VERSION 5.8 ;
BUSBITCHARS "[]" ;
DIVIDERCHAR "/" ;
UNITS
    DATABASE MICRONS 1000 ;
END UNITS

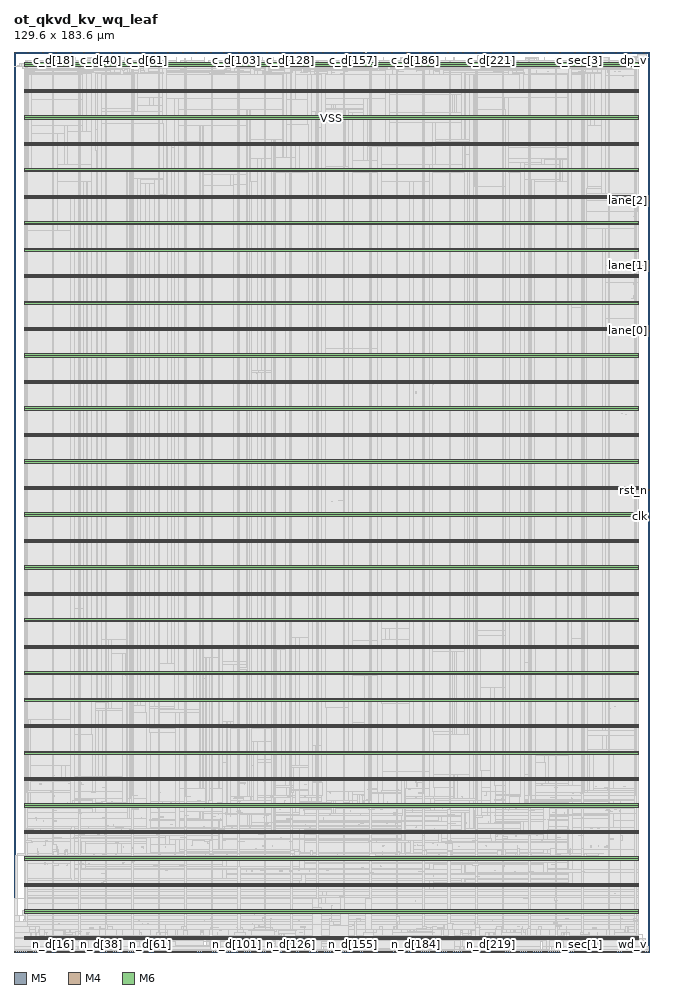
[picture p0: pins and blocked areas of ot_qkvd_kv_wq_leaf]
MACRO ot_qkvd_kv_wq_leaf
  FOREIGN ot_qkvd_kv_wq_leaf 0 0 ;
  CLASS BLOCK ;
  SIZE 129.6 BY 183.6 ;
  PIN c_d[0]
    DIRECTION INPUT ;
    USE SIGNAL ;
    PORT
      LAYER M5 ;
        RECT  0.192 183.516 0.216 183.6 ;
    END
  END c_d[0]
  PIN c_d[100]
    DIRECTION INPUT ;
    USE SIGNAL ;
    PORT
      LAYER M5 ;
        RECT  44.16 183.516 44.184 183.6 ;
    END
  END c_d[100]
  PIN c_d[101]
    DIRECTION INPUT ;
    USE SIGNAL ;
    PORT
      LAYER M5 ;
        RECT  44.592 183.516 44.616 183.6 ;
    END
  END c_d[101]
  PIN c_d[102]
    DIRECTION INPUT ;
    USE SIGNAL ;
    PORT
      LAYER M5 ;
        RECT  45.024 183.516 45.048 183.6 ;
    END
  END c_d[102]
  PIN c_d[103]
    DIRECTION INPUT ;
    USE SIGNAL ;
    PORT
      LAYER M5 ;
        RECT  45.456 183.516 45.48 183.6 ;
    END
  END c_d[103]
  PIN c_d[104]
    DIRECTION INPUT ;
    USE SIGNAL ;
    PORT
      LAYER M5 ;
        RECT  45.888 183.516 45.912 183.6 ;
    END
  END c_d[104]
  PIN c_d[105]
    DIRECTION INPUT ;
    USE SIGNAL ;
    PORT
      LAYER M5 ;
        RECT  46.32 183.516 46.344 183.6 ;
    END
  END c_d[105]
  PIN c_d[106]
    DIRECTION INPUT ;
    USE SIGNAL ;
    PORT
      LAYER M5 ;
        RECT  46.8 183.516 46.824 183.6 ;
    END
  END c_d[106]
  PIN c_d[107]
    DIRECTION INPUT ;
    USE SIGNAL ;
    PORT
      LAYER M5 ;
        RECT  47.232 183.516 47.256 183.6 ;
    END
  END c_d[107]
  PIN c_d[108]
    DIRECTION INPUT ;
    USE SIGNAL ;
    PORT
      LAYER M5 ;
        RECT  47.664 183.516 47.688 183.6 ;
    END
  END c_d[108]
  PIN c_d[109]
    DIRECTION INPUT ;
    USE SIGNAL ;
    PORT
      LAYER M5 ;
        RECT  48.096 183.516 48.12 183.6 ;
    END
  END c_d[109]
  PIN c_d[10]
    DIRECTION INPUT ;
    USE SIGNAL ;
    PORT
      LAYER M5 ;
        RECT  4.608 183.516 4.632 183.6 ;
    END
  END c_d[10]
  PIN c_d[110]
    DIRECTION INPUT ;
    USE SIGNAL ;
    PORT
      LAYER M5 ;
        RECT  48.528 183.516 48.552 183.6 ;
    END
  END c_d[110]
  PIN c_d[111]
    DIRECTION INPUT ;
    USE SIGNAL ;
    PORT
      LAYER M5 ;
        RECT  48.96 183.516 48.984 183.6 ;
    END
  END c_d[111]
  PIN c_d[112]
    DIRECTION INPUT ;
    USE SIGNAL ;
    PORT
      LAYER M5 ;
        RECT  49.392 183.516 49.416 183.6 ;
    END
  END c_d[112]
  PIN c_d[113]
    DIRECTION INPUT ;
    USE SIGNAL ;
    PORT
      LAYER M5 ;
        RECT  49.872 183.516 49.896 183.6 ;
    END
  END c_d[113]
  PIN c_d[114]
    DIRECTION INPUT ;
    USE SIGNAL ;
    PORT
      LAYER M5 ;
        RECT  50.304 183.516 50.328 183.6 ;
    END
  END c_d[114]
  PIN c_d[115]
    DIRECTION INPUT ;
    USE SIGNAL ;
    PORT
      LAYER M5 ;
        RECT  50.736 183.516 50.76 183.6 ;
    END
  END c_d[115]
  PIN c_d[116]
    DIRECTION INPUT ;
    USE SIGNAL ;
    PORT
      LAYER M5 ;
        RECT  51.168 183.516 51.192 183.6 ;
    END
  END c_d[116]
  PIN c_d[117]
    DIRECTION INPUT ;
    USE SIGNAL ;
    PORT
      LAYER M5 ;
        RECT  51.6 183.516 51.624 183.6 ;
    END
  END c_d[117]
  PIN c_d[118]
    DIRECTION INPUT ;
    USE SIGNAL ;
    PORT
      LAYER M5 ;
        RECT  52.032 183.516 52.056 183.6 ;
    END
  END c_d[118]
  PIN c_d[119]
    DIRECTION INPUT ;
    USE SIGNAL ;
    PORT
      LAYER M5 ;
        RECT  52.464 183.516 52.488 183.6 ;
    END
  END c_d[119]
  PIN c_d[11]
    DIRECTION INPUT ;
    USE SIGNAL ;
    PORT
      LAYER M5 ;
        RECT  5.04 183.516 5.064 183.6 ;
    END
  END c_d[11]
  PIN c_d[120]
    DIRECTION INPUT ;
    USE SIGNAL ;
    PORT
      LAYER M5 ;
        RECT  52.944 183.516 52.968 183.6 ;
    END
  END c_d[120]
  PIN c_d[121]
    DIRECTION INPUT ;
    USE SIGNAL ;
    PORT
      LAYER M5 ;
        RECT  53.376 183.516 53.4 183.6 ;
    END
  END c_d[121]
  PIN c_d[122]
    DIRECTION INPUT ;
    USE SIGNAL ;
    PORT
      LAYER M5 ;
        RECT  53.808 183.516 53.832 183.6 ;
    END
  END c_d[122]
  PIN c_d[123]
    DIRECTION INPUT ;
    USE SIGNAL ;
    PORT
      LAYER M5 ;
        RECT  54.24 183.516 54.264 183.6 ;
    END
  END c_d[123]
  PIN c_d[124]
    DIRECTION INPUT ;
    USE SIGNAL ;
    PORT
      LAYER M5 ;
        RECT  54.672 183.516 54.696 183.6 ;
    END
  END c_d[124]
  PIN c_d[125]
    DIRECTION INPUT ;
    USE SIGNAL ;
    PORT
      LAYER M5 ;
        RECT  55.104 183.516 55.128 183.6 ;
    END
  END c_d[125]
  PIN c_d[126]
    DIRECTION INPUT ;
    USE SIGNAL ;
    PORT
      LAYER M5 ;
        RECT  55.584 183.516 55.608 183.6 ;
    END
  END c_d[126]
  PIN c_d[127]
    DIRECTION INPUT ;
    USE SIGNAL ;
    PORT
      LAYER M5 ;
        RECT  56.016 183.516 56.04 183.6 ;
    END
  END c_d[127]
  PIN c_d[128]
    DIRECTION INPUT ;
    USE SIGNAL ;
    PORT
      LAYER M5 ;
        RECT  56.448 183.516 56.472 183.6 ;
    END
  END c_d[128]
  PIN c_d[129]
    DIRECTION INPUT ;
    USE SIGNAL ;
    PORT
      LAYER M5 ;
        RECT  56.88 183.516 56.904 183.6 ;
    END
  END c_d[129]
  PIN c_d[12]
    DIRECTION INPUT ;
    USE SIGNAL ;
    PORT
      LAYER M5 ;
        RECT  5.472 183.516 5.496 183.6 ;
    END
  END c_d[12]
  PIN c_d[130]
    DIRECTION INPUT ;
    USE SIGNAL ;
    PORT
      LAYER M5 ;
        RECT  57.312 183.516 57.336 183.6 ;
    END
  END c_d[130]
  PIN c_d[131]
    DIRECTION INPUT ;
    USE SIGNAL ;
    PORT
      LAYER M5 ;
        RECT  57.744 183.516 57.768 183.6 ;
    END
  END c_d[131]
  PIN c_d[132]
    DIRECTION INPUT ;
    USE SIGNAL ;
    PORT
      LAYER M5 ;
        RECT  58.176 183.516 58.2 183.6 ;
    END
  END c_d[132]
  PIN c_d[133]
    DIRECTION INPUT ;
    USE SIGNAL ;
    PORT
      LAYER M5 ;
        RECT  58.656 183.516 58.68 183.6 ;
    END
  END c_d[133]
  PIN c_d[134]
    DIRECTION INPUT ;
    USE SIGNAL ;
    PORT
      LAYER M5 ;
        RECT  59.088 183.516 59.112 183.6 ;
    END
  END c_d[134]
  PIN c_d[135]
    DIRECTION INPUT ;
    USE SIGNAL ;
    PORT
      LAYER M5 ;
        RECT  59.52 183.516 59.544 183.6 ;
    END
  END c_d[135]
  PIN c_d[136]
    DIRECTION INPUT ;
    USE SIGNAL ;
    PORT
      LAYER M5 ;
        RECT  59.952 183.516 59.976 183.6 ;
    END
  END c_d[136]
  PIN c_d[137]
    DIRECTION INPUT ;
    USE SIGNAL ;
    PORT
      LAYER M5 ;
        RECT  60.384 183.516 60.408 183.6 ;
    END
  END c_d[137]
  PIN c_d[138]
    DIRECTION INPUT ;
    USE SIGNAL ;
    PORT
      LAYER M5 ;
        RECT  60.816 183.516 60.84 183.6 ;
    END
  END c_d[138]
  PIN c_d[139]
    DIRECTION INPUT ;
    USE SIGNAL ;
    PORT
      LAYER M5 ;
        RECT  61.296 183.516 61.32 183.6 ;
    END
  END c_d[139]
  PIN c_d[13]
    DIRECTION INPUT ;
    USE SIGNAL ;
    PORT
      LAYER M5 ;
        RECT  5.904 183.516 5.928 183.6 ;
    END
  END c_d[13]
  PIN c_d[140]
    DIRECTION INPUT ;
    USE SIGNAL ;
    PORT
      LAYER M5 ;
        RECT  61.728 183.516 61.752 183.6 ;
    END
  END c_d[140]
  PIN c_d[141]
    DIRECTION INPUT ;
    USE SIGNAL ;
    PORT
      LAYER M5 ;
        RECT  62.16 183.516 62.184 183.6 ;
    END
  END c_d[141]
  PIN c_d[142]
    DIRECTION INPUT ;
    USE SIGNAL ;
    PORT
      LAYER M5 ;
        RECT  62.592 183.516 62.616 183.6 ;
    END
  END c_d[142]
  PIN c_d[143]
    DIRECTION INPUT ;
    USE SIGNAL ;
    PORT
      LAYER M5 ;
        RECT  63.024 183.516 63.048 183.6 ;
    END
  END c_d[143]
  PIN c_d[144]
    DIRECTION INPUT ;
    USE SIGNAL ;
    PORT
      LAYER M5 ;
        RECT  63.456 183.516 63.48 183.6 ;
    END
  END c_d[144]
  PIN c_d[145]
    DIRECTION INPUT ;
    USE SIGNAL ;
    PORT
      LAYER M5 ;
        RECT  63.888 183.516 63.912 183.6 ;
    END
  END c_d[145]
  PIN c_d[146]
    DIRECTION INPUT ;
    USE SIGNAL ;
    PORT
      LAYER M5 ;
        RECT  64.368 183.516 64.392 183.6 ;
    END
  END c_d[146]
  PIN c_d[147]
    DIRECTION INPUT ;
    USE SIGNAL ;
    PORT
      LAYER M5 ;
        RECT  64.8 183.516 64.824 183.6 ;
    END
  END c_d[147]
  PIN c_d[148]
    DIRECTION INPUT ;
    USE SIGNAL ;
    PORT
      LAYER M5 ;
        RECT  65.232 183.516 65.256 183.6 ;
    END
  END c_d[148]
  PIN c_d[149]
    DIRECTION INPUT ;
    USE SIGNAL ;
    PORT
      LAYER M5 ;
        RECT  65.664 183.516 65.688 183.6 ;
    END
  END c_d[149]
  PIN c_d[14]
    DIRECTION INPUT ;
    USE SIGNAL ;
    PORT
      LAYER M5 ;
        RECT  6.336 183.516 6.36 183.6 ;
    END
  END c_d[14]
  PIN c_d[150]
    DIRECTION INPUT ;
    USE SIGNAL ;
    PORT
      LAYER M5 ;
        RECT  66.096 183.516 66.12 183.6 ;
    END
  END c_d[150]
  PIN c_d[151]
    DIRECTION INPUT ;
    USE SIGNAL ;
    PORT
      LAYER M5 ;
        RECT  66.528 183.516 66.552 183.6 ;
    END
  END c_d[151]
  PIN c_d[152]
    DIRECTION INPUT ;
    USE SIGNAL ;
    PORT
      LAYER M5 ;
        RECT  67.008 183.516 67.032 183.6 ;
    END
  END c_d[152]
  PIN c_d[153]
    DIRECTION INPUT ;
    USE SIGNAL ;
    PORT
      LAYER M5 ;
        RECT  67.44 183.516 67.464 183.6 ;
    END
  END c_d[153]
  PIN c_d[154]
    DIRECTION INPUT ;
    USE SIGNAL ;
    PORT
      LAYER M5 ;
        RECT  67.872 183.516 67.896 183.6 ;
    END
  END c_d[154]
  PIN c_d[155]
    DIRECTION INPUT ;
    USE SIGNAL ;
    PORT
      LAYER M5 ;
        RECT  68.304 183.516 68.328 183.6 ;
    END
  END c_d[155]
  PIN c_d[156]
    DIRECTION INPUT ;
    USE SIGNAL ;
    PORT
      LAYER M5 ;
        RECT  68.736 183.516 68.76 183.6 ;
    END
  END c_d[156]
  PIN c_d[157]
    DIRECTION INPUT ;
    USE SIGNAL ;
    PORT
      LAYER M5 ;
        RECT  69.168 183.516 69.192 183.6 ;
    END
  END c_d[157]
  PIN c_d[158]
    DIRECTION INPUT ;
    USE SIGNAL ;
    PORT
      LAYER M5 ;
        RECT  69.6 183.516 69.624 183.6 ;
    END
  END c_d[158]
  PIN c_d[159]
    DIRECTION INPUT ;
    USE SIGNAL ;
    PORT
      LAYER M5 ;
        RECT  70.08 183.516 70.104 183.6 ;
    END
  END c_d[159]
  PIN c_d[15]
    DIRECTION INPUT ;
    USE SIGNAL ;
    PORT
      LAYER M5 ;
        RECT  6.816 183.516 6.84 183.6 ;
    END
  END c_d[15]
  PIN c_d[160]
    DIRECTION INPUT ;
    USE SIGNAL ;
    PORT
      LAYER M5 ;
        RECT  70.512 183.516 70.536 183.6 ;
    END
  END c_d[160]
  PIN c_d[161]
    DIRECTION INPUT ;
    USE SIGNAL ;
    PORT
      LAYER M5 ;
        RECT  70.944 183.516 70.968 183.6 ;
    END
  END c_d[161]
  PIN c_d[162]
    DIRECTION INPUT ;
    USE SIGNAL ;
    PORT
      LAYER M5 ;
        RECT  71.376 183.516 71.4 183.6 ;
    END
  END c_d[162]
  PIN c_d[163]
    DIRECTION INPUT ;
    USE SIGNAL ;
    PORT
      LAYER M5 ;
        RECT  71.808 183.516 71.832 183.6 ;
    END
  END c_d[163]
  PIN c_d[164]
    DIRECTION INPUT ;
    USE SIGNAL ;
    PORT
      LAYER M5 ;
        RECT  72.24 183.516 72.264 183.6 ;
    END
  END c_d[164]
  PIN c_d[165]
    DIRECTION INPUT ;
    USE SIGNAL ;
    PORT
      LAYER M5 ;
        RECT  72.72 183.516 72.744 183.6 ;
    END
  END c_d[165]
  PIN c_d[166]
    DIRECTION INPUT ;
    USE SIGNAL ;
    PORT
      LAYER M5 ;
        RECT  73.152 183.516 73.176 183.6 ;
    END
  END c_d[166]
  PIN c_d[167]
    DIRECTION INPUT ;
    USE SIGNAL ;
    PORT
      LAYER M5 ;
        RECT  73.584 183.516 73.608 183.6 ;
    END
  END c_d[167]
  PIN c_d[168]
    DIRECTION INPUT ;
    USE SIGNAL ;
    PORT
      LAYER M5 ;
        RECT  74.016 183.516 74.04 183.6 ;
    END
  END c_d[168]
  PIN c_d[169]
    DIRECTION INPUT ;
    USE SIGNAL ;
    PORT
      LAYER M5 ;
        RECT  74.448 183.516 74.472 183.6 ;
    END
  END c_d[169]
  PIN c_d[16]
    DIRECTION INPUT ;
    USE SIGNAL ;
    PORT
      LAYER M5 ;
        RECT  7.248 183.516 7.272 183.6 ;
    END
  END c_d[16]
  PIN c_d[170]
    DIRECTION INPUT ;
    USE SIGNAL ;
    PORT
      LAYER M5 ;
        RECT  74.88 183.516 74.904 183.6 ;
    END
  END c_d[170]
  PIN c_d[171]
    DIRECTION INPUT ;
    USE SIGNAL ;
    PORT
      LAYER M5 ;
        RECT  75.312 183.516 75.336 183.6 ;
    END
  END c_d[171]
  PIN c_d[172]
    DIRECTION INPUT ;
    USE SIGNAL ;
    PORT
      LAYER M5 ;
        RECT  75.792 183.516 75.816 183.6 ;
    END
  END c_d[172]
  PIN c_d[173]
    DIRECTION INPUT ;
    USE SIGNAL ;
    PORT
      LAYER M5 ;
        RECT  76.224 183.516 76.248 183.6 ;
    END
  END c_d[173]
  PIN c_d[174]
    DIRECTION INPUT ;
    USE SIGNAL ;
    PORT
      LAYER M5 ;
        RECT  76.656 183.516 76.68 183.6 ;
    END
  END c_d[174]
  PIN c_d[175]
    DIRECTION INPUT ;
    USE SIGNAL ;
    PORT
      LAYER M5 ;
        RECT  77.088 183.516 77.112 183.6 ;
    END
  END c_d[175]
  PIN c_d[176]
    DIRECTION INPUT ;
    USE SIGNAL ;
    PORT
      LAYER M5 ;
        RECT  77.52 183.516 77.544 183.6 ;
    END
  END c_d[176]
  PIN c_d[177]
    DIRECTION INPUT ;
    USE SIGNAL ;
    PORT
      LAYER M5 ;
        RECT  77.952 183.516 77.976 183.6 ;
    END
  END c_d[177]
  PIN c_d[178]
    DIRECTION INPUT ;
    USE SIGNAL ;
    PORT
      LAYER M5 ;
        RECT  78.384 183.516 78.408 183.6 ;
    END
  END c_d[178]
  PIN c_d[179]
    DIRECTION INPUT ;
    USE SIGNAL ;
    PORT
      LAYER M5 ;
        RECT  78.864 183.516 78.888 183.6 ;
    END
  END c_d[179]
  PIN c_d[17]
    DIRECTION INPUT ;
    USE SIGNAL ;
    PORT
      LAYER M5 ;
        RECT  7.68 183.516 7.704 183.6 ;
    END
  END c_d[17]
  PIN c_d[180]
    DIRECTION INPUT ;
    USE SIGNAL ;
    PORT
      LAYER M5 ;
        RECT  79.296 183.516 79.32 183.6 ;
    END
  END c_d[180]
  PIN c_d[181]
    DIRECTION INPUT ;
    USE SIGNAL ;
    PORT
      LAYER M5 ;
        RECT  79.728 183.516 79.752 183.6 ;
    END
  END c_d[181]
  PIN c_d[182]
    DIRECTION INPUT ;
    USE SIGNAL ;
    PORT
      LAYER M5 ;
        RECT  80.16 183.516 80.184 183.6 ;
    END
  END c_d[182]
  PIN c_d[183]
    DIRECTION INPUT ;
    USE SIGNAL ;
    PORT
      LAYER M5 ;
        RECT  80.592 183.516 80.616 183.6 ;
    END
  END c_d[183]
  PIN c_d[184]
    DIRECTION INPUT ;
    USE SIGNAL ;
    PORT
      LAYER M5 ;
        RECT  81.024 183.516 81.048 183.6 ;
    END
  END c_d[184]
  PIN c_d[185]
    DIRECTION INPUT ;
    USE SIGNAL ;
    PORT
      LAYER M5 ;
        RECT  81.504 183.516 81.528 183.6 ;
    END
  END c_d[185]
  PIN c_d[186]
    DIRECTION INPUT ;
    USE SIGNAL ;
    PORT
      LAYER M5 ;
        RECT  81.936 183.516 81.96 183.6 ;
    END
  END c_d[186]
  PIN c_d[187]
    DIRECTION INPUT ;
    USE SIGNAL ;
    PORT
      LAYER M5 ;
        RECT  82.368 183.516 82.392 183.6 ;
    END
  END c_d[187]
  PIN c_d[188]
    DIRECTION INPUT ;
    USE SIGNAL ;
    PORT
      LAYER M5 ;
        RECT  82.8 183.516 82.824 183.6 ;
    END
  END c_d[188]
  PIN c_d[189]
    DIRECTION INPUT ;
    USE SIGNAL ;
    PORT
      LAYER M5 ;
        RECT  83.232 183.516 83.256 183.6 ;
    END
  END c_d[189]
  PIN c_d[18]
    DIRECTION INPUT ;
    USE SIGNAL ;
    PORT
      LAYER M5 ;
        RECT  8.112 183.516 8.136 183.6 ;
    END
  END c_d[18]
  PIN c_d[190]
    DIRECTION INPUT ;
    USE SIGNAL ;
    PORT
      LAYER M5 ;
        RECT  83.664 183.516 83.688 183.6 ;
    END
  END c_d[190]
  PIN c_d[191]
    DIRECTION INPUT ;
    USE SIGNAL ;
    PORT
      LAYER M5 ;
        RECT  84.096 183.516 84.12 183.6 ;
    END
  END c_d[191]
  PIN c_d[192]
    DIRECTION INPUT ;
    USE SIGNAL ;
    PORT
      LAYER M5 ;
        RECT  84.576 183.516 84.6 183.6 ;
    END
  END c_d[192]
  PIN c_d[193]
    DIRECTION INPUT ;
    USE SIGNAL ;
    PORT
      LAYER M5 ;
        RECT  85.008 183.516 85.032 183.6 ;
    END
  END c_d[193]
  PIN c_d[194]
    DIRECTION INPUT ;
    USE SIGNAL ;
    PORT
      LAYER M5 ;
        RECT  85.44 183.516 85.464 183.6 ;
    END
  END c_d[194]
  PIN c_d[195]
    DIRECTION INPUT ;
    USE SIGNAL ;
    PORT
      LAYER M5 ;
        RECT  85.872 183.516 85.896 183.6 ;
    END
  END c_d[195]
  PIN c_d[196]
    DIRECTION INPUT ;
    USE SIGNAL ;
    PORT
      LAYER M5 ;
        RECT  86.304 183.516 86.328 183.6 ;
    END
  END c_d[196]
  PIN c_d[197]
    DIRECTION INPUT ;
    USE SIGNAL ;
    PORT
      LAYER M5 ;
        RECT  86.736 183.516 86.76 183.6 ;
    END
  END c_d[197]
  PIN c_d[198]
    DIRECTION INPUT ;
    USE SIGNAL ;
    PORT
      LAYER M5 ;
        RECT  87.216 183.516 87.24 183.6 ;
    END
  END c_d[198]
  PIN c_d[199]
    DIRECTION INPUT ;
    USE SIGNAL ;
    PORT
      LAYER M5 ;
        RECT  87.648 183.516 87.672 183.6 ;
    END
  END c_d[199]
  PIN c_d[19]
    DIRECTION INPUT ;
    USE SIGNAL ;
    PORT
      LAYER M5 ;
        RECT  8.544 183.516 8.568 183.6 ;
    END
  END c_d[19]
  PIN c_d[1]
    DIRECTION INPUT ;
    USE SIGNAL ;
    PORT
      LAYER M5 ;
        RECT  0.624 183.516 0.648 183.6 ;
    END
  END c_d[1]
  PIN c_d[200]
    DIRECTION INPUT ;
    USE SIGNAL ;
    PORT
      LAYER M5 ;
        RECT  88.08 183.516 88.104 183.6 ;
    END
  END c_d[200]
  PIN c_d[201]
    DIRECTION INPUT ;
    USE SIGNAL ;
    PORT
      LAYER M5 ;
        RECT  88.512 183.516 88.536 183.6 ;
    END
  END c_d[201]
  PIN c_d[202]
    DIRECTION INPUT ;
    USE SIGNAL ;
    PORT
      LAYER M5 ;
        RECT  88.944 183.516 88.968 183.6 ;
    END
  END c_d[202]
  PIN c_d[203]
    DIRECTION INPUT ;
    USE SIGNAL ;
    PORT
      LAYER M5 ;
        RECT  89.376 183.516 89.4 183.6 ;
    END
  END c_d[203]
  PIN c_d[204]
    DIRECTION INPUT ;
    USE SIGNAL ;
    PORT
      LAYER M5 ;
        RECT  89.808 183.516 89.832 183.6 ;
    END
  END c_d[204]
  PIN c_d[205]
    DIRECTION INPUT ;
    USE SIGNAL ;
    PORT
      LAYER M5 ;
        RECT  90.288 183.516 90.312 183.6 ;
    END
  END c_d[205]
  PIN c_d[206]
    DIRECTION INPUT ;
    USE SIGNAL ;
    PORT
      LAYER M5 ;
        RECT  90.72 183.516 90.744 183.6 ;
    END
  END c_d[206]
  PIN c_d[207]
    DIRECTION INPUT ;
    USE SIGNAL ;
    PORT
      LAYER M5 ;
        RECT  91.152 183.516 91.176 183.6 ;
    END
  END c_d[207]
  PIN c_d[208]
    DIRECTION INPUT ;
    USE SIGNAL ;
    PORT
      LAYER M5 ;
        RECT  91.584 183.516 91.608 183.6 ;
    END
  END c_d[208]
  PIN c_d[209]
    DIRECTION INPUT ;
    USE SIGNAL ;
    PORT
      LAYER M5 ;
        RECT  92.016 183.516 92.04 183.6 ;
    END
  END c_d[209]
  PIN c_d[20]
    DIRECTION INPUT ;
    USE SIGNAL ;
    PORT
      LAYER M5 ;
        RECT  8.976 183.516 9 183.6 ;
    END
  END c_d[20]
  PIN c_d[210]
    DIRECTION INPUT ;
    USE SIGNAL ;
    PORT
      LAYER M5 ;
        RECT  92.448 183.516 92.472 183.6 ;
    END
  END c_d[210]
  PIN c_d[211]
    DIRECTION INPUT ;
    USE SIGNAL ;
    PORT
      LAYER M5 ;
        RECT  92.928 183.516 92.952 183.6 ;
    END
  END c_d[211]
  PIN c_d[212]
    DIRECTION INPUT ;
    USE SIGNAL ;
    PORT
      LAYER M5 ;
        RECT  93.36 183.516 93.384 183.6 ;
    END
  END c_d[212]
  PIN c_d[213]
    DIRECTION INPUT ;
    USE SIGNAL ;
    PORT
      LAYER M5 ;
        RECT  93.792 183.516 93.816 183.6 ;
    END
  END c_d[213]
  PIN c_d[214]
    DIRECTION INPUT ;
    USE SIGNAL ;
    PORT
      LAYER M5 ;
        RECT  94.224 183.516 94.248 183.6 ;
    END
  END c_d[214]
  PIN c_d[215]
    DIRECTION INPUT ;
    USE SIGNAL ;
    PORT
      LAYER M5 ;
        RECT  94.656 183.516 94.68 183.6 ;
    END
  END c_d[215]
  PIN c_d[216]
    DIRECTION INPUT ;
    USE SIGNAL ;
    PORT
      LAYER M5 ;
        RECT  95.088 183.516 95.112 183.6 ;
    END
  END c_d[216]
  PIN c_d[217]
    DIRECTION INPUT ;
    USE SIGNAL ;
    PORT
      LAYER M5 ;
        RECT  95.52 183.516 95.544 183.6 ;
    END
  END c_d[217]
  PIN c_d[218]
    DIRECTION INPUT ;
    USE SIGNAL ;
    PORT
      LAYER M5 ;
        RECT  96 183.516 96.024 183.6 ;
    END
  END c_d[218]
  PIN c_d[219]
    DIRECTION INPUT ;
    USE SIGNAL ;
    PORT
      LAYER M5 ;
        RECT  96.432 183.516 96.456 183.6 ;
    END
  END c_d[219]
  PIN c_d[21]
    DIRECTION INPUT ;
    USE SIGNAL ;
    PORT
      LAYER M5 ;
        RECT  9.456 183.516 9.48 183.6 ;
    END
  END c_d[21]
  PIN c_d[220]
    DIRECTION INPUT ;
    USE SIGNAL ;
    PORT
      LAYER M5 ;
        RECT  96.864 183.516 96.888 183.6 ;
    END
  END c_d[220]
  PIN c_d[221]
    DIRECTION INPUT ;
    USE SIGNAL ;
    PORT
      LAYER M5 ;
        RECT  97.296 183.516 97.32 183.6 ;
    END
  END c_d[221]
  PIN c_d[222]
    DIRECTION INPUT ;
    USE SIGNAL ;
    PORT
      LAYER M5 ;
        RECT  97.728 183.516 97.752 183.6 ;
    END
  END c_d[222]
  PIN c_d[223]
    DIRECTION INPUT ;
    USE SIGNAL ;
    PORT
      LAYER M5 ;
        RECT  98.16 183.516 98.184 183.6 ;
    END
  END c_d[223]
  PIN c_d[224]
    DIRECTION INPUT ;
    USE SIGNAL ;
    PORT
      LAYER M5 ;
        RECT  98.64 183.516 98.664 183.6 ;
    END
  END c_d[224]
  PIN c_d[225]
    DIRECTION INPUT ;
    USE SIGNAL ;
    PORT
      LAYER M5 ;
        RECT  99.072 183.516 99.096 183.6 ;
    END
  END c_d[225]
  PIN c_d[226]
    DIRECTION INPUT ;
    USE SIGNAL ;
    PORT
      LAYER M5 ;
        RECT  99.504 183.516 99.528 183.6 ;
    END
  END c_d[226]
  PIN c_d[227]
    DIRECTION INPUT ;
    USE SIGNAL ;
    PORT
      LAYER M5 ;
        RECT  99.936 183.516 99.96 183.6 ;
    END
  END c_d[227]
  PIN c_d[228]
    DIRECTION INPUT ;
    USE SIGNAL ;
    PORT
      LAYER M5 ;
        RECT  100.368 183.516 100.392 183.6 ;
    END
  END c_d[228]
  PIN c_d[229]
    DIRECTION INPUT ;
    USE SIGNAL ;
    PORT
      LAYER M5 ;
        RECT  100.8 183.516 100.824 183.6 ;
    END
  END c_d[229]
  PIN c_d[22]
    DIRECTION INPUT ;
    USE SIGNAL ;
    PORT
      LAYER M5 ;
        RECT  9.888 183.516 9.912 183.6 ;
    END
  END c_d[22]
  PIN c_d[230]
    DIRECTION INPUT ;
    USE SIGNAL ;
    PORT
      LAYER M5 ;
        RECT  101.232 183.516 101.256 183.6 ;
    END
  END c_d[230]
  PIN c_d[231]
    DIRECTION INPUT ;
    USE SIGNAL ;
    PORT
      LAYER M5 ;
        RECT  101.712 183.516 101.736 183.6 ;
    END
  END c_d[231]
  PIN c_d[232]
    DIRECTION INPUT ;
    USE SIGNAL ;
    PORT
      LAYER M5 ;
        RECT  102.144 183.516 102.168 183.6 ;
    END
  END c_d[232]
  PIN c_d[233]
    DIRECTION INPUT ;
    USE SIGNAL ;
    PORT
      LAYER M5 ;
        RECT  102.576 183.516 102.6 183.6 ;
    END
  END c_d[233]
  PIN c_d[234]
    DIRECTION INPUT ;
    USE SIGNAL ;
    PORT
      LAYER M5 ;
        RECT  103.008 183.516 103.032 183.6 ;
    END
  END c_d[234]
  PIN c_d[235]
    DIRECTION INPUT ;
    USE SIGNAL ;
    PORT
      LAYER M5 ;
        RECT  103.44 183.516 103.464 183.6 ;
    END
  END c_d[235]
  PIN c_d[236]
    DIRECTION INPUT ;
    USE SIGNAL ;
    PORT
      LAYER M5 ;
        RECT  103.872 183.516 103.896 183.6 ;
    END
  END c_d[236]
  PIN c_d[237]
    DIRECTION INPUT ;
    USE SIGNAL ;
    PORT
      LAYER M5 ;
        RECT  104.304 183.516 104.328 183.6 ;
    END
  END c_d[237]
  PIN c_d[238]
    DIRECTION INPUT ;
    USE SIGNAL ;
    PORT
      LAYER M5 ;
        RECT  104.784 183.516 104.808 183.6 ;
    END
  END c_d[238]
  PIN c_d[239]
    DIRECTION INPUT ;
    USE SIGNAL ;
    PORT
      LAYER M5 ;
        RECT  105.216 183.516 105.24 183.6 ;
    END
  END c_d[239]
  PIN c_d[23]
    DIRECTION INPUT ;
    USE SIGNAL ;
    PORT
      LAYER M5 ;
        RECT  10.32 183.516 10.344 183.6 ;
    END
  END c_d[23]
  PIN c_d[240]
    DIRECTION INPUT ;
    USE SIGNAL ;
    PORT
      LAYER M5 ;
        RECT  105.648 183.516 105.672 183.6 ;
    END
  END c_d[240]
  PIN c_d[241]
    DIRECTION INPUT ;
    USE SIGNAL ;
    PORT
      LAYER M5 ;
        RECT  106.08 183.516 106.104 183.6 ;
    END
  END c_d[241]
  PIN c_d[242]
    DIRECTION INPUT ;
    USE SIGNAL ;
    PORT
      LAYER M5 ;
        RECT  106.512 183.516 106.536 183.6 ;
    END
  END c_d[242]
  PIN c_d[243]
    DIRECTION INPUT ;
    USE SIGNAL ;
    PORT
      LAYER M5 ;
        RECT  106.944 183.516 106.968 183.6 ;
    END
  END c_d[243]
  PIN c_d[244]
    DIRECTION INPUT ;
    USE SIGNAL ;
    PORT
      LAYER M5 ;
        RECT  107.424 183.516 107.448 183.6 ;
    END
  END c_d[244]
  PIN c_d[245]
    DIRECTION INPUT ;
    USE SIGNAL ;
    PORT
      LAYER M5 ;
        RECT  107.856 183.516 107.88 183.6 ;
    END
  END c_d[245]
  PIN c_d[246]
    DIRECTION INPUT ;
    USE SIGNAL ;
    PORT
      LAYER M5 ;
        RECT  108.288 183.516 108.312 183.6 ;
    END
  END c_d[246]
  PIN c_d[247]
    DIRECTION INPUT ;
    USE SIGNAL ;
    PORT
      LAYER M5 ;
        RECT  108.72 183.516 108.744 183.6 ;
    END
  END c_d[247]
  PIN c_d[248]
    DIRECTION INPUT ;
    USE SIGNAL ;
    PORT
      LAYER M5 ;
        RECT  109.152 183.516 109.176 183.6 ;
    END
  END c_d[248]
  PIN c_d[249]
    DIRECTION INPUT ;
    USE SIGNAL ;
    PORT
      LAYER M5 ;
        RECT  109.584 183.516 109.608 183.6 ;
    END
  END c_d[249]
  PIN c_d[24]
    DIRECTION INPUT ;
    USE SIGNAL ;
    PORT
      LAYER M5 ;
        RECT  10.752 183.516 10.776 183.6 ;
    END
  END c_d[24]
  PIN c_d[250]
    DIRECTION INPUT ;
    USE SIGNAL ;
    PORT
      LAYER M5 ;
        RECT  110.016 183.516 110.04 183.6 ;
    END
  END c_d[250]
  PIN c_d[251]
    DIRECTION INPUT ;
    USE SIGNAL ;
    PORT
      LAYER M5 ;
        RECT  110.496 183.516 110.52 183.6 ;
    END
  END c_d[251]
  PIN c_d[252]
    DIRECTION INPUT ;
    USE SIGNAL ;
    PORT
      LAYER M5 ;
        RECT  110.928 183.516 110.952 183.6 ;
    END
  END c_d[252]
  PIN c_d[253]
    DIRECTION INPUT ;
    USE SIGNAL ;
    PORT
      LAYER M5 ;
        RECT  111.36 183.516 111.384 183.6 ;
    END
  END c_d[253]
  PIN c_d[254]
    DIRECTION INPUT ;
    USE SIGNAL ;
    PORT
      LAYER M5 ;
        RECT  111.792 183.516 111.816 183.6 ;
    END
  END c_d[254]
  PIN c_d[255]
    DIRECTION INPUT ;
    USE SIGNAL ;
    PORT
      LAYER M5 ;
        RECT  112.224 183.516 112.248 183.6 ;
    END
  END c_d[255]
  PIN c_d[25]
    DIRECTION INPUT ;
    USE SIGNAL ;
    PORT
      LAYER M5 ;
        RECT  11.184 183.516 11.208 183.6 ;
    END
  END c_d[25]
  PIN c_d[26]
    DIRECTION INPUT ;
    USE SIGNAL ;
    PORT
      LAYER M5 ;
        RECT  11.616 183.516 11.64 183.6 ;
    END
  END c_d[26]
  PIN c_d[27]
    DIRECTION INPUT ;
    USE SIGNAL ;
    PORT
      LAYER M5 ;
        RECT  12.048 183.516 12.072 183.6 ;
    END
  END c_d[27]
  PIN c_d[28]
    DIRECTION INPUT ;
    USE SIGNAL ;
    PORT
      LAYER M5 ;
        RECT  12.528 183.516 12.552 183.6 ;
    END
  END c_d[28]
  PIN c_d[29]
    DIRECTION INPUT ;
    USE SIGNAL ;
    PORT
      LAYER M5 ;
        RECT  12.96 183.516 12.984 183.6 ;
    END
  END c_d[29]
  PIN c_d[2]
    DIRECTION INPUT ;
    USE SIGNAL ;
    PORT
      LAYER M5 ;
        RECT  1.104 183.516 1.128 183.6 ;
    END
  END c_d[2]
  PIN c_d[30]
    DIRECTION INPUT ;
    USE SIGNAL ;
    PORT
      LAYER M5 ;
        RECT  13.392 183.516 13.416 183.6 ;
    END
  END c_d[30]
  PIN c_d[31]
    DIRECTION INPUT ;
    USE SIGNAL ;
    PORT
      LAYER M5 ;
        RECT  13.824 183.516 13.848 183.6 ;
    END
  END c_d[31]
  PIN c_d[32]
    DIRECTION INPUT ;
    USE SIGNAL ;
    PORT
      LAYER M5 ;
        RECT  14.256 183.516 14.28 183.6 ;
    END
  END c_d[32]
  PIN c_d[33]
    DIRECTION INPUT ;
    USE SIGNAL ;
    PORT
      LAYER M5 ;
        RECT  14.688 183.516 14.712 183.6 ;
    END
  END c_d[33]
  PIN c_d[34]
    DIRECTION INPUT ;
    USE SIGNAL ;
    PORT
      LAYER M5 ;
        RECT  15.168 183.516 15.192 183.6 ;
    END
  END c_d[34]
  PIN c_d[35]
    DIRECTION INPUT ;
    USE SIGNAL ;
    PORT
      LAYER M5 ;
        RECT  15.6 183.516 15.624 183.6 ;
    END
  END c_d[35]
  PIN c_d[36]
    DIRECTION INPUT ;
    USE SIGNAL ;
    PORT
      LAYER M5 ;
        RECT  16.032 183.516 16.056 183.6 ;
    END
  END c_d[36]
  PIN c_d[37]
    DIRECTION INPUT ;
    USE SIGNAL ;
    PORT
      LAYER M5 ;
        RECT  16.464 183.516 16.488 183.6 ;
    END
  END c_d[37]
  PIN c_d[38]
    DIRECTION INPUT ;
    USE SIGNAL ;
    PORT
      LAYER M5 ;
        RECT  16.896 183.516 16.92 183.6 ;
    END
  END c_d[38]
  PIN c_d[39]
    DIRECTION INPUT ;
    USE SIGNAL ;
    PORT
      LAYER M5 ;
        RECT  17.328 183.516 17.352 183.6 ;
    END
  END c_d[39]
  PIN c_d[3]
    DIRECTION INPUT ;
    USE SIGNAL ;
    PORT
      LAYER M5 ;
        RECT  1.536 183.516 1.56 183.6 ;
    END
  END c_d[3]
  PIN c_d[40]
    DIRECTION INPUT ;
    USE SIGNAL ;
    PORT
      LAYER M5 ;
        RECT  17.76 183.516 17.784 183.6 ;
    END
  END c_d[40]
  PIN c_d[41]
    DIRECTION INPUT ;
    USE SIGNAL ;
    PORT
      LAYER M5 ;
        RECT  18.24 183.516 18.264 183.6 ;
    END
  END c_d[41]
  PIN c_d[42]
    DIRECTION INPUT ;
    USE SIGNAL ;
    PORT
      LAYER M5 ;
        RECT  18.672 183.516 18.696 183.6 ;
    END
  END c_d[42]
  PIN c_d[43]
    DIRECTION INPUT ;
    USE SIGNAL ;
    PORT
      LAYER M5 ;
        RECT  19.104 183.516 19.128 183.6 ;
    END
  END c_d[43]
  PIN c_d[44]
    DIRECTION INPUT ;
    USE SIGNAL ;
    PORT
      LAYER M5 ;
        RECT  19.536 183.516 19.56 183.6 ;
    END
  END c_d[44]
  PIN c_d[45]
    DIRECTION INPUT ;
    USE SIGNAL ;
    PORT
      LAYER M5 ;
        RECT  19.968 183.516 19.992 183.6 ;
    END
  END c_d[45]
  PIN c_d[46]
    DIRECTION INPUT ;
    USE SIGNAL ;
    PORT
      LAYER M5 ;
        RECT  20.4 183.516 20.424 183.6 ;
    END
  END c_d[46]
  PIN c_d[47]
    DIRECTION INPUT ;
    USE SIGNAL ;
    PORT
      LAYER M5 ;
        RECT  20.88 183.516 20.904 183.6 ;
    END
  END c_d[47]
  PIN c_d[48]
    DIRECTION INPUT ;
    USE SIGNAL ;
    PORT
      LAYER M5 ;
        RECT  21.312 183.516 21.336 183.6 ;
    END
  END c_d[48]
  PIN c_d[49]
    DIRECTION INPUT ;
    USE SIGNAL ;
    PORT
      LAYER M5 ;
        RECT  21.744 183.516 21.768 183.6 ;
    END
  END c_d[49]
  PIN c_d[4]
    DIRECTION INPUT ;
    USE SIGNAL ;
    PORT
      LAYER M5 ;
        RECT  1.968 183.516 1.992 183.6 ;
    END
  END c_d[4]
  PIN c_d[50]
    DIRECTION INPUT ;
    USE SIGNAL ;
    PORT
      LAYER M5 ;
        RECT  22.176 183.516 22.2 183.6 ;
    END
  END c_d[50]
  PIN c_d[51]
    DIRECTION INPUT ;
    USE SIGNAL ;
    PORT
      LAYER M5 ;
        RECT  22.608 183.516 22.632 183.6 ;
    END
  END c_d[51]
  PIN c_d[52]
    DIRECTION INPUT ;
    USE SIGNAL ;
    PORT
      LAYER M5 ;
        RECT  23.04 183.516 23.064 183.6 ;
    END
  END c_d[52]
  PIN c_d[53]
    DIRECTION INPUT ;
    USE SIGNAL ;
    PORT
      LAYER M5 ;
        RECT  23.472 183.516 23.496 183.6 ;
    END
  END c_d[53]
  PIN c_d[54]
    DIRECTION INPUT ;
    USE SIGNAL ;
    PORT
      LAYER M5 ;
        RECT  23.952 183.516 23.976 183.6 ;
    END
  END c_d[54]
  PIN c_d[55]
    DIRECTION INPUT ;
    USE SIGNAL ;
    PORT
      LAYER M5 ;
        RECT  24.384 183.516 24.408 183.6 ;
    END
  END c_d[55]
  PIN c_d[56]
    DIRECTION INPUT ;
    USE SIGNAL ;
    PORT
      LAYER M5 ;
        RECT  24.816 183.516 24.84 183.6 ;
    END
  END c_d[56]
  PIN c_d[57]
    DIRECTION INPUT ;
    USE SIGNAL ;
    PORT
      LAYER M5 ;
        RECT  25.248 183.516 25.272 183.6 ;
    END
  END c_d[57]
  PIN c_d[58]
    DIRECTION INPUT ;
    USE SIGNAL ;
    PORT
      LAYER M5 ;
        RECT  25.68 183.516 25.704 183.6 ;
    END
  END c_d[58]
  PIN c_d[59]
    DIRECTION INPUT ;
    USE SIGNAL ;
    PORT
      LAYER M5 ;
        RECT  26.112 183.516 26.136 183.6 ;
    END
  END c_d[59]
  PIN c_d[5]
    DIRECTION INPUT ;
    USE SIGNAL ;
    PORT
      LAYER M5 ;
        RECT  2.4 183.516 2.424 183.6 ;
    END
  END c_d[5]
  PIN c_d[60]
    DIRECTION INPUT ;
    USE SIGNAL ;
    PORT
      LAYER M5 ;
        RECT  26.544 183.516 26.568 183.6 ;
    END
  END c_d[60]
  PIN c_d[61]
    DIRECTION INPUT ;
    USE SIGNAL ;
    PORT
      LAYER M5 ;
        RECT  27.024 183.516 27.048 183.6 ;
    END
  END c_d[61]
  PIN c_d[62]
    DIRECTION INPUT ;
    USE SIGNAL ;
    PORT
      LAYER M5 ;
        RECT  27.456 183.516 27.48 183.6 ;
    END
  END c_d[62]
  PIN c_d[63]
    DIRECTION INPUT ;
    USE SIGNAL ;
    PORT
      LAYER M5 ;
        RECT  27.888 183.516 27.912 183.6 ;
    END
  END c_d[63]
  PIN c_d[64]
    DIRECTION INPUT ;
    USE SIGNAL ;
    PORT
      LAYER M5 ;
        RECT  28.32 183.516 28.344 183.6 ;
    END
  END c_d[64]
  PIN c_d[65]
    DIRECTION INPUT ;
    USE SIGNAL ;
    PORT
      LAYER M5 ;
        RECT  28.752 183.516 28.776 183.6 ;
    END
  END c_d[65]
  PIN c_d[66]
    DIRECTION INPUT ;
    USE SIGNAL ;
    PORT
      LAYER M5 ;
        RECT  29.184 183.516 29.208 183.6 ;
    END
  END c_d[66]
  PIN c_d[67]
    DIRECTION INPUT ;
    USE SIGNAL ;
    PORT
      LAYER M5 ;
        RECT  29.664 183.516 29.688 183.6 ;
    END
  END c_d[67]
  PIN c_d[68]
    DIRECTION INPUT ;
    USE SIGNAL ;
    PORT
      LAYER M5 ;
        RECT  30.096 183.516 30.12 183.6 ;
    END
  END c_d[68]
  PIN c_d[69]
    DIRECTION INPUT ;
    USE SIGNAL ;
    PORT
      LAYER M5 ;
        RECT  30.528 183.516 30.552 183.6 ;
    END
  END c_d[69]
  PIN c_d[6]
    DIRECTION INPUT ;
    USE SIGNAL ;
    PORT
      LAYER M5 ;
        RECT  2.832 183.516 2.856 183.6 ;
    END
  END c_d[6]
  PIN c_d[70]
    DIRECTION INPUT ;
    USE SIGNAL ;
    PORT
      LAYER M5 ;
        RECT  30.96 183.516 30.984 183.6 ;
    END
  END c_d[70]
  PIN c_d[71]
    DIRECTION INPUT ;
    USE SIGNAL ;
    PORT
      LAYER M5 ;
        RECT  31.392 183.516 31.416 183.6 ;
    END
  END c_d[71]
  PIN c_d[72]
    DIRECTION INPUT ;
    USE SIGNAL ;
    PORT
      LAYER M5 ;
        RECT  31.824 183.516 31.848 183.6 ;
    END
  END c_d[72]
  PIN c_d[73]
    DIRECTION INPUT ;
    USE SIGNAL ;
    PORT
      LAYER M5 ;
        RECT  32.256 183.516 32.28 183.6 ;
    END
  END c_d[73]
  PIN c_d[74]
    DIRECTION INPUT ;
    USE SIGNAL ;
    PORT
      LAYER M5 ;
        RECT  32.736 183.516 32.76 183.6 ;
    END
  END c_d[74]
  PIN c_d[75]
    DIRECTION INPUT ;
    USE SIGNAL ;
    PORT
      LAYER M5 ;
        RECT  33.168 183.516 33.192 183.6 ;
    END
  END c_d[75]
  PIN c_d[76]
    DIRECTION INPUT ;
    USE SIGNAL ;
    PORT
      LAYER M5 ;
        RECT  33.6 183.516 33.624 183.6 ;
    END
  END c_d[76]
  PIN c_d[77]
    DIRECTION INPUT ;
    USE SIGNAL ;
    PORT
      LAYER M5 ;
        RECT  34.032 183.516 34.056 183.6 ;
    END
  END c_d[77]
  PIN c_d[78]
    DIRECTION INPUT ;
    USE SIGNAL ;
    PORT
      LAYER M5 ;
        RECT  34.464 183.516 34.488 183.6 ;
    END
  END c_d[78]
  PIN c_d[79]
    DIRECTION INPUT ;
    USE SIGNAL ;
    PORT
      LAYER M5 ;
        RECT  34.896 183.516 34.92 183.6 ;
    END
  END c_d[79]
  PIN c_d[7]
    DIRECTION INPUT ;
    USE SIGNAL ;
    PORT
      LAYER M5 ;
        RECT  3.264 183.516 3.288 183.6 ;
    END
  END c_d[7]
  PIN c_d[80]
    DIRECTION INPUT ;
    USE SIGNAL ;
    PORT
      LAYER M5 ;
        RECT  35.376 183.516 35.4 183.6 ;
    END
  END c_d[80]
  PIN c_d[81]
    DIRECTION INPUT ;
    USE SIGNAL ;
    PORT
      LAYER M5 ;
        RECT  35.808 183.516 35.832 183.6 ;
    END
  END c_d[81]
  PIN c_d[82]
    DIRECTION INPUT ;
    USE SIGNAL ;
    PORT
      LAYER M5 ;
        RECT  36.24 183.516 36.264 183.6 ;
    END
  END c_d[82]
  PIN c_d[83]
    DIRECTION INPUT ;
    USE SIGNAL ;
    PORT
      LAYER M5 ;
        RECT  36.672 183.516 36.696 183.6 ;
    END
  END c_d[83]
  PIN c_d[84]
    DIRECTION INPUT ;
    USE SIGNAL ;
    PORT
      LAYER M5 ;
        RECT  37.104 183.516 37.128 183.6 ;
    END
  END c_d[84]
  PIN c_d[85]
    DIRECTION INPUT ;
    USE SIGNAL ;
    PORT
      LAYER M5 ;
        RECT  37.536 183.516 37.56 183.6 ;
    END
  END c_d[85]
  PIN c_d[86]
    DIRECTION INPUT ;
    USE SIGNAL ;
    PORT
      LAYER M5 ;
        RECT  37.968 183.516 37.992 183.6 ;
    END
  END c_d[86]
  PIN c_d[87]
    DIRECTION INPUT ;
    USE SIGNAL ;
    PORT
      LAYER M5 ;
        RECT  38.448 183.516 38.472 183.6 ;
    END
  END c_d[87]
  PIN c_d[88]
    DIRECTION INPUT ;
    USE SIGNAL ;
    PORT
      LAYER M5 ;
        RECT  38.88 183.516 38.904 183.6 ;
    END
  END c_d[88]
  PIN c_d[89]
    DIRECTION INPUT ;
    USE SIGNAL ;
    PORT
      LAYER M5 ;
        RECT  39.312 183.516 39.336 183.6 ;
    END
  END c_d[89]
  PIN c_d[8]
    DIRECTION INPUT ;
    USE SIGNAL ;
    PORT
      LAYER M5 ;
        RECT  3.744 183.516 3.768 183.6 ;
    END
  END c_d[8]
  PIN c_d[90]
    DIRECTION INPUT ;
    USE SIGNAL ;
    PORT
      LAYER M5 ;
        RECT  39.744 183.516 39.768 183.6 ;
    END
  END c_d[90]
  PIN c_d[91]
    DIRECTION INPUT ;
    USE SIGNAL ;
    PORT
      LAYER M5 ;
        RECT  40.176 183.516 40.2 183.6 ;
    END
  END c_d[91]
  PIN c_d[92]
    DIRECTION INPUT ;
    USE SIGNAL ;
    PORT
      LAYER M5 ;
        RECT  40.608 183.516 40.632 183.6 ;
    END
  END c_d[92]
  PIN c_d[93]
    DIRECTION INPUT ;
    USE SIGNAL ;
    PORT
      LAYER M5 ;
        RECT  41.088 183.516 41.112 183.6 ;
    END
  END c_d[93]
  PIN c_d[94]
    DIRECTION INPUT ;
    USE SIGNAL ;
    PORT
      LAYER M5 ;
        RECT  41.52 183.516 41.544 183.6 ;
    END
  END c_d[94]
  PIN c_d[95]
    DIRECTION INPUT ;
    USE SIGNAL ;
    PORT
      LAYER M5 ;
        RECT  41.952 183.516 41.976 183.6 ;
    END
  END c_d[95]
  PIN c_d[96]
    DIRECTION INPUT ;
    USE SIGNAL ;
    PORT
      LAYER M5 ;
        RECT  42.384 183.516 42.408 183.6 ;
    END
  END c_d[96]
  PIN c_d[97]
    DIRECTION INPUT ;
    USE SIGNAL ;
    PORT
      LAYER M5 ;
        RECT  42.816 183.516 42.84 183.6 ;
    END
  END c_d[97]
  PIN c_d[98]
    DIRECTION INPUT ;
    USE SIGNAL ;
    PORT
      LAYER M5 ;
        RECT  43.248 183.516 43.272 183.6 ;
    END
  END c_d[98]
  PIN c_d[99]
    DIRECTION INPUT ;
    USE SIGNAL ;
    PORT
      LAYER M5 ;
        RECT  43.68 183.516 43.704 183.6 ;
    END
  END c_d[99]
  PIN c_d[9]
    DIRECTION INPUT ;
    USE SIGNAL ;
    PORT
      LAYER M5 ;
        RECT  4.176 183.516 4.2 183.6 ;
    END
  END c_d[9]
  PIN c_lane[0]
    DIRECTION INPUT ;
    USE SIGNAL ;
    PORT
      LAYER M5 ;
        RECT  112.656 183.516 112.68 183.6 ;
    END
  END c_lane[0]
  PIN c_lane[1]
    DIRECTION INPUT ;
    USE SIGNAL ;
    PORT
      LAYER M5 ;
        RECT  113.136 183.516 113.16 183.6 ;
    END
  END c_lane[1]
  PIN c_lane[2]
    DIRECTION INPUT ;
    USE SIGNAL ;
    PORT
      LAYER M5 ;
        RECT  113.568 183.516 113.592 183.6 ;
    END
  END c_lane[2]
  PIN c_sec[0]
    DIRECTION INPUT ;
    USE SIGNAL ;
    PORT
      LAYER M5 ;
        RECT  114 183.516 114.024 183.6 ;
    END
  END c_sec[0]
  PIN c_sec[10]
    DIRECTION INPUT ;
    USE SIGNAL ;
    PORT
      LAYER M5 ;
        RECT  118.368 183.516 118.392 183.6 ;
    END
  END c_sec[10]
  PIN c_sec[11]
    DIRECTION INPUT ;
    USE SIGNAL ;
    PORT
      LAYER M5 ;
        RECT  118.848 183.516 118.872 183.6 ;
    END
  END c_sec[11]
  PIN c_sec[12]
    DIRECTION INPUT ;
    USE SIGNAL ;
    PORT
      LAYER M5 ;
        RECT  119.28 183.516 119.304 183.6 ;
    END
  END c_sec[12]
  PIN c_sec[13]
    DIRECTION INPUT ;
    USE SIGNAL ;
    PORT
      LAYER M5 ;
        RECT  119.712 183.516 119.736 183.6 ;
    END
  END c_sec[13]
  PIN c_sec[14]
    DIRECTION INPUT ;
    USE SIGNAL ;
    PORT
      LAYER M5 ;
        RECT  120.144 183.516 120.168 183.6 ;
    END
  END c_sec[14]
  PIN c_sec[15]
    DIRECTION INPUT ;
    USE SIGNAL ;
    PORT
      LAYER M5 ;
        RECT  120.576 183.516 120.6 183.6 ;
    END
  END c_sec[15]
  PIN c_sec[16]
    DIRECTION INPUT ;
    USE SIGNAL ;
    PORT
      LAYER M5 ;
        RECT  121.008 183.516 121.032 183.6 ;
    END
  END c_sec[16]
  PIN c_sec[17]
    DIRECTION INPUT ;
    USE SIGNAL ;
    PORT
      LAYER M5 ;
        RECT  121.44 183.516 121.464 183.6 ;
    END
  END c_sec[17]
  PIN c_sec[18]
    DIRECTION INPUT ;
    USE SIGNAL ;
    PORT
      LAYER M5 ;
        RECT  121.92 183.516 121.944 183.6 ;
    END
  END c_sec[18]
  PIN c_sec[19]
    DIRECTION INPUT ;
    USE SIGNAL ;
    PORT
      LAYER M5 ;
        RECT  122.352 183.516 122.376 183.6 ;
    END
  END c_sec[19]
  PIN c_sec[1]
    DIRECTION INPUT ;
    USE SIGNAL ;
    PORT
      LAYER M5 ;
        RECT  114.432 183.516 114.456 183.6 ;
    END
  END c_sec[1]
  PIN c_sec[20]
    DIRECTION INPUT ;
    USE SIGNAL ;
    PORT
      LAYER M5 ;
        RECT  122.784 183.516 122.808 183.6 ;
    END
  END c_sec[20]
  PIN c_sec[21]
    DIRECTION INPUT ;
    USE SIGNAL ;
    PORT
      LAYER M5 ;
        RECT  123.216 183.516 123.24 183.6 ;
    END
  END c_sec[21]
  PIN c_sec[22]
    DIRECTION INPUT ;
    USE SIGNAL ;
    PORT
      LAYER M5 ;
        RECT  123.648 183.516 123.672 183.6 ;
    END
  END c_sec[22]
  PIN c_sec[23]
    DIRECTION INPUT ;
    USE SIGNAL ;
    PORT
      LAYER M5 ;
        RECT  124.08 183.516 124.104 183.6 ;
    END
  END c_sec[23]
  PIN c_sec[2]
    DIRECTION INPUT ;
    USE SIGNAL ;
    PORT
      LAYER M5 ;
        RECT  114.864 183.516 114.888 183.6 ;
    END
  END c_sec[2]
  PIN c_sec[3]
    DIRECTION INPUT ;
    USE SIGNAL ;
    PORT
      LAYER M5 ;
        RECT  115.296 183.516 115.32 183.6 ;
    END
  END c_sec[3]
  PIN c_sec[4]
    DIRECTION INPUT ;
    USE SIGNAL ;
    PORT
      LAYER M5 ;
        RECT  115.728 183.516 115.752 183.6 ;
    END
  END c_sec[4]
  PIN c_sec[5]
    DIRECTION INPUT ;
    USE SIGNAL ;
    PORT
      LAYER M5 ;
        RECT  116.208 183.516 116.232 183.6 ;
    END
  END c_sec[5]
  PIN c_sec[6]
    DIRECTION INPUT ;
    USE SIGNAL ;
    PORT
      LAYER M5 ;
        RECT  116.64 183.516 116.664 183.6 ;
    END
  END c_sec[6]
  PIN c_sec[7]
    DIRECTION INPUT ;
    USE SIGNAL ;
    PORT
      LAYER M5 ;
        RECT  117.072 183.516 117.096 183.6 ;
    END
  END c_sec[7]
  PIN c_sec[8]
    DIRECTION INPUT ;
    USE SIGNAL ;
    PORT
      LAYER M5 ;
        RECT  117.504 183.516 117.528 183.6 ;
    END
  END c_sec[8]
  PIN c_sec[9]
    DIRECTION INPUT ;
    USE SIGNAL ;
    PORT
      LAYER M5 ;
        RECT  117.936 183.516 117.96 183.6 ;
    END
  END c_sec[9]
  PIN c_tag[0]
    DIRECTION INPUT ;
    USE SIGNAL ;
    PORT
      LAYER M5 ;
        RECT  124.56 183.516 124.584 183.6 ;
    END
  END c_tag[0]
  PIN c_tag[1]
    DIRECTION INPUT ;
    USE SIGNAL ;
    PORT
      LAYER M5 ;
        RECT  124.992 183.516 125.016 183.6 ;
    END
  END c_tag[1]
  PIN c_tag[2]
    DIRECTION INPUT ;
    USE SIGNAL ;
    PORT
      LAYER M5 ;
        RECT  125.424 183.516 125.448 183.6 ;
    END
  END c_tag[2]
  PIN c_tag[3]
    DIRECTION INPUT ;
    USE SIGNAL ;
    PORT
      LAYER M5 ;
        RECT  125.856 183.516 125.88 183.6 ;
    END
  END c_tag[3]
  PIN c_tag[4]
    DIRECTION INPUT ;
    USE SIGNAL ;
    PORT
      LAYER M5 ;
        RECT  126.288 183.516 126.312 183.6 ;
    END
  END c_tag[4]
  PIN c_tag[5]
    DIRECTION INPUT ;
    USE SIGNAL ;
    PORT
      LAYER M5 ;
        RECT  126.72 183.516 126.744 183.6 ;
    END
  END c_tag[5]
  PIN c_tag[6]
    DIRECTION INPUT ;
    USE SIGNAL ;
    PORT
      LAYER M5 ;
        RECT  127.152 183.516 127.176 183.6 ;
    END
  END c_tag[6]
  PIN c_tag[7]
    DIRECTION INPUT ;
    USE SIGNAL ;
    PORT
      LAYER M5 ;
        RECT  127.632 183.516 127.656 183.6 ;
    END
  END c_tag[7]
  PIN c_tag[8]
    DIRECTION INPUT ;
    USE SIGNAL ;
    PORT
      LAYER M5 ;
        RECT  128.064 183.516 128.088 183.6 ;
    END
  END c_tag[8]
  PIN c_v
    DIRECTION INPUT ;
    USE SIGNAL ;
    PORT
      LAYER M5 ;
        RECT  128.496 183.516 128.52 183.6 ;
    END
  END c_v
  PIN clk
    DIRECTION INPUT ;
    USE SIGNAL ;
    PORT
      LAYER M4 ;
        RECT  129.516 88.752 129.6 88.776 ;
    END
  END clk
  PIN dn_bad
    DIRECTION INPUT ;
    USE SIGNAL ;
    PORT
      LAYER M5 ;
        RECT  0.24 0 0.264 0.084 ;
    END
  END dn_bad
  PIN dn_v
    DIRECTION INPUT ;
    USE SIGNAL ;
    PORT
      LAYER M5 ;
        RECT  0.672 0 0.696 0.084 ;
    END
  END dn_v
  PIN dp_bad
    DIRECTION OUTPUT ;
    USE SIGNAL ;
    PORT
      LAYER M5 ;
        RECT  128.928 183.516 128.952 183.6 ;
    END
  END dp_bad
  PIN dp_v
    DIRECTION OUTPUT ;
    USE SIGNAL ;
    PORT
      LAYER M5 ;
        RECT  129.36 183.516 129.384 183.6 ;
    END
  END dp_v
  PIN lane[0]
    DIRECTION INPUT ;
    USE SIGNAL ;
    PORT
      LAYER M4 ;
        RECT  129.516 126.672 129.6 126.696 ;
    END
  END lane[0]
  PIN lane[1]
    DIRECTION INPUT ;
    USE SIGNAL ;
    PORT
      LAYER M4 ;
        RECT  129.516 139.968 129.6 139.992 ;
    END
  END lane[1]
  PIN lane[2]
    DIRECTION INPUT ;
    USE SIGNAL ;
    PORT
      LAYER M4 ;
        RECT  129.516 153.312 129.6 153.336 ;
    END
  END lane[2]
  PIN n_d[0]
    DIRECTION OUTPUT ;
    USE SIGNAL ;
    PORT
      LAYER M5 ;
        RECT  1.104 0 1.128 0.084 ;
    END
  END n_d[0]
  PIN n_d[100]
    DIRECTION OUTPUT ;
    USE SIGNAL ;
    PORT
      LAYER M5 ;
        RECT  45.024 0 45.048 0.084 ;
    END
  END n_d[100]
  PIN n_d[101]
    DIRECTION OUTPUT ;
    USE SIGNAL ;
    PORT
      LAYER M5 ;
        RECT  45.456 0 45.48 0.084 ;
    END
  END n_d[101]
  PIN n_d[102]
    DIRECTION OUTPUT ;
    USE SIGNAL ;
    PORT
      LAYER M5 ;
        RECT  45.888 0 45.912 0.084 ;
    END
  END n_d[102]
  PIN n_d[103]
    DIRECTION OUTPUT ;
    USE SIGNAL ;
    PORT
      LAYER M5 ;
        RECT  46.32 0 46.344 0.084 ;
    END
  END n_d[103]
  PIN n_d[104]
    DIRECTION OUTPUT ;
    USE SIGNAL ;
    PORT
      LAYER M5 ;
        RECT  46.8 0 46.824 0.084 ;
    END
  END n_d[104]
  PIN n_d[105]
    DIRECTION OUTPUT ;
    USE SIGNAL ;
    PORT
      LAYER M5 ;
        RECT  47.232 0 47.256 0.084 ;
    END
  END n_d[105]
  PIN n_d[106]
    DIRECTION OUTPUT ;
    USE SIGNAL ;
    PORT
      LAYER M5 ;
        RECT  47.664 0 47.688 0.084 ;
    END
  END n_d[106]
  PIN n_d[107]
    DIRECTION OUTPUT ;
    USE SIGNAL ;
    PORT
      LAYER M5 ;
        RECT  48.096 0 48.12 0.084 ;
    END
  END n_d[107]
  PIN n_d[108]
    DIRECTION OUTPUT ;
    USE SIGNAL ;
    PORT
      LAYER M5 ;
        RECT  48.528 0 48.552 0.084 ;
    END
  END n_d[108]
  PIN n_d[109]
    DIRECTION OUTPUT ;
    USE SIGNAL ;
    PORT
      LAYER M5 ;
        RECT  48.96 0 48.984 0.084 ;
    END
  END n_d[109]
  PIN n_d[10]
    DIRECTION OUTPUT ;
    USE SIGNAL ;
    PORT
      LAYER M5 ;
        RECT  5.472 0 5.496 0.084 ;
    END
  END n_d[10]
  PIN n_d[110]
    DIRECTION OUTPUT ;
    USE SIGNAL ;
    PORT
      LAYER M5 ;
        RECT  49.392 0 49.416 0.084 ;
    END
  END n_d[110]
  PIN n_d[111]
    DIRECTION OUTPUT ;
    USE SIGNAL ;
    PORT
      LAYER M5 ;
        RECT  49.872 0 49.896 0.084 ;
    END
  END n_d[111]
  PIN n_d[112]
    DIRECTION OUTPUT ;
    USE SIGNAL ;
    PORT
      LAYER M5 ;
        RECT  50.304 0 50.328 0.084 ;
    END
  END n_d[112]
  PIN n_d[113]
    DIRECTION OUTPUT ;
    USE SIGNAL ;
    PORT
      LAYER M5 ;
        RECT  50.736 0 50.76 0.084 ;
    END
  END n_d[113]
  PIN n_d[114]
    DIRECTION OUTPUT ;
    USE SIGNAL ;
    PORT
      LAYER M5 ;
        RECT  51.168 0 51.192 0.084 ;
    END
  END n_d[114]
  PIN n_d[115]
    DIRECTION OUTPUT ;
    USE SIGNAL ;
    PORT
      LAYER M5 ;
        RECT  51.6 0 51.624 0.084 ;
    END
  END n_d[115]
  PIN n_d[116]
    DIRECTION OUTPUT ;
    USE SIGNAL ;
    PORT
      LAYER M5 ;
        RECT  52.032 0 52.056 0.084 ;
    END
  END n_d[116]
  PIN n_d[117]
    DIRECTION OUTPUT ;
    USE SIGNAL ;
    PORT
      LAYER M5 ;
        RECT  52.464 0 52.488 0.084 ;
    END
  END n_d[117]
  PIN n_d[118]
    DIRECTION OUTPUT ;
    USE SIGNAL ;
    PORT
      LAYER M5 ;
        RECT  52.944 0 52.968 0.084 ;
    END
  END n_d[118]
  PIN n_d[119]
    DIRECTION OUTPUT ;
    USE SIGNAL ;
    PORT
      LAYER M5 ;
        RECT  53.376 0 53.4 0.084 ;
    END
  END n_d[119]
  PIN n_d[11]
    DIRECTION OUTPUT ;
    USE SIGNAL ;
    PORT
      LAYER M5 ;
        RECT  5.904 0 5.928 0.084 ;
    END
  END n_d[11]
  PIN n_d[120]
    DIRECTION OUTPUT ;
    USE SIGNAL ;
    PORT
      LAYER M5 ;
        RECT  53.808 0 53.832 0.084 ;
    END
  END n_d[120]
  PIN n_d[121]
    DIRECTION OUTPUT ;
    USE SIGNAL ;
    PORT
      LAYER M5 ;
        RECT  54.24 0 54.264 0.084 ;
    END
  END n_d[121]
  PIN n_d[122]
    DIRECTION OUTPUT ;
    USE SIGNAL ;
    PORT
      LAYER M5 ;
        RECT  54.672 0 54.696 0.084 ;
    END
  END n_d[122]
  PIN n_d[123]
    DIRECTION OUTPUT ;
    USE SIGNAL ;
    PORT
      LAYER M5 ;
        RECT  55.104 0 55.128 0.084 ;
    END
  END n_d[123]
  PIN n_d[124]
    DIRECTION OUTPUT ;
    USE SIGNAL ;
    PORT
      LAYER M5 ;
        RECT  55.584 0 55.608 0.084 ;
    END
  END n_d[124]
  PIN n_d[125]
    DIRECTION OUTPUT ;
    USE SIGNAL ;
    PORT
      LAYER M5 ;
        RECT  56.016 0 56.04 0.084 ;
    END
  END n_d[125]
  PIN n_d[126]
    DIRECTION OUTPUT ;
    USE SIGNAL ;
    PORT
      LAYER M5 ;
        RECT  56.448 0 56.472 0.084 ;
    END
  END n_d[126]
  PIN n_d[127]
    DIRECTION OUTPUT ;
    USE SIGNAL ;
    PORT
      LAYER M5 ;
        RECT  56.88 0 56.904 0.084 ;
    END
  END n_d[127]
  PIN n_d[128]
    DIRECTION OUTPUT ;
    USE SIGNAL ;
    PORT
      LAYER M5 ;
        RECT  57.312 0 57.336 0.084 ;
    END
  END n_d[128]
  PIN n_d[129]
    DIRECTION OUTPUT ;
    USE SIGNAL ;
    PORT
      LAYER M5 ;
        RECT  57.744 0 57.768 0.084 ;
    END
  END n_d[129]
  PIN n_d[12]
    DIRECTION OUTPUT ;
    USE SIGNAL ;
    PORT
      LAYER M5 ;
        RECT  6.336 0 6.36 0.084 ;
    END
  END n_d[12]
  PIN n_d[130]
    DIRECTION OUTPUT ;
    USE SIGNAL ;
    PORT
      LAYER M5 ;
        RECT  58.176 0 58.2 0.084 ;
    END
  END n_d[130]
  PIN n_d[131]
    DIRECTION OUTPUT ;
    USE SIGNAL ;
    PORT
      LAYER M5 ;
        RECT  58.656 0 58.68 0.084 ;
    END
  END n_d[131]
  PIN n_d[132]
    DIRECTION OUTPUT ;
    USE SIGNAL ;
    PORT
      LAYER M5 ;
        RECT  59.088 0 59.112 0.084 ;
    END
  END n_d[132]
  PIN n_d[133]
    DIRECTION OUTPUT ;
    USE SIGNAL ;
    PORT
      LAYER M5 ;
        RECT  59.52 0 59.544 0.084 ;
    END
  END n_d[133]
  PIN n_d[134]
    DIRECTION OUTPUT ;
    USE SIGNAL ;
    PORT
      LAYER M5 ;
        RECT  59.952 0 59.976 0.084 ;
    END
  END n_d[134]
  PIN n_d[135]
    DIRECTION OUTPUT ;
    USE SIGNAL ;
    PORT
      LAYER M5 ;
        RECT  60.384 0 60.408 0.084 ;
    END
  END n_d[135]
  PIN n_d[136]
    DIRECTION OUTPUT ;
    USE SIGNAL ;
    PORT
      LAYER M5 ;
        RECT  60.816 0 60.84 0.084 ;
    END
  END n_d[136]
  PIN n_d[137]
    DIRECTION OUTPUT ;
    USE SIGNAL ;
    PORT
      LAYER M5 ;
        RECT  61.296 0 61.32 0.084 ;
    END
  END n_d[137]
  PIN n_d[138]
    DIRECTION OUTPUT ;
    USE SIGNAL ;
    PORT
      LAYER M5 ;
        RECT  61.728 0 61.752 0.084 ;
    END
  END n_d[138]
  PIN n_d[139]
    DIRECTION OUTPUT ;
    USE SIGNAL ;
    PORT
      LAYER M5 ;
        RECT  62.16 0 62.184 0.084 ;
    END
  END n_d[139]
  PIN n_d[13]
    DIRECTION OUTPUT ;
    USE SIGNAL ;
    PORT
      LAYER M5 ;
        RECT  6.816 0 6.84 0.084 ;
    END
  END n_d[13]
  PIN n_d[140]
    DIRECTION OUTPUT ;
    USE SIGNAL ;
    PORT
      LAYER M5 ;
        RECT  62.592 0 62.616 0.084 ;
    END
  END n_d[140]
  PIN n_d[141]
    DIRECTION OUTPUT ;
    USE SIGNAL ;
    PORT
      LAYER M5 ;
        RECT  63.024 0 63.048 0.084 ;
    END
  END n_d[141]
  PIN n_d[142]
    DIRECTION OUTPUT ;
    USE SIGNAL ;
    PORT
      LAYER M5 ;
        RECT  63.456 0 63.48 0.084 ;
    END
  END n_d[142]
  PIN n_d[143]
    DIRECTION OUTPUT ;
    USE SIGNAL ;
    PORT
      LAYER M5 ;
        RECT  63.888 0 63.912 0.084 ;
    END
  END n_d[143]
  PIN n_d[144]
    DIRECTION OUTPUT ;
    USE SIGNAL ;
    PORT
      LAYER M5 ;
        RECT  64.416 0 64.44 0.084 ;
    END
  END n_d[144]
  PIN n_d[145]
    DIRECTION OUTPUT ;
    USE SIGNAL ;
    PORT
      LAYER M5 ;
        RECT  64.848 0 64.872 0.084 ;
    END
  END n_d[145]
  PIN n_d[146]
    DIRECTION OUTPUT ;
    USE SIGNAL ;
    PORT
      LAYER M5 ;
        RECT  65.28 0 65.304 0.084 ;
    END
  END n_d[146]
  PIN n_d[147]
    DIRECTION OUTPUT ;
    USE SIGNAL ;
    PORT
      LAYER M5 ;
        RECT  65.712 0 65.736 0.084 ;
    END
  END n_d[147]
  PIN n_d[148]
    DIRECTION OUTPUT ;
    USE SIGNAL ;
    PORT
      LAYER M5 ;
        RECT  66.144 0 66.168 0.084 ;
    END
  END n_d[148]
  PIN n_d[149]
    DIRECTION OUTPUT ;
    USE SIGNAL ;
    PORT
      LAYER M5 ;
        RECT  66.576 0 66.6 0.084 ;
    END
  END n_d[149]
  PIN n_d[14]
    DIRECTION OUTPUT ;
    USE SIGNAL ;
    PORT
      LAYER M5 ;
        RECT  7.248 0 7.272 0.084 ;
    END
  END n_d[14]
  PIN n_d[150]
    DIRECTION OUTPUT ;
    USE SIGNAL ;
    PORT
      LAYER M5 ;
        RECT  67.008 0 67.032 0.084 ;
    END
  END n_d[150]
  PIN n_d[151]
    DIRECTION OUTPUT ;
    USE SIGNAL ;
    PORT
      LAYER M5 ;
        RECT  67.44 0 67.464 0.084 ;
    END
  END n_d[151]
  PIN n_d[152]
    DIRECTION OUTPUT ;
    USE SIGNAL ;
    PORT
      LAYER M5 ;
        RECT  67.872 0 67.896 0.084 ;
    END
  END n_d[152]
  PIN n_d[153]
    DIRECTION OUTPUT ;
    USE SIGNAL ;
    PORT
      LAYER M5 ;
        RECT  68.304 0 68.328 0.084 ;
    END
  END n_d[153]
  PIN n_d[154]
    DIRECTION OUTPUT ;
    USE SIGNAL ;
    PORT
      LAYER M5 ;
        RECT  68.736 0 68.76 0.084 ;
    END
  END n_d[154]
  PIN n_d[155]
    DIRECTION OUTPUT ;
    USE SIGNAL ;
    PORT
      LAYER M5 ;
        RECT  69.168 0 69.192 0.084 ;
    END
  END n_d[155]
  PIN n_d[156]
    DIRECTION OUTPUT ;
    USE SIGNAL ;
    PORT
      LAYER M5 ;
        RECT  69.6 0 69.624 0.084 ;
    END
  END n_d[156]
  PIN n_d[157]
    DIRECTION OUTPUT ;
    USE SIGNAL ;
    PORT
      LAYER M5 ;
        RECT  70.08 0 70.104 0.084 ;
    END
  END n_d[157]
  PIN n_d[158]
    DIRECTION OUTPUT ;
    USE SIGNAL ;
    PORT
      LAYER M5 ;
        RECT  70.512 0 70.536 0.084 ;
    END
  END n_d[158]
  PIN n_d[159]
    DIRECTION OUTPUT ;
    USE SIGNAL ;
    PORT
      LAYER M5 ;
        RECT  70.944 0 70.968 0.084 ;
    END
  END n_d[159]
  PIN n_d[15]
    DIRECTION OUTPUT ;
    USE SIGNAL ;
    PORT
      LAYER M5 ;
        RECT  7.68 0 7.704 0.084 ;
    END
  END n_d[15]
  PIN n_d[160]
    DIRECTION OUTPUT ;
    USE SIGNAL ;
    PORT
      LAYER M5 ;
        RECT  71.376 0 71.4 0.084 ;
    END
  END n_d[160]
  PIN n_d[161]
    DIRECTION OUTPUT ;
    USE SIGNAL ;
    PORT
      LAYER M5 ;
        RECT  71.808 0 71.832 0.084 ;
    END
  END n_d[161]
  PIN n_d[162]
    DIRECTION OUTPUT ;
    USE SIGNAL ;
    PORT
      LAYER M5 ;
        RECT  72.24 0 72.264 0.084 ;
    END
  END n_d[162]
  PIN n_d[163]
    DIRECTION OUTPUT ;
    USE SIGNAL ;
    PORT
      LAYER M5 ;
        RECT  72.72 0 72.744 0.084 ;
    END
  END n_d[163]
  PIN n_d[164]
    DIRECTION OUTPUT ;
    USE SIGNAL ;
    PORT
      LAYER M5 ;
        RECT  73.152 0 73.176 0.084 ;
    END
  END n_d[164]
  PIN n_d[165]
    DIRECTION OUTPUT ;
    USE SIGNAL ;
    PORT
      LAYER M5 ;
        RECT  73.584 0 73.608 0.084 ;
    END
  END n_d[165]
  PIN n_d[166]
    DIRECTION OUTPUT ;
    USE SIGNAL ;
    PORT
      LAYER M5 ;
        RECT  74.016 0 74.04 0.084 ;
    END
  END n_d[166]
  PIN n_d[167]
    DIRECTION OUTPUT ;
    USE SIGNAL ;
    PORT
      LAYER M5 ;
        RECT  74.448 0 74.472 0.084 ;
    END
  END n_d[167]
  PIN n_d[168]
    DIRECTION OUTPUT ;
    USE SIGNAL ;
    PORT
      LAYER M5 ;
        RECT  74.88 0 74.904 0.084 ;
    END
  END n_d[168]
  PIN n_d[169]
    DIRECTION OUTPUT ;
    USE SIGNAL ;
    PORT
      LAYER M5 ;
        RECT  75.312 0 75.336 0.084 ;
    END
  END n_d[169]
  PIN n_d[16]
    DIRECTION OUTPUT ;
    USE SIGNAL ;
    PORT
      LAYER M5 ;
        RECT  8.112 0 8.136 0.084 ;
    END
  END n_d[16]
  PIN n_d[170]
    DIRECTION OUTPUT ;
    USE SIGNAL ;
    PORT
      LAYER M5 ;
        RECT  75.792 0 75.816 0.084 ;
    END
  END n_d[170]
  PIN n_d[171]
    DIRECTION OUTPUT ;
    USE SIGNAL ;
    PORT
      LAYER M5 ;
        RECT  76.224 0 76.248 0.084 ;
    END
  END n_d[171]
  PIN n_d[172]
    DIRECTION OUTPUT ;
    USE SIGNAL ;
    PORT
      LAYER M5 ;
        RECT  76.656 0 76.68 0.084 ;
    END
  END n_d[172]
  PIN n_d[173]
    DIRECTION OUTPUT ;
    USE SIGNAL ;
    PORT
      LAYER M5 ;
        RECT  77.088 0 77.112 0.084 ;
    END
  END n_d[173]
  PIN n_d[174]
    DIRECTION OUTPUT ;
    USE SIGNAL ;
    PORT
      LAYER M5 ;
        RECT  77.52 0 77.544 0.084 ;
    END
  END n_d[174]
  PIN n_d[175]
    DIRECTION OUTPUT ;
    USE SIGNAL ;
    PORT
      LAYER M5 ;
        RECT  77.952 0 77.976 0.084 ;
    END
  END n_d[175]
  PIN n_d[176]
    DIRECTION OUTPUT ;
    USE SIGNAL ;
    PORT
      LAYER M5 ;
        RECT  78.384 0 78.408 0.084 ;
    END
  END n_d[176]
  PIN n_d[177]
    DIRECTION OUTPUT ;
    USE SIGNAL ;
    PORT
      LAYER M5 ;
        RECT  78.864 0 78.888 0.084 ;
    END
  END n_d[177]
  PIN n_d[178]
    DIRECTION OUTPUT ;
    USE SIGNAL ;
    PORT
      LAYER M5 ;
        RECT  79.296 0 79.32 0.084 ;
    END
  END n_d[178]
  PIN n_d[179]
    DIRECTION OUTPUT ;
    USE SIGNAL ;
    PORT
      LAYER M5 ;
        RECT  79.728 0 79.752 0.084 ;
    END
  END n_d[179]
  PIN n_d[17]
    DIRECTION OUTPUT ;
    USE SIGNAL ;
    PORT
      LAYER M5 ;
        RECT  8.544 0 8.568 0.084 ;
    END
  END n_d[17]
  PIN n_d[180]
    DIRECTION OUTPUT ;
    USE SIGNAL ;
    PORT
      LAYER M5 ;
        RECT  80.16 0 80.184 0.084 ;
    END
  END n_d[180]
  PIN n_d[181]
    DIRECTION OUTPUT ;
    USE SIGNAL ;
    PORT
      LAYER M5 ;
        RECT  80.592 0 80.616 0.084 ;
    END
  END n_d[181]
  PIN n_d[182]
    DIRECTION OUTPUT ;
    USE SIGNAL ;
    PORT
      LAYER M5 ;
        RECT  81.024 0 81.048 0.084 ;
    END
  END n_d[182]
  PIN n_d[183]
    DIRECTION OUTPUT ;
    USE SIGNAL ;
    PORT
      LAYER M5 ;
        RECT  81.504 0 81.528 0.084 ;
    END
  END n_d[183]
  PIN n_d[184]
    DIRECTION OUTPUT ;
    USE SIGNAL ;
    PORT
      LAYER M5 ;
        RECT  81.936 0 81.96 0.084 ;
    END
  END n_d[184]
  PIN n_d[185]
    DIRECTION OUTPUT ;
    USE SIGNAL ;
    PORT
      LAYER M5 ;
        RECT  82.368 0 82.392 0.084 ;
    END
  END n_d[185]
  PIN n_d[186]
    DIRECTION OUTPUT ;
    USE SIGNAL ;
    PORT
      LAYER M5 ;
        RECT  82.8 0 82.824 0.084 ;
    END
  END n_d[186]
  PIN n_d[187]
    DIRECTION OUTPUT ;
    USE SIGNAL ;
    PORT
      LAYER M5 ;
        RECT  83.232 0 83.256 0.084 ;
    END
  END n_d[187]
  PIN n_d[188]
    DIRECTION OUTPUT ;
    USE SIGNAL ;
    PORT
      LAYER M5 ;
        RECT  83.664 0 83.688 0.084 ;
    END
  END n_d[188]
  PIN n_d[189]
    DIRECTION OUTPUT ;
    USE SIGNAL ;
    PORT
      LAYER M5 ;
        RECT  84.096 0 84.12 0.084 ;
    END
  END n_d[189]
  PIN n_d[18]
    DIRECTION OUTPUT ;
    USE SIGNAL ;
    PORT
      LAYER M5 ;
        RECT  8.976 0 9 0.084 ;
    END
  END n_d[18]
  PIN n_d[190]
    DIRECTION OUTPUT ;
    USE SIGNAL ;
    PORT
      LAYER M5 ;
        RECT  84.624 0 84.648 0.084 ;
    END
  END n_d[190]
  PIN n_d[191]
    DIRECTION OUTPUT ;
    USE SIGNAL ;
    PORT
      LAYER M5 ;
        RECT  85.056 0 85.08 0.084 ;
    END
  END n_d[191]
  PIN n_d[192]
    DIRECTION OUTPUT ;
    USE SIGNAL ;
    PORT
      LAYER M5 ;
        RECT  85.488 0 85.512 0.084 ;
    END
  END n_d[192]
  PIN n_d[193]
    DIRECTION OUTPUT ;
    USE SIGNAL ;
    PORT
      LAYER M5 ;
        RECT  85.92 0 85.944 0.084 ;
    END
  END n_d[193]
  PIN n_d[194]
    DIRECTION OUTPUT ;
    USE SIGNAL ;
    PORT
      LAYER M5 ;
        RECT  86.352 0 86.376 0.084 ;
    END
  END n_d[194]
  PIN n_d[195]
    DIRECTION OUTPUT ;
    USE SIGNAL ;
    PORT
      LAYER M5 ;
        RECT  86.784 0 86.808 0.084 ;
    END
  END n_d[195]
  PIN n_d[196]
    DIRECTION OUTPUT ;
    USE SIGNAL ;
    PORT
      LAYER M5 ;
        RECT  87.216 0 87.24 0.084 ;
    END
  END n_d[196]
  PIN n_d[197]
    DIRECTION OUTPUT ;
    USE SIGNAL ;
    PORT
      LAYER M5 ;
        RECT  87.648 0 87.672 0.084 ;
    END
  END n_d[197]
  PIN n_d[198]
    DIRECTION OUTPUT ;
    USE SIGNAL ;
    PORT
      LAYER M5 ;
        RECT  88.08 0 88.104 0.084 ;
    END
  END n_d[198]
  PIN n_d[199]
    DIRECTION OUTPUT ;
    USE SIGNAL ;
    PORT
      LAYER M5 ;
        RECT  88.512 0 88.536 0.084 ;
    END
  END n_d[199]
  PIN n_d[19]
    DIRECTION OUTPUT ;
    USE SIGNAL ;
    PORT
      LAYER M5 ;
        RECT  9.456 0 9.48 0.084 ;
    END
  END n_d[19]
  PIN n_d[1]
    DIRECTION OUTPUT ;
    USE SIGNAL ;
    PORT
      LAYER M5 ;
        RECT  1.536 0 1.56 0.084 ;
    END
  END n_d[1]
  PIN n_d[200]
    DIRECTION OUTPUT ;
    USE SIGNAL ;
    PORT
      LAYER M5 ;
        RECT  88.944 0 88.968 0.084 ;
    END
  END n_d[200]
  PIN n_d[201]
    DIRECTION OUTPUT ;
    USE SIGNAL ;
    PORT
      LAYER M5 ;
        RECT  89.376 0 89.4 0.084 ;
    END
  END n_d[201]
  PIN n_d[202]
    DIRECTION OUTPUT ;
    USE SIGNAL ;
    PORT
      LAYER M5 ;
        RECT  89.808 0 89.832 0.084 ;
    END
  END n_d[202]
  PIN n_d[203]
    DIRECTION OUTPUT ;
    USE SIGNAL ;
    PORT
      LAYER M5 ;
        RECT  90.288 0 90.312 0.084 ;
    END
  END n_d[203]
  PIN n_d[204]
    DIRECTION OUTPUT ;
    USE SIGNAL ;
    PORT
      LAYER M5 ;
        RECT  90.72 0 90.744 0.084 ;
    END
  END n_d[204]
  PIN n_d[205]
    DIRECTION OUTPUT ;
    USE SIGNAL ;
    PORT
      LAYER M5 ;
        RECT  91.152 0 91.176 0.084 ;
    END
  END n_d[205]
  PIN n_d[206]
    DIRECTION OUTPUT ;
    USE SIGNAL ;
    PORT
      LAYER M5 ;
        RECT  91.584 0 91.608 0.084 ;
    END
  END n_d[206]
  PIN n_d[207]
    DIRECTION OUTPUT ;
    USE SIGNAL ;
    PORT
      LAYER M5 ;
        RECT  92.016 0 92.04 0.084 ;
    END
  END n_d[207]
  PIN n_d[208]
    DIRECTION OUTPUT ;
    USE SIGNAL ;
    PORT
      LAYER M5 ;
        RECT  92.448 0 92.472 0.084 ;
    END
  END n_d[208]
  PIN n_d[209]
    DIRECTION OUTPUT ;
    USE SIGNAL ;
    PORT
      LAYER M5 ;
        RECT  92.928 0 92.952 0.084 ;
    END
  END n_d[209]
  PIN n_d[20]
    DIRECTION OUTPUT ;
    USE SIGNAL ;
    PORT
      LAYER M5 ;
        RECT  9.888 0 9.912 0.084 ;
    END
  END n_d[20]
  PIN n_d[210]
    DIRECTION OUTPUT ;
    USE SIGNAL ;
    PORT
      LAYER M5 ;
        RECT  93.36 0 93.384 0.084 ;
    END
  END n_d[210]
  PIN n_d[211]
    DIRECTION OUTPUT ;
    USE SIGNAL ;
    PORT
      LAYER M5 ;
        RECT  93.792 0 93.816 0.084 ;
    END
  END n_d[211]
  PIN n_d[212]
    DIRECTION OUTPUT ;
    USE SIGNAL ;
    PORT
      LAYER M5 ;
        RECT  94.224 0 94.248 0.084 ;
    END
  END n_d[212]
  PIN n_d[213]
    DIRECTION OUTPUT ;
    USE SIGNAL ;
    PORT
      LAYER M5 ;
        RECT  94.656 0 94.68 0.084 ;
    END
  END n_d[213]
  PIN n_d[214]
    DIRECTION OUTPUT ;
    USE SIGNAL ;
    PORT
      LAYER M5 ;
        RECT  95.088 0 95.112 0.084 ;
    END
  END n_d[214]
  PIN n_d[215]
    DIRECTION OUTPUT ;
    USE SIGNAL ;
    PORT
      LAYER M5 ;
        RECT  95.52 0 95.544 0.084 ;
    END
  END n_d[215]
  PIN n_d[216]
    DIRECTION OUTPUT ;
    USE SIGNAL ;
    PORT
      LAYER M5 ;
        RECT  96 0 96.024 0.084 ;
    END
  END n_d[216]
  PIN n_d[217]
    DIRECTION OUTPUT ;
    USE SIGNAL ;
    PORT
      LAYER M5 ;
        RECT  96.432 0 96.456 0.084 ;
    END
  END n_d[217]
  PIN n_d[218]
    DIRECTION OUTPUT ;
    USE SIGNAL ;
    PORT
      LAYER M5 ;
        RECT  96.864 0 96.888 0.084 ;
    END
  END n_d[218]
  PIN n_d[219]
    DIRECTION OUTPUT ;
    USE SIGNAL ;
    PORT
      LAYER M5 ;
        RECT  97.296 0 97.32 0.084 ;
    END
  END n_d[219]
  PIN n_d[21]
    DIRECTION OUTPUT ;
    USE SIGNAL ;
    PORT
      LAYER M5 ;
        RECT  10.32 0 10.344 0.084 ;
    END
  END n_d[21]
  PIN n_d[220]
    DIRECTION OUTPUT ;
    USE SIGNAL ;
    PORT
      LAYER M5 ;
        RECT  97.728 0 97.752 0.084 ;
    END
  END n_d[220]
  PIN n_d[221]
    DIRECTION OUTPUT ;
    USE SIGNAL ;
    PORT
      LAYER M5 ;
        RECT  98.16 0 98.184 0.084 ;
    END
  END n_d[221]
  PIN n_d[222]
    DIRECTION OUTPUT ;
    USE SIGNAL ;
    PORT
      LAYER M5 ;
        RECT  98.64 0 98.664 0.084 ;
    END
  END n_d[222]
  PIN n_d[223]
    DIRECTION OUTPUT ;
    USE SIGNAL ;
    PORT
      LAYER M5 ;
        RECT  99.072 0 99.096 0.084 ;
    END
  END n_d[223]
  PIN n_d[224]
    DIRECTION OUTPUT ;
    USE SIGNAL ;
    PORT
      LAYER M5 ;
        RECT  99.504 0 99.528 0.084 ;
    END
  END n_d[224]
  PIN n_d[225]
    DIRECTION OUTPUT ;
    USE SIGNAL ;
    PORT
      LAYER M5 ;
        RECT  99.936 0 99.96 0.084 ;
    END
  END n_d[225]
  PIN n_d[226]
    DIRECTION OUTPUT ;
    USE SIGNAL ;
    PORT
      LAYER M5 ;
        RECT  100.368 0 100.392 0.084 ;
    END
  END n_d[226]
  PIN n_d[227]
    DIRECTION OUTPUT ;
    USE SIGNAL ;
    PORT
      LAYER M5 ;
        RECT  100.8 0 100.824 0.084 ;
    END
  END n_d[227]
  PIN n_d[228]
    DIRECTION OUTPUT ;
    USE SIGNAL ;
    PORT
      LAYER M5 ;
        RECT  101.232 0 101.256 0.084 ;
    END
  END n_d[228]
  PIN n_d[229]
    DIRECTION OUTPUT ;
    USE SIGNAL ;
    PORT
      LAYER M5 ;
        RECT  101.712 0 101.736 0.084 ;
    END
  END n_d[229]
  PIN n_d[22]
    DIRECTION OUTPUT ;
    USE SIGNAL ;
    PORT
      LAYER M5 ;
        RECT  10.752 0 10.776 0.084 ;
    END
  END n_d[22]
  PIN n_d[230]
    DIRECTION OUTPUT ;
    USE SIGNAL ;
    PORT
      LAYER M5 ;
        RECT  102.144 0 102.168 0.084 ;
    END
  END n_d[230]
  PIN n_d[231]
    DIRECTION OUTPUT ;
    USE SIGNAL ;
    PORT
      LAYER M5 ;
        RECT  102.576 0 102.6 0.084 ;
    END
  END n_d[231]
  PIN n_d[232]
    DIRECTION OUTPUT ;
    USE SIGNAL ;
    PORT
      LAYER M5 ;
        RECT  103.008 0 103.032 0.084 ;
    END
  END n_d[232]
  PIN n_d[233]
    DIRECTION OUTPUT ;
    USE SIGNAL ;
    PORT
      LAYER M5 ;
        RECT  103.44 0 103.464 0.084 ;
    END
  END n_d[233]
  PIN n_d[234]
    DIRECTION OUTPUT ;
    USE SIGNAL ;
    PORT
      LAYER M5 ;
        RECT  103.872 0 103.896 0.084 ;
    END
  END n_d[234]
  PIN n_d[235]
    DIRECTION OUTPUT ;
    USE SIGNAL ;
    PORT
      LAYER M5 ;
        RECT  104.304 0 104.328 0.084 ;
    END
  END n_d[235]
  PIN n_d[236]
    DIRECTION OUTPUT ;
    USE SIGNAL ;
    PORT
      LAYER M5 ;
        RECT  104.784 0 104.808 0.084 ;
    END
  END n_d[236]
  PIN n_d[237]
    DIRECTION OUTPUT ;
    USE SIGNAL ;
    PORT
      LAYER M5 ;
        RECT  105.216 0 105.24 0.084 ;
    END
  END n_d[237]
  PIN n_d[238]
    DIRECTION OUTPUT ;
    USE SIGNAL ;
    PORT
      LAYER M5 ;
        RECT  105.648 0 105.672 0.084 ;
    END
  END n_d[238]
  PIN n_d[239]
    DIRECTION OUTPUT ;
    USE SIGNAL ;
    PORT
      LAYER M5 ;
        RECT  106.08 0 106.104 0.084 ;
    END
  END n_d[239]
  PIN n_d[23]
    DIRECTION OUTPUT ;
    USE SIGNAL ;
    PORT
      LAYER M5 ;
        RECT  11.184 0 11.208 0.084 ;
    END
  END n_d[23]
  PIN n_d[240]
    DIRECTION OUTPUT ;
    USE SIGNAL ;
    PORT
      LAYER M5 ;
        RECT  106.512 0 106.536 0.084 ;
    END
  END n_d[240]
  PIN n_d[241]
    DIRECTION OUTPUT ;
    USE SIGNAL ;
    PORT
      LAYER M5 ;
        RECT  106.944 0 106.968 0.084 ;
    END
  END n_d[241]
  PIN n_d[242]
    DIRECTION OUTPUT ;
    USE SIGNAL ;
    PORT
      LAYER M5 ;
        RECT  107.472 0 107.496 0.084 ;
    END
  END n_d[242]
  PIN n_d[243]
    DIRECTION OUTPUT ;
    USE SIGNAL ;
    PORT
      LAYER M5 ;
        RECT  107.904 0 107.928 0.084 ;
    END
  END n_d[243]
  PIN n_d[244]
    DIRECTION OUTPUT ;
    USE SIGNAL ;
    PORT
      LAYER M5 ;
        RECT  108.336 0 108.36 0.084 ;
    END
  END n_d[244]
  PIN n_d[245]
    DIRECTION OUTPUT ;
    USE SIGNAL ;
    PORT
      LAYER M5 ;
        RECT  108.768 0 108.792 0.084 ;
    END
  END n_d[245]
  PIN n_d[246]
    DIRECTION OUTPUT ;
    USE SIGNAL ;
    PORT
      LAYER M5 ;
        RECT  109.2 0 109.224 0.084 ;
    END
  END n_d[246]
  PIN n_d[247]
    DIRECTION OUTPUT ;
    USE SIGNAL ;
    PORT
      LAYER M5 ;
        RECT  109.632 0 109.656 0.084 ;
    END
  END n_d[247]
  PIN n_d[248]
    DIRECTION OUTPUT ;
    USE SIGNAL ;
    PORT
      LAYER M5 ;
        RECT  110.064 0 110.088 0.084 ;
    END
  END n_d[248]
  PIN n_d[249]
    DIRECTION OUTPUT ;
    USE SIGNAL ;
    PORT
      LAYER M5 ;
        RECT  110.496 0 110.52 0.084 ;
    END
  END n_d[249]
  PIN n_d[24]
    DIRECTION OUTPUT ;
    USE SIGNAL ;
    PORT
      LAYER M5 ;
        RECT  11.616 0 11.64 0.084 ;
    END
  END n_d[24]
  PIN n_d[250]
    DIRECTION OUTPUT ;
    USE SIGNAL ;
    PORT
      LAYER M5 ;
        RECT  110.928 0 110.952 0.084 ;
    END
  END n_d[250]
  PIN n_d[251]
    DIRECTION OUTPUT ;
    USE SIGNAL ;
    PORT
      LAYER M5 ;
        RECT  111.36 0 111.384 0.084 ;
    END
  END n_d[251]
  PIN n_d[252]
    DIRECTION OUTPUT ;
    USE SIGNAL ;
    PORT
      LAYER M5 ;
        RECT  111.792 0 111.816 0.084 ;
    END
  END n_d[252]
  PIN n_d[253]
    DIRECTION OUTPUT ;
    USE SIGNAL ;
    PORT
      LAYER M5 ;
        RECT  112.224 0 112.248 0.084 ;
    END
  END n_d[253]
  PIN n_d[254]
    DIRECTION OUTPUT ;
    USE SIGNAL ;
    PORT
      LAYER M5 ;
        RECT  112.656 0 112.68 0.084 ;
    END
  END n_d[254]
  PIN n_d[255]
    DIRECTION OUTPUT ;
    USE SIGNAL ;
    PORT
      LAYER M5 ;
        RECT  113.136 0 113.16 0.084 ;
    END
  END n_d[255]
  PIN n_d[25]
    DIRECTION OUTPUT ;
    USE SIGNAL ;
    PORT
      LAYER M5 ;
        RECT  12.048 0 12.072 0.084 ;
    END
  END n_d[25]
  PIN n_d[26]
    DIRECTION OUTPUT ;
    USE SIGNAL ;
    PORT
      LAYER M5 ;
        RECT  12.528 0 12.552 0.084 ;
    END
  END n_d[26]
  PIN n_d[27]
    DIRECTION OUTPUT ;
    USE SIGNAL ;
    PORT
      LAYER M5 ;
        RECT  12.96 0 12.984 0.084 ;
    END
  END n_d[27]
  PIN n_d[28]
    DIRECTION OUTPUT ;
    USE SIGNAL ;
    PORT
      LAYER M5 ;
        RECT  13.392 0 13.416 0.084 ;
    END
  END n_d[28]
  PIN n_d[29]
    DIRECTION OUTPUT ;
    USE SIGNAL ;
    PORT
      LAYER M5 ;
        RECT  13.824 0 13.848 0.084 ;
    END
  END n_d[29]
  PIN n_d[2]
    DIRECTION OUTPUT ;
    USE SIGNAL ;
    PORT
      LAYER M5 ;
        RECT  1.968 0 1.992 0.084 ;
    END
  END n_d[2]
  PIN n_d[30]
    DIRECTION OUTPUT ;
    USE SIGNAL ;
    PORT
      LAYER M5 ;
        RECT  14.256 0 14.28 0.084 ;
    END
  END n_d[30]
  PIN n_d[31]
    DIRECTION OUTPUT ;
    USE SIGNAL ;
    PORT
      LAYER M5 ;
        RECT  14.688 0 14.712 0.084 ;
    END
  END n_d[31]
  PIN n_d[32]
    DIRECTION OUTPUT ;
    USE SIGNAL ;
    PORT
      LAYER M5 ;
        RECT  15.168 0 15.192 0.084 ;
    END
  END n_d[32]
  PIN n_d[33]
    DIRECTION OUTPUT ;
    USE SIGNAL ;
    PORT
      LAYER M5 ;
        RECT  15.6 0 15.624 0.084 ;
    END
  END n_d[33]
  PIN n_d[34]
    DIRECTION OUTPUT ;
    USE SIGNAL ;
    PORT
      LAYER M5 ;
        RECT  16.032 0 16.056 0.084 ;
    END
  END n_d[34]
  PIN n_d[35]
    DIRECTION OUTPUT ;
    USE SIGNAL ;
    PORT
      LAYER M5 ;
        RECT  16.464 0 16.488 0.084 ;
    END
  END n_d[35]
  PIN n_d[36]
    DIRECTION OUTPUT ;
    USE SIGNAL ;
    PORT
      LAYER M5 ;
        RECT  16.896 0 16.92 0.084 ;
    END
  END n_d[36]
  PIN n_d[37]
    DIRECTION OUTPUT ;
    USE SIGNAL ;
    PORT
      LAYER M5 ;
        RECT  17.328 0 17.352 0.084 ;
    END
  END n_d[37]
  PIN n_d[38]
    DIRECTION OUTPUT ;
    USE SIGNAL ;
    PORT
      LAYER M5 ;
        RECT  17.76 0 17.784 0.084 ;
    END
  END n_d[38]
  PIN n_d[39]
    DIRECTION OUTPUT ;
    USE SIGNAL ;
    PORT
      LAYER M5 ;
        RECT  18.24 0 18.264 0.084 ;
    END
  END n_d[39]
  PIN n_d[3]
    DIRECTION OUTPUT ;
    USE SIGNAL ;
    PORT
      LAYER M5 ;
        RECT  2.4 0 2.424 0.084 ;
    END
  END n_d[3]
  PIN n_d[40]
    DIRECTION OUTPUT ;
    USE SIGNAL ;
    PORT
      LAYER M5 ;
        RECT  18.672 0 18.696 0.084 ;
    END
  END n_d[40]
  PIN n_d[41]
    DIRECTION OUTPUT ;
    USE SIGNAL ;
    PORT
      LAYER M5 ;
        RECT  19.104 0 19.128 0.084 ;
    END
  END n_d[41]
  PIN n_d[42]
    DIRECTION OUTPUT ;
    USE SIGNAL ;
    PORT
      LAYER M5 ;
        RECT  19.536 0 19.56 0.084 ;
    END
  END n_d[42]
  PIN n_d[43]
    DIRECTION OUTPUT ;
    USE SIGNAL ;
    PORT
      LAYER M5 ;
        RECT  19.968 0 19.992 0.084 ;
    END
  END n_d[43]
  PIN n_d[44]
    DIRECTION OUTPUT ;
    USE SIGNAL ;
    PORT
      LAYER M5 ;
        RECT  20.4 0 20.424 0.084 ;
    END
  END n_d[44]
  PIN n_d[45]
    DIRECTION OUTPUT ;
    USE SIGNAL ;
    PORT
      LAYER M5 ;
        RECT  20.928 0 20.952 0.084 ;
    END
  END n_d[45]
  PIN n_d[46]
    DIRECTION OUTPUT ;
    USE SIGNAL ;
    PORT
      LAYER M5 ;
        RECT  21.36 0 21.384 0.084 ;
    END
  END n_d[46]
  PIN n_d[47]
    DIRECTION OUTPUT ;
    USE SIGNAL ;
    PORT
      LAYER M5 ;
        RECT  21.792 0 21.816 0.084 ;
    END
  END n_d[47]
  PIN n_d[48]
    DIRECTION OUTPUT ;
    USE SIGNAL ;
    PORT
      LAYER M5 ;
        RECT  22.224 0 22.248 0.084 ;
    END
  END n_d[48]
  PIN n_d[49]
    DIRECTION OUTPUT ;
    USE SIGNAL ;
    PORT
      LAYER M5 ;
        RECT  22.656 0 22.68 0.084 ;
    END
  END n_d[49]
  PIN n_d[4]
    DIRECTION OUTPUT ;
    USE SIGNAL ;
    PORT
      LAYER M5 ;
        RECT  2.832 0 2.856 0.084 ;
    END
  END n_d[4]
  PIN n_d[50]
    DIRECTION OUTPUT ;
    USE SIGNAL ;
    PORT
      LAYER M5 ;
        RECT  23.088 0 23.112 0.084 ;
    END
  END n_d[50]
  PIN n_d[51]
    DIRECTION OUTPUT ;
    USE SIGNAL ;
    PORT
      LAYER M5 ;
        RECT  23.52 0 23.544 0.084 ;
    END
  END n_d[51]
  PIN n_d[52]
    DIRECTION OUTPUT ;
    USE SIGNAL ;
    PORT
      LAYER M5 ;
        RECT  23.952 0 23.976 0.084 ;
    END
  END n_d[52]
  PIN n_d[53]
    DIRECTION OUTPUT ;
    USE SIGNAL ;
    PORT
      LAYER M5 ;
        RECT  24.384 0 24.408 0.084 ;
    END
  END n_d[53]
  PIN n_d[54]
    DIRECTION OUTPUT ;
    USE SIGNAL ;
    PORT
      LAYER M5 ;
        RECT  24.816 0 24.84 0.084 ;
    END
  END n_d[54]
  PIN n_d[55]
    DIRECTION OUTPUT ;
    USE SIGNAL ;
    PORT
      LAYER M5 ;
        RECT  25.248 0 25.272 0.084 ;
    END
  END n_d[55]
  PIN n_d[56]
    DIRECTION OUTPUT ;
    USE SIGNAL ;
    PORT
      LAYER M5 ;
        RECT  25.68 0 25.704 0.084 ;
    END
  END n_d[56]
  PIN n_d[57]
    DIRECTION OUTPUT ;
    USE SIGNAL ;
    PORT
      LAYER M5 ;
        RECT  26.112 0 26.136 0.084 ;
    END
  END n_d[57]
  PIN n_d[58]
    DIRECTION OUTPUT ;
    USE SIGNAL ;
    PORT
      LAYER M5 ;
        RECT  26.544 0 26.568 0.084 ;
    END
  END n_d[58]
  PIN n_d[59]
    DIRECTION OUTPUT ;
    USE SIGNAL ;
    PORT
      LAYER M5 ;
        RECT  27.024 0 27.048 0.084 ;
    END
  END n_d[59]
  PIN n_d[5]
    DIRECTION OUTPUT ;
    USE SIGNAL ;
    PORT
      LAYER M5 ;
        RECT  3.264 0 3.288 0.084 ;
    END
  END n_d[5]
  PIN n_d[60]
    DIRECTION OUTPUT ;
    USE SIGNAL ;
    PORT
      LAYER M5 ;
        RECT  27.456 0 27.48 0.084 ;
    END
  END n_d[60]
  PIN n_d[61]
    DIRECTION OUTPUT ;
    USE SIGNAL ;
    PORT
      LAYER M5 ;
        RECT  27.888 0 27.912 0.084 ;
    END
  END n_d[61]
  PIN n_d[62]
    DIRECTION OUTPUT ;
    USE SIGNAL ;
    PORT
      LAYER M5 ;
        RECT  28.32 0 28.344 0.084 ;
    END
  END n_d[62]
  PIN n_d[63]
    DIRECTION OUTPUT ;
    USE SIGNAL ;
    PORT
      LAYER M5 ;
        RECT  28.752 0 28.776 0.084 ;
    END
  END n_d[63]
  PIN n_d[64]
    DIRECTION OUTPUT ;
    USE SIGNAL ;
    PORT
      LAYER M5 ;
        RECT  29.184 0 29.208 0.084 ;
    END
  END n_d[64]
  PIN n_d[65]
    DIRECTION OUTPUT ;
    USE SIGNAL ;
    PORT
      LAYER M5 ;
        RECT  29.664 0 29.688 0.084 ;
    END
  END n_d[65]
  PIN n_d[66]
    DIRECTION OUTPUT ;
    USE SIGNAL ;
    PORT
      LAYER M5 ;
        RECT  30.096 0 30.12 0.084 ;
    END
  END n_d[66]
  PIN n_d[67]
    DIRECTION OUTPUT ;
    USE SIGNAL ;
    PORT
      LAYER M5 ;
        RECT  30.528 0 30.552 0.084 ;
    END
  END n_d[67]
  PIN n_d[68]
    DIRECTION OUTPUT ;
    USE SIGNAL ;
    PORT
      LAYER M5 ;
        RECT  30.96 0 30.984 0.084 ;
    END
  END n_d[68]
  PIN n_d[69]
    DIRECTION OUTPUT ;
    USE SIGNAL ;
    PORT
      LAYER M5 ;
        RECT  31.392 0 31.416 0.084 ;
    END
  END n_d[69]
  PIN n_d[6]
    DIRECTION OUTPUT ;
    USE SIGNAL ;
    PORT
      LAYER M5 ;
        RECT  3.744 0 3.768 0.084 ;
    END
  END n_d[6]
  PIN n_d[70]
    DIRECTION OUTPUT ;
    USE SIGNAL ;
    PORT
      LAYER M5 ;
        RECT  31.824 0 31.848 0.084 ;
    END
  END n_d[70]
  PIN n_d[71]
    DIRECTION OUTPUT ;
    USE SIGNAL ;
    PORT
      LAYER M5 ;
        RECT  32.256 0 32.28 0.084 ;
    END
  END n_d[71]
  PIN n_d[72]
    DIRECTION OUTPUT ;
    USE SIGNAL ;
    PORT
      LAYER M5 ;
        RECT  32.736 0 32.76 0.084 ;
    END
  END n_d[72]
  PIN n_d[73]
    DIRECTION OUTPUT ;
    USE SIGNAL ;
    PORT
      LAYER M5 ;
        RECT  33.168 0 33.192 0.084 ;
    END
  END n_d[73]
  PIN n_d[74]
    DIRECTION OUTPUT ;
    USE SIGNAL ;
    PORT
      LAYER M5 ;
        RECT  33.6 0 33.624 0.084 ;
    END
  END n_d[74]
  PIN n_d[75]
    DIRECTION OUTPUT ;
    USE SIGNAL ;
    PORT
      LAYER M5 ;
        RECT  34.032 0 34.056 0.084 ;
    END
  END n_d[75]
  PIN n_d[76]
    DIRECTION OUTPUT ;
    USE SIGNAL ;
    PORT
      LAYER M5 ;
        RECT  34.464 0 34.488 0.084 ;
    END
  END n_d[76]
  PIN n_d[77]
    DIRECTION OUTPUT ;
    USE SIGNAL ;
    PORT
      LAYER M5 ;
        RECT  34.896 0 34.92 0.084 ;
    END
  END n_d[77]
  PIN n_d[78]
    DIRECTION OUTPUT ;
    USE SIGNAL ;
    PORT
      LAYER M5 ;
        RECT  35.376 0 35.4 0.084 ;
    END
  END n_d[78]
  PIN n_d[79]
    DIRECTION OUTPUT ;
    USE SIGNAL ;
    PORT
      LAYER M5 ;
        RECT  35.808 0 35.832 0.084 ;
    END
  END n_d[79]
  PIN n_d[7]
    DIRECTION OUTPUT ;
    USE SIGNAL ;
    PORT
      LAYER M5 ;
        RECT  4.176 0 4.2 0.084 ;
    END
  END n_d[7]
  PIN n_d[80]
    DIRECTION OUTPUT ;
    USE SIGNAL ;
    PORT
      LAYER M5 ;
        RECT  36.24 0 36.264 0.084 ;
    END
  END n_d[80]
  PIN n_d[81]
    DIRECTION OUTPUT ;
    USE SIGNAL ;
    PORT
      LAYER M5 ;
        RECT  36.672 0 36.696 0.084 ;
    END
  END n_d[81]
  PIN n_d[82]
    DIRECTION OUTPUT ;
    USE SIGNAL ;
    PORT
      LAYER M5 ;
        RECT  37.104 0 37.128 0.084 ;
    END
  END n_d[82]
  PIN n_d[83]
    DIRECTION OUTPUT ;
    USE SIGNAL ;
    PORT
      LAYER M5 ;
        RECT  37.536 0 37.56 0.084 ;
    END
  END n_d[83]
  PIN n_d[84]
    DIRECTION OUTPUT ;
    USE SIGNAL ;
    PORT
      LAYER M5 ;
        RECT  37.968 0 37.992 0.084 ;
    END
  END n_d[84]
  PIN n_d[85]
    DIRECTION OUTPUT ;
    USE SIGNAL ;
    PORT
      LAYER M5 ;
        RECT  38.448 0 38.472 0.084 ;
    END
  END n_d[85]
  PIN n_d[86]
    DIRECTION OUTPUT ;
    USE SIGNAL ;
    PORT
      LAYER M5 ;
        RECT  38.88 0 38.904 0.084 ;
    END
  END n_d[86]
  PIN n_d[87]
    DIRECTION OUTPUT ;
    USE SIGNAL ;
    PORT
      LAYER M5 ;
        RECT  39.312 0 39.336 0.084 ;
    END
  END n_d[87]
  PIN n_d[88]
    DIRECTION OUTPUT ;
    USE SIGNAL ;
    PORT
      LAYER M5 ;
        RECT  39.744 0 39.768 0.084 ;
    END
  END n_d[88]
  PIN n_d[89]
    DIRECTION OUTPUT ;
    USE SIGNAL ;
    PORT
      LAYER M5 ;
        RECT  40.176 0 40.2 0.084 ;
    END
  END n_d[89]
  PIN n_d[8]
    DIRECTION OUTPUT ;
    USE SIGNAL ;
    PORT
      LAYER M5 ;
        RECT  4.608 0 4.632 0.084 ;
    END
  END n_d[8]
  PIN n_d[90]
    DIRECTION OUTPUT ;
    USE SIGNAL ;
    PORT
      LAYER M5 ;
        RECT  40.608 0 40.632 0.084 ;
    END
  END n_d[90]
  PIN n_d[91]
    DIRECTION OUTPUT ;
    USE SIGNAL ;
    PORT
      LAYER M5 ;
        RECT  41.136 0 41.16 0.084 ;
    END
  END n_d[91]
  PIN n_d[92]
    DIRECTION OUTPUT ;
    USE SIGNAL ;
    PORT
      LAYER M5 ;
        RECT  41.568 0 41.592 0.084 ;
    END
  END n_d[92]
  PIN n_d[93]
    DIRECTION OUTPUT ;
    USE SIGNAL ;
    PORT
      LAYER M5 ;
        RECT  42 0 42.024 0.084 ;
    END
  END n_d[93]
  PIN n_d[94]
    DIRECTION OUTPUT ;
    USE SIGNAL ;
    PORT
      LAYER M5 ;
        RECT  42.432 0 42.456 0.084 ;
    END
  END n_d[94]
  PIN n_d[95]
    DIRECTION OUTPUT ;
    USE SIGNAL ;
    PORT
      LAYER M5 ;
        RECT  42.864 0 42.888 0.084 ;
    END
  END n_d[95]
  PIN n_d[96]
    DIRECTION OUTPUT ;
    USE SIGNAL ;
    PORT
      LAYER M5 ;
        RECT  43.296 0 43.32 0.084 ;
    END
  END n_d[96]
  PIN n_d[97]
    DIRECTION OUTPUT ;
    USE SIGNAL ;
    PORT
      LAYER M5 ;
        RECT  43.728 0 43.752 0.084 ;
    END
  END n_d[97]
  PIN n_d[98]
    DIRECTION OUTPUT ;
    USE SIGNAL ;
    PORT
      LAYER M5 ;
        RECT  44.16 0 44.184 0.084 ;
    END
  END n_d[98]
  PIN n_d[99]
    DIRECTION OUTPUT ;
    USE SIGNAL ;
    PORT
      LAYER M5 ;
        RECT  44.592 0 44.616 0.084 ;
    END
  END n_d[99]
  PIN n_d[9]
    DIRECTION OUTPUT ;
    USE SIGNAL ;
    PORT
      LAYER M5 ;
        RECT  5.04 0 5.064 0.084 ;
    END
  END n_d[9]
  PIN n_lane[0]
    DIRECTION OUTPUT ;
    USE SIGNAL ;
    PORT
      LAYER M5 ;
        RECT  113.568 0 113.592 0.084 ;
    END
  END n_lane[0]
  PIN n_lane[1]
    DIRECTION OUTPUT ;
    USE SIGNAL ;
    PORT
      LAYER M5 ;
        RECT  114 0 114.024 0.084 ;
    END
  END n_lane[1]
  PIN n_lane[2]
    DIRECTION OUTPUT ;
    USE SIGNAL ;
    PORT
      LAYER M5 ;
        RECT  114.432 0 114.456 0.084 ;
    END
  END n_lane[2]
  PIN n_sec[0]
    DIRECTION OUTPUT ;
    USE SIGNAL ;
    PORT
      LAYER M5 ;
        RECT  114.864 0 114.888 0.084 ;
    END
  END n_sec[0]
  PIN n_sec[10]
    DIRECTION OUTPUT ;
    USE SIGNAL ;
    PORT
      LAYER M5 ;
        RECT  119.28 0 119.304 0.084 ;
    END
  END n_sec[10]
  PIN n_sec[11]
    DIRECTION OUTPUT ;
    USE SIGNAL ;
    PORT
      LAYER M5 ;
        RECT  119.712 0 119.736 0.084 ;
    END
  END n_sec[11]
  PIN n_sec[12]
    DIRECTION OUTPUT ;
    USE SIGNAL ;
    PORT
      LAYER M5 ;
        RECT  120.144 0 120.168 0.084 ;
    END
  END n_sec[12]
  PIN n_sec[13]
    DIRECTION OUTPUT ;
    USE SIGNAL ;
    PORT
      LAYER M5 ;
        RECT  120.576 0 120.6 0.084 ;
    END
  END n_sec[13]
  PIN n_sec[14]
    DIRECTION OUTPUT ;
    USE SIGNAL ;
    PORT
      LAYER M5 ;
        RECT  121.008 0 121.032 0.084 ;
    END
  END n_sec[14]
  PIN n_sec[15]
    DIRECTION OUTPUT ;
    USE SIGNAL ;
    PORT
      LAYER M5 ;
        RECT  121.44 0 121.464 0.084 ;
    END
  END n_sec[15]
  PIN n_sec[16]
    DIRECTION OUTPUT ;
    USE SIGNAL ;
    PORT
      LAYER M5 ;
        RECT  121.92 0 121.944 0.084 ;
    END
  END n_sec[16]
  PIN n_sec[17]
    DIRECTION OUTPUT ;
    USE SIGNAL ;
    PORT
      LAYER M5 ;
        RECT  122.352 0 122.376 0.084 ;
    END
  END n_sec[17]
  PIN n_sec[18]
    DIRECTION OUTPUT ;
    USE SIGNAL ;
    PORT
      LAYER M5 ;
        RECT  122.784 0 122.808 0.084 ;
    END
  END n_sec[18]
  PIN n_sec[19]
    DIRECTION OUTPUT ;
    USE SIGNAL ;
    PORT
      LAYER M5 ;
        RECT  123.216 0 123.24 0.084 ;
    END
  END n_sec[19]
  PIN n_sec[1]
    DIRECTION OUTPUT ;
    USE SIGNAL ;
    PORT
      LAYER M5 ;
        RECT  115.296 0 115.32 0.084 ;
    END
  END n_sec[1]
  PIN n_sec[20]
    DIRECTION OUTPUT ;
    USE SIGNAL ;
    PORT
      LAYER M5 ;
        RECT  123.648 0 123.672 0.084 ;
    END
  END n_sec[20]
  PIN n_sec[21]
    DIRECTION OUTPUT ;
    USE SIGNAL ;
    PORT
      LAYER M5 ;
        RECT  124.08 0 124.104 0.084 ;
    END
  END n_sec[21]
  PIN n_sec[22]
    DIRECTION OUTPUT ;
    USE SIGNAL ;
    PORT
      LAYER M5 ;
        RECT  124.56 0 124.584 0.084 ;
    END
  END n_sec[22]
  PIN n_sec[23]
    DIRECTION OUTPUT ;
    USE SIGNAL ;
    PORT
      LAYER M5 ;
        RECT  124.992 0 125.016 0.084 ;
    END
  END n_sec[23]
  PIN n_sec[2]
    DIRECTION OUTPUT ;
    USE SIGNAL ;
    PORT
      LAYER M5 ;
        RECT  115.728 0 115.752 0.084 ;
    END
  END n_sec[2]
  PIN n_sec[3]
    DIRECTION OUTPUT ;
    USE SIGNAL ;
    PORT
      LAYER M5 ;
        RECT  116.208 0 116.232 0.084 ;
    END
  END n_sec[3]
  PIN n_sec[4]
    DIRECTION OUTPUT ;
    USE SIGNAL ;
    PORT
      LAYER M5 ;
        RECT  116.64 0 116.664 0.084 ;
    END
  END n_sec[4]
  PIN n_sec[5]
    DIRECTION OUTPUT ;
    USE SIGNAL ;
    PORT
      LAYER M5 ;
        RECT  117.072 0 117.096 0.084 ;
    END
  END n_sec[5]
  PIN n_sec[6]
    DIRECTION OUTPUT ;
    USE SIGNAL ;
    PORT
      LAYER M5 ;
        RECT  117.504 0 117.528 0.084 ;
    END
  END n_sec[6]
  PIN n_sec[7]
    DIRECTION OUTPUT ;
    USE SIGNAL ;
    PORT
      LAYER M5 ;
        RECT  117.936 0 117.96 0.084 ;
    END
  END n_sec[7]
  PIN n_sec[8]
    DIRECTION OUTPUT ;
    USE SIGNAL ;
    PORT
      LAYER M5 ;
        RECT  118.368 0 118.392 0.084 ;
    END
  END n_sec[8]
  PIN n_sec[9]
    DIRECTION OUTPUT ;
    USE SIGNAL ;
    PORT
      LAYER M5 ;
        RECT  118.848 0 118.872 0.084 ;
    END
  END n_sec[9]
  PIN n_tag[0]
    DIRECTION OUTPUT ;
    USE SIGNAL ;
    PORT
      LAYER M5 ;
        RECT  125.424 0 125.448 0.084 ;
    END
  END n_tag[0]
  PIN n_tag[1]
    DIRECTION OUTPUT ;
    USE SIGNAL ;
    PORT
      LAYER M5 ;
        RECT  125.856 0 125.88 0.084 ;
    END
  END n_tag[1]
  PIN n_tag[2]
    DIRECTION OUTPUT ;
    USE SIGNAL ;
    PORT
      LAYER M5 ;
        RECT  126.288 0 126.312 0.084 ;
    END
  END n_tag[2]
  PIN n_tag[3]
    DIRECTION OUTPUT ;
    USE SIGNAL ;
    PORT
      LAYER M5 ;
        RECT  126.72 0 126.744 0.084 ;
    END
  END n_tag[3]
  PIN n_tag[4]
    DIRECTION OUTPUT ;
    USE SIGNAL ;
    PORT
      LAYER M5 ;
        RECT  127.152 0 127.176 0.084 ;
    END
  END n_tag[4]
  PIN n_tag[5]
    DIRECTION OUTPUT ;
    USE SIGNAL ;
    PORT
      LAYER M5 ;
        RECT  127.68 0 127.704 0.084 ;
    END
  END n_tag[5]
  PIN n_tag[6]
    DIRECTION OUTPUT ;
    USE SIGNAL ;
    PORT
      LAYER M5 ;
        RECT  128.112 0 128.136 0.084 ;
    END
  END n_tag[6]
  PIN n_tag[7]
    DIRECTION OUTPUT ;
    USE SIGNAL ;
    PORT
      LAYER M5 ;
        RECT  128.544 0 128.568 0.084 ;
    END
  END n_tag[7]
  PIN n_tag[8]
    DIRECTION OUTPUT ;
    USE SIGNAL ;
    PORT
      LAYER M5 ;
        RECT  128.976 0 129 0.084 ;
    END
  END n_tag[8]
  PIN n_v
    DIRECTION OUTPUT ;
    USE SIGNAL ;
    PORT
      LAYER M5 ;
        RECT  129.408 0 129.432 0.084 ;
    END
  END n_v
  PIN rst_n
    DIRECTION INPUT ;
    USE SIGNAL ;
    PORT
      LAYER M4 ;
        RECT  129.516 94.224 129.6 94.248 ;
    END
  END rst_n
  PIN w_data[0]
    DIRECTION OUTPUT ;
    USE SIGNAL ;
    PORT
      LAYER M5 ;
        RECT  0.192 0 0.216 0.084 ;
    END
  END w_data[0]
  PIN w_data[100]
    DIRECTION OUTPUT ;
    USE SIGNAL ;
    PORT
      LAYER M5 ;
        RECT  43.248 0 43.272 0.084 ;
    END
  END w_data[100]
  PIN w_data[101]
    DIRECTION OUTPUT ;
    USE SIGNAL ;
    PORT
      LAYER M5 ;
        RECT  43.68 0 43.704 0.084 ;
    END
  END w_data[101]
  PIN w_data[102]
    DIRECTION OUTPUT ;
    USE SIGNAL ;
    PORT
      LAYER M5 ;
        RECT  44.112 0 44.136 0.084 ;
    END
  END w_data[102]
  PIN w_data[103]
    DIRECTION OUTPUT ;
    USE SIGNAL ;
    PORT
      LAYER M5 ;
        RECT  44.544 0 44.568 0.084 ;
    END
  END w_data[103]
  PIN w_data[104]
    DIRECTION OUTPUT ;
    USE SIGNAL ;
    PORT
      LAYER M5 ;
        RECT  44.976 0 45 0.084 ;
    END
  END w_data[104]
  PIN w_data[105]
    DIRECTION OUTPUT ;
    USE SIGNAL ;
    PORT
      LAYER M5 ;
        RECT  45.408 0 45.432 0.084 ;
    END
  END w_data[105]
  PIN w_data[106]
    DIRECTION OUTPUT ;
    USE SIGNAL ;
    PORT
      LAYER M5 ;
        RECT  45.84 0 45.864 0.084 ;
    END
  END w_data[106]
  PIN w_data[107]
    DIRECTION OUTPUT ;
    USE SIGNAL ;
    PORT
      LAYER M5 ;
        RECT  46.272 0 46.296 0.084 ;
    END
  END w_data[107]
  PIN w_data[108]
    DIRECTION OUTPUT ;
    USE SIGNAL ;
    PORT
      LAYER M5 ;
        RECT  46.704 0 46.728 0.084 ;
    END
  END w_data[108]
  PIN w_data[109]
    DIRECTION OUTPUT ;
    USE SIGNAL ;
    PORT
      LAYER M5 ;
        RECT  47.136 0 47.16 0.084 ;
    END
  END w_data[109]
  PIN w_data[10]
    DIRECTION OUTPUT ;
    USE SIGNAL ;
    PORT
      LAYER M5 ;
        RECT  4.512 0 4.536 0.084 ;
    END
  END w_data[10]
  PIN w_data[110]
    DIRECTION OUTPUT ;
    USE SIGNAL ;
    PORT
      LAYER M5 ;
        RECT  47.568 0 47.592 0.084 ;
    END
  END w_data[110]
  PIN w_data[111]
    DIRECTION OUTPUT ;
    USE SIGNAL ;
    PORT
      LAYER M5 ;
        RECT  48 0 48.024 0.084 ;
    END
  END w_data[111]
  PIN w_data[112]
    DIRECTION OUTPUT ;
    USE SIGNAL ;
    PORT
      LAYER M5 ;
        RECT  48.432 0 48.456 0.084 ;
    END
  END w_data[112]
  PIN w_data[113]
    DIRECTION OUTPUT ;
    USE SIGNAL ;
    PORT
      LAYER M5 ;
        RECT  48.864 0 48.888 0.084 ;
    END
  END w_data[113]
  PIN w_data[114]
    DIRECTION OUTPUT ;
    USE SIGNAL ;
    PORT
      LAYER M5 ;
        RECT  49.296 0 49.32 0.084 ;
    END
  END w_data[114]
  PIN w_data[115]
    DIRECTION OUTPUT ;
    USE SIGNAL ;
    PORT
      LAYER M5 ;
        RECT  49.728 0 49.752 0.084 ;
    END
  END w_data[115]
  PIN w_data[116]
    DIRECTION OUTPUT ;
    USE SIGNAL ;
    PORT
      LAYER M5 ;
        RECT  50.16 0 50.184 0.084 ;
    END
  END w_data[116]
  PIN w_data[117]
    DIRECTION OUTPUT ;
    USE SIGNAL ;
    PORT
      LAYER M5 ;
        RECT  50.592 0 50.616 0.084 ;
    END
  END w_data[117]
  PIN w_data[118]
    DIRECTION OUTPUT ;
    USE SIGNAL ;
    PORT
      LAYER M5 ;
        RECT  51.024 0 51.048 0.084 ;
    END
  END w_data[118]
  PIN w_data[119]
    DIRECTION OUTPUT ;
    USE SIGNAL ;
    PORT
      LAYER M5 ;
        RECT  51.456 0 51.48 0.084 ;
    END
  END w_data[119]
  PIN w_data[11]
    DIRECTION OUTPUT ;
    USE SIGNAL ;
    PORT
      LAYER M5 ;
        RECT  4.944 0 4.968 0.084 ;
    END
  END w_data[11]
  PIN w_data[120]
    DIRECTION OUTPUT ;
    USE SIGNAL ;
    PORT
      LAYER M5 ;
        RECT  51.888 0 51.912 0.084 ;
    END
  END w_data[120]
  PIN w_data[121]
    DIRECTION OUTPUT ;
    USE SIGNAL ;
    PORT
      LAYER M5 ;
        RECT  52.32 0 52.344 0.084 ;
    END
  END w_data[121]
  PIN w_data[122]
    DIRECTION OUTPUT ;
    USE SIGNAL ;
    PORT
      LAYER M5 ;
        RECT  52.752 0 52.776 0.084 ;
    END
  END w_data[122]
  PIN w_data[123]
    DIRECTION OUTPUT ;
    USE SIGNAL ;
    PORT
      LAYER M5 ;
        RECT  53.184 0 53.208 0.084 ;
    END
  END w_data[123]
  PIN w_data[124]
    DIRECTION OUTPUT ;
    USE SIGNAL ;
    PORT
      LAYER M5 ;
        RECT  53.616 0 53.64 0.084 ;
    END
  END w_data[124]
  PIN w_data[125]
    DIRECTION OUTPUT ;
    USE SIGNAL ;
    PORT
      LAYER M5 ;
        RECT  54.048 0 54.072 0.084 ;
    END
  END w_data[125]
  PIN w_data[126]
    DIRECTION OUTPUT ;
    USE SIGNAL ;
    PORT
      LAYER M5 ;
        RECT  54.432 0 54.456 0.084 ;
    END
  END w_data[126]
  PIN w_data[127]
    DIRECTION OUTPUT ;
    USE SIGNAL ;
    PORT
      LAYER M5 ;
        RECT  54.864 0 54.888 0.084 ;
    END
  END w_data[127]
  PIN w_data[128]
    DIRECTION OUTPUT ;
    USE SIGNAL ;
    PORT
      LAYER M5 ;
        RECT  55.296 0 55.32 0.084 ;
    END
  END w_data[128]
  PIN w_data[129]
    DIRECTION OUTPUT ;
    USE SIGNAL ;
    PORT
      LAYER M5 ;
        RECT  55.728 0 55.752 0.084 ;
    END
  END w_data[129]
  PIN w_data[12]
    DIRECTION OUTPUT ;
    USE SIGNAL ;
    PORT
      LAYER M5 ;
        RECT  5.376 0 5.4 0.084 ;
    END
  END w_data[12]
  PIN w_data[130]
    DIRECTION OUTPUT ;
    USE SIGNAL ;
    PORT
      LAYER M5 ;
        RECT  56.16 0 56.184 0.084 ;
    END
  END w_data[130]
  PIN w_data[131]
    DIRECTION OUTPUT ;
    USE SIGNAL ;
    PORT
      LAYER M5 ;
        RECT  56.592 0 56.616 0.084 ;
    END
  END w_data[131]
  PIN w_data[132]
    DIRECTION OUTPUT ;
    USE SIGNAL ;
    PORT
      LAYER M5 ;
        RECT  57.024 0 57.048 0.084 ;
    END
  END w_data[132]
  PIN w_data[133]
    DIRECTION OUTPUT ;
    USE SIGNAL ;
    PORT
      LAYER M5 ;
        RECT  57.456 0 57.48 0.084 ;
    END
  END w_data[133]
  PIN w_data[134]
    DIRECTION OUTPUT ;
    USE SIGNAL ;
    PORT
      LAYER M5 ;
        RECT  57.888 0 57.912 0.084 ;
    END
  END w_data[134]
  PIN w_data[135]
    DIRECTION OUTPUT ;
    USE SIGNAL ;
    PORT
      LAYER M5 ;
        RECT  58.32 0 58.344 0.084 ;
    END
  END w_data[135]
  PIN w_data[136]
    DIRECTION OUTPUT ;
    USE SIGNAL ;
    PORT
      LAYER M5 ;
        RECT  58.752 0 58.776 0.084 ;
    END
  END w_data[136]
  PIN w_data[137]
    DIRECTION OUTPUT ;
    USE SIGNAL ;
    PORT
      LAYER M5 ;
        RECT  59.184 0 59.208 0.084 ;
    END
  END w_data[137]
  PIN w_data[138]
    DIRECTION OUTPUT ;
    USE SIGNAL ;
    PORT
      LAYER M5 ;
        RECT  59.616 0 59.64 0.084 ;
    END
  END w_data[138]
  PIN w_data[139]
    DIRECTION OUTPUT ;
    USE SIGNAL ;
    PORT
      LAYER M5 ;
        RECT  60.048 0 60.072 0.084 ;
    END
  END w_data[139]
  PIN w_data[13]
    DIRECTION OUTPUT ;
    USE SIGNAL ;
    PORT
      LAYER M5 ;
        RECT  5.808 0 5.832 0.084 ;
    END
  END w_data[13]
  PIN w_data[140]
    DIRECTION OUTPUT ;
    USE SIGNAL ;
    PORT
      LAYER M5 ;
        RECT  60.48 0 60.504 0.084 ;
    END
  END w_data[140]
  PIN w_data[141]
    DIRECTION OUTPUT ;
    USE SIGNAL ;
    PORT
      LAYER M5 ;
        RECT  60.912 0 60.936 0.084 ;
    END
  END w_data[141]
  PIN w_data[142]
    DIRECTION OUTPUT ;
    USE SIGNAL ;
    PORT
      LAYER M5 ;
        RECT  61.344 0 61.368 0.084 ;
    END
  END w_data[142]
  PIN w_data[143]
    DIRECTION OUTPUT ;
    USE SIGNAL ;
    PORT
      LAYER M5 ;
        RECT  61.776 0 61.8 0.084 ;
    END
  END w_data[143]
  PIN w_data[144]
    DIRECTION OUTPUT ;
    USE SIGNAL ;
    PORT
      LAYER M5 ;
        RECT  62.208 0 62.232 0.084 ;
    END
  END w_data[144]
  PIN w_data[145]
    DIRECTION OUTPUT ;
    USE SIGNAL ;
    PORT
      LAYER M5 ;
        RECT  62.64 0 62.664 0.084 ;
    END
  END w_data[145]
  PIN w_data[146]
    DIRECTION OUTPUT ;
    USE SIGNAL ;
    PORT
      LAYER M5 ;
        RECT  63.072 0 63.096 0.084 ;
    END
  END w_data[146]
  PIN w_data[147]
    DIRECTION OUTPUT ;
    USE SIGNAL ;
    PORT
      LAYER M5 ;
        RECT  63.504 0 63.528 0.084 ;
    END
  END w_data[147]
  PIN w_data[148]
    DIRECTION OUTPUT ;
    USE SIGNAL ;
    PORT
      LAYER M5 ;
        RECT  63.936 0 63.96 0.084 ;
    END
  END w_data[148]
  PIN w_data[149]
    DIRECTION OUTPUT ;
    USE SIGNAL ;
    PORT
      LAYER M5 ;
        RECT  64.368 0 64.392 0.084 ;
    END
  END w_data[149]
  PIN w_data[14]
    DIRECTION OUTPUT ;
    USE SIGNAL ;
    PORT
      LAYER M5 ;
        RECT  6.24 0 6.264 0.084 ;
    END
  END w_data[14]
  PIN w_data[150]
    DIRECTION OUTPUT ;
    USE SIGNAL ;
    PORT
      LAYER M5 ;
        RECT  64.8 0 64.824 0.084 ;
    END
  END w_data[150]
  PIN w_data[151]
    DIRECTION OUTPUT ;
    USE SIGNAL ;
    PORT
      LAYER M5 ;
        RECT  65.232 0 65.256 0.084 ;
    END
  END w_data[151]
  PIN w_data[152]
    DIRECTION OUTPUT ;
    USE SIGNAL ;
    PORT
      LAYER M5 ;
        RECT  65.664 0 65.688 0.084 ;
    END
  END w_data[152]
  PIN w_data[153]
    DIRECTION OUTPUT ;
    USE SIGNAL ;
    PORT
      LAYER M5 ;
        RECT  66.096 0 66.12 0.084 ;
    END
  END w_data[153]
  PIN w_data[154]
    DIRECTION OUTPUT ;
    USE SIGNAL ;
    PORT
      LAYER M5 ;
        RECT  66.528 0 66.552 0.084 ;
    END
  END w_data[154]
  PIN w_data[155]
    DIRECTION OUTPUT ;
    USE SIGNAL ;
    PORT
      LAYER M5 ;
        RECT  66.96 0 66.984 0.084 ;
    END
  END w_data[155]
  PIN w_data[156]
    DIRECTION OUTPUT ;
    USE SIGNAL ;
    PORT
      LAYER M5 ;
        RECT  67.392 0 67.416 0.084 ;
    END
  END w_data[156]
  PIN w_data[157]
    DIRECTION OUTPUT ;
    USE SIGNAL ;
    PORT
      LAYER M5 ;
        RECT  67.824 0 67.848 0.084 ;
    END
  END w_data[157]
  PIN w_data[158]
    DIRECTION OUTPUT ;
    USE SIGNAL ;
    PORT
      LAYER M5 ;
        RECT  68.256 0 68.28 0.084 ;
    END
  END w_data[158]
  PIN w_data[159]
    DIRECTION OUTPUT ;
    USE SIGNAL ;
    PORT
      LAYER M5 ;
        RECT  68.64 0 68.664 0.084 ;
    END
  END w_data[159]
  PIN w_data[15]
    DIRECTION OUTPUT ;
    USE SIGNAL ;
    PORT
      LAYER M5 ;
        RECT  6.672 0 6.696 0.084 ;
    END
  END w_data[15]
  PIN w_data[160]
    DIRECTION OUTPUT ;
    USE SIGNAL ;
    PORT
      LAYER M5 ;
        RECT  69.072 0 69.096 0.084 ;
    END
  END w_data[160]
  PIN w_data[161]
    DIRECTION OUTPUT ;
    USE SIGNAL ;
    PORT
      LAYER M5 ;
        RECT  69.504 0 69.528 0.084 ;
    END
  END w_data[161]
  PIN w_data[162]
    DIRECTION OUTPUT ;
    USE SIGNAL ;
    PORT
      LAYER M5 ;
        RECT  69.936 0 69.96 0.084 ;
    END
  END w_data[162]
  PIN w_data[163]
    DIRECTION OUTPUT ;
    USE SIGNAL ;
    PORT
      LAYER M5 ;
        RECT  70.368 0 70.392 0.084 ;
    END
  END w_data[163]
  PIN w_data[164]
    DIRECTION OUTPUT ;
    USE SIGNAL ;
    PORT
      LAYER M5 ;
        RECT  70.8 0 70.824 0.084 ;
    END
  END w_data[164]
  PIN w_data[165]
    DIRECTION OUTPUT ;
    USE SIGNAL ;
    PORT
      LAYER M5 ;
        RECT  71.232 0 71.256 0.084 ;
    END
  END w_data[165]
  PIN w_data[166]
    DIRECTION OUTPUT ;
    USE SIGNAL ;
    PORT
      LAYER M5 ;
        RECT  71.664 0 71.688 0.084 ;
    END
  END w_data[166]
  PIN w_data[167]
    DIRECTION OUTPUT ;
    USE SIGNAL ;
    PORT
      LAYER M5 ;
        RECT  72.096 0 72.12 0.084 ;
    END
  END w_data[167]
  PIN w_data[168]
    DIRECTION OUTPUT ;
    USE SIGNAL ;
    PORT
      LAYER M5 ;
        RECT  72.528 0 72.552 0.084 ;
    END
  END w_data[168]
  PIN w_data[169]
    DIRECTION OUTPUT ;
    USE SIGNAL ;
    PORT
      LAYER M5 ;
        RECT  72.96 0 72.984 0.084 ;
    END
  END w_data[169]
  PIN w_data[16]
    DIRECTION OUTPUT ;
    USE SIGNAL ;
    PORT
      LAYER M5 ;
        RECT  7.104 0 7.128 0.084 ;
    END
  END w_data[16]
  PIN w_data[170]
    DIRECTION OUTPUT ;
    USE SIGNAL ;
    PORT
      LAYER M5 ;
        RECT  73.392 0 73.416 0.084 ;
    END
  END w_data[170]
  PIN w_data[171]
    DIRECTION OUTPUT ;
    USE SIGNAL ;
    PORT
      LAYER M5 ;
        RECT  73.824 0 73.848 0.084 ;
    END
  END w_data[171]
  PIN w_data[172]
    DIRECTION OUTPUT ;
    USE SIGNAL ;
    PORT
      LAYER M5 ;
        RECT  74.256 0 74.28 0.084 ;
    END
  END w_data[172]
  PIN w_data[173]
    DIRECTION OUTPUT ;
    USE SIGNAL ;
    PORT
      LAYER M5 ;
        RECT  74.688 0 74.712 0.084 ;
    END
  END w_data[173]
  PIN w_data[174]
    DIRECTION OUTPUT ;
    USE SIGNAL ;
    PORT
      LAYER M5 ;
        RECT  75.12 0 75.144 0.084 ;
    END
  END w_data[174]
  PIN w_data[175]
    DIRECTION OUTPUT ;
    USE SIGNAL ;
    PORT
      LAYER M5 ;
        RECT  75.552 0 75.576 0.084 ;
    END
  END w_data[175]
  PIN w_data[176]
    DIRECTION OUTPUT ;
    USE SIGNAL ;
    PORT
      LAYER M5 ;
        RECT  75.984 0 76.008 0.084 ;
    END
  END w_data[176]
  PIN w_data[177]
    DIRECTION OUTPUT ;
    USE SIGNAL ;
    PORT
      LAYER M5 ;
        RECT  76.416 0 76.44 0.084 ;
    END
  END w_data[177]
  PIN w_data[178]
    DIRECTION OUTPUT ;
    USE SIGNAL ;
    PORT
      LAYER M5 ;
        RECT  76.848 0 76.872 0.084 ;
    END
  END w_data[178]
  PIN w_data[179]
    DIRECTION OUTPUT ;
    USE SIGNAL ;
    PORT
      LAYER M5 ;
        RECT  77.28 0 77.304 0.084 ;
    END
  END w_data[179]
  PIN w_data[17]
    DIRECTION OUTPUT ;
    USE SIGNAL ;
    PORT
      LAYER M5 ;
        RECT  7.536 0 7.56 0.084 ;
    END
  END w_data[17]
  PIN w_data[180]
    DIRECTION OUTPUT ;
    USE SIGNAL ;
    PORT
      LAYER M5 ;
        RECT  77.712 0 77.736 0.084 ;
    END
  END w_data[180]
  PIN w_data[181]
    DIRECTION OUTPUT ;
    USE SIGNAL ;
    PORT
      LAYER M5 ;
        RECT  78.144 0 78.168 0.084 ;
    END
  END w_data[181]
  PIN w_data[182]
    DIRECTION OUTPUT ;
    USE SIGNAL ;
    PORT
      LAYER M5 ;
        RECT  78.576 0 78.6 0.084 ;
    END
  END w_data[182]
  PIN w_data[183]
    DIRECTION OUTPUT ;
    USE SIGNAL ;
    PORT
      LAYER M5 ;
        RECT  79.008 0 79.032 0.084 ;
    END
  END w_data[183]
  PIN w_data[184]
    DIRECTION OUTPUT ;
    USE SIGNAL ;
    PORT
      LAYER M5 ;
        RECT  79.44 0 79.464 0.084 ;
    END
  END w_data[184]
  PIN w_data[185]
    DIRECTION OUTPUT ;
    USE SIGNAL ;
    PORT
      LAYER M5 ;
        RECT  79.872 0 79.896 0.084 ;
    END
  END w_data[185]
  PIN w_data[186]
    DIRECTION OUTPUT ;
    USE SIGNAL ;
    PORT
      LAYER M5 ;
        RECT  80.304 0 80.328 0.084 ;
    END
  END w_data[186]
  PIN w_data[187]
    DIRECTION OUTPUT ;
    USE SIGNAL ;
    PORT
      LAYER M5 ;
        RECT  80.736 0 80.76 0.084 ;
    END
  END w_data[187]
  PIN w_data[188]
    DIRECTION OUTPUT ;
    USE SIGNAL ;
    PORT
      LAYER M5 ;
        RECT  81.168 0 81.192 0.084 ;
    END
  END w_data[188]
  PIN w_data[189]
    DIRECTION OUTPUT ;
    USE SIGNAL ;
    PORT
      LAYER M5 ;
        RECT  81.6 0 81.624 0.084 ;
    END
  END w_data[189]
  PIN w_data[18]
    DIRECTION OUTPUT ;
    USE SIGNAL ;
    PORT
      LAYER M5 ;
        RECT  7.968 0 7.992 0.084 ;
    END
  END w_data[18]
  PIN w_data[190]
    DIRECTION OUTPUT ;
    USE SIGNAL ;
    PORT
      LAYER M5 ;
        RECT  82.032 0 82.056 0.084 ;
    END
  END w_data[190]
  PIN w_data[191]
    DIRECTION OUTPUT ;
    USE SIGNAL ;
    PORT
      LAYER M5 ;
        RECT  82.464 0 82.488 0.084 ;
    END
  END w_data[191]
  PIN w_data[192]
    DIRECTION OUTPUT ;
    USE SIGNAL ;
    PORT
      LAYER M5 ;
        RECT  82.896 0 82.92 0.084 ;
    END
  END w_data[192]
  PIN w_data[193]
    DIRECTION OUTPUT ;
    USE SIGNAL ;
    PORT
      LAYER M5 ;
        RECT  83.28 0 83.304 0.084 ;
    END
  END w_data[193]
  PIN w_data[194]
    DIRECTION OUTPUT ;
    USE SIGNAL ;
    PORT
      LAYER M5 ;
        RECT  83.712 0 83.736 0.084 ;
    END
  END w_data[194]
  PIN w_data[195]
    DIRECTION OUTPUT ;
    USE SIGNAL ;
    PORT
      LAYER M5 ;
        RECT  84.144 0 84.168 0.084 ;
    END
  END w_data[195]
  PIN w_data[196]
    DIRECTION OUTPUT ;
    USE SIGNAL ;
    PORT
      LAYER M5 ;
        RECT  84.576 0 84.6 0.084 ;
    END
  END w_data[196]
  PIN w_data[197]
    DIRECTION OUTPUT ;
    USE SIGNAL ;
    PORT
      LAYER M5 ;
        RECT  85.008 0 85.032 0.084 ;
    END
  END w_data[197]
  PIN w_data[198]
    DIRECTION OUTPUT ;
    USE SIGNAL ;
    PORT
      LAYER M5 ;
        RECT  85.44 0 85.464 0.084 ;
    END
  END w_data[198]
  PIN w_data[199]
    DIRECTION OUTPUT ;
    USE SIGNAL ;
    PORT
      LAYER M5 ;
        RECT  85.872 0 85.896 0.084 ;
    END
  END w_data[199]
  PIN w_data[19]
    DIRECTION OUTPUT ;
    USE SIGNAL ;
    PORT
      LAYER M5 ;
        RECT  8.4 0 8.424 0.084 ;
    END
  END w_data[19]
  PIN w_data[1]
    DIRECTION OUTPUT ;
    USE SIGNAL ;
    PORT
      LAYER M5 ;
        RECT  0.624 0 0.648 0.084 ;
    END
  END w_data[1]
  PIN w_data[200]
    DIRECTION OUTPUT ;
    USE SIGNAL ;
    PORT
      LAYER M5 ;
        RECT  86.304 0 86.328 0.084 ;
    END
  END w_data[200]
  PIN w_data[201]
    DIRECTION OUTPUT ;
    USE SIGNAL ;
    PORT
      LAYER M5 ;
        RECT  86.736 0 86.76 0.084 ;
    END
  END w_data[201]
  PIN w_data[202]
    DIRECTION OUTPUT ;
    USE SIGNAL ;
    PORT
      LAYER M5 ;
        RECT  87.168 0 87.192 0.084 ;
    END
  END w_data[202]
  PIN w_data[203]
    DIRECTION OUTPUT ;
    USE SIGNAL ;
    PORT
      LAYER M5 ;
        RECT  87.6 0 87.624 0.084 ;
    END
  END w_data[203]
  PIN w_data[204]
    DIRECTION OUTPUT ;
    USE SIGNAL ;
    PORT
      LAYER M5 ;
        RECT  88.032 0 88.056 0.084 ;
    END
  END w_data[204]
  PIN w_data[205]
    DIRECTION OUTPUT ;
    USE SIGNAL ;
    PORT
      LAYER M5 ;
        RECT  88.464 0 88.488 0.084 ;
    END
  END w_data[205]
  PIN w_data[206]
    DIRECTION OUTPUT ;
    USE SIGNAL ;
    PORT
      LAYER M5 ;
        RECT  88.896 0 88.92 0.084 ;
    END
  END w_data[206]
  PIN w_data[207]
    DIRECTION OUTPUT ;
    USE SIGNAL ;
    PORT
      LAYER M5 ;
        RECT  89.328 0 89.352 0.084 ;
    END
  END w_data[207]
  PIN w_data[208]
    DIRECTION OUTPUT ;
    USE SIGNAL ;
    PORT
      LAYER M5 ;
        RECT  89.76 0 89.784 0.084 ;
    END
  END w_data[208]
  PIN w_data[209]
    DIRECTION OUTPUT ;
    USE SIGNAL ;
    PORT
      LAYER M5 ;
        RECT  90.192 0 90.216 0.084 ;
    END
  END w_data[209]
  PIN w_data[20]
    DIRECTION OUTPUT ;
    USE SIGNAL ;
    PORT
      LAYER M5 ;
        RECT  8.832 0 8.856 0.084 ;
    END
  END w_data[20]
  PIN w_data[210]
    DIRECTION OUTPUT ;
    USE SIGNAL ;
    PORT
      LAYER M5 ;
        RECT  90.624 0 90.648 0.084 ;
    END
  END w_data[210]
  PIN w_data[211]
    DIRECTION OUTPUT ;
    USE SIGNAL ;
    PORT
      LAYER M5 ;
        RECT  91.056 0 91.08 0.084 ;
    END
  END w_data[211]
  PIN w_data[212]
    DIRECTION OUTPUT ;
    USE SIGNAL ;
    PORT
      LAYER M5 ;
        RECT  91.488 0 91.512 0.084 ;
    END
  END w_data[212]
  PIN w_data[213]
    DIRECTION OUTPUT ;
    USE SIGNAL ;
    PORT
      LAYER M5 ;
        RECT  91.92 0 91.944 0.084 ;
    END
  END w_data[213]
  PIN w_data[214]
    DIRECTION OUTPUT ;
    USE SIGNAL ;
    PORT
      LAYER M5 ;
        RECT  92.352 0 92.376 0.084 ;
    END
  END w_data[214]
  PIN w_data[215]
    DIRECTION OUTPUT ;
    USE SIGNAL ;
    PORT
      LAYER M5 ;
        RECT  92.784 0 92.808 0.084 ;
    END
  END w_data[215]
  PIN w_data[216]
    DIRECTION OUTPUT ;
    USE SIGNAL ;
    PORT
      LAYER M5 ;
        RECT  93.216 0 93.24 0.084 ;
    END
  END w_data[216]
  PIN w_data[217]
    DIRECTION OUTPUT ;
    USE SIGNAL ;
    PORT
      LAYER M5 ;
        RECT  93.648 0 93.672 0.084 ;
    END
  END w_data[217]
  PIN w_data[218]
    DIRECTION OUTPUT ;
    USE SIGNAL ;
    PORT
      LAYER M5 ;
        RECT  94.08 0 94.104 0.084 ;
    END
  END w_data[218]
  PIN w_data[219]
    DIRECTION OUTPUT ;
    USE SIGNAL ;
    PORT
      LAYER M5 ;
        RECT  94.512 0 94.536 0.084 ;
    END
  END w_data[219]
  PIN w_data[21]
    DIRECTION OUTPUT ;
    USE SIGNAL ;
    PORT
      LAYER M5 ;
        RECT  9.264 0 9.288 0.084 ;
    END
  END w_data[21]
  PIN w_data[220]
    DIRECTION OUTPUT ;
    USE SIGNAL ;
    PORT
      LAYER M5 ;
        RECT  94.944 0 94.968 0.084 ;
    END
  END w_data[220]
  PIN w_data[221]
    DIRECTION OUTPUT ;
    USE SIGNAL ;
    PORT
      LAYER M5 ;
        RECT  95.376 0 95.4 0.084 ;
    END
  END w_data[221]
  PIN w_data[222]
    DIRECTION OUTPUT ;
    USE SIGNAL ;
    PORT
      LAYER M5 ;
        RECT  95.808 0 95.832 0.084 ;
    END
  END w_data[222]
  PIN w_data[223]
    DIRECTION OUTPUT ;
    USE SIGNAL ;
    PORT
      LAYER M5 ;
        RECT  96.24 0 96.264 0.084 ;
    END
  END w_data[223]
  PIN w_data[224]
    DIRECTION OUTPUT ;
    USE SIGNAL ;
    PORT
      LAYER M5 ;
        RECT  96.672 0 96.696 0.084 ;
    END
  END w_data[224]
  PIN w_data[225]
    DIRECTION OUTPUT ;
    USE SIGNAL ;
    PORT
      LAYER M5 ;
        RECT  97.104 0 97.128 0.084 ;
    END
  END w_data[225]
  PIN w_data[226]
    DIRECTION OUTPUT ;
    USE SIGNAL ;
    PORT
      LAYER M5 ;
        RECT  97.488 0 97.512 0.084 ;
    END
  END w_data[226]
  PIN w_data[227]
    DIRECTION OUTPUT ;
    USE SIGNAL ;
    PORT
      LAYER M5 ;
        RECT  97.92 0 97.944 0.084 ;
    END
  END w_data[227]
  PIN w_data[228]
    DIRECTION OUTPUT ;
    USE SIGNAL ;
    PORT
      LAYER M5 ;
        RECT  98.352 0 98.376 0.084 ;
    END
  END w_data[228]
  PIN w_data[229]
    DIRECTION OUTPUT ;
    USE SIGNAL ;
    PORT
      LAYER M5 ;
        RECT  98.784 0 98.808 0.084 ;
    END
  END w_data[229]
  PIN w_data[22]
    DIRECTION OUTPUT ;
    USE SIGNAL ;
    PORT
      LAYER M5 ;
        RECT  9.696 0 9.72 0.084 ;
    END
  END w_data[22]
  PIN w_data[230]
    DIRECTION OUTPUT ;
    USE SIGNAL ;
    PORT
      LAYER M5 ;
        RECT  99.216 0 99.24 0.084 ;
    END
  END w_data[230]
  PIN w_data[231]
    DIRECTION OUTPUT ;
    USE SIGNAL ;
    PORT
      LAYER M5 ;
        RECT  99.648 0 99.672 0.084 ;
    END
  END w_data[231]
  PIN w_data[232]
    DIRECTION OUTPUT ;
    USE SIGNAL ;
    PORT
      LAYER M5 ;
        RECT  100.08 0 100.104 0.084 ;
    END
  END w_data[232]
  PIN w_data[233]
    DIRECTION OUTPUT ;
    USE SIGNAL ;
    PORT
      LAYER M5 ;
        RECT  100.512 0 100.536 0.084 ;
    END
  END w_data[233]
  PIN w_data[234]
    DIRECTION OUTPUT ;
    USE SIGNAL ;
    PORT
      LAYER M5 ;
        RECT  100.944 0 100.968 0.084 ;
    END
  END w_data[234]
  PIN w_data[235]
    DIRECTION OUTPUT ;
    USE SIGNAL ;
    PORT
      LAYER M5 ;
        RECT  101.376 0 101.4 0.084 ;
    END
  END w_data[235]
  PIN w_data[236]
    DIRECTION OUTPUT ;
    USE SIGNAL ;
    PORT
      LAYER M5 ;
        RECT  101.808 0 101.832 0.084 ;
    END
  END w_data[236]
  PIN w_data[237]
    DIRECTION OUTPUT ;
    USE SIGNAL ;
    PORT
      LAYER M5 ;
        RECT  102.24 0 102.264 0.084 ;
    END
  END w_data[237]
  PIN w_data[238]
    DIRECTION OUTPUT ;
    USE SIGNAL ;
    PORT
      LAYER M5 ;
        RECT  102.672 0 102.696 0.084 ;
    END
  END w_data[238]
  PIN w_data[239]
    DIRECTION OUTPUT ;
    USE SIGNAL ;
    PORT
      LAYER M5 ;
        RECT  103.104 0 103.128 0.084 ;
    END
  END w_data[239]
  PIN w_data[23]
    DIRECTION OUTPUT ;
    USE SIGNAL ;
    PORT
      LAYER M5 ;
        RECT  10.128 0 10.152 0.084 ;
    END
  END w_data[23]
  PIN w_data[240]
    DIRECTION OUTPUT ;
    USE SIGNAL ;
    PORT
      LAYER M5 ;
        RECT  103.536 0 103.56 0.084 ;
    END
  END w_data[240]
  PIN w_data[241]
    DIRECTION OUTPUT ;
    USE SIGNAL ;
    PORT
      LAYER M5 ;
        RECT  103.968 0 103.992 0.084 ;
    END
  END w_data[241]
  PIN w_data[242]
    DIRECTION OUTPUT ;
    USE SIGNAL ;
    PORT
      LAYER M5 ;
        RECT  104.4 0 104.424 0.084 ;
    END
  END w_data[242]
  PIN w_data[243]
    DIRECTION OUTPUT ;
    USE SIGNAL ;
    PORT
      LAYER M5 ;
        RECT  104.832 0 104.856 0.084 ;
    END
  END w_data[243]
  PIN w_data[244]
    DIRECTION OUTPUT ;
    USE SIGNAL ;
    PORT
      LAYER M5 ;
        RECT  105.264 0 105.288 0.084 ;
    END
  END w_data[244]
  PIN w_data[245]
    DIRECTION OUTPUT ;
    USE SIGNAL ;
    PORT
      LAYER M5 ;
        RECT  105.696 0 105.72 0.084 ;
    END
  END w_data[245]
  PIN w_data[246]
    DIRECTION OUTPUT ;
    USE SIGNAL ;
    PORT
      LAYER M5 ;
        RECT  106.128 0 106.152 0.084 ;
    END
  END w_data[246]
  PIN w_data[247]
    DIRECTION OUTPUT ;
    USE SIGNAL ;
    PORT
      LAYER M5 ;
        RECT  106.56 0 106.584 0.084 ;
    END
  END w_data[247]
  PIN w_data[248]
    DIRECTION OUTPUT ;
    USE SIGNAL ;
    PORT
      LAYER M5 ;
        RECT  106.992 0 107.016 0.084 ;
    END
  END w_data[248]
  PIN w_data[249]
    DIRECTION OUTPUT ;
    USE SIGNAL ;
    PORT
      LAYER M5 ;
        RECT  107.424 0 107.448 0.084 ;
    END
  END w_data[249]
  PIN w_data[24]
    DIRECTION OUTPUT ;
    USE SIGNAL ;
    PORT
      LAYER M5 ;
        RECT  10.56 0 10.584 0.084 ;
    END
  END w_data[24]
  PIN w_data[250]
    DIRECTION OUTPUT ;
    USE SIGNAL ;
    PORT
      LAYER M5 ;
        RECT  107.856 0 107.88 0.084 ;
    END
  END w_data[250]
  PIN w_data[251]
    DIRECTION OUTPUT ;
    USE SIGNAL ;
    PORT
      LAYER M5 ;
        RECT  108.288 0 108.312 0.084 ;
    END
  END w_data[251]
  PIN w_data[252]
    DIRECTION OUTPUT ;
    USE SIGNAL ;
    PORT
      LAYER M5 ;
        RECT  108.72 0 108.744 0.084 ;
    END
  END w_data[252]
  PIN w_data[253]
    DIRECTION OUTPUT ;
    USE SIGNAL ;
    PORT
      LAYER M5 ;
        RECT  109.152 0 109.176 0.084 ;
    END
  END w_data[253]
  PIN w_data[254]
    DIRECTION OUTPUT ;
    USE SIGNAL ;
    PORT
      LAYER M5 ;
        RECT  109.584 0 109.608 0.084 ;
    END
  END w_data[254]
  PIN w_data[255]
    DIRECTION OUTPUT ;
    USE SIGNAL ;
    PORT
      LAYER M5 ;
        RECT  110.016 0 110.04 0.084 ;
    END
  END w_data[255]
  PIN w_data[25]
    DIRECTION OUTPUT ;
    USE SIGNAL ;
    PORT
      LAYER M5 ;
        RECT  10.944 0 10.968 0.084 ;
    END
  END w_data[25]
  PIN w_data[26]
    DIRECTION OUTPUT ;
    USE SIGNAL ;
    PORT
      LAYER M5 ;
        RECT  11.376 0 11.4 0.084 ;
    END
  END w_data[26]
  PIN w_data[27]
    DIRECTION OUTPUT ;
    USE SIGNAL ;
    PORT
      LAYER M5 ;
        RECT  11.808 0 11.832 0.084 ;
    END
  END w_data[27]
  PIN w_data[28]
    DIRECTION OUTPUT ;
    USE SIGNAL ;
    PORT
      LAYER M5 ;
        RECT  12.24 0 12.264 0.084 ;
    END
  END w_data[28]
  PIN w_data[29]
    DIRECTION OUTPUT ;
    USE SIGNAL ;
    PORT
      LAYER M5 ;
        RECT  12.672 0 12.696 0.084 ;
    END
  END w_data[29]
  PIN w_data[2]
    DIRECTION OUTPUT ;
    USE SIGNAL ;
    PORT
      LAYER M5 ;
        RECT  1.056 0 1.08 0.084 ;
    END
  END w_data[2]
  PIN w_data[30]
    DIRECTION OUTPUT ;
    USE SIGNAL ;
    PORT
      LAYER M5 ;
        RECT  13.104 0 13.128 0.084 ;
    END
  END w_data[30]
  PIN w_data[31]
    DIRECTION OUTPUT ;
    USE SIGNAL ;
    PORT
      LAYER M5 ;
        RECT  13.536 0 13.56 0.084 ;
    END
  END w_data[31]
  PIN w_data[32]
    DIRECTION OUTPUT ;
    USE SIGNAL ;
    PORT
      LAYER M5 ;
        RECT  13.968 0 13.992 0.084 ;
    END
  END w_data[32]
  PIN w_data[33]
    DIRECTION OUTPUT ;
    USE SIGNAL ;
    PORT
      LAYER M5 ;
        RECT  14.4 0 14.424 0.084 ;
    END
  END w_data[33]
  PIN w_data[34]
    DIRECTION OUTPUT ;
    USE SIGNAL ;
    PORT
      LAYER M5 ;
        RECT  14.832 0 14.856 0.084 ;
    END
  END w_data[34]
  PIN w_data[35]
    DIRECTION OUTPUT ;
    USE SIGNAL ;
    PORT
      LAYER M5 ;
        RECT  15.264 0 15.288 0.084 ;
    END
  END w_data[35]
  PIN w_data[36]
    DIRECTION OUTPUT ;
    USE SIGNAL ;
    PORT
      LAYER M5 ;
        RECT  15.696 0 15.72 0.084 ;
    END
  END w_data[36]
  PIN w_data[37]
    DIRECTION OUTPUT ;
    USE SIGNAL ;
    PORT
      LAYER M5 ;
        RECT  16.128 0 16.152 0.084 ;
    END
  END w_data[37]
  PIN w_data[38]
    DIRECTION OUTPUT ;
    USE SIGNAL ;
    PORT
      LAYER M5 ;
        RECT  16.56 0 16.584 0.084 ;
    END
  END w_data[38]
  PIN w_data[39]
    DIRECTION OUTPUT ;
    USE SIGNAL ;
    PORT
      LAYER M5 ;
        RECT  16.992 0 17.016 0.084 ;
    END
  END w_data[39]
  PIN w_data[3]
    DIRECTION OUTPUT ;
    USE SIGNAL ;
    PORT
      LAYER M5 ;
        RECT  1.488 0 1.512 0.084 ;
    END
  END w_data[3]
  PIN w_data[40]
    DIRECTION OUTPUT ;
    USE SIGNAL ;
    PORT
      LAYER M5 ;
        RECT  17.424 0 17.448 0.084 ;
    END
  END w_data[40]
  PIN w_data[41]
    DIRECTION OUTPUT ;
    USE SIGNAL ;
    PORT
      LAYER M5 ;
        RECT  17.856 0 17.88 0.084 ;
    END
  END w_data[41]
  PIN w_data[42]
    DIRECTION OUTPUT ;
    USE SIGNAL ;
    PORT
      LAYER M5 ;
        RECT  18.288 0 18.312 0.084 ;
    END
  END w_data[42]
  PIN w_data[43]
    DIRECTION OUTPUT ;
    USE SIGNAL ;
    PORT
      LAYER M5 ;
        RECT  18.72 0 18.744 0.084 ;
    END
  END w_data[43]
  PIN w_data[44]
    DIRECTION OUTPUT ;
    USE SIGNAL ;
    PORT
      LAYER M5 ;
        RECT  19.152 0 19.176 0.084 ;
    END
  END w_data[44]
  PIN w_data[45]
    DIRECTION OUTPUT ;
    USE SIGNAL ;
    PORT
      LAYER M5 ;
        RECT  19.584 0 19.608 0.084 ;
    END
  END w_data[45]
  PIN w_data[46]
    DIRECTION OUTPUT ;
    USE SIGNAL ;
    PORT
      LAYER M5 ;
        RECT  20.016 0 20.04 0.084 ;
    END
  END w_data[46]
  PIN w_data[47]
    DIRECTION OUTPUT ;
    USE SIGNAL ;
    PORT
      LAYER M5 ;
        RECT  20.448 0 20.472 0.084 ;
    END
  END w_data[47]
  PIN w_data[48]
    DIRECTION OUTPUT ;
    USE SIGNAL ;
    PORT
      LAYER M5 ;
        RECT  20.88 0 20.904 0.084 ;
    END
  END w_data[48]
  PIN w_data[49]
    DIRECTION OUTPUT ;
    USE SIGNAL ;
    PORT
      LAYER M5 ;
        RECT  21.312 0 21.336 0.084 ;
    END
  END w_data[49]
  PIN w_data[4]
    DIRECTION OUTPUT ;
    USE SIGNAL ;
    PORT
      LAYER M5 ;
        RECT  1.92 0 1.944 0.084 ;
    END
  END w_data[4]
  PIN w_data[50]
    DIRECTION OUTPUT ;
    USE SIGNAL ;
    PORT
      LAYER M5 ;
        RECT  21.744 0 21.768 0.084 ;
    END
  END w_data[50]
  PIN w_data[51]
    DIRECTION OUTPUT ;
    USE SIGNAL ;
    PORT
      LAYER M5 ;
        RECT  22.176 0 22.2 0.084 ;
    END
  END w_data[51]
  PIN w_data[52]
    DIRECTION OUTPUT ;
    USE SIGNAL ;
    PORT
      LAYER M5 ;
        RECT  22.608 0 22.632 0.084 ;
    END
  END w_data[52]
  PIN w_data[53]
    DIRECTION OUTPUT ;
    USE SIGNAL ;
    PORT
      LAYER M5 ;
        RECT  23.04 0 23.064 0.084 ;
    END
  END w_data[53]
  PIN w_data[54]
    DIRECTION OUTPUT ;
    USE SIGNAL ;
    PORT
      LAYER M5 ;
        RECT  23.472 0 23.496 0.084 ;
    END
  END w_data[54]
  PIN w_data[55]
    DIRECTION OUTPUT ;
    USE SIGNAL ;
    PORT
      LAYER M5 ;
        RECT  23.904 0 23.928 0.084 ;
    END
  END w_data[55]
  PIN w_data[56]
    DIRECTION OUTPUT ;
    USE SIGNAL ;
    PORT
      LAYER M5 ;
        RECT  24.336 0 24.36 0.084 ;
    END
  END w_data[56]
  PIN w_data[57]
    DIRECTION OUTPUT ;
    USE SIGNAL ;
    PORT
      LAYER M5 ;
        RECT  24.768 0 24.792 0.084 ;
    END
  END w_data[57]
  PIN w_data[58]
    DIRECTION OUTPUT ;
    USE SIGNAL ;
    PORT
      LAYER M5 ;
        RECT  25.2 0 25.224 0.084 ;
    END
  END w_data[58]
  PIN w_data[59]
    DIRECTION OUTPUT ;
    USE SIGNAL ;
    PORT
      LAYER M5 ;
        RECT  25.584 0 25.608 0.084 ;
    END
  END w_data[59]
  PIN w_data[5]
    DIRECTION OUTPUT ;
    USE SIGNAL ;
    PORT
      LAYER M5 ;
        RECT  2.352 0 2.376 0.084 ;
    END
  END w_data[5]
  PIN w_data[60]
    DIRECTION OUTPUT ;
    USE SIGNAL ;
    PORT
      LAYER M5 ;
        RECT  26.016 0 26.04 0.084 ;
    END
  END w_data[60]
  PIN w_data[61]
    DIRECTION OUTPUT ;
    USE SIGNAL ;
    PORT
      LAYER M5 ;
        RECT  26.448 0 26.472 0.084 ;
    END
  END w_data[61]
  PIN w_data[62]
    DIRECTION OUTPUT ;
    USE SIGNAL ;
    PORT
      LAYER M5 ;
        RECT  26.88 0 26.904 0.084 ;
    END
  END w_data[62]
  PIN w_data[63]
    DIRECTION OUTPUT ;
    USE SIGNAL ;
    PORT
      LAYER M5 ;
        RECT  27.312 0 27.336 0.084 ;
    END
  END w_data[63]
  PIN w_data[64]
    DIRECTION OUTPUT ;
    USE SIGNAL ;
    PORT
      LAYER M5 ;
        RECT  27.744 0 27.768 0.084 ;
    END
  END w_data[64]
  PIN w_data[65]
    DIRECTION OUTPUT ;
    USE SIGNAL ;
    PORT
      LAYER M5 ;
        RECT  28.176 0 28.2 0.084 ;
    END
  END w_data[65]
  PIN w_data[66]
    DIRECTION OUTPUT ;
    USE SIGNAL ;
    PORT
      LAYER M5 ;
        RECT  28.608 0 28.632 0.084 ;
    END
  END w_data[66]
  PIN w_data[67]
    DIRECTION OUTPUT ;
    USE SIGNAL ;
    PORT
      LAYER M5 ;
        RECT  29.04 0 29.064 0.084 ;
    END
  END w_data[67]
  PIN w_data[68]
    DIRECTION OUTPUT ;
    USE SIGNAL ;
    PORT
      LAYER M5 ;
        RECT  29.472 0 29.496 0.084 ;
    END
  END w_data[68]
  PIN w_data[69]
    DIRECTION OUTPUT ;
    USE SIGNAL ;
    PORT
      LAYER M5 ;
        RECT  29.904 0 29.928 0.084 ;
    END
  END w_data[69]
  PIN w_data[6]
    DIRECTION OUTPUT ;
    USE SIGNAL ;
    PORT
      LAYER M5 ;
        RECT  2.784 0 2.808 0.084 ;
    END
  END w_data[6]
  PIN w_data[70]
    DIRECTION OUTPUT ;
    USE SIGNAL ;
    PORT
      LAYER M5 ;
        RECT  30.336 0 30.36 0.084 ;
    END
  END w_data[70]
  PIN w_data[71]
    DIRECTION OUTPUT ;
    USE SIGNAL ;
    PORT
      LAYER M5 ;
        RECT  30.768 0 30.792 0.084 ;
    END
  END w_data[71]
  PIN w_data[72]
    DIRECTION OUTPUT ;
    USE SIGNAL ;
    PORT
      LAYER M5 ;
        RECT  31.2 0 31.224 0.084 ;
    END
  END w_data[72]
  PIN w_data[73]
    DIRECTION OUTPUT ;
    USE SIGNAL ;
    PORT
      LAYER M5 ;
        RECT  31.632 0 31.656 0.084 ;
    END
  END w_data[73]
  PIN w_data[74]
    DIRECTION OUTPUT ;
    USE SIGNAL ;
    PORT
      LAYER M5 ;
        RECT  32.064 0 32.088 0.084 ;
    END
  END w_data[74]
  PIN w_data[75]
    DIRECTION OUTPUT ;
    USE SIGNAL ;
    PORT
      LAYER M5 ;
        RECT  32.496 0 32.52 0.084 ;
    END
  END w_data[75]
  PIN w_data[76]
    DIRECTION OUTPUT ;
    USE SIGNAL ;
    PORT
      LAYER M5 ;
        RECT  32.928 0 32.952 0.084 ;
    END
  END w_data[76]
  PIN w_data[77]
    DIRECTION OUTPUT ;
    USE SIGNAL ;
    PORT
      LAYER M5 ;
        RECT  33.36 0 33.384 0.084 ;
    END
  END w_data[77]
  PIN w_data[78]
    DIRECTION OUTPUT ;
    USE SIGNAL ;
    PORT
      LAYER M5 ;
        RECT  33.792 0 33.816 0.084 ;
    END
  END w_data[78]
  PIN w_data[79]
    DIRECTION OUTPUT ;
    USE SIGNAL ;
    PORT
      LAYER M5 ;
        RECT  34.224 0 34.248 0.084 ;
    END
  END w_data[79]
  PIN w_data[7]
    DIRECTION OUTPUT ;
    USE SIGNAL ;
    PORT
      LAYER M5 ;
        RECT  3.216 0 3.24 0.084 ;
    END
  END w_data[7]
  PIN w_data[80]
    DIRECTION OUTPUT ;
    USE SIGNAL ;
    PORT
      LAYER M5 ;
        RECT  34.656 0 34.68 0.084 ;
    END
  END w_data[80]
  PIN w_data[81]
    DIRECTION OUTPUT ;
    USE SIGNAL ;
    PORT
      LAYER M5 ;
        RECT  35.088 0 35.112 0.084 ;
    END
  END w_data[81]
  PIN w_data[82]
    DIRECTION OUTPUT ;
    USE SIGNAL ;
    PORT
      LAYER M5 ;
        RECT  35.52 0 35.544 0.084 ;
    END
  END w_data[82]
  PIN w_data[83]
    DIRECTION OUTPUT ;
    USE SIGNAL ;
    PORT
      LAYER M5 ;
        RECT  35.952 0 35.976 0.084 ;
    END
  END w_data[83]
  PIN w_data[84]
    DIRECTION OUTPUT ;
    USE SIGNAL ;
    PORT
      LAYER M5 ;
        RECT  36.384 0 36.408 0.084 ;
    END
  END w_data[84]
  PIN w_data[85]
    DIRECTION OUTPUT ;
    USE SIGNAL ;
    PORT
      LAYER M5 ;
        RECT  36.816 0 36.84 0.084 ;
    END
  END w_data[85]
  PIN w_data[86]
    DIRECTION OUTPUT ;
    USE SIGNAL ;
    PORT
      LAYER M5 ;
        RECT  37.248 0 37.272 0.084 ;
    END
  END w_data[86]
  PIN w_data[87]
    DIRECTION OUTPUT ;
    USE SIGNAL ;
    PORT
      LAYER M5 ;
        RECT  37.68 0 37.704 0.084 ;
    END
  END w_data[87]
  PIN w_data[88]
    DIRECTION OUTPUT ;
    USE SIGNAL ;
    PORT
      LAYER M5 ;
        RECT  38.112 0 38.136 0.084 ;
    END
  END w_data[88]
  PIN w_data[89]
    DIRECTION OUTPUT ;
    USE SIGNAL ;
    PORT
      LAYER M5 ;
        RECT  38.544 0 38.568 0.084 ;
    END
  END w_data[89]
  PIN w_data[8]
    DIRECTION OUTPUT ;
    USE SIGNAL ;
    PORT
      LAYER M5 ;
        RECT  3.648 0 3.672 0.084 ;
    END
  END w_data[8]
  PIN w_data[90]
    DIRECTION OUTPUT ;
    USE SIGNAL ;
    PORT
      LAYER M5 ;
        RECT  38.976 0 39 0.084 ;
    END
  END w_data[90]
  PIN w_data[91]
    DIRECTION OUTPUT ;
    USE SIGNAL ;
    PORT
      LAYER M5 ;
        RECT  39.408 0 39.432 0.084 ;
    END
  END w_data[91]
  PIN w_data[92]
    DIRECTION OUTPUT ;
    USE SIGNAL ;
    PORT
      LAYER M5 ;
        RECT  39.792 0 39.816 0.084 ;
    END
  END w_data[92]
  PIN w_data[93]
    DIRECTION OUTPUT ;
    USE SIGNAL ;
    PORT
      LAYER M5 ;
        RECT  40.224 0 40.248 0.084 ;
    END
  END w_data[93]
  PIN w_data[94]
    DIRECTION OUTPUT ;
    USE SIGNAL ;
    PORT
      LAYER M5 ;
        RECT  40.656 0 40.68 0.084 ;
    END
  END w_data[94]
  PIN w_data[95]
    DIRECTION OUTPUT ;
    USE SIGNAL ;
    PORT
      LAYER M5 ;
        RECT  41.088 0 41.112 0.084 ;
    END
  END w_data[95]
  PIN w_data[96]
    DIRECTION OUTPUT ;
    USE SIGNAL ;
    PORT
      LAYER M5 ;
        RECT  41.52 0 41.544 0.084 ;
    END
  END w_data[96]
  PIN w_data[97]
    DIRECTION OUTPUT ;
    USE SIGNAL ;
    PORT
      LAYER M5 ;
        RECT  41.952 0 41.976 0.084 ;
    END
  END w_data[97]
  PIN w_data[98]
    DIRECTION OUTPUT ;
    USE SIGNAL ;
    PORT
      LAYER M5 ;
        RECT  42.384 0 42.408 0.084 ;
    END
  END w_data[98]
  PIN w_data[99]
    DIRECTION OUTPUT ;
    USE SIGNAL ;
    PORT
      LAYER M5 ;
        RECT  42.816 0 42.84 0.084 ;
    END
  END w_data[99]
  PIN w_data[9]
    DIRECTION OUTPUT ;
    USE SIGNAL ;
    PORT
      LAYER M5 ;
        RECT  4.08 0 4.104 0.084 ;
    END
  END w_data[9]
  PIN w_room
    DIRECTION INPUT ;
    USE SIGNAL ;
    PORT
      LAYER M5 ;
        RECT  110.448 0 110.472 0.084 ;
    END
  END w_room
  PIN w_sec[0]
    DIRECTION OUTPUT ;
    USE SIGNAL ;
    PORT
      LAYER M5 ;
        RECT  110.88 0 110.904 0.084 ;
    END
  END w_sec[0]
  PIN w_sec[10]
    DIRECTION OUTPUT ;
    USE SIGNAL ;
    PORT
      LAYER M5 ;
        RECT  115.152 0 115.176 0.084 ;
    END
  END w_sec[10]
  PIN w_sec[11]
    DIRECTION OUTPUT ;
    USE SIGNAL ;
    PORT
      LAYER M5 ;
        RECT  115.584 0 115.608 0.084 ;
    END
  END w_sec[11]
  PIN w_sec[12]
    DIRECTION OUTPUT ;
    USE SIGNAL ;
    PORT
      LAYER M5 ;
        RECT  116.016 0 116.04 0.084 ;
    END
  END w_sec[12]
  PIN w_sec[13]
    DIRECTION OUTPUT ;
    USE SIGNAL ;
    PORT
      LAYER M5 ;
        RECT  116.448 0 116.472 0.084 ;
    END
  END w_sec[13]
  PIN w_sec[14]
    DIRECTION OUTPUT ;
    USE SIGNAL ;
    PORT
      LAYER M5 ;
        RECT  116.88 0 116.904 0.084 ;
    END
  END w_sec[14]
  PIN w_sec[15]
    DIRECTION OUTPUT ;
    USE SIGNAL ;
    PORT
      LAYER M5 ;
        RECT  117.312 0 117.336 0.084 ;
    END
  END w_sec[15]
  PIN w_sec[16]
    DIRECTION OUTPUT ;
    USE SIGNAL ;
    PORT
      LAYER M5 ;
        RECT  117.744 0 117.768 0.084 ;
    END
  END w_sec[16]
  PIN w_sec[17]
    DIRECTION OUTPUT ;
    USE SIGNAL ;
    PORT
      LAYER M5 ;
        RECT  118.176 0 118.2 0.084 ;
    END
  END w_sec[17]
  PIN w_sec[18]
    DIRECTION OUTPUT ;
    USE SIGNAL ;
    PORT
      LAYER M5 ;
        RECT  118.608 0 118.632 0.084 ;
    END
  END w_sec[18]
  PIN w_sec[19]
    DIRECTION OUTPUT ;
    USE SIGNAL ;
    PORT
      LAYER M5 ;
        RECT  119.04 0 119.064 0.084 ;
    END
  END w_sec[19]
  PIN w_sec[1]
    DIRECTION OUTPUT ;
    USE SIGNAL ;
    PORT
      LAYER M5 ;
        RECT  111.312 0 111.336 0.084 ;
    END
  END w_sec[1]
  PIN w_sec[20]
    DIRECTION OUTPUT ;
    USE SIGNAL ;
    PORT
      LAYER M5 ;
        RECT  119.472 0 119.496 0.084 ;
    END
  END w_sec[20]
  PIN w_sec[21]
    DIRECTION OUTPUT ;
    USE SIGNAL ;
    PORT
      LAYER M5 ;
        RECT  119.904 0 119.928 0.084 ;
    END
  END w_sec[21]
  PIN w_sec[22]
    DIRECTION OUTPUT ;
    USE SIGNAL ;
    PORT
      LAYER M5 ;
        RECT  120.336 0 120.36 0.084 ;
    END
  END w_sec[22]
  PIN w_sec[23]
    DIRECTION OUTPUT ;
    USE SIGNAL ;
    PORT
      LAYER M5 ;
        RECT  120.768 0 120.792 0.084 ;
    END
  END w_sec[23]
  PIN w_sec[2]
    DIRECTION OUTPUT ;
    USE SIGNAL ;
    PORT
      LAYER M5 ;
        RECT  111.744 0 111.768 0.084 ;
    END
  END w_sec[2]
  PIN w_sec[3]
    DIRECTION OUTPUT ;
    USE SIGNAL ;
    PORT
      LAYER M5 ;
        RECT  112.128 0 112.152 0.084 ;
    END
  END w_sec[3]
  PIN w_sec[4]
    DIRECTION OUTPUT ;
    USE SIGNAL ;
    PORT
      LAYER M5 ;
        RECT  112.56 0 112.584 0.084 ;
    END
  END w_sec[4]
  PIN w_sec[5]
    DIRECTION OUTPUT ;
    USE SIGNAL ;
    PORT
      LAYER M5 ;
        RECT  112.992 0 113.016 0.084 ;
    END
  END w_sec[5]
  PIN w_sec[6]
    DIRECTION OUTPUT ;
    USE SIGNAL ;
    PORT
      LAYER M5 ;
        RECT  113.424 0 113.448 0.084 ;
    END
  END w_sec[6]
  PIN w_sec[7]
    DIRECTION OUTPUT ;
    USE SIGNAL ;
    PORT
      LAYER M5 ;
        RECT  113.856 0 113.88 0.084 ;
    END
  END w_sec[7]
  PIN w_sec[8]
    DIRECTION OUTPUT ;
    USE SIGNAL ;
    PORT
      LAYER M5 ;
        RECT  114.288 0 114.312 0.084 ;
    END
  END w_sec[8]
  PIN w_sec[9]
    DIRECTION OUTPUT ;
    USE SIGNAL ;
    PORT
      LAYER M5 ;
        RECT  114.72 0 114.744 0.084 ;
    END
  END w_sec[9]
  PIN w_tag[0]
    DIRECTION OUTPUT ;
    USE SIGNAL ;
    PORT
      LAYER M5 ;
        RECT  121.2 0 121.224 0.084 ;
    END
  END w_tag[0]
  PIN w_tag[1]
    DIRECTION OUTPUT ;
    USE SIGNAL ;
    PORT
      LAYER M5 ;
        RECT  121.632 0 121.656 0.084 ;
    END
  END w_tag[1]
  PIN w_tag[2]
    DIRECTION OUTPUT ;
    USE SIGNAL ;
    PORT
      LAYER M5 ;
        RECT  122.064 0 122.088 0.084 ;
    END
  END w_tag[2]
  PIN w_tag[3]
    DIRECTION OUTPUT ;
    USE SIGNAL ;
    PORT
      LAYER M5 ;
        RECT  122.496 0 122.52 0.084 ;
    END
  END w_tag[3]
  PIN w_tag[4]
    DIRECTION OUTPUT ;
    USE SIGNAL ;
    PORT
      LAYER M5 ;
        RECT  122.928 0 122.952 0.084 ;
    END
  END w_tag[4]
  PIN w_tag[5]
    DIRECTION OUTPUT ;
    USE SIGNAL ;
    PORT
      LAYER M5 ;
        RECT  123.36 0 123.384 0.084 ;
    END
  END w_tag[5]
  PIN w_tag[6]
    DIRECTION OUTPUT ;
    USE SIGNAL ;
    PORT
      LAYER M5 ;
        RECT  123.792 0 123.816 0.084 ;
    END
  END w_tag[6]
  PIN w_tag[7]
    DIRECTION OUTPUT ;
    USE SIGNAL ;
    PORT
      LAYER M5 ;
        RECT  124.224 0 124.248 0.084 ;
    END
  END w_tag[7]
  PIN w_tag[8]
    DIRECTION OUTPUT ;
    USE SIGNAL ;
    PORT
      LAYER M5 ;
        RECT  124.656 0 124.68 0.084 ;
    END
  END w_tag[8]
  PIN w_v
    DIRECTION OUTPUT ;
    USE SIGNAL ;
    PORT
      LAYER M5 ;
        RECT  125.088 0 125.112 0.084 ;
    END
  END w_v
  PIN wd_tag[0]
    DIRECTION INPUT ;
    USE SIGNAL ;
    PORT
      LAYER M5 ;
        RECT  125.52 0 125.544 0.084 ;
    END
  END wd_tag[0]
  PIN wd_tag[1]
    DIRECTION INPUT ;
    USE SIGNAL ;
    PORT
      LAYER M5 ;
        RECT  125.952 0 125.976 0.084 ;
    END
  END wd_tag[1]
  PIN wd_tag[2]
    DIRECTION INPUT ;
    USE SIGNAL ;
    PORT
      LAYER M5 ;
        RECT  126.336 0 126.36 0.084 ;
    END
  END wd_tag[2]
  PIN wd_tag[3]
    DIRECTION INPUT ;
    USE SIGNAL ;
    PORT
      LAYER M5 ;
        RECT  126.768 0 126.792 0.084 ;
    END
  END wd_tag[3]
  PIN wd_tag[4]
    DIRECTION INPUT ;
    USE SIGNAL ;
    PORT
      LAYER M5 ;
        RECT  127.2 0 127.224 0.084 ;
    END
  END wd_tag[4]
  PIN wd_tag[5]
    DIRECTION INPUT ;
    USE SIGNAL ;
    PORT
      LAYER M5 ;
        RECT  127.632 0 127.656 0.084 ;
    END
  END wd_tag[5]
  PIN wd_tag[6]
    DIRECTION INPUT ;
    USE SIGNAL ;
    PORT
      LAYER M5 ;
        RECT  128.064 0 128.088 0.084 ;
    END
  END wd_tag[6]
  PIN wd_tag[7]
    DIRECTION INPUT ;
    USE SIGNAL ;
    PORT
      LAYER M5 ;
        RECT  128.496 0 128.52 0.084 ;
    END
  END wd_tag[7]
  PIN wd_tag[8]
    DIRECTION INPUT ;
    USE SIGNAL ;
    PORT
      LAYER M5 ;
        RECT  128.928 0 128.952 0.084 ;
    END
  END wd_tag[8]
  PIN wd_v
    DIRECTION INPUT ;
    USE SIGNAL ;
    PORT
      LAYER M5 ;
        RECT  129.36 0 129.384 0.084 ;
    END
  END wd_v
  PIN VDD
    DIRECTION INOUT ;
    USE POWER ;
    PORT
      LAYER M6 ;
        RECT  2.16 181.113 127.44 181.401 ;
        RECT  2.16 175.713 127.44 176.001 ;
        RECT  2.16 170.313 127.44 170.601 ;
        RECT  2.16 164.913 127.44 165.201 ;
        RECT  2.16 159.513 127.44 159.801 ;
        RECT  2.16 154.113 127.44 154.401 ;
        RECT  2.16 148.713 127.44 149.001 ;
        RECT  2.16 143.313 127.44 143.601 ;
        RECT  2.16 137.913 127.44 138.201 ;
        RECT  2.16 132.513 127.44 132.801 ;
        RECT  2.16 127.113 127.44 127.401 ;
        RECT  2.16 121.713 127.44 122.001 ;
        RECT  2.16 116.313 127.44 116.601 ;
        RECT  2.16 110.913 127.44 111.201 ;
        RECT  2.16 105.513 127.44 105.801 ;
        RECT  2.16 100.113 127.44 100.401 ;
        RECT  2.16 94.713 127.44 95.001 ;
        RECT  2.16 89.313 127.44 89.601 ;
        RECT  2.16 83.913 127.44 84.201 ;
        RECT  2.16 78.513 127.44 78.801 ;
        RECT  2.16 73.113 127.44 73.401 ;
        RECT  2.16 67.713 127.44 68.001 ;
        RECT  2.16 62.313 127.44 62.601 ;
        RECT  2.16 56.913 127.44 57.201 ;
        RECT  2.16 51.513 127.44 51.801 ;
        RECT  2.16 46.113 127.44 46.401 ;
        RECT  2.16 40.713 127.44 41.001 ;
        RECT  2.16 35.313 127.44 35.601 ;
        RECT  2.16 29.913 127.44 30.201 ;
        RECT  2.16 24.513 127.44 24.801 ;
        RECT  2.16 19.113 127.44 19.401 ;
        RECT  2.16 13.713 127.44 14.001 ;
        RECT  2.16 8.313 127.44 8.601 ;
        RECT  2.16 2.913 127.44 3.201 ;
    END
  END VDD
  PIN VSS
    DIRECTION INOUT ;
    USE GROUND ;
    PORT
      LAYER M6 ;
        RECT  2.16 180.729 127.44 181.017 ;
        RECT  2.16 175.329 127.44 175.617 ;
        RECT  2.16 169.929 127.44 170.217 ;
        RECT  2.16 164.529 127.44 164.817 ;
        RECT  2.16 159.129 127.44 159.417 ;
        RECT  2.16 153.729 127.44 154.017 ;
        RECT  2.16 148.329 127.44 148.617 ;
        RECT  2.16 142.929 127.44 143.217 ;
        RECT  2.16 137.529 127.44 137.817 ;
        RECT  2.16 132.129 127.44 132.417 ;
        RECT  2.16 126.729 127.44 127.017 ;
        RECT  2.16 121.329 127.44 121.617 ;
        RECT  2.16 115.929 127.44 116.217 ;
        RECT  2.16 110.529 127.44 110.817 ;
        RECT  2.16 105.129 127.44 105.417 ;
        RECT  2.16 99.729 127.44 100.017 ;
        RECT  2.16 94.329 127.44 94.617 ;
        RECT  2.16 88.929 127.44 89.217 ;
        RECT  2.16 83.529 127.44 83.817 ;
        RECT  2.16 78.129 127.44 78.417 ;
        RECT  2.16 72.729 127.44 73.017 ;
        RECT  2.16 67.329 127.44 67.617 ;
        RECT  2.16 61.929 127.44 62.217 ;
        RECT  2.16 56.529 127.44 56.817 ;
        RECT  2.16 51.129 127.44 51.417 ;
        RECT  2.16 45.729 127.44 46.017 ;
        RECT  2.16 40.329 127.44 40.617 ;
        RECT  2.16 34.929 127.44 35.217 ;
        RECT  2.16 29.529 127.44 29.817 ;
        RECT  2.16 24.129 127.44 24.417 ;
        RECT  2.16 18.729 127.44 19.017 ;
        RECT  2.16 13.329 127.44 13.617 ;
        RECT  2.16 7.929 127.44 8.217 ;
        RECT  2.16 2.529 127.44 2.817 ;
    END
  END VSS
  OBS
    LAYER RVTN ;
     RECT  2.16 2.16 127.44 2.295 ;
     RECT  2.16 2.565 127.44 2.835 ;
     RECT  2.16 3.105 127.44 3.375 ;
     RECT  2.16 3.645 127.44 3.915 ;
     RECT  2.16 4.185 127.44 4.455 ;
     RECT  2.16 4.725 127.44 4.995 ;
     RECT  2.16 5.265 127.44 5.535 ;
     RECT  2.16 5.805 127.44 6.075 ;
     RECT  2.16 6.345 127.44 6.615 ;
     RECT  2.16 6.885 127.44 7.155 ;
     RECT  2.16 7.425 127.44 7.695 ;
     RECT  2.16 7.965 127.44 8.235 ;
     RECT  2.16 8.505 127.44 8.775 ;
     RECT  2.16 9.045 127.44 9.315 ;
     RECT  2.16 9.585 127.44 9.855 ;
     RECT  2.16 10.125 127.44 10.395 ;
     RECT  2.16 10.665 127.44 10.935 ;
     RECT  2.16 11.205 127.44 11.475 ;
     RECT  2.16 11.745 127.44 12.015 ;
     RECT  2.16 12.285 127.44 12.555 ;
     RECT  2.16 12.825 127.44 13.095 ;
     RECT  2.16 13.365 127.44 13.635 ;
     RECT  2.16 13.905 127.44 14.175 ;
     RECT  2.16 14.445 127.44 14.715 ;
     RECT  2.16 14.985 127.44 15.255 ;
     RECT  2.16 15.525 127.44 15.795 ;
     RECT  2.16 16.065 127.44 16.335 ;
     RECT  2.16 16.605 127.44 16.875 ;
     RECT  2.16 17.145 127.44 17.415 ;
     RECT  2.16 17.685 127.44 17.955 ;
     RECT  2.16 18.225 127.44 18.495 ;
     RECT  2.16 18.765 127.44 19.035 ;
     RECT  2.16 19.305 127.44 19.575 ;
     RECT  2.16 19.845 127.44 20.115 ;
     RECT  2.16 20.385 127.44 20.655 ;
     RECT  2.16 20.925 127.44 21.195 ;
     RECT  2.16 21.465 127.44 21.735 ;
     RECT  2.16 22.005 127.44 22.275 ;
     RECT  2.16 22.545 127.44 22.815 ;
     RECT  2.16 23.085 127.44 23.355 ;
     RECT  2.16 23.625 127.44 23.895 ;
     RECT  2.16 24.165 127.44 24.435 ;
     RECT  2.16 24.705 127.44 24.975 ;
     RECT  2.16 25.245 127.44 25.515 ;
     RECT  2.16 25.785 127.44 26.055 ;
     RECT  2.16 26.325 127.44 26.595 ;
     RECT  2.16 26.865 127.44 27.135 ;
     RECT  2.16 27.405 127.44 27.675 ;
     RECT  2.16 27.945 127.44 28.215 ;
     RECT  2.16 28.485 127.44 28.755 ;
     RECT  2.16 29.025 127.44 29.295 ;
     RECT  2.16 29.565 127.44 29.835 ;
     RECT  2.16 30.105 127.44 30.375 ;
     RECT  2.16 30.645 127.44 30.915 ;
     RECT  2.16 31.185 127.44 31.455 ;
     RECT  2.16 31.725 127.44 31.995 ;
     RECT  2.16 32.265 127.44 32.535 ;
     RECT  2.16 32.805 127.44 33.075 ;
     RECT  2.16 33.345 127.44 33.615 ;
     RECT  2.16 33.885 127.44 34.155 ;
     RECT  2.16 34.425 127.44 34.695 ;
     RECT  2.16 34.965 127.44 35.235 ;
     RECT  2.16 35.505 127.44 35.775 ;
     RECT  2.16 36.045 127.44 36.315 ;
     RECT  2.16 36.585 127.44 36.855 ;
     RECT  2.16 37.125 127.44 37.395 ;
     RECT  2.16 37.665 127.44 37.935 ;
     RECT  2.16 38.205 127.44 38.475 ;
     RECT  2.16 38.745 127.44 39.015 ;
     RECT  2.16 39.285 127.44 39.555 ;
     RECT  2.16 39.825 127.44 40.095 ;
     RECT  2.16 40.365 127.44 40.635 ;
     RECT  2.16 40.905 127.44 41.175 ;
     RECT  2.16 41.445 127.44 41.715 ;
     RECT  2.16 41.985 127.44 42.255 ;
     RECT  2.16 42.525 127.44 42.795 ;
     RECT  2.16 43.065 127.44 43.335 ;
     RECT  2.16 43.605 127.44 43.875 ;
     RECT  2.16 44.145 127.44 44.415 ;
     RECT  2.16 44.685 127.44 44.955 ;
     RECT  2.16 45.225 127.44 45.495 ;
     RECT  2.16 45.765 127.44 46.035 ;
     RECT  2.16 46.305 127.44 46.575 ;
     RECT  2.16 46.845 127.44 47.115 ;
     RECT  2.16 47.385 127.44 47.655 ;
     RECT  2.16 47.925 127.44 48.195 ;
     RECT  2.16 48.465 127.44 48.735 ;
     RECT  2.16 49.005 127.44 49.275 ;
     RECT  2.16 49.545 127.44 49.815 ;
     RECT  2.16 50.085 127.44 50.355 ;
     RECT  2.16 50.625 127.44 50.895 ;
     RECT  2.16 51.165 127.44 51.435 ;
     RECT  2.16 51.705 127.44 51.975 ;
     RECT  2.16 52.245 127.44 52.515 ;
     RECT  2.16 52.785 127.44 53.055 ;
     RECT  2.16 53.325 127.44 53.595 ;
     RECT  2.16 53.865 127.44 54.135 ;
     RECT  2.16 54.405 127.44 54.675 ;
     RECT  2.16 54.945 127.44 55.215 ;
     RECT  2.16 55.485 127.44 55.755 ;
     RECT  2.16 56.025 127.44 56.295 ;
     RECT  2.16 56.565 127.44 56.835 ;
     RECT  2.16 57.105 127.44 57.375 ;
     RECT  2.16 57.645 127.44 57.915 ;
     RECT  2.16 58.185 127.44 58.455 ;
     RECT  2.16 58.725 127.44 58.995 ;
     RECT  2.16 59.265 127.44 59.535 ;
     RECT  2.16 59.805 127.44 60.075 ;
     RECT  2.16 60.345 127.44 60.615 ;
     RECT  2.16 60.885 127.44 61.155 ;
     RECT  2.16 61.425 127.44 61.695 ;
     RECT  2.16 61.965 127.44 62.235 ;
     RECT  2.16 62.505 127.44 62.775 ;
     RECT  2.16 63.045 127.44 63.315 ;
     RECT  2.16 63.585 127.44 63.855 ;
     RECT  2.16 64.125 127.44 64.395 ;
     RECT  2.16 64.665 127.44 64.935 ;
     RECT  2.16 65.205 127.44 65.475 ;
     RECT  2.16 65.745 127.44 66.015 ;
     RECT  2.16 66.285 127.44 66.555 ;
     RECT  2.16 66.825 127.44 67.095 ;
     RECT  2.16 67.365 127.44 67.635 ;
     RECT  2.16 67.905 127.44 68.175 ;
     RECT  2.16 68.445 127.44 68.715 ;
     RECT  2.16 68.985 127.44 69.255 ;
     RECT  2.16 69.525 127.44 69.795 ;
     RECT  2.16 70.065 127.44 70.335 ;
     RECT  2.16 70.605 127.44 70.875 ;
     RECT  2.16 71.145 127.44 71.415 ;
     RECT  2.16 71.685 127.44 71.955 ;
     RECT  2.16 72.225 127.44 72.495 ;
     RECT  2.16 72.765 127.44 73.035 ;
     RECT  2.16 73.305 127.44 73.575 ;
     RECT  2.16 73.845 127.44 74.115 ;
     RECT  2.16 74.385 127.44 74.655 ;
     RECT  2.16 74.925 127.44 75.195 ;
     RECT  2.16 75.465 127.44 75.735 ;
     RECT  2.16 76.005 127.44 76.275 ;
     RECT  2.16 76.545 127.44 76.815 ;
     RECT  2.16 77.085 127.44 77.355 ;
     RECT  2.16 77.625 127.44 77.895 ;
     RECT  2.16 78.165 127.44 78.435 ;
     RECT  2.16 78.705 127.44 78.975 ;
     RECT  2.16 79.245 127.44 79.515 ;
     RECT  2.16 79.785 127.44 80.055 ;
     RECT  2.16 80.325 127.44 80.595 ;
     RECT  2.16 80.865 127.44 81.135 ;
     RECT  2.16 81.405 127.44 81.675 ;
     RECT  2.16 81.945 127.44 82.215 ;
     RECT  2.16 82.485 127.44 82.755 ;
     RECT  2.16 83.025 127.44 83.295 ;
     RECT  2.16 83.565 127.44 83.835 ;
     RECT  2.16 84.105 127.44 84.375 ;
     RECT  2.16 84.645 127.44 84.915 ;
     RECT  2.16 85.185 127.44 85.455 ;
     RECT  2.16 85.725 127.44 85.995 ;
     RECT  2.16 86.265 127.44 86.535 ;
     RECT  2.16 86.805 127.44 87.075 ;
     RECT  2.16 87.345 127.44 87.615 ;
     RECT  2.16 87.885 127.44 88.155 ;
     RECT  2.16 88.425 127.44 88.695 ;
     RECT  2.16 88.965 127.44 89.235 ;
     RECT  2.16 89.505 127.44 89.775 ;
     RECT  2.16 90.045 127.44 90.315 ;
     RECT  2.16 90.585 127.44 90.855 ;
     RECT  2.16 91.125 127.44 91.395 ;
     RECT  2.16 91.665 127.44 91.935 ;
     RECT  2.16 92.205 127.44 92.475 ;
     RECT  2.16 92.745 127.44 93.015 ;
     RECT  2.16 93.285 127.44 93.555 ;
     RECT  2.16 93.825 127.44 94.095 ;
     RECT  2.16 94.365 127.44 94.635 ;
     RECT  2.16 94.905 127.44 95.175 ;
     RECT  2.16 95.445 127.44 95.715 ;
     RECT  2.16 95.985 127.44 96.255 ;
     RECT  2.16 96.525 127.44 96.795 ;
     RECT  2.16 97.065 127.44 97.335 ;
     RECT  2.16 97.605 127.44 97.875 ;
     RECT  2.16 98.145 127.44 98.415 ;
     RECT  2.16 98.685 127.44 98.955 ;
     RECT  2.16 99.225 127.44 99.495 ;
     RECT  2.16 99.765 127.44 100.035 ;
     RECT  2.16 100.305 127.44 100.575 ;
     RECT  2.16 100.845 127.44 101.115 ;
     RECT  2.16 101.385 127.44 101.655 ;
     RECT  2.16 101.925 127.44 102.195 ;
     RECT  2.16 102.465 127.44 102.735 ;
     RECT  2.16 103.005 127.44 103.275 ;
     RECT  2.16 103.545 127.44 103.815 ;
     RECT  2.16 104.085 127.44 104.355 ;
     RECT  2.16 104.625 127.44 104.895 ;
     RECT  2.16 105.165 127.44 105.435 ;
     RECT  2.16 105.705 127.44 105.975 ;
     RECT  2.16 106.245 127.44 106.515 ;
     RECT  2.16 106.785 127.44 107.055 ;
     RECT  2.16 107.325 127.44 107.595 ;
     RECT  2.16 107.865 127.44 108.135 ;
     RECT  2.16 108.405 127.44 108.675 ;
     RECT  2.16 108.945 127.44 109.215 ;
     RECT  2.16 109.485 127.44 109.755 ;
     RECT  2.16 110.025 127.44 110.295 ;
     RECT  2.16 110.565 127.44 110.835 ;
     RECT  2.16 111.105 127.44 111.375 ;
     RECT  2.16 111.645 127.44 111.915 ;
     RECT  2.16 112.185 127.44 112.455 ;
     RECT  2.16 112.725 127.44 112.995 ;
     RECT  2.16 113.265 127.44 113.535 ;
     RECT  2.16 113.805 127.44 114.075 ;
     RECT  2.16 114.345 127.44 114.615 ;
     RECT  2.16 114.885 127.44 115.155 ;
     RECT  2.16 115.425 127.44 115.695 ;
     RECT  2.16 115.965 127.44 116.235 ;
     RECT  2.16 116.505 127.44 116.775 ;
     RECT  2.16 117.045 127.44 117.315 ;
     RECT  2.16 117.585 127.44 117.855 ;
     RECT  2.16 118.125 127.44 118.395 ;
     RECT  2.16 118.665 127.44 118.935 ;
     RECT  2.16 119.205 127.44 119.475 ;
     RECT  2.16 119.745 127.44 120.015 ;
     RECT  2.16 120.285 127.44 120.555 ;
     RECT  2.16 120.825 127.44 121.095 ;
     RECT  2.16 121.365 127.44 121.635 ;
     RECT  2.16 121.905 127.44 122.175 ;
     RECT  2.16 122.445 127.44 122.715 ;
     RECT  2.16 122.985 127.44 123.255 ;
     RECT  2.16 123.525 127.44 123.795 ;
     RECT  2.16 124.065 127.44 124.335 ;
     RECT  2.16 124.605 127.44 124.875 ;
     RECT  2.16 125.145 127.44 125.415 ;
     RECT  2.16 125.685 127.44 125.955 ;
     RECT  2.16 126.225 127.44 126.495 ;
     RECT  2.16 126.765 127.44 127.035 ;
     RECT  2.16 127.305 127.44 127.575 ;
     RECT  2.16 127.845 127.44 128.115 ;
     RECT  2.16 128.385 127.44 128.655 ;
     RECT  2.16 128.925 127.44 129.195 ;
     RECT  2.16 129.465 127.44 129.735 ;
     RECT  2.16 130.005 127.44 130.275 ;
     RECT  2.16 130.545 127.44 130.815 ;
     RECT  2.16 131.085 127.44 131.355 ;
     RECT  2.16 131.625 127.44 131.895 ;
     RECT  2.16 132.165 127.44 132.435 ;
     RECT  2.16 132.705 127.44 132.975 ;
     RECT  2.16 133.245 127.44 133.515 ;
     RECT  2.16 133.785 127.44 134.055 ;
     RECT  2.16 134.325 127.44 134.595 ;
     RECT  2.16 134.865 127.44 135.135 ;
     RECT  2.16 135.405 127.44 135.675 ;
     RECT  2.16 135.945 127.44 136.215 ;
     RECT  2.16 136.485 127.44 136.755 ;
     RECT  2.16 137.025 127.44 137.295 ;
     RECT  2.16 137.565 127.44 137.835 ;
     RECT  2.16 138.105 127.44 138.375 ;
     RECT  2.16 138.645 127.44 138.915 ;
     RECT  2.16 139.185 127.44 139.455 ;
     RECT  2.16 139.725 127.44 139.995 ;
     RECT  2.16 140.265 127.44 140.535 ;
     RECT  2.16 140.805 127.44 141.075 ;
     RECT  2.16 141.345 127.44 141.615 ;
     RECT  2.16 141.885 127.44 142.155 ;
     RECT  2.16 142.425 127.44 142.695 ;
     RECT  2.16 142.965 127.44 143.235 ;
     RECT  2.16 143.505 127.44 143.775 ;
     RECT  2.16 144.045 127.44 144.315 ;
     RECT  2.16 144.585 127.44 144.855 ;
     RECT  2.16 145.125 127.44 145.395 ;
     RECT  2.16 145.665 127.44 145.935 ;
     RECT  2.16 146.205 127.44 146.475 ;
     RECT  2.16 146.745 127.44 147.015 ;
     RECT  2.16 147.285 127.44 147.555 ;
     RECT  2.16 147.825 127.44 148.095 ;
     RECT  2.16 148.365 127.44 148.635 ;
     RECT  2.16 148.905 127.44 149.175 ;
     RECT  2.16 149.445 127.44 149.715 ;
     RECT  2.16 149.985 127.44 150.255 ;
     RECT  2.16 150.525 127.44 150.795 ;
     RECT  2.16 151.065 127.44 151.335 ;
     RECT  2.16 151.605 127.44 151.875 ;
     RECT  2.16 152.145 127.44 152.415 ;
     RECT  2.16 152.685 127.44 152.955 ;
     RECT  2.16 153.225 127.44 153.495 ;
     RECT  2.16 153.765 127.44 154.035 ;
     RECT  2.16 154.305 127.44 154.575 ;
     RECT  2.16 154.845 127.44 155.115 ;
     RECT  2.16 155.385 127.44 155.655 ;
     RECT  2.16 155.925 127.44 156.195 ;
     RECT  2.16 156.465 127.44 156.735 ;
     RECT  2.16 157.005 127.44 157.275 ;
     RECT  2.16 157.545 127.44 157.815 ;
     RECT  2.16 158.085 127.44 158.355 ;
     RECT  2.16 158.625 127.44 158.895 ;
     RECT  2.16 159.165 127.44 159.435 ;
     RECT  2.16 159.705 127.44 159.975 ;
     RECT  2.16 160.245 127.44 160.515 ;
     RECT  2.16 160.785 127.44 161.055 ;
     RECT  2.16 161.325 127.44 161.595 ;
     RECT  2.16 161.865 127.44 162.135 ;
     RECT  2.16 162.405 127.44 162.675 ;
     RECT  2.16 162.945 127.44 163.215 ;
     RECT  2.16 163.485 127.44 163.755 ;
     RECT  2.16 164.025 127.44 164.295 ;
     RECT  2.16 164.565 127.44 164.835 ;
     RECT  2.16 165.105 127.44 165.375 ;
     RECT  2.16 165.645 127.44 165.915 ;
     RECT  2.16 166.185 127.44 166.455 ;
     RECT  2.16 166.725 127.44 166.995 ;
     RECT  2.16 167.265 127.44 167.535 ;
     RECT  2.16 167.805 127.44 168.075 ;
     RECT  2.16 168.345 127.44 168.615 ;
     RECT  2.16 168.885 127.44 169.155 ;
     RECT  2.16 169.425 127.44 169.695 ;
     RECT  2.16 169.965 127.44 170.235 ;
     RECT  2.16 170.505 127.44 170.775 ;
     RECT  2.16 171.045 127.44 171.315 ;
     RECT  2.16 171.585 127.44 171.855 ;
     RECT  2.16 172.125 127.44 172.395 ;
     RECT  2.16 172.665 127.44 172.935 ;
     RECT  2.16 173.205 127.44 173.475 ;
     RECT  2.16 173.745 127.44 174.015 ;
     RECT  2.16 174.285 127.44 174.555 ;
     RECT  2.16 174.825 127.44 175.095 ;
     RECT  2.16 175.365 127.44 175.635 ;
     RECT  2.16 175.905 127.44 176.175 ;
     RECT  2.16 176.445 127.44 176.715 ;
     RECT  2.16 176.985 127.44 177.255 ;
     RECT  2.16 177.525 127.44 177.795 ;
     RECT  2.16 178.065 127.44 178.335 ;
     RECT  2.16 178.605 127.44 178.875 ;
     RECT  2.16 179.145 127.44 179.415 ;
     RECT  2.16 179.685 127.44 179.955 ;
     RECT  2.16 180.225 127.44 180.495 ;
     RECT  2.16 180.765 127.44 181.035 ;
     RECT  2.16 181.305 127.44 181.44 ;
    LAYER RVTP ;
     RECT  2.16 2.295 127.44 2.565 ;
     RECT  2.16 2.835 127.44 3.105 ;
     RECT  2.16 3.375 127.44 3.645 ;
     RECT  2.16 3.915 127.44 4.185 ;
     RECT  2.16 4.455 127.44 4.725 ;
     RECT  2.16 4.995 127.44 5.265 ;
     RECT  2.16 5.535 127.44 5.805 ;
     RECT  2.16 6.075 127.44 6.345 ;
     RECT  2.16 6.615 127.44 6.885 ;
     RECT  2.16 7.155 127.44 7.425 ;
     RECT  2.16 7.695 127.44 7.965 ;
     RECT  2.16 8.235 127.44 8.505 ;
     RECT  2.16 8.775 127.44 9.045 ;
     RECT  2.16 9.315 127.44 9.585 ;
     RECT  2.16 9.855 127.44 10.125 ;
     RECT  2.16 10.395 127.44 10.665 ;
     RECT  2.16 10.935 127.44 11.205 ;
     RECT  2.16 11.475 127.44 11.745 ;
     RECT  2.16 12.015 127.44 12.285 ;
     RECT  2.16 12.555 127.44 12.825 ;
     RECT  2.16 13.095 127.44 13.365 ;
     RECT  2.16 13.635 127.44 13.905 ;
     RECT  2.16 14.175 127.44 14.445 ;
     RECT  2.16 14.715 127.44 14.985 ;
     RECT  2.16 15.255 127.44 15.525 ;
     RECT  2.16 15.795 127.44 16.065 ;
     RECT  2.16 16.335 127.44 16.605 ;
     RECT  2.16 16.875 127.44 17.145 ;
     RECT  2.16 17.415 127.44 17.685 ;
     RECT  2.16 17.955 127.44 18.225 ;
     RECT  2.16 18.495 127.44 18.765 ;
     RECT  2.16 19.035 127.44 19.305 ;
     RECT  2.16 19.575 127.44 19.845 ;
     RECT  2.16 20.115 127.44 20.385 ;
     RECT  2.16 20.655 127.44 20.925 ;
     RECT  2.16 21.195 127.44 21.465 ;
     RECT  2.16 21.735 127.44 22.005 ;
     RECT  2.16 22.275 127.44 22.545 ;
     RECT  2.16 22.815 127.44 23.085 ;
     RECT  2.16 23.355 127.44 23.625 ;
     RECT  2.16 23.895 127.44 24.165 ;
     RECT  2.16 24.435 127.44 24.705 ;
     RECT  2.16 24.975 127.44 25.245 ;
     RECT  2.16 25.515 127.44 25.785 ;
     RECT  2.16 26.055 127.44 26.325 ;
     RECT  2.16 26.595 127.44 26.865 ;
     RECT  2.16 27.135 127.44 27.405 ;
     RECT  2.16 27.675 127.44 27.945 ;
     RECT  2.16 28.215 127.44 28.485 ;
     RECT  2.16 28.755 127.44 29.025 ;
     RECT  2.16 29.295 127.44 29.565 ;
     RECT  2.16 29.835 127.44 30.105 ;
     RECT  2.16 30.375 127.44 30.645 ;
     RECT  2.16 30.915 127.44 31.185 ;
     RECT  2.16 31.455 127.44 31.725 ;
     RECT  2.16 31.995 127.44 32.265 ;
     RECT  2.16 32.535 127.44 32.805 ;
     RECT  2.16 33.075 127.44 33.345 ;
     RECT  2.16 33.615 127.44 33.885 ;
     RECT  2.16 34.155 127.44 34.425 ;
     RECT  2.16 34.695 127.44 34.965 ;
     RECT  2.16 35.235 127.44 35.505 ;
     RECT  2.16 35.775 127.44 36.045 ;
     RECT  2.16 36.315 127.44 36.585 ;
     RECT  2.16 36.855 127.44 37.125 ;
     RECT  2.16 37.395 127.44 37.665 ;
     RECT  2.16 37.935 127.44 38.205 ;
     RECT  2.16 38.475 127.44 38.745 ;
     RECT  2.16 39.015 127.44 39.285 ;
     RECT  2.16 39.555 127.44 39.825 ;
     RECT  2.16 40.095 127.44 40.365 ;
     RECT  2.16 40.635 127.44 40.905 ;
     RECT  2.16 41.175 127.44 41.445 ;
     RECT  2.16 41.715 127.44 41.985 ;
     RECT  2.16 42.255 127.44 42.525 ;
     RECT  2.16 42.795 127.44 43.065 ;
     RECT  2.16 43.335 127.44 43.605 ;
     RECT  2.16 43.875 127.44 44.145 ;
     RECT  2.16 44.415 127.44 44.685 ;
     RECT  2.16 44.955 127.44 45.225 ;
     RECT  2.16 45.495 127.44 45.765 ;
     RECT  2.16 46.035 127.44 46.305 ;
     RECT  2.16 46.575 127.44 46.845 ;
     RECT  2.16 47.115 127.44 47.385 ;
     RECT  2.16 47.655 127.44 47.925 ;
     RECT  2.16 48.195 127.44 48.465 ;
     RECT  2.16 48.735 127.44 49.005 ;
     RECT  2.16 49.275 127.44 49.545 ;
     RECT  2.16 49.815 127.44 50.085 ;
     RECT  2.16 50.355 127.44 50.625 ;
     RECT  2.16 50.895 127.44 51.165 ;
     RECT  2.16 51.435 127.44 51.705 ;
     RECT  2.16 51.975 127.44 52.245 ;
     RECT  2.16 52.515 127.44 52.785 ;
     RECT  2.16 53.055 127.44 53.325 ;
     RECT  2.16 53.595 127.44 53.865 ;
     RECT  2.16 54.135 127.44 54.405 ;
     RECT  2.16 54.675 127.44 54.945 ;
     RECT  2.16 55.215 127.44 55.485 ;
     RECT  2.16 55.755 127.44 56.025 ;
     RECT  2.16 56.295 127.44 56.565 ;
     RECT  2.16 56.835 127.44 57.105 ;
     RECT  2.16 57.375 127.44 57.645 ;
     RECT  2.16 57.915 127.44 58.185 ;
     RECT  2.16 58.455 127.44 58.725 ;
     RECT  2.16 58.995 127.44 59.265 ;
     RECT  2.16 59.535 127.44 59.805 ;
     RECT  2.16 60.075 127.44 60.345 ;
     RECT  2.16 60.615 127.44 60.885 ;
     RECT  2.16 61.155 127.44 61.425 ;
     RECT  2.16 61.695 127.44 61.965 ;
     RECT  2.16 62.235 127.44 62.505 ;
     RECT  2.16 62.775 127.44 63.045 ;
     RECT  2.16 63.315 127.44 63.585 ;
     RECT  2.16 63.855 127.44 64.125 ;
     RECT  2.16 64.395 127.44 64.665 ;
     RECT  2.16 64.935 127.44 65.205 ;
     RECT  2.16 65.475 127.44 65.745 ;
     RECT  2.16 66.015 127.44 66.285 ;
     RECT  2.16 66.555 127.44 66.825 ;
     RECT  2.16 67.095 127.44 67.365 ;
     RECT  2.16 67.635 127.44 67.905 ;
     RECT  2.16 68.175 127.44 68.445 ;
     RECT  2.16 68.715 127.44 68.985 ;
     RECT  2.16 69.255 127.44 69.525 ;
     RECT  2.16 69.795 127.44 70.065 ;
     RECT  2.16 70.335 127.44 70.605 ;
     RECT  2.16 70.875 127.44 71.145 ;
     RECT  2.16 71.415 127.44 71.685 ;
     RECT  2.16 71.955 127.44 72.225 ;
     RECT  2.16 72.495 127.44 72.765 ;
     RECT  2.16 73.035 127.44 73.305 ;
     RECT  2.16 73.575 127.44 73.845 ;
     RECT  2.16 74.115 127.44 74.385 ;
     RECT  2.16 74.655 127.44 74.925 ;
     RECT  2.16 75.195 127.44 75.465 ;
     RECT  2.16 75.735 127.44 76.005 ;
     RECT  2.16 76.275 127.44 76.545 ;
     RECT  2.16 76.815 127.44 77.085 ;
     RECT  2.16 77.355 127.44 77.625 ;
     RECT  2.16 77.895 127.44 78.165 ;
     RECT  2.16 78.435 127.44 78.705 ;
     RECT  2.16 78.975 127.44 79.245 ;
     RECT  2.16 79.515 127.44 79.785 ;
     RECT  2.16 80.055 127.44 80.325 ;
     RECT  2.16 80.595 127.44 80.865 ;
     RECT  2.16 81.135 127.44 81.405 ;
     RECT  2.16 81.675 127.44 81.945 ;
     RECT  2.16 82.215 127.44 82.485 ;
     RECT  2.16 82.755 127.44 83.025 ;
     RECT  2.16 83.295 127.44 83.565 ;
     RECT  2.16 83.835 127.44 84.105 ;
     RECT  2.16 84.375 127.44 84.645 ;
     RECT  2.16 84.915 127.44 85.185 ;
     RECT  2.16 85.455 127.44 85.725 ;
     RECT  2.16 85.995 127.44 86.265 ;
     RECT  2.16 86.535 127.44 86.805 ;
     RECT  2.16 87.075 127.44 87.345 ;
     RECT  2.16 87.615 127.44 87.885 ;
     RECT  2.16 88.155 127.44 88.425 ;
     RECT  2.16 88.695 127.44 88.965 ;
     RECT  2.16 89.235 127.44 89.505 ;
     RECT  2.16 89.775 127.44 90.045 ;
     RECT  2.16 90.315 127.44 90.585 ;
     RECT  2.16 90.855 127.44 91.125 ;
     RECT  2.16 91.395 127.44 91.665 ;
     RECT  2.16 91.935 127.44 92.205 ;
     RECT  2.16 92.475 127.44 92.745 ;
     RECT  2.16 93.015 127.44 93.285 ;
     RECT  2.16 93.555 127.44 93.825 ;
     RECT  2.16 94.095 127.44 94.365 ;
     RECT  2.16 94.635 127.44 94.905 ;
     RECT  2.16 95.175 127.44 95.445 ;
     RECT  2.16 95.715 127.44 95.985 ;
     RECT  2.16 96.255 127.44 96.525 ;
     RECT  2.16 96.795 127.44 97.065 ;
     RECT  2.16 97.335 127.44 97.605 ;
     RECT  2.16 97.875 127.44 98.145 ;
     RECT  2.16 98.415 127.44 98.685 ;
     RECT  2.16 98.955 127.44 99.225 ;
     RECT  2.16 99.495 127.44 99.765 ;
     RECT  2.16 100.035 127.44 100.305 ;
     RECT  2.16 100.575 127.44 100.845 ;
     RECT  2.16 101.115 127.44 101.385 ;
     RECT  2.16 101.655 127.44 101.925 ;
     RECT  2.16 102.195 127.44 102.465 ;
     RECT  2.16 102.735 127.44 103.005 ;
     RECT  2.16 103.275 127.44 103.545 ;
     RECT  2.16 103.815 127.44 104.085 ;
     RECT  2.16 104.355 127.44 104.625 ;
     RECT  2.16 104.895 127.44 105.165 ;
     RECT  2.16 105.435 127.44 105.705 ;
     RECT  2.16 105.975 127.44 106.245 ;
     RECT  2.16 106.515 127.44 106.785 ;
     RECT  2.16 107.055 127.44 107.325 ;
     RECT  2.16 107.595 127.44 107.865 ;
     RECT  2.16 108.135 127.44 108.405 ;
     RECT  2.16 108.675 127.44 108.945 ;
     RECT  2.16 109.215 127.44 109.485 ;
     RECT  2.16 109.755 127.44 110.025 ;
     RECT  2.16 110.295 127.44 110.565 ;
     RECT  2.16 110.835 127.44 111.105 ;
     RECT  2.16 111.375 127.44 111.645 ;
     RECT  2.16 111.915 127.44 112.185 ;
     RECT  2.16 112.455 127.44 112.725 ;
     RECT  2.16 112.995 127.44 113.265 ;
     RECT  2.16 113.535 127.44 113.805 ;
     RECT  2.16 114.075 127.44 114.345 ;
     RECT  2.16 114.615 127.44 114.885 ;
     RECT  2.16 115.155 127.44 115.425 ;
     RECT  2.16 115.695 127.44 115.965 ;
     RECT  2.16 116.235 127.44 116.505 ;
     RECT  2.16 116.775 127.44 117.045 ;
     RECT  2.16 117.315 127.44 117.585 ;
     RECT  2.16 117.855 127.44 118.125 ;
     RECT  2.16 118.395 127.44 118.665 ;
     RECT  2.16 118.935 127.44 119.205 ;
     RECT  2.16 119.475 127.44 119.745 ;
     RECT  2.16 120.015 127.44 120.285 ;
     RECT  2.16 120.555 127.44 120.825 ;
     RECT  2.16 121.095 127.44 121.365 ;
     RECT  2.16 121.635 127.44 121.905 ;
     RECT  2.16 122.175 127.44 122.445 ;
     RECT  2.16 122.715 127.44 122.985 ;
     RECT  2.16 123.255 127.44 123.525 ;
     RECT  2.16 123.795 127.44 124.065 ;
     RECT  2.16 124.335 127.44 124.605 ;
     RECT  2.16 124.875 127.44 125.145 ;
     RECT  2.16 125.415 127.44 125.685 ;
     RECT  2.16 125.955 127.44 126.225 ;
     RECT  2.16 126.495 127.44 126.765 ;
     RECT  2.16 127.035 127.44 127.305 ;
     RECT  2.16 127.575 127.44 127.845 ;
     RECT  2.16 128.115 127.44 128.385 ;
     RECT  2.16 128.655 127.44 128.925 ;
     RECT  2.16 129.195 127.44 129.465 ;
     RECT  2.16 129.735 127.44 130.005 ;
     RECT  2.16 130.275 127.44 130.545 ;
     RECT  2.16 130.815 127.44 131.085 ;
     RECT  2.16 131.355 127.44 131.625 ;
     RECT  2.16 131.895 127.44 132.165 ;
     RECT  2.16 132.435 127.44 132.705 ;
     RECT  2.16 132.975 127.44 133.245 ;
     RECT  2.16 133.515 127.44 133.785 ;
     RECT  2.16 134.055 127.44 134.325 ;
     RECT  2.16 134.595 127.44 134.865 ;
     RECT  2.16 135.135 127.44 135.405 ;
     RECT  2.16 135.675 127.44 135.945 ;
     RECT  2.16 136.215 127.44 136.485 ;
     RECT  2.16 136.755 127.44 137.025 ;
     RECT  2.16 137.295 127.44 137.565 ;
     RECT  2.16 137.835 127.44 138.105 ;
     RECT  2.16 138.375 127.44 138.645 ;
     RECT  2.16 138.915 127.44 139.185 ;
     RECT  2.16 139.455 127.44 139.725 ;
     RECT  2.16 139.995 127.44 140.265 ;
     RECT  2.16 140.535 127.44 140.805 ;
     RECT  2.16 141.075 127.44 141.345 ;
     RECT  2.16 141.615 127.44 141.885 ;
     RECT  2.16 142.155 127.44 142.425 ;
     RECT  2.16 142.695 127.44 142.965 ;
     RECT  2.16 143.235 127.44 143.505 ;
     RECT  2.16 143.775 127.44 144.045 ;
     RECT  2.16 144.315 127.44 144.585 ;
     RECT  2.16 144.855 127.44 145.125 ;
     RECT  2.16 145.395 127.44 145.665 ;
     RECT  2.16 145.935 127.44 146.205 ;
     RECT  2.16 146.475 127.44 146.745 ;
     RECT  2.16 147.015 127.44 147.285 ;
     RECT  2.16 147.555 127.44 147.825 ;
     RECT  2.16 148.095 127.44 148.365 ;
     RECT  2.16 148.635 127.44 148.905 ;
     RECT  2.16 149.175 127.44 149.445 ;
     RECT  2.16 149.715 127.44 149.985 ;
     RECT  2.16 150.255 127.44 150.525 ;
     RECT  2.16 150.795 127.44 151.065 ;
     RECT  2.16 151.335 127.44 151.605 ;
     RECT  2.16 151.875 127.44 152.145 ;
     RECT  2.16 152.415 127.44 152.685 ;
     RECT  2.16 152.955 127.44 153.225 ;
     RECT  2.16 153.495 127.44 153.765 ;
     RECT  2.16 154.035 127.44 154.305 ;
     RECT  2.16 154.575 127.44 154.845 ;
     RECT  2.16 155.115 127.44 155.385 ;
     RECT  2.16 155.655 127.44 155.925 ;
     RECT  2.16 156.195 127.44 156.465 ;
     RECT  2.16 156.735 127.44 157.005 ;
     RECT  2.16 157.275 127.44 157.545 ;
     RECT  2.16 157.815 127.44 158.085 ;
     RECT  2.16 158.355 127.44 158.625 ;
     RECT  2.16 158.895 127.44 159.165 ;
     RECT  2.16 159.435 127.44 159.705 ;
     RECT  2.16 159.975 127.44 160.245 ;
     RECT  2.16 160.515 127.44 160.785 ;
     RECT  2.16 161.055 127.44 161.325 ;
     RECT  2.16 161.595 127.44 161.865 ;
     RECT  2.16 162.135 127.44 162.405 ;
     RECT  2.16 162.675 127.44 162.945 ;
     RECT  2.16 163.215 127.44 163.485 ;
     RECT  2.16 163.755 127.44 164.025 ;
     RECT  2.16 164.295 127.44 164.565 ;
     RECT  2.16 164.835 127.44 165.105 ;
     RECT  2.16 165.375 127.44 165.645 ;
     RECT  2.16 165.915 127.44 166.185 ;
     RECT  2.16 166.455 127.44 166.725 ;
     RECT  2.16 166.995 127.44 167.265 ;
     RECT  2.16 167.535 127.44 167.805 ;
     RECT  2.16 168.075 127.44 168.345 ;
     RECT  2.16 168.615 127.44 168.885 ;
     RECT  2.16 169.155 127.44 169.425 ;
     RECT  2.16 169.695 127.44 169.965 ;
     RECT  2.16 170.235 127.44 170.505 ;
     RECT  2.16 170.775 127.44 171.045 ;
     RECT  2.16 171.315 127.44 171.585 ;
     RECT  2.16 171.855 127.44 172.125 ;
     RECT  2.16 172.395 127.44 172.665 ;
     RECT  2.16 172.935 127.44 173.205 ;
     RECT  2.16 173.475 127.44 173.745 ;
     RECT  2.16 174.015 127.44 174.285 ;
     RECT  2.16 174.555 127.44 174.825 ;
     RECT  2.16 175.095 127.44 175.365 ;
     RECT  2.16 175.635 127.44 175.905 ;
     RECT  2.16 176.175 127.44 176.445 ;
     RECT  2.16 176.715 127.44 176.985 ;
     RECT  2.16 177.255 127.44 177.525 ;
     RECT  2.16 177.795 127.44 178.065 ;
     RECT  2.16 178.335 127.44 178.605 ;
     RECT  2.16 178.875 127.44 179.145 ;
     RECT  2.16 179.415 127.44 179.685 ;
     RECT  2.16 179.955 127.44 180.225 ;
     RECT  2.16 180.495 127.44 180.765 ;
     RECT  2.16 181.035 127.44 181.305 ;
    LAYER M1 ;
     RECT  2.16 2.151 127.44 181.449 ;
    LAYER M2 ;
     RECT  1.111 2.646 1.975 2.664 ;
     RECT  1.975 2.106 2.16 2.664 ;
     RECT  1.939 6.516 2.16 6.534 ;
     RECT  1.723 8.406 2.16 8.424 ;
     RECT  1.687 180.27 2.16 180.288 ;
     RECT  1.111 181.116 2.16 181.134 ;
     RECT  2.16 2.106 3.047 181.449 ;
     RECT  3.047 2.151 13.027 181.449 ;
     RECT  13.027 2.106 13.415 181.449 ;
     RECT  13.415 2.151 14.755 181.449 ;
     RECT  14.755 2.106 15.071 181.449 ;
     RECT  15.071 2.151 23.107 181.449 ;
     RECT  23.107 2.106 23.495 181.449 ;
     RECT  23.495 2.151 32.755 181.449 ;
     RECT  32.755 2.106 33.827 181.449 ;
     RECT  33.827 2.151 37.975 181.449 ;
     RECT  37.975 2.106 38.363 181.449 ;
     RECT  38.363 2.151 39.271 181.449 ;
     RECT  39.271 2.106 40.127 181.449 ;
     RECT  40.063 1.152 40.199 1.17 ;
     RECT  40.127 2.151 41.575 181.449 ;
     RECT  41.575 2.106 41.855 181.449 ;
     RECT  41.855 2.151 43.303 181.449 ;
     RECT  43.303 2.106 43.655 181.449 ;
     RECT  43.655 2.151 47.695 181.449 ;
     RECT  47.695 2.106 48.083 181.449 ;
     RECT  48.083 2.151 51.187 181.449 ;
     RECT  51.187 2.106 51.683 181.449 ;
     RECT  51.683 2.151 52.987 181.449 ;
     RECT  52.987 2.106 53.087 181.449 ;
     RECT  53.087 2.151 54.679 181.449 ;
     RECT  54.679 2.106 54.887 181.449 ;
     RECT  54.887 2.151 64.867 181.449 ;
     RECT  64.867 2.106 65.255 181.449 ;
     RECT  65.255 2.151 68.323 181.449 ;
     RECT  68.323 2.106 68.963 181.449 ;
     RECT  68.963 2.151 70.087 181.449 ;
     RECT  70.087 2.106 70.475 181.449 ;
     RECT  70.475 2.151 77.971 181.449 ;
     RECT  77.971 2.106 78.431 181.449 ;
     RECT  78.431 2.151 79.735 181.449 ;
     RECT  79.735 2.106 80.087 181.449 ;
     RECT  80.087 2.151 85.927 181.449 ;
     RECT  85.927 2.106 86.423 181.449 ;
     RECT  86.423 2.151 87.655 181.449 ;
     RECT  87.655 2.106 88.043 181.449 ;
     RECT  88.043 2.151 89.383 181.449 ;
     RECT  89.383 2.106 89.771 181.449 ;
     RECT  89.771 2.151 91.183 181.449 ;
     RECT  91.183 2.106 91.967 181.449 ;
     RECT  91.967 2.151 93.811 181.449 ;
     RECT  93.811 2.106 94.199 181.449 ;
     RECT  94.199 2.151 95.539 181.449 ;
     RECT  95.539 2.106 96.035 181.449 ;
     RECT  96.035 2.151 102.559 181.449 ;
     RECT  102.559 2.106 102.983 181.449 ;
     RECT  102.983 2.151 105.223 181.449 ;
     RECT  105.223 2.106 105.575 181.449 ;
     RECT  105.575 2.151 109.219 181.449 ;
     RECT  109.219 2.106 109.571 181.449 ;
     RECT  109.571 2.151 110.947 181.449 ;
     RECT  110.947 2.106 111.407 181.449 ;
     RECT  111.407 2.151 112.675 181.449 ;
     RECT  112.675 2.106 113.099 181.449 ;
     RECT  113.099 2.151 114.439 181.449 ;
     RECT  114.439 2.106 114.827 181.449 ;
     RECT  114.827 2.151 116.239 181.449 ;
     RECT  116.239 2.106 116.447 181.449 ;
     RECT  119.443 1.152 119.543 1.17 ;
     RECT  116.447 2.151 121.567 181.449 ;
     RECT  121.567 2.106 124.979 181.449 ;
     RECT  124.979 2.151 126.211 181.449 ;
     RECT  126.211 2.106 126.499 181.449 ;
     RECT  126.499 2.07 127.44 181.449 ;
     RECT  127.44 2.07 127.607 2.754 ;
     RECT  127.607 2.106 127.643 2.754 ;
     RECT  127.44 3.582 128.255 3.6 ;
     RECT  127.44 180.81 128.291 180.828 ;
     RECT  127.643 2.232 128.831 2.754 ;
     RECT  127.44 94.032 128.831 94.05 ;
     RECT  127.44 127.386 128.831 127.404 ;
     RECT  128.831 2.232 128.939 2.25 ;
    LAYER M3 ;
     RECT  8.856 0.091 8.874 0.139 ;
     RECT  13.644 0.091 16.254 0.139 ;
     RECT  25.956 0.091 25.974 0.139 ;
     RECT  54.576 0.091 54.594 0.139 ;
     RECT  73.332 0.091 73.782 0.139 ;
     RECT  80.136 0.091 82.926 0.139 ;
     RECT  90.504 0.091 90.954 0.139 ;
     RECT  13.536 0.139 16.254 0.187 ;
     RECT  98.424 0.091 98.874 0.187 ;
     RECT  109.98 0.139 109.998 0.187 ;
     RECT  18.468 0.139 18.486 0.235 ;
     RECT  21.636 0.139 22.626 0.235 ;
     RECT  40.86 0.139 41.31 0.235 ;
     RECT  42.156 0.139 43.002 0.235 ;
     RECT  45.288 0.139 45.306 0.235 ;
     RECT  80.136 0.139 83.322 0.235 ;
     RECT  109.98 0.187 110.106 0.235 ;
     RECT  109.62 0.235 110.106 0.283 ;
     RECT  8.136 0.139 8.874 0.523 ;
     RECT  9.756 0.091 9.774 0.523 ;
     RECT  11.34 0.091 12.258 0.523 ;
     RECT  40.68 0.235 41.418 0.523 ;
     RECT  48.276 0.091 48.762 0.523 ;
     RECT  52.956 0.091 52.974 0.523 ;
     RECT  73.332 0.139 74.034 0.523 ;
     RECT  85.896 0.139 88.074 0.523 ;
     RECT  92.232 0.091 93.222 0.523 ;
     RECT  98.388 0.187 98.874 0.523 ;
     RECT  111.6 0.139 112.158 0.523 ;
     RECT  113.328 0.091 114.318 0.523 ;
     RECT  115.164 0.091 117.738 0.523 ;
     RECT  124.884 0.043 124.902 0.523 ;
     RECT  126.288 0.139 126.306 0.523 ;
     RECT  128.916 0.139 128.934 0.523 ;
     RECT  2.556 0.235 2.574 0.571 ;
     RECT  4.788 0.091 4.806 0.571 ;
     RECT  8.136 0.523 9.774 0.571 ;
     RECT  11.34 0.523 12.69 0.571 ;
     RECT  13.536 0.187 16.29 0.571 ;
     RECT  17.496 0.091 17.514 0.571 ;
     RECT  18.36 0.235 18.486 0.571 ;
     RECT  20.196 0.139 20.214 0.571 ;
     RECT  23.76 0.139 23.778 0.571 ;
     RECT  25.38 0.139 25.974 0.571 ;
     RECT  26.712 0.091 28.278 0.571 ;
     RECT  29.304 0.091 30.186 0.571 ;
     RECT  31.14 0.091 31.662 0.571 ;
     RECT  32.4 0.091 32.418 0.571 ;
     RECT  33.372 0.091 33.39 0.571 ;
     RECT  34.668 0.091 35.694 0.571 ;
     RECT  37.26 0.091 37.854 0.571 ;
     RECT  46.26 0.475 46.278 0.571 ;
     RECT  47.124 0.091 47.142 0.571 ;
     RECT  52.956 0.523 53.154 0.571 ;
     RECT  54.468 0.139 54.594 0.571 ;
     RECT  56.196 0.091 56.718 0.571 ;
     RECT  57.492 0.091 58.59 0.571 ;
     RECT  63.108 0.139 63.63 0.571 ;
     RECT  68.904 0.091 68.922 0.571 ;
     RECT  69.876 0.091 72.558 0.571 ;
     RECT  73.332 0.523 74.682 0.571 ;
     RECT  78.552 0.091 79.11 0.571 ;
     RECT  80.136 0.235 83.574 0.571 ;
     RECT  85.86 0.523 88.074 0.571 ;
     RECT  89.82 0.139 90.954 0.571 ;
     RECT  91.872 0.523 93.222 0.571 ;
     RECT  93.996 0.091 95.094 0.571 ;
     RECT  96.156 0.091 96.57 0.571 ;
     RECT  106.56 0.139 106.578 0.571 ;
     RECT  111.24 0.523 114.318 0.571 ;
     RECT  115.164 0.523 118.17 0.571 ;
     RECT  121.608 0.475 121.626 0.571 ;
     RECT  124.884 0.523 125.01 0.571 ;
     RECT  126.288 0.523 127.314 0.619 ;
     RECT  128.232 0.523 128.934 0.619 ;
     RECT  91.872 0.571 95.094 1.099 ;
     RECT  96.048 0.571 96.57 1.099 ;
     RECT  2.556 0.571 3.114 1.147 ;
     RECT  4.428 0.571 4.806 1.147 ;
     RECT  6.048 0.091 6.75 1.147 ;
     RECT  19.62 0.571 20.214 1.147 ;
     RECT  21.564 0.235 22.626 1.147 ;
     RECT  23.508 0.571 33.39 1.147 ;
     RECT  34.308 0.571 35.694 1.147 ;
     RECT  36.432 0.571 37.854 1.147 ;
     RECT  39.24 0.571 39.258 1.147 ;
     RECT  40.068 0.523 41.418 1.147 ;
     RECT  42.156 0.235 43.038 1.147 ;
     RECT  44.64 0.235 45.306 1.147 ;
     RECT  46.044 0.571 47.142 1.147 ;
     RECT  47.988 0.523 48.762 1.147 ;
     RECT  50.292 0.091 50.922 1.147 ;
     RECT  51.804 0.571 51.822 1.147 ;
     RECT  52.812 0.571 58.698 1.147 ;
     RECT  59.724 0.571 60.318 1.147 ;
     RECT  61.74 0.571 62.334 1.147 ;
     RECT  63.108 0.571 64.602 1.147 ;
     RECT  65.448 0.139 65.466 1.147 ;
     RECT  66.564 0.139 66.582 1.147 ;
     RECT  67.536 0.139 68.166 1.147 ;
     RECT  68.904 0.571 69.138 1.147 ;
     RECT  69.876 0.571 74.682 1.147 ;
     RECT  77.364 0.091 77.778 1.147 ;
     RECT  78.552 0.571 83.574 1.147 ;
     RECT  85.14 0.571 90.954 1.147 ;
     RECT  91.872 1.099 96.57 1.147 ;
     RECT  101.844 0.091 101.862 1.147 ;
     RECT  102.708 0.091 102.726 1.147 ;
     RECT  104.148 0.091 104.562 1.147 ;
     RECT  107.712 0.139 108.594 1.147 ;
     RECT  109.62 0.283 110.25 1.147 ;
     RECT  111.24 0.571 118.17 1.147 ;
     RECT  119.052 0.091 120.402 1.147 ;
     RECT  121.176 0.571 121.662 1.147 ;
     RECT  123.048 0.571 123.498 1.147 ;
     RECT  124.704 0.571 125.01 1.147 ;
     RECT  1.98 1.147 3.114 1.723 ;
     RECT  4.428 1.147 6.75 1.723 ;
     RECT  49.572 1.147 60.39 1.723 ;
     RECT  61.38 1.147 66.69 1.723 ;
     RECT  97.632 0.091 97.65 1.723 ;
     RECT  119.052 1.147 121.662 1.723 ;
     RECT  126.288 0.619 128.934 1.723 ;
     RECT  17.496 0.571 18.486 2.011 ;
     RECT  19.368 1.147 20.214 2.011 ;
     RECT  36.432 1.147 37.998 2.101 ;
     RECT  39.24 1.147 43.326 2.101 ;
     RECT  101.844 1.147 102.726 2.101 ;
     RECT  103.716 1.147 105.246 2.101 ;
     RECT  106.2 0.571 106.578 2.101 ;
     RECT  1.98 1.723 6.75 2.129 ;
     RECT  101.844 2.101 102.978 2.129 ;
     RECT  125.784 1.723 128.934 2.129 ;
     RECT  44.424 1.147 45.306 2.143 ;
     RECT  46.044 1.147 48.762 2.143 ;
     RECT  49.572 1.723 66.69 2.143 ;
     RECT  67.536 1.147 74.682 2.143 ;
     RECT  98.388 0.523 99.198 2.143 ;
     RECT  100.152 0.091 101.106 2.143 ;
     RECT  119.052 1.723 122.238 2.191 ;
     RECT  123.048 1.147 125.01 2.191 ;
     RECT  21.564 1.147 35.694 2.227 ;
     RECT  49.572 2.143 74.682 2.227 ;
     RECT  77.364 1.147 83.574 2.227 ;
     RECT  97.38 1.723 97.65 2.227 ;
     RECT  98.388 2.143 101.106 2.227 ;
     RECT  119.052 2.191 125.01 2.227 ;
     RECT  77.292 2.227 83.574 2.251 ;
     RECT  84.348 1.147 84.366 2.251 ;
     RECT  128.232 2.129 128.934 2.255 ;
     RECT  2.376 2.129 6.75 2.263 ;
     RECT  7.632 0.571 10.098 2.263 ;
     RECT  11.34 0.571 16.758 2.263 ;
     RECT  17.496 2.011 20.214 2.263 ;
     RECT  39.24 2.101 43.65 2.263 ;
     RECT  49.5 2.227 74.682 2.263 ;
     RECT  97.38 2.227 101.106 2.263 ;
     RECT  101.844 2.129 101.862 2.263 ;
     RECT  102.6 2.129 102.978 2.263 ;
     RECT  103.716 2.101 106.578 2.263 ;
     RECT  118.98 2.227 125.01 2.263 ;
     RECT  125.784 2.129 127.35 2.263 ;
     RECT  11.34 2.263 20.214 2.299 ;
     RECT  21.528 2.227 35.694 2.299 ;
     RECT  36.432 2.101 38.358 2.299 ;
     RECT  39.168 2.263 43.65 2.299 ;
     RECT  44.424 2.143 48.762 2.299 ;
     RECT  49.5 2.263 74.718 2.299 ;
     RECT  77.292 2.251 84.366 2.299 ;
     RECT  85.14 1.147 96.57 2.299 ;
     RECT  97.38 2.263 101.862 2.299 ;
     RECT  118.98 2.263 127.35 2.299 ;
     RECT  107.712 1.147 118.17 2.335 ;
     RECT  21.528 2.299 38.358 2.569 ;
     RECT  39.168 2.299 74.718 2.569 ;
     RECT  75.744 0.091 76.446 2.605 ;
     RECT  2.376 2.263 10.098 2.641 ;
     RECT  10.836 2.299 20.214 2.641 ;
     RECT  21.528 2.569 74.718 2.641 ;
     RECT  75.636 2.605 76.446 2.641 ;
     RECT  77.292 2.299 101.862 2.641 ;
     RECT  107.604 2.335 118.17 2.641 ;
     RECT  1.116 2.299 1.134 2.669 ;
     RECT  128.232 2.255 128.826 2.759 ;
     RECT  107.352 2.641 118.17 2.767 ;
     RECT  118.944 2.299 127.35 2.767 ;
     RECT  2.376 2.641 20.214 2.875 ;
     RECT  20.952 2.641 101.862 2.875 ;
     RECT  102.6 2.263 106.578 2.875 ;
     RECT  107.352 2.767 127.35 2.875 ;
     RECT  2.376 2.875 101.862 2.911 ;
     RECT  102.6 2.875 127.35 2.911 ;
     RECT  2.376 2.911 127.35 3.307 ;
     RECT  128.232 2.759 128.25 3.605 ;
     RECT  2.304 3.307 127.35 4.559 ;
     RECT  2.415 4.559 127.35 5.575 ;
     RECT  2.34 5.575 127.35 6.283 ;
     RECT  1.944 6.283 127.35 6.539 ;
     RECT  2.34 6.539 127.314 7.483 ;
     RECT  1.728 7.483 127.314 8.429 ;
     RECT  2.34 8.429 127.314 9.959 ;
     RECT  2.34 9.959 62.766 10.859 ;
     RECT  2.415 10.859 62.766 11.173 ;
     RECT  63.504 9.959 127.314 11.173 ;
     RECT  2.415 11.173 127.314 11.543 ;
     RECT  2.415 11.543 62.91 12.289 ;
     RECT  63.684 11.543 127.314 12.289 ;
     RECT  2.415 12.289 127.314 12.659 ;
     RECT  2.415 12.659 84.798 13.289 ;
     RECT  2.415 13.289 58.626 13.469 ;
     RECT  85.536 12.659 127.314 13.937 ;
     RECT  85.536 13.937 113.022 14.207 ;
     RECT  2.415 13.469 58.194 14.485 ;
     RECT  59.436 13.289 84.798 14.485 ;
     RECT  85.536 14.207 91.314 14.485 ;
     RECT  2.415 14.485 58.554 14.675 ;
     RECT  92.052 14.207 113.022 14.881 ;
     RECT  2.415 14.675 11.646 14.909 ;
     RECT  12.384 14.675 58.554 14.909 ;
     RECT  59.436 14.485 91.314 15.061 ;
     RECT  92.052 14.881 113.058 15.061 ;
     RECT  43.344 14.909 58.554 15.763 ;
     RECT  59.436 15.061 113.058 15.763 ;
     RECT  43.344 15.763 113.058 16.025 ;
     RECT  92.124 16.025 113.058 16.169 ;
     RECT  108.828 16.169 113.058 16.219 ;
     RECT  113.94 13.937 127.314 16.219 ;
     RECT  12.384 14.909 42.534 16.843 ;
     RECT  43.344 16.025 91.35 16.843 ;
     RECT  12.384 16.843 91.35 16.871 ;
     RECT  85.572 16.871 91.35 16.907 ;
     RECT  108.828 16.219 127.314 16.907 ;
     RECT  12.384 16.871 84.798 16.979 ;
     RECT  14.544 16.979 84.798 17.069 ;
     RECT  108.828 16.907 113.058 17.069 ;
     RECT  14.544 17.069 58.194 17.519 ;
     RECT  12.384 16.979 13.77 17.761 ;
     RECT  14.544 17.519 42.606 17.761 ;
     RECT  85.608 16.907 91.35 17.887 ;
     RECT  92.124 16.169 108.09 17.887 ;
     RECT  12.384 17.761 42.606 17.933 ;
     RECT  59.292 17.069 84.798 17.959 ;
     RECT  85.608 17.887 108.09 17.959 ;
     RECT  2.415 14.909 11.43 18.121 ;
     RECT  59.292 17.959 108.09 18.193 ;
     RECT  108.828 17.069 112.986 18.193 ;
     RECT  43.344 17.519 58.194 18.841 ;
     RECT  59.292 18.193 112.986 18.841 ;
     RECT  43.344 18.841 112.986 18.869 ;
     RECT  43.344 18.869 108.09 19.031 ;
     RECT  59.292 19.031 108.09 19.139 ;
     RECT  113.94 16.907 127.314 19.301 ;
     RECT  81.54 19.139 108.09 19.409 ;
     RECT  14.544 17.933 42.606 19.535 ;
     RECT  21.852 19.535 42.606 19.579 ;
     RECT  43.344 19.031 58.23 19.579 ;
     RECT  12.384 17.933 13.77 19.679 ;
     RECT  21.852 19.579 58.23 19.913 ;
     RECT  27.756 19.913 58.23 20.011 ;
     RECT  59.292 19.139 80.694 20.075 ;
     RECT  27.756 20.011 58.518 20.191 ;
     RECT  59.292 20.075 79.002 20.191 ;
     RECT  79.848 20.075 80.694 20.281 ;
     RECT  27.756 20.191 79.002 20.309 ;
     RECT  27.756 20.309 32.886 20.345 ;
     RECT  81.54 19.409 91.314 20.353 ;
     RECT  92.088 19.409 108.09 20.353 ;
     RECT  33.66 20.309 58.446 20.417 ;
     RECT  33.66 20.417 58.194 20.849 ;
     RECT  81.54 20.353 108.09 20.965 ;
     RECT  108.828 18.869 112.986 20.965 ;
     RECT  113.94 19.301 126.897 20.965 ;
     RECT  81.54 20.965 126.897 21.005 ;
     RECT  27.756 20.345 32.85 21.839 ;
     RECT  14.544 19.535 21.114 22.207 ;
     RECT  21.852 19.913 26.946 22.207 ;
     RECT  81.54 21.005 112.986 22.307 ;
     RECT  59.292 20.309 79.002 22.315 ;
     RECT  79.848 20.281 80.802 22.315 ;
     RECT  2.415 18.121 11.466 22.441 ;
     RECT  87.264 22.307 112.986 22.577 ;
     RECT  12.42 19.679 13.77 22.585 ;
     RECT  14.544 22.207 26.946 22.585 ;
     RECT  12.42 22.585 26.946 22.621 ;
     RECT  59.292 22.315 80.802 22.775 ;
     RECT  79.848 22.775 80.802 22.783 ;
     RECT  81.54 22.307 86.526 22.783 ;
     RECT  59.292 22.775 79.038 22.811 ;
     RECT  98.172 22.577 112.986 22.883 ;
     RECT  31.752 21.839 32.85 23.017 ;
     RECT  33.66 20.849 41.706 23.017 ;
     RECT  42.444 20.849 58.194 23.017 ;
     RECT  59.292 22.811 79.002 23.017 ;
     RECT  2.415 22.441 11.61 23.161 ;
     RECT  12.348 22.621 26.946 23.161 ;
     RECT  42.444 23.017 79.002 23.189 ;
     RECT  87.264 22.577 97.326 23.189 ;
     RECT  2.415 23.161 26.946 23.213 ;
     RECT  12.42 23.213 26.946 23.359 ;
     RECT  27.756 21.839 30.978 23.359 ;
     RECT  12.42 23.359 30.978 23.863 ;
     RECT  31.752 23.017 41.706 23.863 ;
     RECT  59.292 23.189 79.002 23.971 ;
     RECT  98.172 22.883 108.09 23.999 ;
     RECT  87.264 23.189 97.146 24.169 ;
     RECT  87.264 24.169 97.398 24.205 ;
     RECT  98.172 23.999 103.266 24.205 ;
     RECT  87.264 24.205 103.266 24.665 ;
     RECT  42.444 23.189 58.194 24.737 ;
     RECT  108.9 22.883 112.986 24.745 ;
     RECT  108.9 24.745 113.13 24.893 ;
     RECT  79.848 22.783 86.526 24.907 ;
     RECT  87.264 24.665 91.314 24.907 ;
     RECT  59.22 23.971 79.002 24.943 ;
     RECT  108.9 24.893 112.986 25.007 ;
     RECT  12.42 23.863 41.706 25.147 ;
     RECT  42.444 24.737 52.542 25.147 ;
     RECT  12.42 25.147 52.542 25.169 ;
     RECT  2.415 23.213 11.466 25.177 ;
     RECT  27.756 25.169 52.542 25.205 ;
     RECT  92.052 24.665 103.266 25.241 ;
     RECT  53.352 24.737 58.194 25.249 ;
     RECT  59.22 24.943 79.074 25.249 ;
     RECT  113.94 21.005 126.897 25.439 ;
     RECT  27.756 25.205 41.706 25.475 ;
     RECT  42.444 25.205 52.542 25.583 ;
     RECT  2.415 25.177 11.646 25.591 ;
     RECT  12.42 25.169 26.946 25.591 ;
     RECT  53.352 25.249 79.074 25.591 ;
     RECT  108.936 25.007 112.986 25.681 ;
     RECT  42.444 25.583 42.606 25.709 ;
     RECT  79.848 24.907 91.314 25.709 ;
     RECT  53.352 25.591 79.11 25.781 ;
     RECT  43.38 25.583 52.542 25.817 ;
     RECT  93.924 25.241 103.266 26.249 ;
     RECT  48.456 25.817 52.542 26.365 ;
     RECT  53.352 25.781 79.038 26.365 ;
     RECT  48.456 26.365 79.038 26.429 ;
     RECT  97.956 26.249 103.266 26.429 ;
     RECT  79.884 25.709 91.314 26.591 ;
     RECT  53.352 26.429 79.038 26.635 ;
     RECT  79.884 26.591 86.526 26.635 ;
     RECT  98.208 26.429 103.266 26.671 ;
     RECT  104.004 23.999 108.09 26.671 ;
     RECT  53.352 26.635 86.526 26.765 ;
     RECT  108.936 25.681 113.13 26.789 ;
     RECT  122.256 25.439 126.897 26.789 ;
     RECT  33.768 25.475 41.706 26.827 ;
     RECT  42.516 25.709 42.606 26.827 ;
     RECT  27.756 25.475 32.994 26.869 ;
     RECT  108.936 26.789 113.022 26.941 ;
     RECT  27.72 26.869 32.994 26.969 ;
     RECT  108.864 26.941 113.022 27.059 ;
     RECT  98.208 26.671 108.09 27.061 ;
     RECT  33.768 26.827 42.606 27.101 ;
     RECT  98.208 27.061 108.378 27.101 ;
     RECT  2.415 25.591 26.946 27.167 ;
     RECT  113.94 25.439 121.497 27.211 ;
     RECT  33.768 27.101 37.926 27.329 ;
     RECT  109.152 27.059 113.022 27.571 ;
     RECT  79.956 26.765 86.526 27.643 ;
     RECT  87.264 26.591 91.314 27.643 ;
     RECT  98.208 27.101 108.09 27.751 ;
     RECT  109.152 27.571 113.166 27.841 ;
     RECT  113.94 27.211 121.554 27.841 ;
     RECT  98.172 27.751 108.09 27.868 ;
     RECT  93.924 26.249 97.146 27.869 ;
     RECT  79.956 27.643 91.314 27.877 ;
     RECT  53.352 26.765 79.038 27.905 ;
     RECT  59.184 27.905 79.038 27.913 ;
     RECT  79.92 27.877 91.314 27.917 ;
     RECT  109.152 27.841 121.554 28.013 ;
     RECT  53.352 27.905 58.302 28.139 ;
     RECT  43.38 25.817 47.538 28.147 ;
     RECT  48.456 26.429 52.542 28.147 ;
     RECT  43.38 28.147 52.542 28.183 ;
     RECT  59.184 27.913 79.182 28.211 ;
     RECT  113.94 28.013 121.554 28.219 ;
     RECT  122.328 26.789 126.897 28.219 ;
     RECT  43.38 28.183 52.578 28.283 ;
     RECT  38.664 27.101 42.606 28.291 ;
     RECT  43.38 28.283 43.398 28.291 ;
     RECT  44.136 28.283 52.578 28.291 ;
     RECT  38.664 28.291 43.398 28.349 ;
     RECT  79.956 27.917 91.314 28.381 ;
     RECT  92.052 25.241 92.97 28.381 ;
     RECT  2.415 27.167 23.166 28.409 ;
     RECT  95.292 27.869 97.146 28.411 ;
     RECT  98.136 27.868 108.09 28.411 ;
     RECT  27.756 26.969 32.994 28.445 ;
     RECT  53.352 28.139 58.194 28.445 ;
     RECT  95.292 28.411 108.09 28.451 ;
     RECT  33.804 27.329 37.926 28.561 ;
     RECT  38.664 28.349 42.606 28.561 ;
     RECT  93.924 27.869 94.554 28.787 ;
     RECT  79.956 28.381 92.97 28.823 ;
     RECT  98.208 28.451 108.09 28.985 ;
     RECT  59.184 28.211 64.854 28.987 ;
     RECT  2.415 28.409 15.966 29.219 ;
     RECT  58.176 28.445 58.194 29.263 ;
     RECT  59.04 28.987 64.854 29.263 ;
     RECT  113.94 28.219 126.897 29.291 ;
     RECT  113.94 29.291 121.554 29.327 ;
     RECT  109.152 28.013 112.986 29.365 ;
     RECT  113.94 29.327 121.497 29.365 ;
     RECT  65.592 28.211 79.182 29.371 ;
     RECT  79.956 28.823 85.014 29.371 ;
     RECT  94.068 28.787 94.554 29.399 ;
     RECT  109.152 29.365 121.497 29.405 ;
     RECT  2.415 29.219 11.538 29.489 ;
     RECT  65.592 29.371 85.014 29.561 ;
     RECT  53.352 28.445 57.33 29.605 ;
     RECT  58.176 29.263 64.854 29.605 ;
     RECT  101.124 28.985 108.09 29.605 ;
     RECT  109.152 29.405 113.094 29.605 ;
     RECT  98.208 28.985 100.314 29.641 ;
     RECT  101.124 29.605 113.094 29.795 ;
     RECT  75.312 29.561 85.014 29.867 ;
     RECT  27.756 28.445 32.85 29.911 ;
     RECT  53.352 29.605 64.854 30.029 ;
     RECT  65.592 29.561 74.394 30.029 ;
     RECT  33.804 28.561 42.606 30.173 ;
     RECT  101.124 29.795 103.266 30.299 ;
     RECT  70.992 30.029 74.394 30.371 ;
     RECT  104.184 29.795 113.094 30.451 ;
     RECT  16.704 28.409 23.166 30.569 ;
     RECT  58.176 30.029 64.854 30.569 ;
     RECT  58.176 30.569 62.766 30.677 ;
     RECT  27.756 29.911 32.958 30.685 ;
     RECT  33.804 30.173 39.006 30.685 ;
     RECT  104.184 30.451 113.166 30.685 ;
     RECT  113.94 29.405 121.497 30.685 ;
     RECT  27.756 30.685 39.006 30.749 ;
     RECT  63.684 30.569 64.854 30.805 ;
     RECT  65.592 30.029 68.202 30.805 ;
     RECT  12.42 29.219 15.966 30.811 ;
     RECT  44.136 28.291 52.614 30.839 ;
     RECT  63.684 30.805 68.202 30.847 ;
     RECT  69.012 30.029 70.074 30.847 ;
     RECT  94.068 29.399 94.497 30.859 ;
     RECT  95.292 28.451 97.146 30.859 ;
     RECT  63.684 30.847 70.074 30.893 ;
     RECT  94.068 30.859 97.146 30.911 ;
     RECT  104.184 30.685 121.497 30.919 ;
     RECT  122.328 29.291 126.897 30.919 ;
     RECT  85.824 28.823 92.97 30.955 ;
     RECT  94.068 30.911 94.497 30.955 ;
     RECT  98.172 29.641 100.314 30.991 ;
     RECT  97.92 30.991 100.314 31.109 ;
     RECT  104.184 30.919 126.897 31.109 ;
     RECT  12.348 30.811 15.966 31.145 ;
     RECT  98.028 31.109 100.314 31.145 ;
     RECT  98.1 31.145 100.314 31.181 ;
     RECT  12.42 31.145 15.966 31.225 ;
     RECT  16.704 30.569 22.05 31.225 ;
     RECT  22.896 30.569 23.166 31.261 ;
     RECT  23.94 27.167 26.946 31.261 ;
     RECT  85.824 30.955 94.497 31.325 ;
     RECT  22.896 31.261 26.946 31.379 ;
     RECT  79.956 29.867 85.014 31.387 ;
     RECT  85.824 31.325 92.97 31.387 ;
     RECT  79.956 31.387 92.97 31.415 ;
     RECT  49.752 30.839 52.614 31.483 ;
     RECT  53.352 30.029 57.33 31.483 ;
     RECT  58.176 30.677 59.994 31.531 ;
     RECT  60.768 30.677 62.766 31.531 ;
     RECT  101.124 30.299 103.194 31.621 ;
     RECT  44.136 30.839 48.942 31.649 ;
     RECT  79.956 31.415 89.622 31.685 ;
     RECT  48.384 31.649 48.942 31.721 ;
     RECT  49.752 31.483 57.33 31.853 ;
     RECT  58.176 31.531 62.766 31.891 ;
     RECT  70.992 30.371 71.514 31.891 ;
     RECT  104.184 31.109 105.534 31.915 ;
     RECT  106.308 31.109 126.897 31.915 ;
     RECT  49.752 31.853 55.494 31.919 ;
     RECT  58.176 31.891 62.838 31.919 ;
     RECT  104.184 31.915 126.897 31.955 ;
     RECT  98.172 31.181 100.314 31.963 ;
     RECT  101.124 31.621 103.338 31.963 ;
     RECT  69.012 30.893 70.074 32.071 ;
     RECT  70.92 31.891 71.514 32.071 ;
     RECT  98.172 31.963 103.338 32.225 ;
     RECT  72.324 30.371 74.394 32.341 ;
     RECT  75.312 29.867 79.11 32.341 ;
     RECT  106.308 31.955 126.897 32.459 ;
     RECT  72.324 32.341 79.11 32.495 ;
     RECT  2.415 29.489 2.697 32.539 ;
     RECT  3.456 29.489 11.538 32.539 ;
     RECT  95.292 30.911 97.146 32.683 ;
     RECT  98.172 32.225 100.314 32.683 ;
     RECT  63.684 30.893 68.202 32.701 ;
     RECT  69.012 32.071 71.514 32.701 ;
     RECT  12.42 31.225 22.05 32.729 ;
     RECT  95.292 32.683 100.314 32.729 ;
     RECT  56.268 31.853 57.33 32.845 ;
     RECT  58.176 31.919 59.994 32.845 ;
     RECT  75.06 32.495 79.11 32.873 ;
     RECT  2.415 32.539 11.538 32.999 ;
     RECT  116.964 32.459 126.897 32.999 ;
     RECT  56.268 32.845 59.994 33.071 ;
     RECT  72.324 32.495 74.214 33.115 ;
     RECT  56.268 33.071 57.294 33.179 ;
     RECT  33.804 30.749 39.006 33.269 ;
     RECT  39.852 30.173 42.606 33.269 ;
     RECT  72.252 33.115 74.214 33.269 ;
     RECT  79.956 31.685 84.798 33.269 ;
     RECT  80.028 33.269 84.798 33.341 ;
     RECT  118.26 32.999 126.897 33.449 ;
     RECT  53.352 31.919 55.494 33.547 ;
     RECT  56.268 33.179 57.114 33.547 ;
     RECT  85.824 31.685 89.622 33.619 ;
     RECT  95.292 32.729 97.146 33.647 ;
     RECT  53.352 33.547 57.114 33.917 ;
     RECT  53.352 33.917 55.494 33.953 ;
     RECT  98.172 32.729 100.314 33.961 ;
     RECT  106.308 32.459 116.154 33.989 ;
     RECT  106.308 33.989 113.058 34.349 ;
     RECT  60.912 31.919 62.838 34.619 ;
     RECT  3.456 32.999 11.538 34.691 ;
     RECT  60.912 34.619 62.766 34.735 ;
     RECT  60.84 34.735 62.766 34.763 ;
     RECT  10.44 34.691 11.538 35.231 ;
     RECT  44.136 31.649 47.574 35.429 ;
     RECT  53.352 33.953 55.314 35.429 ;
     RECT  75.132 32.873 79.11 35.581 ;
     RECT  80.064 33.341 84.798 35.581 ;
     RECT  101.124 32.225 103.338 35.699 ;
     RECT  12.42 32.729 15.93 35.707 ;
     RECT  16.704 32.729 22.05 35.707 ;
     RECT  12.42 35.707 22.05 35.744 ;
     RECT  16.704 35.744 22.05 35.807 ;
     RECT  85.536 33.619 89.622 36.121 ;
     RECT  90.468 31.415 92.97 36.121 ;
     RECT  104.184 31.955 105.534 36.239 ;
     RECT  94.068 31.325 94.497 36.581 ;
     RECT  75.132 35.581 84.798 36.779 ;
     RECT  95.328 33.647 97.146 37.021 ;
     RECT  56.268 33.917 57.114 37.633 ;
     RECT  58.176 33.071 59.994 37.633 ;
     RECT  48.456 31.721 48.942 38.011 ;
     RECT  56.268 37.633 59.994 38.129 ;
     RECT  3.456 34.691 9.702 38.137 ;
     RECT  10.476 35.231 11.538 38.137 ;
     RECT  42.516 33.269 42.606 38.641 ;
     RECT  43.38 28.349 43.398 38.641 ;
     RECT  49.752 31.919 52.614 38.641 ;
     RECT  106.308 34.349 108.342 38.669 ;
     RECT  42.516 38.641 43.398 38.741 ;
     RECT  49.68 38.641 52.614 39.209 ;
     RECT  106.308 38.669 108.27 40.171 ;
     RECT  109.116 34.349 113.058 40.171 ;
     RECT  106.308 40.171 113.058 40.289 ;
     RECT  63.684 32.701 71.514 40.559 ;
     RECT  3.456 38.137 11.538 40.801 ;
     RECT  56.268 38.129 57.402 40.981 ;
     RECT  116.964 32.999 117.414 40.981 ;
     RECT  118.26 33.449 121.497 40.981 ;
     RECT  122.328 33.449 126.897 40.981 ;
     RECT  116.964 40.981 126.897 41.369 ;
     RECT  60.84 34.763 60.858 42.061 ;
     RECT  61.596 34.763 62.766 42.061 ;
     RECT  48.42 38.011 48.942 42.961 ;
     RECT  49.68 39.209 52.542 42.961 ;
     RECT  116.964 41.369 120.006 44.221 ;
     RECT  120.78 41.369 126.897 44.221 ;
     RECT  12.42 35.744 15.93 44.339 ;
     RECT  85.536 36.121 92.97 44.339 ;
     RECT  92.592 44.339 92.97 44.419 ;
     RECT  27.756 30.749 32.85 44.761 ;
     RECT  85.536 44.339 89.514 45.031 ;
     RECT  116.964 44.221 126.897 45.149 ;
     RECT  27.684 44.761 32.85 45.599 ;
     RECT  44.136 35.429 47.43 45.689 ;
     RECT  48.42 42.961 52.542 45.689 ;
     RECT  75.132 36.779 84.726 46.499 ;
     RECT  69.084 40.559 71.514 46.769 ;
     RECT  42.588 38.741 43.398 46.921 ;
     RECT  44.136 45.689 44.874 46.921 ;
     RECT  2.415 32.999 2.697 47.461 ;
     RECT  3.456 40.801 11.61 47.461 ;
     RECT  29.415 45.599 32.85 48.811 ;
     RECT  33.804 33.269 37.854 48.811 ;
     RECT  23.724 31.379 26.946 48.929 ;
     RECT  16.704 35.807 17.19 49.351 ;
     RECT  18 35.807 22.05 49.351 ;
     RECT  29.415 48.811 37.854 49.469 ;
     RECT  27.684 45.599 28.638 49.585 ;
     RECT  29.415 49.469 32.742 49.585 ;
     RECT  16.704 49.351 22.05 49.739 ;
     RECT  63.684 40.559 68.31 49.891 ;
     RECT  27.684 49.585 32.742 50.009 ;
     RECT  23.724 48.929 26.874 50.279 ;
     RECT  75.132 46.499 80.73 50.701 ;
     RECT  16.704 49.739 19.206 50.819 ;
     RECT  16.704 50.819 17.118 51.161 ;
     RECT  33.516 49.469 37.854 51.359 ;
     RECT  54.468 35.429 55.314 51.511 ;
     RECT  95.22 37.021 97.146 53.941 ;
     RECT  98.1 33.961 100.314 53.941 ;
     RECT  38.592 33.269 39.006 55.831 ;
     RECT  22.896 31.379 22.95 56.371 ;
     RECT  69.084 46.769 71.442 56.371 ;
     RECT  72.324 33.269 74.214 56.371 ;
     RECT  101.124 35.699 103.23 56.641 ;
     RECT  12.42 44.339 15.858 57.029 ;
     RECT  113.94 33.989 116.154 57.181 ;
     RECT  45.615 45.689 47.43 57.577 ;
     RECT  45.615 57.577 47.61 58.109 ;
     RECT  42.588 46.921 44.874 58.729 ;
     RECT  45.615 58.109 47.502 58.729 ;
     RECT  29.415 50.009 32.742 58.919 ;
     RECT  104.184 36.239 105.462 59.071 ;
     RECT  42.588 58.729 47.502 59.189 ;
     RECT  38.592 55.831 39.078 60.151 ;
     RECT  39.852 33.269 41.778 60.151 ;
     RECT  19.98 49.739 22.05 60.961 ;
     RECT  22.824 56.371 22.95 60.961 ;
     RECT  85.464 45.031 89.514 61.321 ;
     RECT  90.324 44.339 91.854 61.321 ;
     RECT  53.352 35.429 53.586 61.771 ;
     RECT  54.396 51.511 55.314 61.771 ;
     RECT  94.104 36.581 94.497 61.961 ;
     RECT  94.14 61.961 94.497 62.041 ;
     RECT  95.22 53.941 100.314 62.041 ;
     RECT  38.592 60.151 41.778 62.311 ;
     RECT  42.588 59.189 44.874 62.311 ;
     RECT  106.308 40.289 112.914 62.311 ;
     RECT  33.516 51.359 36.558 62.581 ;
     RECT  37.296 51.359 37.854 62.581 ;
     RECT  69.084 56.371 74.214 63.509 ;
     RECT  17.892 50.819 19.206 63.661 ;
     RECT  19.98 60.961 22.95 63.661 ;
     RECT  74.988 50.701 80.73 63.779 ;
     RECT  113.796 57.181 116.154 64.049 ;
     RECT  56.196 40.981 57.402 64.201 ;
     RECT  58.176 38.129 59.994 64.201 ;
     RECT  94.14 62.041 100.314 64.589 ;
     RECT  94.14 64.589 100.206 65.515 ;
     RECT  74.988 63.779 75.87 66.091 ;
     RECT  76.644 63.779 80.73 66.091 ;
     RECT  116.964 45.149 119.97 67.441 ;
     RECT  12.42 57.029 14.202 70.141 ;
     RECT  129.42 88.747 129.438 88.877 ;
     RECT  128.808 94.027 128.826 94.253 ;
     RECT  50.472 45.689 52.542 116.107 ;
     RECT  53.352 61.771 55.314 116.107 ;
     RECT  50.472 116.107 55.314 116.429 ;
     RECT  48.42 45.689 49.734 118.201 ;
     RECT  50.472 116.429 52.542 118.201 ;
     RECT  48.42 118.201 52.542 118.541 ;
     RECT  63.576 49.891 68.31 123.151 ;
     RECT  69.084 63.509 74.142 123.151 ;
     RECT  63.576 123.151 74.142 123.197 ;
     RECT  128.808 126.667 128.826 127.409 ;
     RECT  120.708 45.149 126.897 129.235 ;
     RECT  113.796 64.049 116.097 131.557 ;
     RECT  120.708 129.235 126.99 136.525 ;
     RECT  120.708 136.525 127.386 139.997 ;
     RECT  2.415 47.461 11.61 147.209 ;
     RECT  116.856 67.441 119.97 147.595 ;
     RECT  120.708 139.997 126.99 147.595 ;
     RECT  116.856 147.595 126.99 151.033 ;
     RECT  116.856 151.033 127.134 153.341 ;
     RECT  8.892 147.209 11.61 153.805 ;
     RECT  12.348 70.141 14.202 153.805 ;
     RECT  29.415 58.919 31.374 154.499 ;
     RECT  116.856 153.341 126.99 154.769 ;
     RECT  116.856 154.769 119.826 155.849 ;
     RECT  94.104 65.515 100.206 156.127 ;
     RECT  116.892 155.849 119.826 156.163 ;
     RECT  38.592 62.311 44.874 156.389 ;
     RECT  44.856 156.389 44.874 156.505 ;
     RECT  45.615 59.189 47.502 156.505 ;
     RECT  25.884 50.279 26.874 156.703 ;
     RECT  27.684 50.009 28.674 156.703 ;
     RECT  106.236 62.311 112.914 157.199 ;
     RECT  8.892 153.805 14.202 157.279 ;
     RECT  14.976 57.029 15.858 157.279 ;
     RECT  48.42 118.541 49.734 157.279 ;
     RECT  74.988 66.091 80.73 157.279 ;
     RECT  81.468 46.499 84.726 157.279 ;
     RECT  25.884 156.703 28.674 157.585 ;
     RECT  29.415 154.499 30.438 157.585 ;
     RECT  104.076 59.071 105.462 157.585 ;
     RECT  106.236 157.199 111.186 157.585 ;
     RECT  23.724 50.279 25.146 157.855 ;
     RECT  25.884 157.585 30.438 157.855 ;
     RECT  38.592 156.389 44.118 158.665 ;
     RECT  44.856 156.505 47.502 158.665 ;
     RECT  53.352 116.429 55.314 158.935 ;
     RECT  56.196 64.201 59.994 158.935 ;
     RECT  69.084 123.197 74.142 158.935 ;
     RECT  101.052 56.641 103.23 158.935 ;
     RECT  85.464 61.321 91.854 159.089 ;
     RECT  17.892 63.661 22.95 159.205 ;
     RECT  23.724 157.855 30.438 159.205 ;
     RECT  92.592 44.419 93.006 159.205 ;
     RECT  2.415 147.209 8.154 159.359 ;
     RECT  53.352 158.935 59.994 159.899 ;
     RECT  60.84 42.061 62.766 159.899 ;
     RECT  63.576 123.197 68.31 160.169 ;
     RECT  8.892 157.279 15.858 160.709 ;
     RECT  85.464 159.089 91.422 160.709 ;
     RECT  104.076 157.585 111.186 160.709 ;
     RECT  74.988 157.279 84.726 160.717 ;
     RECT  100.944 158.935 103.23 161.095 ;
     RECT  104.076 160.709 107.514 161.095 ;
     RECT  69.084 158.935 74.214 161.519 ;
     RECT  108.252 160.709 111.186 161.635 ;
     RECT  111.924 157.199 112.914 161.635 ;
     RECT  48.24 157.279 49.734 161.833 ;
     RECT  50.472 118.541 52.542 161.833 ;
     RECT  100.944 161.095 107.514 161.833 ;
     RECT  108.252 161.635 112.914 161.833 ;
     RECT  53.352 159.899 57.438 162.059 ;
     RECT  92.16 159.205 93.006 162.599 ;
     RECT  16.812 51.161 17.118 163.525 ;
     RECT  32.148 58.919 32.742 164.065 ;
     RECT  100.944 161.833 112.914 164.065 ;
     RECT  72.108 161.519 74.214 164.335 ;
     RECT  74.988 160.717 85.302 164.335 ;
     RECT  72.108 164.335 85.302 165.029 ;
     RECT  31.176 154.499 31.374 165.145 ;
     RECT  32.148 164.065 32.778 165.145 ;
     RECT  55.584 162.059 57.438 165.145 ;
     RECT  58.176 159.899 59.994 165.145 ;
     RECT  33.516 62.581 37.854 165.299 ;
     RECT  86.04 160.709 91.422 165.307 ;
     RECT  92.16 162.599 92.898 165.307 ;
     RECT  48.24 161.833 52.542 165.685 ;
     RECT  53.352 162.059 54.81 165.685 ;
     RECT  86.04 165.307 92.898 165.839 ;
     RECT  3.528 159.359 8.154 166.963 ;
     RECT  8.892 160.709 10.242 166.963 ;
     RECT  10.98 160.709 15.858 167.459 ;
     RECT  16.668 163.525 17.118 167.729 ;
     RECT  61.524 159.899 62.766 168.269 ;
     RECT  116.892 156.163 119.862 168.539 ;
     RECT  3.528 166.963 10.242 168.655 ;
     RECT  10.98 167.459 14.022 168.655 ;
     RECT  33.516 165.299 37.782 168.655 ;
     RECT  38.592 158.665 47.502 168.655 ;
     RECT  55.584 165.145 59.994 168.809 ;
     RECT  17.892 159.205 30.438 169.079 ;
     RECT  63.576 160.169 67.554 169.195 ;
     RECT  76.536 165.029 85.302 169.195 ;
     RECT  86.04 165.839 91.386 169.195 ;
     RECT  14.868 167.459 15.858 170.699 ;
     RECT  76.536 169.195 91.386 171.239 ;
     RECT  68.292 160.169 68.31 171.355 ;
     RECT  69.084 161.519 71.262 171.355 ;
     RECT  17.892 169.079 30.33 171.509 ;
     RECT  60.768 160.015 60.786 171.553 ;
     RECT  61.524 168.269 62.73 171.553 ;
     RECT  93.996 156.127 100.206 171.779 ;
     RECT  33.516 168.655 47.502 171.895 ;
     RECT  48.24 165.685 54.81 171.895 ;
     RECT  63.468 169.195 67.554 171.895 ;
     RECT  68.292 171.355 71.262 171.895 ;
     RECT  63.468 171.895 71.262 172.049 ;
     RECT  17.892 171.509 24.498 172.093 ;
     RECT  25.236 171.509 30.33 172.589 ;
     RECT  63.468 172.049 64.746 172.975 ;
     RECT  65.484 172.049 71.262 172.975 ;
     RECT  3.528 168.655 14.022 173.939 ;
     RECT  55.584 168.809 59.958 173.939 ;
     RECT  31.176 165.145 32.778 174.055 ;
     RECT  33.516 171.895 54.81 174.055 ;
     RECT  63.468 172.975 71.262 174.055 ;
     RECT  72.108 165.029 75.798 174.055 ;
     RECT  25.236 172.589 27.738 174.325 ;
     RECT  28.548 172.589 30.33 174.325 ;
     RECT  93.996 171.779 100.098 174.325 ;
     RECT  100.944 164.065 112.95 174.325 ;
     RECT  76.536 171.239 89.55 174.865 ;
     RECT  90.36 171.239 91.386 174.865 ;
     RECT  93.996 174.325 112.95 175.829 ;
     RECT  2.415 159.359 2.697 178.141 ;
     RECT  120.672 154.769 126.99 178.799 ;
     RECT  2.415 178.141 2.754 178.915 ;
     RECT  3.528 173.939 13.986 178.915 ;
     RECT  57.42 173.939 59.958 178.915 ;
     RECT  60.768 171.553 62.73 178.915 ;
     RECT  92.16 165.839 92.898 178.915 ;
     RECT  93.996 175.829 103.086 178.915 ;
     RECT  63.468 174.055 75.798 178.951 ;
     RECT  76.536 174.865 91.386 178.951 ;
     RECT  17.784 172.093 24.498 179.069 ;
     RECT  31.176 174.055 54.81 179.069 ;
     RECT  57.42 178.915 62.73 179.069 ;
     RECT  63.468 178.951 91.386 179.069 ;
     RECT  92.16 178.915 103.086 179.069 ;
     RECT  103.932 175.829 112.95 179.069 ;
     RECT  113.688 131.557 116.097 179.069 ;
     RECT  116.892 168.539 117.558 179.113 ;
     RECT  2.415 178.915 13.986 179.185 ;
     RECT  14.868 170.699 15.75 179.185 ;
     RECT  16.668 167.729 16.974 179.185 ;
     RECT  17.784 179.069 21.69 179.185 ;
     RECT  101.772 179.069 103.086 179.185 ;
     RECT  103.932 179.069 104.166 179.185 ;
     RECT  113.796 179.069 116.097 179.185 ;
     RECT  116.892 179.113 117.594 179.185 ;
     RECT  22.428 179.069 24.498 179.221 ;
     RECT  25.236 174.325 30.33 179.221 ;
     RECT  50.724 179.069 54.81 179.221 ;
     RECT  55.584 173.939 56.697 179.221 ;
     RECT  61.308 179.069 62.73 179.221 ;
     RECT  63.468 179.069 63.918 179.221 ;
     RECT  104.94 179.069 112.95 179.221 ;
     RECT  113.796 179.185 117.63 179.221 ;
     RECT  118.44 168.539 119.862 179.221 ;
     RECT  16.668 179.185 21.69 179.339 ;
     RECT  22.428 179.221 30.402 179.339 ;
     RECT  31.176 179.069 48.258 179.339 ;
     RECT  50.724 179.221 56.697 179.339 ;
     RECT  101.772 179.185 104.166 179.339 ;
     RECT  113.796 179.221 119.934 179.339 ;
     RECT  2.415 179.185 15.75 179.347 ;
     RECT  16.668 179.339 19.782 179.347 ;
     RECT  52.092 179.339 56.697 179.455 ;
     RECT  87.624 179.069 91.386 179.455 ;
     RECT  92.16 179.069 100.962 179.455 ;
     RECT  31.176 179.339 48.186 179.609 ;
     RECT  31.176 179.609 44.226 179.617 ;
     RECT  2.415 179.347 19.782 179.725 ;
     RECT  31.14 179.617 44.226 179.725 ;
     RECT  87.624 179.455 100.962 179.845 ;
     RECT  101.772 179.339 104.022 179.845 ;
     RECT  61.308 179.221 63.918 179.851 ;
     RECT  64.728 179.069 75.798 179.851 ;
     RECT  23.976 179.339 26.586 179.879 ;
     RECT  50.724 179.339 51.297 179.887 ;
     RECT  52.092 179.455 56.754 179.887 ;
     RECT  57.492 179.069 60.462 179.887 ;
     RECT  85.608 179.069 86.706 179.923 ;
     RECT  85.5 179.923 86.706 179.989 ;
     RECT  87.624 179.845 104.022 179.989 ;
     RECT  61.308 179.851 75.798 179.995 ;
     RECT  49.032 179.069 49.626 180.031 ;
     RECT  52.092 179.887 60.462 180.031 ;
     RECT  61.308 179.995 76.302 180.031 ;
     RECT  77.148 179.069 84.726 180.031 ;
     RECT  85.5 179.989 104.022 180.031 ;
     RECT  113.796 179.339 118.098 180.091 ;
     RECT  118.944 179.339 119.934 180.091 ;
     RECT  120.672 178.799 126.954 180.091 ;
     RECT  2.34 179.725 19.782 180.121 ;
     RECT  20.52 179.339 21.654 180.121 ;
     RECT  22.428 179.339 23.238 180.121 ;
     RECT  2.34 180.121 23.238 180.139 ;
     RECT  23.976 179.879 26.514 180.139 ;
     RECT  27.36 179.339 30.33 180.139 ;
     RECT  31.104 179.725 44.226 180.139 ;
     RECT  48.924 180.031 49.626 180.139 ;
     RECT  50.364 179.887 51.297 180.139 ;
     RECT  77.148 180.031 104.022 180.139 ;
     RECT  104.94 179.221 113.022 180.139 ;
     RECT  2.34 180.139 26.514 180.265 ;
     RECT  44.964 179.609 48.186 180.301 ;
     RECT  48.924 180.139 51.297 180.301 ;
     RECT  52.092 180.031 76.302 180.301 ;
     RECT  77.148 180.139 113.022 180.301 ;
     RECT  113.796 180.091 126.954 180.301 ;
     RECT  44.964 180.301 51.297 180.535 ;
     RECT  52.092 180.301 127.206 180.535 ;
     RECT  44.964 180.535 127.206 180.571 ;
     RECT  1.692 180.265 26.514 180.697 ;
     RECT  27.36 180.139 44.226 180.697 ;
     RECT  1.692 180.697 44.226 180.749 ;
     RECT  2.304 180.749 44.226 180.805 ;
     RECT  44.964 180.571 127.242 180.805 ;
     RECT  2.304 180.805 127.242 181.111 ;
     RECT  1.116 181.111 1.134 181.181 ;
     RECT  2.304 181.111 127.314 181.265 ;
     RECT  2.376 181.265 127.314 181.277 ;
     RECT  2.376 181.277 6.354 181.853 ;
     RECT  7.2 181.277 33.102 181.853 ;
     RECT  34.056 181.277 38.826 181.853 ;
     RECT  39.78 181.277 63.918 181.853 ;
     RECT  64.656 181.277 73.602 181.853 ;
     RECT  74.484 181.277 96.318 181.853 ;
     RECT  97.344 181.277 102.15 181.853 ;
     RECT  102.996 181.277 123.39 181.853 ;
     RECT  124.128 181.277 127.314 181.853 ;
     RECT  34.776 181.853 34.794 182.189 ;
     RECT  110.376 181.853 110.394 182.189 ;
     RECT  4.572 181.853 5.022 182.381 ;
     RECT  15.048 181.853 16.47 182.381 ;
     RECT  17.208 181.853 17.766 182.381 ;
     RECT  20.88 181.853 20.898 182.381 ;
     RECT  22.5 181.853 22.518 182.381 ;
     RECT  27.468 181.853 29.574 182.381 ;
     RECT  33.084 181.853 33.102 182.381 ;
     RECT  36.216 181.853 36.234 182.381 ;
     RECT  38.808 181.853 38.826 182.381 ;
     RECT  43.236 181.853 43.578 182.381 ;
     RECT  47.232 181.853 47.574 182.381 ;
     RECT  49.392 181.853 49.41 182.381 ;
     RECT  52.848 181.853 52.866 182.381 ;
     RECT  53.964 181.853 54.702 182.381 ;
     RECT  61.272 181.853 61.29 182.381 ;
     RECT  68.184 181.853 68.202 182.381 ;
     RECT  71.856 181.853 71.874 182.381 ;
     RECT  72.756 181.853 72.774 182.381 ;
     RECT  73.584 181.853 73.602 182.381 ;
     RECT  75.312 181.853 75.33 182.381 ;
     RECT  78.768 181.853 81.486 182.381 ;
     RECT  85.788 181.853 85.806 182.381 ;
     RECT  87.948 181.853 87.966 182.381 ;
     RECT  89.676 181.853 89.694 182.381 ;
     RECT  100.368 181.853 100.386 182.381 ;
     RECT  104.292 181.853 106.11 182.381 ;
     RECT  106.848 181.853 106.866 182.381 ;
     RECT  117 181.853 117.018 182.381 ;
     RECT  117.756 181.853 117.774 182.381 ;
     RECT  120.564 181.853 120.582 182.381 ;
     RECT  121.428 181.853 121.446 182.381 ;
     RECT  124.992 181.853 126.198 182.381 ;
     RECT  10.224 181.853 10.242 182.429 ;
     RECT  11.952 181.853 12.474 182.429 ;
     RECT  14.112 181.853 14.13 182.429 ;
     RECT  15.912 182.381 15.93 182.429 ;
     RECT  29.556 182.381 29.574 182.429 ;
     RECT  50.616 181.853 50.634 182.429 ;
     RECT  53.964 182.381 53.982 182.429 ;
     RECT  77.508 181.853 77.526 182.429 ;
     RECT  79.2 182.381 79.218 182.429 ;
     RECT  81.468 182.381 81.486 182.429 ;
     RECT  92.808 181.853 92.826 182.429 ;
     RECT  96.3 181.853 96.318 182.429 ;
     RECT  98.46 181.853 98.478 182.429 ;
     RECT  104.292 182.381 104.31 182.429 ;
     RECT  108.288 181.853 108.306 182.429 ;
     RECT  113.904 181.853 113.922 182.429 ;
     RECT  115.632 181.853 115.65 182.429 ;
     RECT  119.592 181.853 119.61 182.429 ;
     RECT  127.08 181.853 127.314 182.429 ;
     RECT  125.208 182.381 125.226 182.669 ;
     RECT  94.536 181.853 94.554 182.957 ;
     RECT  127.116 182.429 127.314 183.005 ;
     RECT  128.268 180.805 128.286 183.005 ;
     RECT  127.296 183.005 127.314 183.053 ;
    LAYER M4 ;
     RECT  0.181 180.576 0.613 180.6 ;
     RECT  0.229 19.632 0.661 19.656 ;
     RECT  0.613 7.44 1.045 7.464 ;
     RECT  0.613 180.576 1.093 180.744 ;
     RECT  1.061 2.304 1.145 2.328 ;
     RECT  1.093 180.576 1.525 181.176 ;
     RECT  1.525 0.576 1.925 0.6 ;
     RECT  1.925 0.576 2.009 1.176 ;
     RECT  2.009 0.576 2.293 0.6 ;
     RECT  1.525 180.576 2.348 181.272 ;
     RECT  2.293 2.88 2.408 2.904 ;
     RECT  1.477 4.128 2.408 4.152 ;
     RECT  1.889 6.288 2.408 6.312 ;
     RECT  1.045 7.44 2.408 7.512 ;
     RECT  0.181 10.896 2.408 10.92 ;
     RECT  0.661 19.632 2.408 20.184 ;
     RECT  2.348 180.576 2.408 181.848 ;
     RECT  2.293 0.144 2.435 0.6 ;
     RECT  2.408 2.148 2.512 181.848 ;
     RECT  2.435 0.24 2.585 0.6 ;
     RECT  2.512 2.418 2.704 181.848 ;
     RECT  2.704 7.44 2.765 7.464 ;
     RECT  2.704 2.736 2.981 4.152 ;
     RECT  2.704 10.896 3.233 10.92 ;
     RECT  2.704 32.544 3.443 32.568 ;
     RECT  2.981 2.736 3.485 4.008 ;
     RECT  2.704 22.32 3.587 22.776 ;
     RECT  3.587 22.32 3.701 22.344 ;
     RECT  2.704 25.152 3.923 25.176 ;
     RECT  3.637 1.728 4.133 1.752 ;
     RECT  2.704 179.52 4.169 179.544 ;
     RECT  2.704 181.248 4.277 181.848 ;
     RECT  3.485 2.88 4.345 4.008 ;
     RECT  2.704 5.136 4.345 5.16 ;
     RECT  4.268 30.192 4.355 30.216 ;
     RECT  4.345 2.88 4.453 5.16 ;
     RECT  2.585 0.576 4.457 0.6 ;
     RECT  4.357 27.312 4.547 27.336 ;
     RECT  3.925 24.72 4.745 24.744 ;
     RECT  2.704 19.632 4.796 20.184 ;
     RECT  4.597 0.096 4.817 0.12 ;
     RECT  4.796 19.632 4.883 20.76 ;
     RECT  4.633 179.808 4.931 179.832 ;
     RECT  4.844 180.96 4.931 180.984 ;
     RECT  4.883 19.632 5.02 20.424 ;
     RECT  4.561 182.352 5.077 182.376 ;
     RECT  4.453 2.832 5.123 5.16 ;
     RECT  5.123 4.56 5.249 5.16 ;
     RECT  5.413 24.672 5.5 24.696 ;
     RECT  5.365 1.152 5.501 1.176 ;
     RECT  5.123 2.832 5.573 3 ;
     RECT  5.209 34.272 5.699 34.296 ;
     RECT  5.317 180.144 5.699 180.6 ;
     RECT  5.573 2.832 5.749 2.952 ;
     RECT  5.797 0.576 5.893 0.6 ;
     RECT  5.749 2.784 5.939 2.952 ;
     RECT  5.996 26.736 6.083 26.76 ;
     RECT  5.939 2.784 6.149 2.904 ;
     RECT  5.893 0.096 6.185 0.6 ;
     RECT  6.217 17.952 6.245 17.976 ;
     RECT  5.249 4.56 6.293 4.584 ;
     RECT  6.245 17.952 6.329 18.216 ;
     RECT  5.989 21.696 6.467 21.72 ;
     RECT  6.329 17.952 6.509 18.024 ;
     RECT  6.389 22.8 6.577 22.824 ;
     RECT  5.699 180.576 6.581 180.6 ;
     RECT  6.577 22.704 6.661 22.824 ;
     RECT  6.185 0.096 6.761 0.12 ;
     RECT  6.661 3.984 6.761 4.008 ;
     RECT  6.661 22.8 6.761 22.824 ;
     RECT  5.353 181.824 6.785 181.848 ;
     RECT  6.509 18 6.803 18.024 ;
     RECT  6.805 2.304 7.237 2.376 ;
     RECT  7.141 30 7.369 30.024 ;
     RECT  7.525 0.576 7.661 0.6 ;
     RECT  7.237 2.304 7.808 2.904 ;
     RECT  5.02 19.632 7.808 20.184 ;
     RECT  7.369 30 7.808 30.072 ;
     RECT  7.436 32.688 7.808 32.712 ;
     RECT  7.765 180.144 7.808 180.168 ;
     RECT  6.785 181.248 7.808 181.848 ;
     RECT  7.669 1.152 7.985 1.176 ;
     RECT  7.957 0.144 8.101 0.168 ;
     RECT  7.808 2.148 8.104 181.848 ;
     RECT  8.101 0.096 8.165 0.168 ;
     RECT  8.104 31.872 8.243 31.896 ;
     RECT  8.104 36 8.243 36.024 ;
     RECT  8.104 17.568 8.533 17.64 ;
     RECT  8.104 28.896 8.572 28.92 ;
     RECT  8.104 30.048 8.633 30.216 ;
     RECT  8.104 26.64 8.723 26.664 ;
     RECT  8.104 19.632 8.813 21.576 ;
     RECT  8.104 2.148 8.821 3.432 ;
     RECT  8.104 23.28 8.86 23.304 ;
     RECT  8.821 1.728 9.029 3.432 ;
     RECT  8.533 17.616 9.101 17.64 ;
     RECT  8.813 19.632 9.107 20.952 ;
     RECT  8.165 0.096 9.205 0.12 ;
     RECT  9.164 5.712 9.251 5.736 ;
     RECT  8.104 180.144 9.281 180.168 ;
     RECT  9.205 0.096 9.445 0.552 ;
     RECT  9.029 2.688 9.587 3.432 ;
     RECT  9.521 23.376 9.605 23.4 ;
     RECT  9.445 0.096 9.677 1.176 ;
     RECT  8.633 30.048 9.733 30.072 ;
     RECT  9.677 0.096 9.785 0.6 ;
     RECT  9.733 30.048 9.821 30.36 ;
     RECT  9.785 0.576 10.109 0.6 ;
     RECT  9.587 3.408 10.117 3.432 ;
     RECT  8.104 4.416 10.117 4.44 ;
     RECT  8.104 181.824 10.213 181.848 ;
     RECT  10.117 3.408 10.249 4.44 ;
     RECT  10.213 181.824 10.355 182.424 ;
     RECT  9.107 19.632 10.357 20.184 ;
     RECT  10.249 3.408 10.549 4.536 ;
     RECT  10.357 19.632 10.597 20.664 ;
     RECT  10.309 2.304 10.741 2.328 ;
     RECT  10.549 3.408 10.741 4.584 ;
     RECT  10.741 17.616 10.828 17.64 ;
     RECT  10.597 19.632 10.835 20.952 ;
     RECT  10.741 2.304 10.865 4.584 ;
     RECT  9.821 30.048 10.883 30.072 ;
     RECT  10.837 17.952 10.924 17.976 ;
     RECT  10.865 2.832 11.009 4.584 ;
     RECT  11.009 2.88 11.081 4.584 ;
     RECT  11.149 34.416 11.411 34.44 ;
     RECT  11.081 3.408 11.477 4.584 ;
     RECT  11.413 22.464 11.621 22.488 ;
     RECT  11.564 25.584 11.651 25.608 ;
     RECT  10.355 181.824 11.692 181.848 ;
     RECT  11.221 180 11.729 180.024 ;
     RECT  11.66 28.272 11.747 28.296 ;
     RECT  12.037 23.184 12.179 23.208 ;
     RECT  10.933 0.096 12.269 0.12 ;
     RECT  10.835 19.632 12.437 20.184 ;
     RECT  11.173 1.152 12.517 1.176 ;
     RECT  11.941 182.4 12.563 182.424 ;
     RECT  11.477 3.408 12.625 4.008 ;
     RECT  12.517 0.528 13.061 1.176 ;
     RECT  12.877 179.568 13.093 179.592 ;
     RECT  12.625 3.408 13.208 4.248 ;
     RECT  12.437 18.816 13.208 20.184 ;
     RECT  11.989 30.816 13.208 30.84 ;
     RECT  13.093 34.464 13.208 34.488 ;
     RECT  13.093 179.568 13.208 180.552 ;
     RECT  12.908 181.824 13.208 181.848 ;
     RECT  13.208 2.148 13.312 181.848 ;
     RECT  13.061 0.528 13.381 0.6 ;
     RECT  13.312 2.418 13.504 181.848 ;
     RECT  13.504 2.88 13.619 4.248 ;
     RECT  13.504 179.664 13.667 180.552 ;
     RECT  13.504 34.08 13.673 34.488 ;
     RECT  13.619 4.224 13.817 4.248 ;
     RECT  13.504 28.32 13.817 28.344 ;
     RECT  13.504 181.824 14.101 181.848 ;
     RECT  13.673 34.08 14.243 34.104 ;
     RECT  13.504 17.904 14.257 17.928 ;
     RECT  13.504 23.952 14.291 23.976 ;
     RECT  14.101 181.824 14.291 182.424 ;
     RECT  13.381 0.096 14.677 0.6 ;
     RECT  14.291 181.824 14.723 182.376 ;
     RECT  14.677 0.096 14.789 1.176 ;
     RECT  13.619 2.88 14.828 2.904 ;
     RECT  14.828 2.88 14.915 3.864 ;
     RECT  13.504 25.2 15.289 25.224 ;
     RECT  15.289 25.2 15.293 25.56 ;
     RECT  15.245 3.984 15.329 4.008 ;
     RECT  15.253 18 15.34 18.024 ;
     RECT  15.293 25.536 15.395 25.56 ;
     RECT  15.788 32.448 15.875 32.472 ;
     RECT  14.723 182.352 15.901 182.376 ;
     RECT  15.901 182.352 16.067 182.424 ;
     RECT  13.667 179.664 16.117 179.688 ;
     RECT  15.361 4.896 16.157 4.92 ;
     RECT  16.117 179.664 16.157 180.024 ;
     RECT  13.504 19.632 16.261 20.184 ;
     RECT  14.789 0.096 16.265 0.6 ;
     RECT  16.265 0.192 16.301 0.6 ;
     RECT  15.973 35.712 16.301 35.736 ;
     RECT  16.261 19.344 16.355 20.184 ;
     RECT  16.301 0.576 16.433 0.6 ;
     RECT  16.433 0.576 16.517 1.176 ;
     RECT  16.477 32.544 16.561 32.568 ;
     RECT  16.517 0.576 16.769 0.6 ;
     RECT  14.915 2.88 16.885 2.904 ;
     RECT  16.067 182.352 16.885 182.376 ;
     RECT  16.885 181.824 16.972 182.376 ;
     RECT  16.885 2.88 16.981 2.952 ;
     RECT  16.157 180 17.021 180.024 ;
     RECT  16.988 22.32 17.075 22.344 ;
     RECT  17.036 32.688 17.123 32.712 ;
     RECT  16.981 2.88 17.201 3.432 ;
     RECT  17.077 23.856 17.345 23.88 ;
     RECT  17.413 4.704 17.468 4.728 ;
     RECT  17.317 0.096 17.525 0.12 ;
     RECT  17.468 4.704 17.555 5.112 ;
     RECT  17.749 0.144 17.804 0.6 ;
     RECT  16.972 182.352 17.821 182.376 ;
     RECT  16.549 30.144 17.845 30.168 ;
     RECT  17.804 0.144 17.891 1.128 ;
     RECT  17.891 0.144 17.993 0.6 ;
     RECT  17.881 14.064 18.14 14.088 ;
     RECT  17.201 2.88 18.469 2.904 ;
     RECT  17.993 0.144 18.497 0.264 ;
     RECT  18.469 2.88 18.608 3.432 ;
     RECT  17.555 4.704 18.608 4.728 ;
     RECT  18.14 14.064 18.608 14.232 ;
     RECT  17.804 15.984 18.608 16.008 ;
     RECT  16.355 19.632 18.608 20.184 ;
     RECT  18.38 24.096 18.608 24.12 ;
     RECT  18.085 27.312 18.608 27.336 ;
     RECT  17.845 30.144 18.608 30.744 ;
     RECT  17.989 33.504 18.608 33.528 ;
     RECT  18.565 179.088 18.608 179.112 ;
     RECT  18.229 181.824 18.608 181.848 ;
     RECT  18.608 2.148 18.661 181.848 ;
     RECT  18.497 0.192 18.755 0.264 ;
     RECT  18.661 2.016 18.904 181.848 ;
     RECT  18.904 2.016 18.965 3.432 ;
     RECT  18.965 2.832 19.001 3.432 ;
     RECT  18.904 17.04 19.081 17.064 ;
     RECT  18.904 4.512 19.084 5.592 ;
     RECT  19.084 4.56 19.101 5.592 ;
     RECT  19.093 0.576 19.397 1.176 ;
     RECT  19.397 0.576 19.649 0.6 ;
     RECT  18.904 30 19.957 30.168 ;
     RECT  19.001 2.832 19.973 2.952 ;
     RECT  19.101 4.56 20.081 5.304 ;
     RECT  19.957 0.144 20.225 0.168 ;
     RECT  18.904 25.68 20.3 25.704 ;
     RECT  19.957 30 20.369 30.6 ;
     RECT  20.3 25.68 20.387 25.992 ;
     RECT  20.387 25.68 20.636 25.704 ;
     RECT  20.081 4.56 20.657 4.68 ;
     RECT  20.636 25.44 20.693 25.704 ;
     RECT  18.904 19.632 20.725 20.184 ;
     RECT  20.725 19.488 20.809 20.184 ;
     RECT  18.904 179.088 20.837 179.112 ;
     RECT  19.973 2.88 20.869 2.952 ;
     RECT  20.657 4.56 20.869 4.584 ;
     RECT  18.904 181.824 20.869 181.848 ;
     RECT  20.869 181.824 20.953 182.376 ;
     RECT  20.869 4.08 20.956 4.584 ;
     RECT  20.761 22.32 20.972 22.344 ;
     RECT  20.972 22.32 21.107 22.44 ;
     RECT  20.956 4.56 21.197 4.584 ;
     RECT  20.869 2.88 21.229 3 ;
     RECT  21.107 22.416 21.233 22.44 ;
     RECT  21.229 2.88 21.305 3.432 ;
     RECT  21.301 0.24 21.349 0.264 ;
     RECT  21.349 0.144 21.733 0.264 ;
     RECT  20.693 25.44 21.884 25.464 ;
     RECT  21.733 0.144 21.953 0.6 ;
     RECT  21.884 24.864 21.971 25.464 ;
     RECT  21.805 180.144 22.213 180.168 ;
     RECT  22.261 21.552 22.349 21.576 ;
     RECT  21.971 25.44 22.349 25.464 ;
     RECT  22.213 179.808 22.457 180.168 ;
     RECT  20.953 181.824 22.489 181.848 ;
     RECT  22.213 18.192 22.529 18.216 ;
     RECT  22.489 181.824 22.643 182.376 ;
     RECT  21.305 3.408 22.645 3.432 ;
     RECT  22.645 2.88 22.889 3.432 ;
     RECT  22.889 2.88 22.961 2.904 ;
     RECT  23.057 1.152 23.141 1.176 ;
     RECT  22.165 4.56 23.389 4.584 ;
     RECT  21.953 0.144 23.453 0.168 ;
     RECT  23.389 4.224 23.893 4.584 ;
     RECT  23.533 25.008 23.929 25.032 ;
     RECT  23.137 2.592 24.008 2.856 ;
     RECT  23.893 3.984 24.008 4.584 ;
     RECT  20.809 19.632 24.008 20.184 ;
     RECT  23.929 24.384 24.008 25.032 ;
     RECT  20.369 30 24.008 30.024 ;
     RECT  22.457 180.144 24.008 180.168 ;
     RECT  22.643 181.824 24.008 181.848 ;
     RECT  24.008 2.148 24.112 181.848 ;
     RECT  24.112 2.418 24.304 181.848 ;
     RECT  24.304 19.632 24.419 21.144 ;
     RECT  24.304 2.88 24.473 4.248 ;
     RECT  24.304 18.384 24.508 18.408 ;
     RECT  24.473 2.88 24.545 3.432 ;
     RECT  24.545 2.88 24.653 2.904 ;
     RECT  23.453 0.144 24.805 0.6 ;
     RECT  24.805 0.144 25.085 1.176 ;
     RECT  24.304 31.968 25.129 31.992 ;
     RECT  24.304 29.664 25.139 29.688 ;
     RECT  24.304 179.232 25.297 179.256 ;
     RECT  25.085 0.144 25.301 0.6 ;
     RECT  25.285 29.184 25.373 29.208 ;
     RECT  25.301 0.144 25.409 0.168 ;
     RECT  25.484 6.528 25.571 6.552 ;
     RECT  25.297 179.232 25.769 180.168 ;
     RECT  25.573 4.56 25.877 4.584 ;
     RECT  25.964 27.312 26.051 27.336 ;
     RECT  26.005 3.984 26.093 4.008 ;
     RECT  25.669 16.992 26.129 17.016 ;
     RECT  26.125 5.712 26.243 5.736 ;
     RECT  26.101 3.408 26.309 3.432 ;
     RECT  25.909 21.36 26.387 21.384 ;
     RECT  25.669 0.096 26.437 0.12 ;
     RECT  26.437 0.096 26.705 0.6 ;
     RECT  24.304 181.824 27.059 181.848 ;
     RECT  27.013 2.88 27.241 2.904 ;
     RECT  27.241 2.16 27.347 2.904 ;
     RECT  27.452 23.808 27.539 23.832 ;
     RECT  27.301 5.664 27.641 5.688 ;
     RECT  27.829 26.736 27.916 26.76 ;
     RECT  27.733 4.56 28.001 4.584 ;
     RECT  27.347 2.88 28.145 2.904 ;
     RECT  28.213 31.536 28.355 31.56 ;
     RECT  28.309 1.152 28.469 1.176 ;
     RECT  26.705 0.096 28.741 0.12 ;
     RECT  28.597 3.408 28.997 3.432 ;
     RECT  28.997 3.408 29.257 4.008 ;
     RECT  29.257 2.832 29.408 4.008 ;
     RECT  28.46 17.52 29.408 17.544 ;
     RECT  24.419 19.632 29.408 20.184 ;
     RECT  29.077 23.808 29.408 23.832 ;
     RECT  28.321 27.216 29.408 27.24 ;
     RECT  29.173 29.424 29.408 29.448 ;
     RECT  27.529 179.568 29.408 179.592 ;
     RECT  27.413 182.352 29.408 182.376 ;
     RECT  29.408 2.148 29.512 182.376 ;
     RECT  29.512 2.418 29.545 182.376 ;
     RECT  29.545 2.418 29.699 182.424 ;
     RECT  29.699 2.418 29.704 181.848 ;
     RECT  29.704 2.418 29.837 4.008 ;
     RECT  28.741 0.096 29.893 0.6 ;
     RECT  29.704 32.544 29.909 32.568 ;
     RECT  29.893 0.096 30.053 1.176 ;
     RECT  29.704 29.808 30.313 29.832 ;
     RECT  29.704 27.552 30.515 27.576 ;
     RECT  29.837 2.418 30.517 2.952 ;
     RECT  30.053 0.096 30.593 0.6 ;
     RECT  30.517 2.304 30.845 2.952 ;
     RECT  29.837 3.984 30.853 4.008 ;
     RECT  30.805 5.424 30.853 5.448 ;
     RECT  30.845 2.832 30.899 2.952 ;
     RECT  30.805 21.408 30.953 21.432 ;
     RECT  30.853 3.984 30.989 5.448 ;
     RECT  29.704 180.144 30.997 180.168 ;
     RECT  29.704 181.824 30.997 181.848 ;
     RECT  30.899 2.832 31.061 2.904 ;
     RECT  30.997 180.144 31.084 181.848 ;
     RECT  31.084 180.144 31.133 180.168 ;
     RECT  30.997 16.608 31.277 16.632 ;
     RECT  30.989 3.984 31.313 4.584 ;
     RECT  31.237 5.616 31.324 5.64 ;
     RECT  31.313 4.56 31.421 4.584 ;
     RECT  30.593 0.096 31.561 0.12 ;
     RECT  31.561 0.096 31.813 0.552 ;
     RECT  31.957 30.576 32.044 30.6 ;
     RECT  31.909 26.016 32.285 26.04 ;
     RECT  31.061 2.832 32.465 2.856 ;
     RECT  31.084 181.824 32.812 181.848 ;
     RECT  31.813 0.096 32.825 1.176 ;
     RECT  29.704 19.632 32.828 20.184 ;
     RECT  32.828 19.632 32.915 20.328 ;
     RECT  33.073 182.352 33.203 182.376 ;
     RECT  32.825 0.096 33.401 0.12 ;
     RECT  33.505 30.72 33.635 30.744 ;
     RECT  32.825 1.152 33.661 1.176 ;
     RECT  33.589 181.248 33.676 181.272 ;
     RECT  33.781 3.408 34.021 3.432 ;
     RECT  32.917 4.56 34.189 4.584 ;
     RECT  34.213 0.576 34.337 0.6 ;
     RECT  34.021 2.88 34.501 3.432 ;
     RECT  34.189 4.56 34.501 5.16 ;
     RECT  34.021 181.824 34.765 181.848 ;
     RECT  34.501 2.88 34.808 5.16 ;
     RECT  33.829 17.616 34.808 17.64 ;
     RECT  32.915 19.632 34.808 20.184 ;
     RECT  33.901 23.376 34.808 23.4 ;
     RECT  33.901 180 34.808 180.024 ;
     RECT  34.765 181.824 34.808 182.184 ;
     RECT  34.808 2.148 34.912 182.184 ;
     RECT  34.912 2.304 34.931 182.184 ;
     RECT  34.931 2.304 35.104 181.848 ;
     RECT  35.104 19.632 35.219 20.712 ;
     RECT  35.104 25.536 35.219 25.56 ;
     RECT  35.104 4.32 35.381 4.584 ;
     RECT  35.381 4.32 35.404 4.344 ;
     RECT  34.453 0.096 35.509 0.168 ;
     RECT  35.104 27.84 35.597 27.864 ;
     RECT  35.509 0.096 35.705 0.6 ;
     RECT  35.104 31.68 36.029 31.704 ;
     RECT  35.104 2.304 36.137 3.192 ;
     RECT  35.104 181.824 36.205 181.848 ;
     RECT  35.705 0.576 36.229 0.6 ;
     RECT  36.205 181.824 36.289 182.376 ;
     RECT  36.137 2.64 36.373 3.192 ;
     RECT  36.133 21.648 36.515 21.672 ;
     RECT  36.229 0.576 36.893 1.176 ;
     RECT  37.069 17.04 37.153 17.064 ;
     RECT  36.469 22.8 37.333 22.824 ;
     RECT  37.333 22.704 37.42 22.824 ;
     RECT  37.393 30.816 37.571 30.84 ;
     RECT  36.373 2.64 37.757 3.432 ;
     RECT  37.205 0.096 37.865 0.12 ;
     RECT  37.957 27.072 38.044 27.096 ;
     RECT  37.573 4.56 38.069 4.584 ;
     RECT  38.06 30.912 38.147 30.936 ;
     RECT  38.069 3.984 38.153 4.584 ;
     RECT  38.108 179.328 38.195 179.352 ;
     RECT  36.289 181.824 38.483 181.848 ;
     RECT  38.153 4.56 38.533 4.584 ;
     RECT  38.533 4.56 38.549 4.632 ;
     RECT  38.485 28.656 38.572 28.68 ;
     RECT  37.42 22.8 38.723 22.824 ;
     RECT  38.684 25.536 38.771 25.56 ;
     RECT  37.757 2.64 38.801 2.904 ;
     RECT  38.761 179.04 38.845 179.064 ;
     RECT  38.821 6.528 38.908 6.552 ;
     RECT  38.797 182.352 38.915 182.376 ;
     RECT  36.893 1.152 38.965 1.176 ;
     RECT  35.219 19.632 38.972 20.184 ;
     RECT  38.972 19.632 39.059 20.52 ;
     RECT  39.061 17.04 39.148 17.064 ;
     RECT  38.549 4.608 39.161 4.632 ;
     RECT  38.965 0.576 39.265 1.176 ;
     RECT  38.773 29.664 39.265 29.688 ;
     RECT  39.265 0.576 39.349 1.272 ;
     RECT  38.773 22.56 39.445 22.584 ;
     RECT  39.301 181.248 39.733 181.272 ;
     RECT  39.349 0.576 39.845 1.176 ;
     RECT  39.541 179.52 39.877 179.544 ;
     RECT  40.057 0.528 40.069 0.552 ;
     RECT  39.301 3.408 40.069 3.432 ;
     RECT  39.781 4.56 40.129 4.584 ;
     RECT  40.069 2.88 40.208 3.432 ;
     RECT  40.129 4.56 40.208 5.064 ;
     RECT  40.021 6.816 40.208 6.84 ;
     RECT  39.059 19.632 40.208 20.184 ;
     RECT  39.445 22.176 40.208 22.584 ;
     RECT  39.265 29.664 40.208 30.072 ;
     RECT  39.877 179.28 40.208 179.544 ;
     RECT  39.733 181.248 40.208 181.848 ;
     RECT  40.069 0.144 40.259 0.552 ;
     RECT  40.208 2.148 40.312 181.848 ;
     RECT  40.312 2.418 40.504 181.848 ;
     RECT  40.504 2.736 40.565 2.904 ;
     RECT  40.504 24.96 40.931 25.032 ;
     RECT  40.931 25.008 41.027 25.032 ;
     RECT  40.504 27.648 41.123 27.672 ;
     RECT  40.259 0.144 41.525 0.264 ;
     RECT  41.509 17.04 41.596 17.064 ;
     RECT  40.504 30.048 41.605 30.072 ;
     RECT  41.525 0.144 41.609 1.176 ;
     RECT  41.509 3.984 41.609 4.008 ;
     RECT  40.504 5.04 41.645 5.064 ;
     RECT  41.605 28.176 41.689 28.2 ;
     RECT  41.605 30.048 41.789 30.408 ;
     RECT  40.565 2.736 41.989 2.76 ;
     RECT  41.713 27.072 42.001 27.096 ;
     RECT  42.001 26.832 42.131 27.096 ;
     RECT  42.131 27.072 42.179 27.096 ;
     RECT  41.989 2.736 42.221 2.904 ;
     RECT  42.221 2.88 42.257 2.904 ;
     RECT  41.821 4.368 42.401 4.392 ;
     RECT  42.181 25.152 42.401 25.176 ;
     RECT  41.789 30.384 42.467 30.408 ;
     RECT  42.648 22.752 42.649 22.776 ;
     RECT  40.504 179.184 42.649 179.208 ;
     RECT  42.649 179.184 42.65 179.256 ;
     RECT  42.649 22.752 42.733 22.92 ;
     RECT  42.65 179.232 42.853 179.256 ;
     RECT  40.504 181.824 42.892 181.848 ;
     RECT  42.853 179.232 42.899 180.168 ;
     RECT  42.853 25.44 42.94 25.464 ;
     RECT  42.899 180 42.941 180.168 ;
     RECT  41.609 0.144 43.013 0.6 ;
     RECT  43.013 0.24 43.049 0.6 ;
     RECT  43.052 28.32 43.139 28.344 ;
     RECT  42.733 22.752 43.152 22.776 ;
     RECT  43.237 3.408 43.333 3.432 ;
     RECT  40.504 19.632 43.333 20.184 ;
     RECT  42.941 180 43.373 180.024 ;
     RECT  43.333 19.536 43.481 20.184 ;
     RECT  43.225 182.352 43.715 182.376 ;
     RECT  43.333 2.592 43.717 3.432 ;
     RECT  43.717 2.304 43.913 3.432 ;
     RECT  43.669 4.56 43.985 4.584 ;
     RECT  43.909 17.424 44.021 17.448 ;
     RECT  44.156 28.272 44.243 28.296 ;
     RECT  44.348 22.56 44.435 22.584 ;
     RECT  43.253 1.152 44.453 1.176 ;
     RECT  43.913 2.592 44.489 3.432 ;
     RECT  44.533 0.24 44.581 0.264 ;
     RECT  44.489 2.688 44.627 3.432 ;
     RECT  44.581 0.144 44.669 0.264 ;
     RECT  44.627 2.88 44.945 3.432 ;
     RECT  44.669 0.144 45.317 0.168 ;
     RECT  44.413 179.568 45.565 179.592 ;
     RECT  44.945 2.88 45.608 4.008 ;
     RECT  45.349 5.04 45.608 5.064 ;
     RECT  45.457 17.424 45.608 17.448 ;
     RECT  43.481 19.632 45.608 20.184 ;
     RECT  44.437 25.68 45.608 25.704 ;
     RECT  45.349 28.656 45.608 28.68 ;
     RECT  44.845 31.296 45.608 31.32 ;
     RECT  45.565 179.568 45.608 179.928 ;
     RECT  44.108 181.824 45.608 181.848 ;
     RECT  45.608 2.148 45.712 181.848 ;
     RECT  45.829 0.48 45.877 0.6 ;
     RECT  45.712 2.418 45.904 181.848 ;
     RECT  45.904 30.768 46.001 31.656 ;
     RECT  45.904 28.368 46.115 28.872 ;
     RECT  45.877 0.48 46.181 1.176 ;
     RECT  45.904 17.424 46.325 17.448 ;
     RECT  46.181 0.48 46.505 0.6 ;
     RECT  46.115 28.368 46.541 28.392 ;
     RECT  45.904 4.32 46.649 5.064 ;
     RECT  46.649 4.32 46.739 4.44 ;
     RECT  46.001 30.96 46.739 31.656 ;
     RECT  45.904 34.464 46.739 34.632 ;
     RECT  46.739 4.32 46.8 4.344 ;
     RECT  45.904 181.824 46.876 181.848 ;
     RECT  45.904 179.568 46.901 179.928 ;
     RECT  46.739 34.464 46.925 34.488 ;
     RECT  45.904 22.608 46.937 22.632 ;
     RECT  46.925 34.08 47.009 34.488 ;
     RECT  47.105 3.984 47.189 4.008 ;
     RECT  45.904 2.832 47.221 2.856 ;
     RECT  47.221 2.832 47.261 2.904 ;
     RECT  46.739 31.632 47.267 31.656 ;
     RECT  47.009 34.464 47.297 34.488 ;
     RECT  46.901 179.568 47.333 179.592 ;
     RECT  47.261 2.88 47.441 2.904 ;
     RECT  47.372 16.512 47.459 16.536 ;
     RECT  47.605 28.464 47.692 28.488 ;
     RECT  47.221 182.352 47.699 182.376 ;
     RECT  47.645 1.152 47.729 1.176 ;
     RECT  46.789 0.096 47.948 0.12 ;
     RECT  47.948 0.096 48.035 0.552 ;
     RECT  48.092 25.488 48.179 25.512 ;
     RECT  47.557 3.072 48.305 3.096 ;
     RECT  47.893 4.416 48.401 4.44 ;
     RECT  48.325 180.624 48.412 180.648 ;
     RECT  48.325 31.632 48.413 31.656 ;
     RECT  48.476 16.512 48.563 16.536 ;
     RECT  48.572 5.712 48.659 5.736 ;
     RECT  48.265 25.728 48.665 25.752 ;
     RECT  48.035 0.096 48.773 0.12 ;
     RECT  48.697 1.104 48.899 1.128 ;
     RECT  48.401 4.416 48.908 4.584 ;
     RECT  49.013 7.44 49.093 7.464 ;
     RECT  49.032 8.448 49.093 8.472 ;
     RECT  49.093 7.44 49.097 8.472 ;
     RECT  49.097 7.968 49.187 8.472 ;
     RECT  48.949 2.304 49.205 2.328 ;
     RECT  48.769 3.36 49.265 3.384 ;
     RECT  48.908 4.416 49.265 4.824 ;
     RECT  48.085 181.824 49.381 181.848 ;
     RECT  49.285 21.168 49.421 21.192 ;
     RECT  49.187 8.448 49.457 8.472 ;
     RECT  49.381 181.824 49.465 182.376 ;
     RECT  49.525 118.032 49.609 118.056 ;
     RECT  49.265 3.36 49.669 4.824 ;
     RECT  49.669 2.784 49.909 4.824 ;
     RECT  49.021 179.904 49.916 179.928 ;
     RECT  49.849 118.512 49.933 118.536 ;
     RECT  49.909 2.784 49.996 5.4 ;
     RECT  49.916 179.904 50.003 180.168 ;
     RECT  49.921 23.952 50.005 23.976 ;
     RECT  49.465 181.824 50.605 181.848 ;
     RECT  50.713 6.288 50.725 6.888 ;
     RECT  50.003 179.904 50.725 179.928 ;
     RECT  50.605 181.824 50.771 182.424 ;
     RECT  50.149 0.096 50.821 0.12 ;
     RECT  49.381 1.152 50.821 1.176 ;
     RECT  50.821 0.096 50.933 1.176 ;
     RECT  49.996 2.784 51.008 5.208 ;
     RECT  50.725 6.288 51.008 7.08 ;
     RECT  50.341 16.656 51.008 16.68 ;
     RECT  45.904 19.632 51.008 20.184 ;
     RECT  50.629 21.648 51.008 21.672 ;
     RECT  50.173 23.904 51.008 23.928 ;
     RECT  50.965 27.36 51.008 27.384 ;
     RECT  50.461 31.92 51.008 31.944 ;
     RECT  50.869 34.848 51.008 34.872 ;
     RECT  50.725 179.616 51.008 179.928 ;
     RECT  50.771 181.824 51.008 181.848 ;
     RECT  50.933 0.528 51.059 1.176 ;
     RECT  51.008 2.148 51.112 181.848 ;
     RECT  51.112 2.418 51.304 181.848 ;
     RECT  51.304 27.36 51.443 28.008 ;
     RECT  51.304 26.112 51.731 26.184 ;
     RECT  51.304 2.88 51.82 3.336 ;
     RECT  51.731 26.16 51.875 26.184 ;
     RECT  51.304 179.52 51.875 180.744 ;
     RECT  51.82 2.88 51.905 2.904 ;
     RECT  51.443 27.888 51.905 28.008 ;
     RECT  51.905 27.984 52.049 28.008 ;
     RECT  51.875 179.52 52.121 180.024 ;
     RECT  52.297 31.92 52.412 31.944 ;
     RECT  51.059 0.576 52.453 1.176 ;
     RECT  52.412 31.776 52.499 31.944 ;
     RECT  52.309 6.768 52.517 6.792 ;
     RECT  52.121 179.52 52.553 179.544 ;
     RECT  51.304 4.56 52.697 5.064 ;
     RECT  52.693 21.552 52.78 21.576 ;
     RECT  51.304 181.824 52.837 181.848 ;
     RECT  52.499 31.776 52.844 31.896 ;
     RECT  52.844 31.488 52.931 31.896 ;
     RECT  52.931 31.872 52.972 31.896 ;
     RECT  52.837 181.824 52.979 182.376 ;
     RECT  52.453 0.096 52.985 1.176 ;
     RECT  52.94 26.4 53.027 26.424 ;
     RECT  52.697 4.56 53.029 4.584 ;
     RECT  53.029 3.312 53.116 4.584 ;
     RECT  53.029 116.304 53.125 116.328 ;
     RECT  53.125 116.112 53.201 116.328 ;
     RECT  53.201 116.112 53.212 116.136 ;
     RECT  52.985 0.528 53.219 1.176 ;
     RECT  53.173 5.616 53.26 5.64 ;
     RECT  53.116 4.224 53.525 4.584 ;
     RECT  53.219 0.576 53.849 1.176 ;
     RECT  52.979 181.824 53.885 181.848 ;
     RECT  53.953 182.352 54.275 182.424 ;
     RECT  53.525 4.56 54.389 4.584 ;
     RECT  54.241 29.088 54.419 29.112 ;
     RECT  54.229 0.096 54.605 0.168 ;
     RECT  53.365 2.88 54.637 2.904 ;
     RECT  54.313 23.376 54.659 23.4 ;
     RECT  54.205 16.512 54.707 16.536 ;
     RECT  54.565 33.936 54.707 33.96 ;
     RECT  54.275 182.352 54.713 182.376 ;
     RECT  54.709 16.848 54.821 16.872 ;
     RECT  53.849 1.152 54.853 1.176 ;
     RECT  54.637 2.784 54.995 4.344 ;
     RECT  54.995 4.32 55.036 4.344 ;
     RECT  54.637 179.328 55.177 179.352 ;
     RECT  55.213 30.816 55.297 30.84 ;
     RECT  54.995 2.784 55.325 2.904 ;
     RECT  55.325 2.784 55.397 2.808 ;
     RECT  54.853 0.576 55.865 1.176 ;
     RECT  55.865 0.576 56.005 0.6 ;
     RECT  55.717 4.56 56.408 4.584 ;
     RECT  56.293 16.512 56.408 16.536 ;
     RECT  51.304 19.632 56.408 20.184 ;
     RECT  56.293 22.512 56.408 22.536 ;
     RECT  55.58 27.216 56.408 27.24 ;
     RECT  55.82 31.824 56.408 31.848 ;
     RECT  55.669 33.552 56.408 33.576 ;
     RECT  55.177 179.328 56.408 180.168 ;
     RECT  55.093 181.824 56.408 181.848 ;
     RECT  56.408 2.148 56.512 181.848 ;
     RECT  56.512 2.418 56.704 181.848 ;
     RECT  56.704 180.912 56.915 181.848 ;
     RECT  56.704 30.192 57.011 30.216 ;
     RECT  56.704 32.544 57.011 33.048 ;
     RECT  56.704 19.632 57.203 20.76 ;
     RECT  56.005 0.096 57.269 0.6 ;
     RECT  56.704 2.88 57.436 3.192 ;
     RECT  56.704 4.416 57.557 4.44 ;
     RECT  56.704 25.728 57.635 25.752 ;
     RECT  56.704 27.984 57.665 28.008 ;
     RECT  57.925 28.416 58.012 28.44 ;
     RECT  57.203 19.632 58.163 20.52 ;
     RECT  57.011 33.024 58.163 33.048 ;
     RECT  58.117 17.04 58.204 17.064 ;
     RECT  57.269 0.096 58.309 0.168 ;
     RECT  58.261 30.48 58.309 30.504 ;
     RECT  58.117 6.528 58.313 6.552 ;
     RECT  58.309 30.24 58.349 30.504 ;
     RECT  58.309 0.096 58.601 0.6 ;
     RECT  58.349 30.24 58.625 30.264 ;
     RECT  58.381 179.472 58.669 179.496 ;
     RECT  58.625 29.424 58.709 30.264 ;
     RECT  58.601 0.576 58.741 0.6 ;
     RECT  58.273 3.984 58.853 4.008 ;
     RECT  57.436 2.88 58.925 2.904 ;
     RECT  58.669 179.472 59.033 180.168 ;
     RECT  58.981 28.992 59.069 29.016 ;
     RECT  58.417 5.088 59.173 5.112 ;
     RECT  58.741 0.576 59.177 1.224 ;
     RECT  59.173 4.56 59.357 5.112 ;
     RECT  59.372 25.968 59.459 25.992 ;
     RECT  59.269 31.776 59.465 31.8 ;
     RECT  59.357 5.088 59.537 5.112 ;
     RECT  59.353 34.08 59.651 34.104 ;
     RECT  59.653 34.32 59.74 34.344 ;
     RECT  59.785 22.896 59.869 22.92 ;
     RECT  59.033 179.472 59.897 179.592 ;
     RECT  59.605 3.408 60.077 3.432 ;
     RECT  59.177 0.576 60.329 1.176 ;
     RECT  60.245 16.512 60.329 16.536 ;
     RECT  60.332 25.344 60.419 25.368 ;
     RECT  60.329 1.152 60.469 1.176 ;
     RECT  60.373 2.304 60.469 2.328 ;
     RECT  58.163 19.632 60.469 20.184 ;
     RECT  60.421 31.872 60.581 31.896 ;
     RECT  60.469 19.632 60.797 20.664 ;
     RECT  58.709 30.24 60.853 30.264 ;
     RECT  56.915 181.824 61.261 181.848 ;
     RECT  60.469 1.152 61.337 2.328 ;
     RECT  61.261 181.824 61.345 182.376 ;
     RECT  61.337 1.152 61.409 1.176 ;
     RECT  61.628 6.48 61.649 6.504 ;
     RECT  61.669 0.144 61.685 0.168 ;
     RECT  61.337 2.148 61.808 2.328 ;
     RECT  61.657 3.984 61.808 4.008 ;
     RECT  61.436 5.04 61.808 5.064 ;
     RECT  61.649 6.48 61.808 6.6 ;
     RECT  60.901 10.848 61.808 10.872 ;
     RECT  61.436 15.984 61.808 16.008 ;
     RECT  59.941 18.144 61.808 18.168 ;
     RECT  60.797 19.632 61.808 20.184 ;
     RECT  60.853 29.472 61.808 30.264 ;
     RECT  59.897 179.568 61.808 179.592 ;
     RECT  61.345 181.824 61.808 181.848 ;
     RECT  61.685 0.144 61.811 0.6 ;
     RECT  61.808 2.148 61.912 181.848 ;
     RECT  61.912 2.418 62.104 181.848 ;
     RECT  62.104 18.144 62.165 18.168 ;
     RECT  62.104 2.88 62.381 3.432 ;
     RECT  62.104 29.184 62.572 29.208 ;
     RECT  61.811 0.576 62.581 0.6 ;
     RECT  62.104 9.072 62.675 9.096 ;
     RECT  62.581 0.576 62.705 1.176 ;
     RECT  62.381 3.264 62.741 3.432 ;
     RECT  62.705 0.576 63.053 0.6 ;
     RECT  62.104 5.616 63.073 5.64 ;
     RECT  62.104 179.616 63.097 179.64 ;
     RECT  63.068 27.312 63.155 27.336 ;
     RECT  63.053 0.144 63.641 0.6 ;
     RECT  63.097 179.52 63.829 179.64 ;
     RECT  63.829 179.52 63.875 180.168 ;
     RECT  62.741 3.408 63.893 3.432 ;
     RECT  63.641 0.576 63.925 0.6 ;
     RECT  63.829 16.608 64.253 16.632 ;
     RECT  62.104 181.824 64.357 181.848 ;
     RECT  64.316 6.816 64.403 6.84 ;
     RECT  64.249 23.952 64.403 23.976 ;
     RECT  63.875 180.144 64.433 180.168 ;
     RECT  64.357 181.248 64.444 181.848 ;
     RECT  64.321 57.36 64.451 57.384 ;
     RECT  64.405 27.984 64.541 28.008 ;
     RECT  64.46 32.448 64.547 32.472 ;
     RECT  63.925 0.576 64.613 0.696 ;
     RECT  64.681 57.456 64.765 57.48 ;
     RECT  64.825 91.824 64.909 91.848 ;
     RECT  64.789 9.456 65.009 9.48 ;
     RECT  64.988 30.816 65.075 30.84 ;
     RECT  64.981 179.328 65.441 179.352 ;
     RECT  65.221 6.288 65.549 6.312 ;
     RECT  65.516 22.704 65.603 22.728 ;
     RECT  65.653 5.136 65.948 5.16 ;
     RECT  62.104 19.632 65.996 20.184 ;
     RECT  65.545 2.88 66.017 2.904 ;
     RECT  65.948 5.136 66.035 5.4 ;
     RECT  66.035 5.136 66.053 5.16 ;
     RECT  65.996 19.536 66.083 20.184 ;
     RECT  66.085 4.56 66.233 4.584 ;
     RECT  66.133 11.088 66.38 11.112 ;
     RECT  66.38 11.088 66.517 11.304 ;
     RECT  66.908 2.832 66.997 2.856 ;
     RECT  66.997 2.832 67.208 3.048 ;
     RECT  66.517 10.272 67.208 11.304 ;
     RECT  66.332 17.04 67.208 17.064 ;
     RECT  66.083 19.632 67.208 20.184 ;
     RECT  66.409 27.84 67.208 27.864 ;
     RECT  66.277 92.16 67.208 92.184 ;
     RECT  66.625 179.184 67.208 179.208 ;
     RECT  64.444 181.824 67.208 181.848 ;
     RECT  67.208 2.148 67.312 181.848 ;
     RECT  67.312 2.418 67.504 181.848 ;
     RECT  65.269 0.144 67.813 0.168 ;
     RECT  64.817 1.152 67.813 1.176 ;
     RECT  67.813 0.144 67.997 1.176 ;
     RECT  67.504 179.616 67.997 179.784 ;
     RECT  67.504 181.824 68.173 181.848 ;
     RECT  67.504 8.544 68.321 8.568 ;
     RECT  68.173 181.824 68.339 182.376 ;
     RECT  67.504 25.632 68.435 25.656 ;
     RECT  67.504 30.864 68.435 30.888 ;
     RECT  67.504 123.168 68.645 123.192 ;
     RECT  68.581 28.8 68.668 28.824 ;
     RECT  67.997 0.144 68.725 0.168 ;
     RECT  68.821 16.944 68.908 16.968 ;
     RECT  67.504 5.136 68.933 5.16 ;
     RECT  68.629 2.256 68.969 2.28 ;
     RECT  68.725 0.096 69.061 0.168 ;
     RECT  67.997 1.152 69.061 1.176 ;
     RECT  69.061 0.096 69.149 1.176 ;
     RECT  68.965 5.424 69.389 5.448 ;
     RECT  69.253 2.784 69.397 2.808 ;
     RECT  69.317 22.896 69.401 22.92 ;
     RECT  69.389 5.424 69.473 6.312 ;
     RECT  69.397 2.784 69.539 3 ;
     RECT  69.473 5.424 69.539 5.448 ;
     RECT  67.997 179.76 69.581 179.784 ;
     RECT  69.539 2.784 70.229 2.904 ;
     RECT  70.153 123.168 70.237 123.192 ;
     RECT  70.357 25.968 70.444 25.992 ;
     RECT  69.925 6.864 70.604 6.888 ;
     RECT  70.577 27.888 70.604 27.912 ;
     RECT  70.604 27.792 70.661 27.912 ;
     RECT  70.604 6.288 70.691 6.888 ;
     RECT  70.661 27.792 70.691 27.816 ;
     RECT  70.691 6.864 70.697 6.888 ;
     RECT  70.501 2.304 70.805 2.328 ;
     RECT  69.149 1.152 71.201 1.176 ;
     RECT  70.693 26.256 71.201 26.28 ;
     RECT  70.909 17.136 71.267 17.16 ;
     RECT  71.197 3.984 71.281 4.008 ;
     RECT  71.276 30.576 71.305 30.6 ;
     RECT  71.305 30.576 71.363 30.984 ;
     RECT  68.339 181.824 71.845 181.848 ;
     RECT  71.797 183.456 71.939 183.48 ;
     RECT  71.521 3.936 72.085 3.96 ;
     RECT  72.085 3.408 72.229 3.96 ;
     RECT  71.363 30.96 72.373 30.984 ;
     RECT  72.229 2.88 72.608 3.96 ;
     RECT  72.229 4.944 72.608 4.968 ;
     RECT  71.653 10.848 72.608 10.872 ;
     RECT  67.504 19.632 72.608 20.184 ;
     RECT  72.305 22.464 72.608 22.488 ;
     RECT  72.385 28.992 72.608 29.016 ;
     RECT  72.373 30.816 72.608 30.984 ;
     RECT  72.197 33.12 72.608 33.144 ;
     RECT  71.485 180.144 72.608 180.168 ;
     RECT  71.845 181.824 72.608 182.376 ;
     RECT  72.608 2.148 72.712 182.376 ;
     RECT  72.701 1.152 72.785 1.176 ;
     RECT  72.712 2.418 72.904 182.376 ;
     RECT  69.149 0.096 72.949 0.12 ;
     RECT  72.949 0.096 73.037 0.6 ;
     RECT  72.904 181.824 73.228 182.376 ;
     RECT  72.904 16.128 73.324 16.152 ;
     RECT  72.904 28.992 73.571 29.016 ;
     RECT  73.228 182.352 73.657 182.376 ;
     RECT  72.904 24.816 73.708 24.84 ;
     RECT  72.904 19.344 73.757 20.184 ;
     RECT  73.037 0.096 73.793 0.168 ;
     RECT  72.904 3.936 74.003 4.584 ;
     RECT  73.793 0.144 74.045 0.168 ;
     RECT  72.904 22.704 74.092 22.728 ;
     RECT  74.003 4.512 74.153 4.584 ;
     RECT  74.005 181.248 74.189 181.272 ;
     RECT  72.904 180.144 74.221 180.168 ;
     RECT  74.005 2.88 74.297 3.432 ;
     RECT  74.197 32.448 74.339 32.472 ;
     RECT  74.204 0.528 74.429 0.552 ;
     RECT  74.153 4.56 74.509 4.584 ;
     RECT  74.429 0.528 74.513 1.176 ;
     RECT  74.221 179.904 74.513 180.168 ;
     RECT  74.297 2.88 74.545 2.904 ;
     RECT  74.513 179.904 74.675 179.928 ;
     RECT  74.513 0.528 74.737 0.552 ;
     RECT  74.677 17.472 74.909 17.496 ;
     RECT  73.757 19.632 75.116 20.184 ;
     RECT  74.677 28.992 75.161 29.016 ;
     RECT  75.116 19.632 75.203 20.568 ;
     RECT  74.509 4.56 75.233 5.112 ;
     RECT  74.437 181.824 75.301 181.848 ;
     RECT  75.233 4.56 75.305 4.584 ;
     RECT  75.301 181.824 75.385 182.376 ;
     RECT  75.253 21.648 75.521 21.672 ;
     RECT  74.545 2.64 75.541 2.904 ;
     RECT  75.541 2.64 75.781 3.432 ;
     RECT  76.069 26.256 76.156 26.28 ;
     RECT  75.781 2.304 76.205 3.432 ;
     RECT  76.165 30.576 76.252 30.6 ;
     RECT  75.697 180 76.273 180.024 ;
     RECT  76.213 1.152 76.385 1.176 ;
     RECT  76.273 180 76.745 180.744 ;
     RECT  76.205 2.928 77.209 3.432 ;
     RECT  77.269 4.656 77.353 4.68 ;
     RECT  77.365 28.176 77.389 28.2 ;
     RECT  75.385 181.824 77.468 181.848 ;
     RECT  77.209 2.832 77.544 3.432 ;
     RECT  77.353 4.56 77.544 5.112 ;
     RECT  77.468 181.824 77.555 182.424 ;
     RECT  75.203 19.632 77.885 20.184 ;
     RECT  77.921 1.152 78.005 1.176 ;
     RECT  77.544 2.832 78.008 5.112 ;
     RECT  77.677 17.04 78.008 17.064 ;
     RECT  77.885 19.632 78.008 20.328 ;
     RECT  77.845 25.872 78.008 25.896 ;
     RECT  77.389 28.176 78.008 28.44 ;
     RECT  77.893 30.144 78.008 30.168 ;
     RECT  76.745 180 78.008 180.024 ;
     RECT  77.555 181.824 78.008 181.848 ;
     RECT  78.008 2.148 78.112 181.848 ;
     RECT  78.112 2.418 78.304 181.848 ;
     RECT  78.304 181.824 78.419 181.848 ;
     RECT  78.304 33.12 78.473 33.144 ;
     RECT  78.304 179.568 78.473 180.024 ;
     RECT  78.304 19.632 78.563 20.376 ;
     RECT  78.304 2.688 78.689 2.904 ;
     RECT  78.304 5.616 78.733 7.08 ;
     RECT  78.689 2.688 78.833 2.856 ;
     RECT  78.757 182.352 79.189 182.376 ;
     RECT  75.301 0.096 79.285 0.12 ;
     RECT  78.304 4.56 79.301 4.584 ;
     RECT  79.189 182.352 79.331 182.424 ;
     RECT  78.304 22.32 79.337 22.344 ;
     RECT  78.473 179.568 79.373 179.592 ;
     RECT  79.397 3.984 79.481 4.008 ;
     RECT  79.285 0.096 79.625 0.6 ;
     RECT  78.733 5.616 79.697 5.64 ;
     RECT  79.685 1.152 79.769 1.176 ;
     RECT  79.729 26.736 79.813 26.76 ;
     RECT  79.772 7.056 79.859 7.08 ;
     RECT  78.563 19.632 79.861 20.184 ;
     RECT  79.861 19.632 79.949 20.232 ;
     RECT  79.861 27.888 79.949 27.912 ;
     RECT  78.833 2.688 80.149 2.712 ;
     RECT  80.149 2.688 80.485 2.904 ;
     RECT  80.405 27.408 80.489 27.432 ;
     RECT  80.341 22.752 80.492 22.776 ;
     RECT  80.485 2.4 80.569 2.904 ;
     RECT  80.492 22.464 80.579 22.776 ;
     RECT  80.293 4.56 80.581 4.584 ;
     RECT  80.588 16.944 80.675 16.968 ;
     RECT  80.579 22.752 80.705 22.776 ;
     RECT  80.581 4.08 80.809 4.584 ;
     RECT  80.485 33.12 80.963 33.144 ;
     RECT  79.625 0.096 81.061 0.12 ;
     RECT  81.301 28.896 81.388 29.256 ;
     RECT  81.388 29.232 81.389 29.256 ;
     RECT  79.331 182.352 81.452 182.376 ;
     RECT  80.809 3.312 81.532 4.584 ;
     RECT  81.452 182.352 81.539 182.424 ;
     RECT  81.061 0.096 81.557 0.552 ;
     RECT  81.557 0.096 81.641 0.6 ;
     RECT  81.349 180.048 81.673 180.072 ;
     RECT  81.532 4.08 81.677 4.584 ;
     RECT  81.637 5.616 81.721 5.64 ;
     RECT  81.877 10.416 81.884 10.44 ;
     RECT  81.677 4.56 81.889 4.584 ;
     RECT  81.877 34.608 81.889 34.632 ;
     RECT  81.493 21.744 81.929 21.768 ;
     RECT  81.884 10.416 81.964 10.536 ;
     RECT  81.877 31.632 81.964 31.656 ;
     RECT  81.964 10.512 81.971 10.536 ;
     RECT  81.973 114.24 81.997 114.264 ;
     RECT  81.889 34.608 82.019 34.872 ;
     RECT  81.673 180.048 82.021 180.168 ;
     RECT  81.997 113.952 82.06 114.264 ;
     RECT  81.889 4.56 82.067 4.68 ;
     RECT  82.021 179.52 82.067 180.168 ;
     RECT  81.997 25.44 82.081 25.464 ;
     RECT  82.06 113.952 82.081 113.976 ;
     RECT  82.067 179.52 82.109 179.88 ;
     RECT  82.019 34.608 82.165 34.632 ;
     RECT  81.925 2.304 82.213 2.328 ;
     RECT  82.165 33.792 82.252 34.632 ;
     RECT  82.213 2.304 82.253 3 ;
     RECT  81.641 0.096 82.937 0.12 ;
     RECT  82.067 4.56 83.18 4.584 ;
     RECT  83.18 4.56 83.221 4.68 ;
     RECT  79.949 19.632 83.269 20.184 ;
     RECT  83.221 0.144 83.333 0.36 ;
     RECT  82.253 2.88 83.408 3 ;
     RECT  83.221 4.512 83.408 4.68 ;
     RECT  82.501 16.416 83.408 16.44 ;
     RECT  83.293 18.192 83.408 18.216 ;
     RECT  83.269 19.344 83.408 20.184 ;
     RECT  82.309 21.792 83.408 21.816 ;
     RECT  82.645 29.52 83.408 29.544 ;
     RECT  82.117 31.392 83.408 31.416 ;
     RECT  82.565 32.448 83.408 32.472 ;
     RECT  82.252 34.608 83.408 34.632 ;
     RECT  82.109 179.856 83.408 179.88 ;
     RECT  81.884 181.824 83.408 181.848 ;
     RECT  83.408 2.148 83.512 181.848 ;
     RECT  83.333 0.24 83.585 0.36 ;
     RECT  83.512 2.256 83.704 181.848 ;
     RECT  83.585 0.336 83.747 0.36 ;
     RECT  83.704 2.256 83.765 3.432 ;
     RECT  83.704 4.512 83.837 5.208 ;
     RECT  83.704 23.808 83.843 23.832 ;
     RECT  83.704 19.632 84.124 20.712 ;
     RECT  83.837 4.56 84.227 5.208 ;
     RECT  83.765 2.304 84.269 3.432 ;
     RECT  84.269 2.304 84.593 2.904 ;
     RECT  84.227 4.56 84.953 5.064 ;
     RECT  84.085 1.152 84.997 1.176 ;
     RECT  84.593 2.88 85.025 2.904 ;
     RECT  84.953 5.04 85.385 5.064 ;
     RECT  84.997 0.576 85.477 1.176 ;
     RECT  85.445 115.824 85.484 115.848 ;
     RECT  85.429 22.176 85.516 22.2 ;
     RECT  85.345 31.392 85.523 31.416 ;
     RECT  85.484 115.824 85.529 116.088 ;
     RECT  85.529 116.064 85.571 116.088 ;
     RECT  85.477 15.456 85.601 15.48 ;
     RECT  85.628 25.056 85.715 25.08 ;
     RECT  83.704 181.824 85.777 181.848 ;
     RECT  85.345 3.936 85.853 3.96 ;
     RECT  85.777 181.824 85.907 182.376 ;
     RECT  85.477 0.144 85.961 1.176 ;
     RECT  84.877 27.888 85.989 27.912 ;
     RECT  85.429 5.136 86.141 5.16 ;
     RECT  86.341 21.936 86.429 21.96 ;
     RECT  86.54 22.272 86.627 22.296 ;
     RECT  84.124 19.632 86.629 20.184 ;
     RECT  86.629 19.536 86.716 20.184 ;
     RECT  85.957 179.616 86.773 179.64 ;
     RECT  86.773 179.616 86.819 180.168 ;
     RECT  86.819 180 86.86 180.168 ;
     RECT  85.961 0.144 86.969 0.6 ;
     RECT  87.068 24.912 87.155 24.936 ;
     RECT  86.425 4.896 87.157 4.92 ;
     RECT  86.86 180 87.329 180.024 ;
     RECT  87.356 30 87.443 30.024 ;
     RECT  87.157 4.56 87.493 4.92 ;
     RECT  87.073 2.832 87.505 2.856 ;
     RECT  87.493 3.936 87.505 4.92 ;
     RECT  87.397 13.632 87.509 13.656 ;
     RECT  87.505 2.832 87.545 4.92 ;
     RECT  87.545 3.312 87.58 4.92 ;
     RECT  87.58 4.512 87.613 4.92 ;
     RECT  87.613 4.512 87.833 5.688 ;
     RECT  85.907 181.824 87.937 181.848 ;
     RECT  87.937 181.824 88.115 182.376 ;
     RECT  86.969 0.144 88.453 0.168 ;
     RECT  87.605 1.152 88.453 1.176 ;
     RECT  87.58 3.312 88.693 3.336 ;
     RECT  88.069 2.304 88.808 2.328 ;
     RECT  88.693 3.312 88.808 3.432 ;
     RECT  87.833 4.512 88.808 4.584 ;
     RECT  88.693 17.088 88.808 17.496 ;
     RECT  86.716 19.632 88.808 20.184 ;
     RECT  87.98 22.416 88.808 22.44 ;
     RECT  88.325 27.744 88.808 27.768 ;
     RECT  88.501 29.04 88.808 29.064 ;
     RECT  88.115 181.824 88.808 181.848 ;
     RECT  88.808 2.148 88.912 181.848 ;
     RECT  88.912 2.418 89.104 181.848 ;
     RECT  89.104 3.312 89.165 3.336 ;
     RECT  89.104 22.752 89.219 22.776 ;
     RECT  89.104 30.864 89.219 30.888 ;
     RECT  89.104 19.632 89.317 21.624 ;
     RECT  88.453 0.144 89.345 1.176 ;
     RECT  89.345 1.152 89.417 1.176 ;
     RECT  89.317 19.632 89.52 21.336 ;
     RECT  89.52 19.632 89.555 20.52 ;
     RECT  89.104 5.712 89.597 5.736 ;
     RECT  89.104 181.824 89.665 181.848 ;
     RECT  89.665 181.824 89.843 182.376 ;
     RECT  89.104 27.984 89.921 28.008 ;
     RECT  89.104 26.256 90.083 26.28 ;
     RECT  89.345 0.144 90.277 0.168 ;
     RECT  89.104 4.56 90.317 4.584 ;
     RECT  89.104 180.144 90.389 180.168 ;
     RECT  90.517 18.144 90.659 18.168 ;
     RECT  90.764 21.552 90.851 21.576 ;
     RECT  90.277 0.096 90.893 0.168 ;
     RECT  90.893 0.096 90.965 0.12 ;
     RECT  90.529 3.408 91.045 3.432 ;
     RECT  91.045 3.408 91.253 4.392 ;
     RECT  91.237 26.448 91.324 26.472 ;
     RECT  91.177 28.464 91.475 28.488 ;
     RECT  91.388 31.632 91.475 31.656 ;
     RECT  91.253 3.696 91.477 4.392 ;
     RECT  91.133 1.152 91.685 1.176 ;
     RECT  91.628 180.624 91.715 180.648 ;
     RECT  91.82 22.752 91.907 22.776 ;
     RECT  91.861 0.528 92.005 0.552 ;
     RECT  92.3 26.256 92.387 26.28 ;
     RECT  89.843 181.824 92.797 181.848 ;
     RECT  92.797 181.824 92.963 182.424 ;
     RECT  91.477 3.696 93.161 4.584 ;
     RECT  92.005 0.096 93.205 0.552 ;
     RECT  93.161 3.696 93.349 4.44 ;
     RECT  93.205 0.096 93.449 0.6 ;
     RECT  93.761 1.152 93.845 1.176 ;
     RECT  93.157 6.288 93.941 6.312 ;
     RECT  93.449 0.096 94.133 0.168 ;
     RECT  93.349 2.88 94.208 4.44 ;
     RECT  93.941 5.616 94.208 6.312 ;
     RECT  93.452 17.616 94.208 17.64 ;
     RECT  89.555 19.632 94.208 20.184 ;
     RECT  93.493 22.752 94.208 22.776 ;
     RECT  94.069 25.008 94.208 25.032 ;
     RECT  93.949 27.408 94.208 27.432 ;
     RECT  92.917 31.296 94.208 31.32 ;
     RECT  93.013 179.76 94.208 179.784 ;
     RECT  92.963 181.824 94.208 181.848 ;
     RECT  94.208 2.148 94.312 181.848 ;
     RECT  94.312 2.256 94.504 181.848 ;
     RECT  94.504 179.904 94.565 179.928 ;
     RECT  94.504 19.632 94.601 20.904 ;
     RECT  94.525 182.928 94.691 182.952 ;
     RECT  94.504 2.256 94.709 2.328 ;
     RECT  94.504 15.408 94.897 15.432 ;
     RECT  94.504 4.416 94.924 5.64 ;
     RECT  94.504 30.864 94.931 30.888 ;
     RECT  94.504 18.24 94.997 18.264 ;
     RECT  94.924 4.416 95.033 5.016 ;
     RECT  95.033 4.992 95.213 5.016 ;
     RECT  94.709 2.304 95.321 2.328 ;
     RECT  95.324 1.104 95.489 1.128 ;
     RECT  94.504 27.744 95.507 27.768 ;
     RECT  95.489 1.104 95.573 1.176 ;
     RECT  94.133 0.096 95.797 0.12 ;
     RECT  95.797 0.096 96.077 0.6 ;
     RECT  94.504 181.824 96.077 181.848 ;
     RECT  95.893 31.872 96.323 31.896 ;
     RECT  96.284 21.648 96.371 21.672 ;
     RECT  96.325 30.192 96.397 30.216 ;
     RECT  96.397 29.76 96.437 30.216 ;
     RECT  96.289 182.4 96.467 182.424 ;
     RECT  96.209 3.984 96.469 4.008 ;
     RECT  96.437 29.76 96.652 29.784 ;
     RECT  96.716 26.448 96.803 26.472 ;
     RECT  96.469 3.408 96.905 4.008 ;
     RECT  96.853 181.248 96.941 181.272 ;
     RECT  96.853 2.304 97.093 2.328 ;
     RECT  97.093 1.728 97.409 2.328 ;
     RECT  97.477 32.688 97.564 32.712 ;
     RECT  97.621 6.528 97.708 6.552 ;
     RECT  97.409 2.304 97.717 2.328 ;
     RECT  96.905 3.408 97.717 3.96 ;
     RECT  97.669 28.416 97.756 28.44 ;
     RECT  97.717 2.304 97.769 3.96 ;
     RECT  97.717 25.008 97.804 25.032 ;
     RECT  97.769 2.832 97.909 3.96 ;
     RECT  97.909 2.832 98.065 4.008 ;
     RECT  98.005 6.864 98.092 6.888 ;
     RECT  98.065 2.88 98.093 4.008 ;
     RECT  98.093 3.408 98.149 4.008 ;
     RECT  98.089 16.608 98.173 16.632 ;
     RECT  98.101 27.888 98.188 27.912 ;
     RECT  98.149 3.408 98.237 4.824 ;
     RECT  96.077 0.096 98.333 0.12 ;
     RECT  98.237 4.512 98.377 4.824 ;
     RECT  97.285 181.824 98.449 181.848 ;
     RECT  98.005 31.104 98.561 31.128 ;
     RECT  98.449 23.616 98.627 23.64 ;
     RECT  98.449 181.824 98.675 182.424 ;
     RECT  94.601 19.632 98.677 20.184 ;
     RECT  98.333 0.096 98.885 0.216 ;
     RECT  98.885 0.144 99.053 0.216 ;
     RECT  99.053 0.144 99.251 1.176 ;
     RECT  98.237 3.408 99.413 3.432 ;
     RECT  98.377 4.512 99.413 5.208 ;
     RECT  98.677 19.632 99.457 20.76 ;
     RECT  99.493 2.304 99.608 2.328 ;
     RECT  99.413 3.408 99.608 5.208 ;
     RECT  99.457 19.632 99.608 20.952 ;
     RECT  99.452 31.296 99.608 31.32 ;
     RECT  97.837 179.568 99.608 179.592 ;
     RECT  98.675 181.824 99.608 181.848 ;
     RECT  99.251 0.144 99.683 0.168 ;
     RECT  99.608 2.148 99.712 181.848 ;
     RECT  99.712 2.304 99.785 181.848 ;
     RECT  99.785 2.418 99.904 181.848 ;
     RECT  99.904 4.512 100.037 4.584 ;
     RECT  99.904 17.568 100.163 17.592 ;
     RECT  99.904 26.16 100.163 26.184 ;
     RECT  99.904 19.632 100.181 20.952 ;
     RECT  99.904 180.624 100.259 180.648 ;
     RECT  99.904 181.824 100.357 181.848 ;
     RECT  100.357 181.824 100.441 182.376 ;
     RECT  99.904 23.136 100.636 23.16 ;
     RECT  99.251 1.152 100.865 1.176 ;
     RECT  100.885 28.944 100.973 28.968 ;
     RECT  100.885 31.968 100.973 31.992 ;
     RECT  99.904 2.784 101.045 2.808 ;
     RECT  101.036 179.856 101.123 179.88 ;
     RECT  101.221 5.616 101.305 5.64 ;
     RECT  100.037 4.56 101.357 4.584 ;
     RECT  101.221 2.88 101.513 2.904 ;
     RECT  101.357 3.984 102.133 4.584 ;
     RECT  102.14 16.416 102.227 16.44 ;
     RECT  102.133 3.408 102.233 4.584 ;
     RECT  102.277 29.424 102.325 29.448 ;
     RECT  100.181 19.632 102.332 20.184 ;
     RECT  102.325 29.232 102.377 29.448 ;
     RECT  102.377 29.232 102.412 29.256 ;
     RECT  102.373 23.808 102.46 23.832 ;
     RECT  102.193 179.472 102.561 179.496 ;
     RECT  100.441 181.824 102.561 181.848 ;
     RECT  102.561 179.472 102.611 180.024 ;
     RECT  102.233 3.408 102.613 4.008 ;
     RECT  102.332 19.632 102.613 20.232 ;
     RECT  102.613 3.216 102.659 4.008 ;
     RECT  102.613 19.632 102.661 21.144 ;
     RECT  102.611 180 102.665 180.024 ;
     RECT  102.561 181.248 102.665 181.848 ;
     RECT  102.659 3.216 102.701 3.48 ;
     RECT  100.069 0.096 102.737 0.12 ;
     RECT  102.661 19.632 102.745 21.624 ;
     RECT  102.701 3.216 102.997 3.432 ;
     RECT  103.004 180.048 103.091 180.072 ;
     RECT  102.745 19.632 103.139 21.144 ;
     RECT  102.769 5.136 103.205 5.16 ;
     RECT  102.997 2.88 103.385 3.432 ;
     RECT  102.524 1.152 103.745 1.176 ;
     RECT  103.525 4.56 103.763 4.872 ;
     RECT  102.665 181.824 103.907 181.848 ;
     RECT  103.385 2.88 103.921 2.952 ;
     RECT  103.763 4.56 103.957 4.68 ;
     RECT  104.252 182.352 104.339 182.424 ;
     RECT  103.921 2.832 104.389 2.952 ;
     RECT  103.957 3.984 104.389 4.68 ;
     RECT  103.957 0.096 104.573 0.12 ;
     RECT  104.389 2.832 104.821 4.68 ;
     RECT  104.821 2.832 104.869 4.728 ;
     RECT  104.869 2.832 105.008 5.208 ;
     RECT  103.957 10.848 105.008 10.872 ;
     RECT  104.425 18.624 105.008 18.648 ;
     RECT  103.139 19.632 105.008 20.184 ;
     RECT  104.869 23.856 105.008 23.88 ;
     RECT  104.293 180.144 105.008 180.168 ;
     RECT  104.339 182.352 105.008 182.376 ;
     RECT  105.008 2.148 105.112 182.376 ;
     RECT  105.112 2.418 105.304 181.182 ;
     RECT  105.304 4.656 105.329 4.728 ;
     RECT  105.253 0.144 105.443 0.168 ;
     RECT  105.304 23.856 105.443 23.88 ;
     RECT  105.304 19.632 105.581 20.328 ;
     RECT  105.304 16.368 106.057 16.392 ;
     RECT  105.304 28.848 106.115 28.872 ;
     RECT  105.173 1.152 106.117 1.176 ;
     RECT  106.117 0.576 106.229 1.176 ;
     RECT  105.304 31.92 106.273 31.944 ;
     RECT  105.112 182.352 106.501 182.376 ;
     RECT  105.304 2.64 106.517 3.432 ;
     RECT  105.329 4.656 106.549 4.68 ;
     RECT  106.229 1.152 106.553 1.176 ;
     RECT  106.405 179.184 106.585 179.208 ;
     RECT  106.585 179.184 106.669 179.832 ;
     RECT  106.597 23.76 106.697 23.784 ;
     RECT  106.501 181.824 106.979 182.376 ;
     RECT  106.549 4.56 107.053 4.68 ;
     RECT  106.517 2.88 107.201 3.432 ;
     RECT  106.669 179.184 107.309 179.208 ;
     RECT  107.053 4.56 107.705 5.112 ;
     RECT  107.557 34.272 107.747 34.296 ;
     RECT  107.708 22.752 107.795 22.776 ;
     RECT  107.705 4.56 107.813 4.584 ;
     RECT  106.501 0.144 107.845 0.168 ;
     RECT  106.979 181.824 108.236 181.848 ;
     RECT  108.236 181.824 108.323 182.424 ;
     RECT  108.325 27.072 108.412 27.096 ;
     RECT  107.845 0.144 108.569 0.6 ;
     RECT  108.569 0.144 108.605 0.168 ;
     RECT  108.709 2.976 108.757 3 ;
     RECT  108.757 2.88 108.893 3 ;
     RECT  108.853 179.52 108.94 179.544 ;
     RECT  108.893 2.88 109.145 2.904 ;
     RECT  109.169 1.152 109.253 1.176 ;
     RECT  105.581 19.632 109.537 20.184 ;
     RECT  109.565 0.24 109.621 0.312 ;
     RECT  109.621 0.144 110.261 0.312 ;
     RECT  108.323 181.824 110.365 181.848 ;
     RECT  110.293 3.024 110.408 3.096 ;
     RECT  109.141 4.56 110.408 4.584 ;
     RECT  109.957 5.856 110.408 5.88 ;
     RECT  110.293 10.56 110.408 11.016 ;
     RECT  109.628 17.856 110.408 17.88 ;
     RECT  109.537 19.632 110.408 21.144 ;
     RECT  110.005 25.584 110.408 25.608 ;
     RECT  109.861 28.416 110.408 28.44 ;
     RECT  109.532 31.536 110.408 31.56 ;
     RECT  110.293 33.6 110.408 33.624 ;
     RECT  110.005 179.184 110.408 179.208 ;
     RECT  110.365 181.824 110.408 182.184 ;
     RECT  110.408 2.148 110.512 182.184 ;
     RECT  110.512 2.418 110.531 182.184 ;
     RECT  110.531 2.418 110.704 181.848 ;
     RECT  110.704 3.072 110.801 3.096 ;
     RECT  110.704 33.6 110.819 33.624 ;
     RECT  110.704 10.512 110.845 10.536 ;
     RECT  110.704 4.56 110.909 6.12 ;
     RECT  110.365 1.152 110.981 1.176 ;
     RECT  110.909 4.56 111.197 5.448 ;
     RECT  110.261 0.144 111.229 0.168 ;
     RECT  110.704 23.376 111.457 23.4 ;
     RECT  111.197 5.424 111.635 5.448 ;
     RECT  111.733 3.312 111.769 3.336 ;
     RECT  110.704 179.232 111.809 179.256 ;
     RECT  111.829 31.248 111.916 31.272 ;
     RECT  111.229 0.144 112.021 0.6 ;
     RECT  111.98 16.8 112.067 16.824 ;
     RECT  111.769 3.312 112.117 4.008 ;
     RECT  112.021 0.096 112.163 0.6 ;
     RECT  112.117 2.88 112.172 4.008 ;
     RECT  112.172 2.448 112.259 4.008 ;
     RECT  112.316 27.744 112.403 27.768 ;
     RECT  112.163 0.144 112.625 0.6 ;
     RECT  112.259 2.88 112.652 4.008 ;
     RECT  112.625 0.144 112.709 1.176 ;
     RECT  112.652 2.88 112.739 4.824 ;
     RECT  112.837 33.552 112.925 33.576 ;
     RECT  112.709 0.144 113.027 0.552 ;
     RECT  112.549 6.768 113.033 6.792 ;
     RECT  113.027 0.144 113.125 0.168 ;
     RECT  112.739 2.88 113.357 3.96 ;
     RECT  113.269 16.224 113.357 16.248 ;
     RECT  113.101 24.864 113.411 24.888 ;
     RECT  113.357 2.88 113.413 3.336 ;
     RECT  110.704 19.632 113.413 20.184 ;
     RECT  113.413 19.632 113.5 21 ;
     RECT  113.365 29.424 113.564 29.448 ;
     RECT  113.564 29.376 113.651 29.448 ;
     RECT  113.413 2.4 113.681 3.336 ;
     RECT  113.651 29.424 113.843 29.448 ;
     RECT  110.704 181.824 113.893 181.848 ;
     RECT  113.749 31.392 113.897 31.416 ;
     RECT  113.893 181.824 114.035 182.424 ;
     RECT  113.989 32.352 114.076 32.376 ;
     RECT  113.125 0.096 114.277 0.168 ;
     RECT  114.277 0.096 114.389 0.6 ;
     RECT  114.389 0.096 114.473 1.176 ;
     RECT  113.681 3.312 114.505 3.336 ;
     RECT  114.505 3.312 114.853 3.432 ;
     RECT  114.473 0.096 114.941 0.6 ;
     RECT  114.853 2.88 115.141 3.432 ;
     RECT  115.141 2.784 115.573 3.432 ;
     RECT  114.035 181.824 115.621 181.848 ;
     RECT  115.621 181.824 115.763 182.424 ;
     RECT  115.573 2.784 115.808 4.008 ;
     RECT  113.5 19.632 115.808 20.184 ;
     RECT  115.141 23.712 115.808 23.736 ;
     RECT  115.369 27.312 115.808 27.336 ;
     RECT  115.436 32.448 115.808 32.472 ;
     RECT  115.153 179.664 115.808 179.688 ;
     RECT  115.763 181.824 115.808 181.848 ;
     RECT  115.808 2.148 116.005 181.848 ;
     RECT  116.005 1.728 116.104 181.848 ;
     RECT  116.104 1.728 116.165 1.752 ;
     RECT  116.104 19.104 116.243 21.144 ;
     RECT  116.189 1.152 116.273 1.176 ;
     RECT  116.104 16.416 116.381 16.44 ;
     RECT  116.243 19.104 116.387 20.184 ;
     RECT  116.104 29.472 116.435 29.496 ;
     RECT  116.104 179.568 116.669 180.12 ;
     RECT  116.387 19.344 116.813 20.184 ;
     RECT  114.941 0.096 116.869 0.12 ;
     RECT  116.104 181.824 116.989 181.848 ;
     RECT  116.104 33.024 117.107 33.048 ;
     RECT  116.104 3.312 117.269 3.576 ;
     RECT  117.269 3.312 117.353 4.008 ;
     RECT  116.669 180.096 117.596 180.12 ;
     RECT  116.989 181.824 117.596 182.376 ;
     RECT  117.596 180.096 117.683 182.376 ;
     RECT  116.869 0.096 117.749 0.6 ;
     RECT  117.685 21.648 117.772 21.672 ;
     RECT  117.749 0.528 117.917 0.6 ;
     RECT  117.601 25.296 117.971 25.32 ;
     RECT  117.683 181.824 117.971 182.376 ;
     RECT  117.917 0.528 118.001 1.176 ;
     RECT  118.069 28.128 118.156 28.152 ;
     RECT  118.001 0.528 118.211 0.552 ;
     RECT  118.357 2.304 118.597 2.328 ;
     RECT  117.353 3.312 118.597 3.336 ;
     RECT  118.597 18 118.684 18.024 ;
     RECT  117.961 4.896 118.757 4.92 ;
     RECT  118.681 33.696 118.765 33.72 ;
     RECT  118.597 2.304 118.829 3.336 ;
     RECT  118.829 2.304 118.973 2.328 ;
     RECT  118.829 3.312 118.997 3.336 ;
     RECT  118.997 3.312 119.081 4.008 ;
     RECT  119.149 21.6 119.233 21.624 ;
     RECT  116.813 19.632 119.297 20.184 ;
     RECT  119.125 25.296 119.405 25.32 ;
     RECT  118.837 0.096 119.42 0.12 ;
     RECT  119.42 0.096 119.507 0.552 ;
     RECT  117.971 181.824 119.581 181.848 ;
     RECT  119.544 17.616 119.692 17.64 ;
     RECT  119.581 181.824 119.747 182.424 ;
     RECT  119.507 0.096 119.945 0.168 ;
     RECT  120.037 33.744 120.125 33.768 ;
     RECT  119.081 3.312 120.133 3.432 ;
     RECT  119.297 20.16 120.197 20.184 ;
     RECT  119.945 0.096 120.413 0.12 ;
     RECT  120.757 28.944 120.769 28.968 ;
     RECT  120.565 1.152 120.845 1.176 ;
     RECT  120.476 21.552 120.949 21.576 ;
     RECT  120.757 4.56 120.997 4.584 ;
     RECT  120.481 33.552 121.093 33.576 ;
     RECT  117.683 180.096 121.093 180.12 ;
     RECT  120.133 2.88 121.208 3.432 ;
     RECT  120.997 4.56 121.208 4.68 ;
     RECT  120.949 21.552 121.208 21.624 ;
     RECT  120.769 28.944 121.208 29.064 ;
     RECT  121.093 33.024 121.208 33.576 ;
     RECT  121.093 179.472 121.208 180.12 ;
     RECT  119.747 181.824 121.208 182.376 ;
     RECT  120.997 0.576 121.235 0.696 ;
     RECT  121.208 2.148 121.501 182.376 ;
     RECT  121.501 2.148 121.504 181.848 ;
     RECT  121.235 0.576 121.58 0.6 ;
     RECT  121.504 49.632 121.637 49.656 ;
     RECT  121.504 180.24 121.645 180.744 ;
     RECT  121.58 0.48 121.667 0.6 ;
     RECT  121.667 0.576 121.673 0.6 ;
     RECT  121.504 4.656 121.709 4.68 ;
     RECT  121.504 28.704 121.997 28.728 ;
     RECT  121.504 2.148 122.053 3.336 ;
     RECT  122.053 1.728 122.249 3.336 ;
     RECT  121.504 23.04 122.339 23.064 ;
     RECT  121.645 180.72 122.531 180.744 ;
     RECT  122.249 2.304 122.609 3.336 ;
     RECT  122.497 179.616 122.645 179.64 ;
     RECT  122.497 11.952 122.681 11.976 ;
     RECT  122.533 50.112 122.681 50.136 ;
     RECT  122.533 28.992 122.933 29.016 ;
     RECT  122.485 4.56 123.149 4.584 ;
     RECT  122.773 0.576 123.509 0.6 ;
     RECT  123.5 28.8 123.587 28.824 ;
     RECT  122.609 2.832 123.637 3.336 ;
     RECT  121.504 181.824 123.637 181.848 ;
     RECT  123.637 181.248 123.725 181.848 ;
     RECT  123.637 2.832 123.749 3.432 ;
     RECT  123.649 4.512 123.749 4.536 ;
     RECT  123.253 179.52 123.797 179.544 ;
     RECT  123.757 30.816 123.841 30.84 ;
     RECT  123.781 1.152 124.013 1.176 ;
     RECT  123.829 6.864 124.049 6.888 ;
     RECT  123.98 109.872 124.067 109.896 ;
     RECT  123.749 2.832 124.081 4.536 ;
     RECT  124.076 23.76 124.117 23.784 ;
     RECT  124.117 22.8 124.163 23.784 ;
     RECT  124.163 22.8 124.204 22.824 ;
     RECT  124.081 2.736 124.213 4.536 ;
     RECT  124.22 178.608 124.307 178.632 ;
     RECT  124.261 180.144 124.373 180.168 ;
     RECT  124.009 5.568 124.589 5.592 ;
     RECT  124.645 0.576 124.733 0.6 ;
     RECT  124.297 33.696 124.835 33.72 ;
     RECT  124.213 2.736 124.837 4.584 ;
     RECT  124.837 109.68 124.921 109.704 ;
     RECT  123.725 181.824 124.981 181.848 ;
     RECT  124.873 0.048 125.027 0.552 ;
     RECT  124.837 2.736 125.129 5.208 ;
     RECT  124.981 181.824 125.197 182.376 ;
     RECT  125.129 2.736 125.273 5.16 ;
     RECT  125.305 28.416 125.417 28.44 ;
     RECT  125.372 178.608 125.459 178.632 ;
     RECT  125.197 181.824 125.5 182.664 ;
     RECT  125.521 25.008 125.605 25.032 ;
     RECT  125.413 1.728 125.813 1.752 ;
     RECT  125.708 93.936 125.981 93.96 ;
     RECT  125.027 0.048 126.277 0.072 ;
     RECT  125.989 133.392 126.421 133.416 ;
     RECT  126.428 6.768 126.449 6.792 ;
     RECT  126.277 0.048 126.565 0.168 ;
     RECT  125.273 2.736 126.608 4.008 ;
     RECT  125.273 5.136 126.608 5.16 ;
     RECT  126.449 6.288 126.608 6.792 ;
     RECT  125.797 28.272 126.608 28.296 ;
     RECT  125.653 31.872 126.608 31.896 ;
     RECT  125.981 93.744 126.608 93.96 ;
     RECT  126.421 133.392 126.608 133.944 ;
     RECT  126.469 136.272 126.608 136.296 ;
     RECT  126.428 150 126.608 150.024 ;
     RECT  125.5 182.352 126.608 182.664 ;
     RECT  126.565 0.048 126.709 0.552 ;
     RECT  126.709 0.048 126.745 0.6 ;
     RECT  126.608 2.148 126.796 182.664 ;
     RECT  126.796 2.148 126.904 181.182 ;
     RECT  126.904 6.384 127.001 6.744 ;
     RECT  127.001 6.528 127.091 6.744 ;
     RECT  126.796 182.4 127.105 182.664 ;
     RECT  127.091 6.528 127.109 6.552 ;
     RECT  126.904 2.148 127.132 3.432 ;
     RECT  127.105 182.4 127.187 183 ;
     RECT  127.187 182.448 127.285 183 ;
     RECT  127.132 2.148 127.289 2.856 ;
     RECT  126.745 0.048 127.573 1.128 ;
     RECT  127.573 0.048 128.099 1.752 ;
     RECT  127.289 2.832 128.147 2.856 ;
     RECT  128.099 0.048 128.435 1.176 ;
     RECT  127.285 182.448 128.963 183.048 ;
     RECT  128.435 0.144 128.989 1.176 ;
     RECT  128.989 0.528 129.395 1.176 ;
     RECT  128.963 182.448 129.395 182.472 ;
     RECT  129.397 88.848 129.409 88.872 ;
     RECT  129.395 1.152 129.443 1.176 ;
     RECT  129.409 88.752 129.484 88.872 ;
     RECT  129.484 88.752 129.564 88.776 ;
     RECT  128.797 94.224 129.564 94.248 ;
     RECT  128.797 126.672 129.564 126.696 ;
     RECT  126.904 139.968 129.564 139.992 ;
     RECT  126.904 153.312 129.564 153.336 ;
    LAYER M5 ;
     RECT  0.192 0.016 129.432 0.179 ;
     RECT  0.192 0.179 89.784 0.275 ;
     RECT  91.056 0.179 113.016 0.323 ;
     RECT  0.192 0.275 40.248 0.563 ;
     RECT  91.056 0.323 109.224 0.563 ;
     RECT  110.304 0.323 113.016 0.563 ;
     RECT  114.288 0.179 129.432 0.563 ;
     RECT  0.192 0.563 40.104 0.611 ;
     RECT  41.52 0.275 89.784 0.611 ;
     RECT  92.784 0.563 109.224 0.611 ;
     RECT  110.304 0.563 112.68 0.611 ;
     RECT  114.288 0.563 119.064 0.611 ;
     RECT  63.936 0.611 80.76 0.707 ;
     RECT  16.464 0.611 20.952 1.139 ;
     RECT  120.144 0.563 129.432 1.139 ;
     RECT  0.192 0.611 12.984 1.187 ;
     RECT  14.688 0.611 15.288 1.187 ;
     RECT  16.464 1.139 17.448 1.187 ;
     RECT  22.176 0.611 40.104 1.187 ;
     RECT  43.248 0.611 55.752 1.187 ;
     RECT  81.936 0.611 85.944 1.187 ;
     RECT  91.056 0.563 91.608 1.187 ;
     RECT  92.784 0.611 107.448 1.187 ;
     RECT  108.72 0.611 109.224 1.187 ;
     RECT  110.304 0.611 110.952 1.187 ;
     RECT  112.032 0.611 112.68 1.187 ;
     RECT  114.432 0.611 116.232 1.187 ;
     RECT  117.312 0.611 119.064 1.187 ;
     RECT  129.408 1.139 129.432 1.187 ;
     RECT  32.928 1.187 40.104 1.283 ;
     RECT  39.792 1.283 40.104 2.137 ;
     RECT  55.104 1.187 55.752 2.137 ;
     RECT  56.88 0.611 57.48 2.137 ;
     RECT  64.368 0.707 80.76 2.291 ;
     RECT  30.528 1.187 31.224 2.339 ;
     RECT  32.928 1.283 38.568 2.339 ;
     RECT  58.656 0.611 62.664 2.339 ;
     RECT  69.408 2.291 80.76 2.339 ;
     RECT  87.168 0.611 89.784 2.339 ;
     RECT  92.784 1.187 95.112 2.339 ;
     RECT  96.24 1.187 107.448 2.339 ;
     RECT  118.368 1.187 119.064 2.339 ;
     RECT  120.144 1.139 128.136 2.339 ;
     RECT  112.032 1.187 112.152 2.357 ;
     RECT  13.2 2.137 13.32 2.407 ;
     RECT  25.584 1.187 29.52 2.407 ;
     RECT  39.792 2.137 40.32 2.407 ;
     RECT  43.248 1.187 45.72 2.407 ;
     RECT  46.704 1.187 52.344 2.407 ;
     RECT  114.864 1.187 116.04 2.407 ;
     RECT  113.424 2.351 113.448 2.435 ;
     RECT  112.032 2.357 112.248 2.483 ;
     RECT  0.192 1.187 9 2.677 ;
     RECT  10.128 1.187 11.832 2.677 ;
     RECT  128.112 2.339 128.136 2.867 ;
     RECT  0.192 2.677 11.832 2.915 ;
     RECT  25.584 2.407 29.712 2.915 ;
     RECT  36.384 2.339 38.568 2.915 ;
     RECT  41.52 0.611 42.024 2.915 ;
     RECT  53.376 1.187 54.072 2.915 ;
     RECT  55.104 2.137 57.48 2.915 ;
     RECT  58.656 2.339 59.64 2.915 ;
     RECT  71.232 2.339 80.76 2.915 ;
     RECT  92.784 2.339 94.968 2.915 ;
     RECT  97.728 2.339 107.448 2.915 ;
     RECT  112.032 2.483 112.152 2.915 ;
     RECT  114.864 2.407 116.112 2.915 ;
     RECT  118.608 2.339 119.064 2.915 ;
     RECT  120.144 2.339 126.912 2.915 ;
     RECT  4.512 2.915 6.696 2.963 ;
     RECT  16.896 1.187 17.448 2.963 ;
     RECT  30.768 2.339 31.224 2.963 ;
     RECT  75.12 2.915 80.76 2.963 ;
     RECT  18.48 1.139 20.952 2.965 ;
     RECT  108.72 1.187 109.176 3.011 ;
     RECT  75.12 2.963 75.864 3.059 ;
     RECT  110.304 1.187 110.904 3.059 ;
     RECT  43.248 2.407 52.344 3.107 ;
     RECT  76.848 2.963 80.76 3.283 ;
     RECT  81.936 1.187 85.464 3.283 ;
     RECT  48.432 3.107 52.344 3.301 ;
     RECT  119.04 2.915 119.064 3.301 ;
     RECT  120.144 2.915 121.512 3.301 ;
     RECT  122.496 2.915 126.912 3.301 ;
     RECT  119.04 3.301 121.512 3.385 ;
     RECT  7.8 2.915 8.424 3.443 ;
     RECT  9.552 2.915 11.832 3.443 ;
     RECT  16.992 2.963 17.448 3.443 ;
     RECT  18.48 2.965 21 3.443 ;
     RECT  22.176 1.187 24.456 3.443 ;
     RECT  25.584 2.915 26.136 3.443 ;
     RECT  27.744 2.915 29.712 3.443 ;
     RECT  32.928 2.339 35.352 3.443 ;
     RECT  36.384 2.915 36.408 3.443 ;
     RECT  37.536 2.915 38.568 3.443 ;
     RECT  43.248 3.107 47.16 3.443 ;
     RECT  59.184 2.915 59.64 3.443 ;
     RECT  75.12 3.059 75.576 3.443 ;
     RECT  76.848 3.283 85.464 3.443 ;
     RECT  97.92 2.915 107.448 3.443 ;
     RECT  115.152 2.915 116.112 3.443 ;
     RECT  122.496 3.301 127.08 3.443 ;
     RECT  10.128 3.443 11.832 3.491 ;
     RECT  115.584 3.443 116.112 3.541 ;
     RECT  117.312 1.187 117.336 3.541 ;
     RECT  115.584 3.541 117.336 3.627 ;
     RECT  13.2 2.407 13.512 3.685 ;
     RECT  54.048 2.915 54.072 3.733 ;
     RECT  55.104 2.915 57.384 3.733 ;
     RECT  15.264 1.187 15.288 3.795 ;
     RECT  14.88 3.795 15.288 3.883 ;
     RECT  4.512 2.963 5.112 3.913 ;
     RECT  122.496 3.443 126.912 3.923 ;
     RECT  71.232 2.915 73.416 3.925 ;
     RECT  71.232 3.925 73.992 4.011 ;
     RECT  0.192 2.915 3.288 4.019 ;
     RECT  4.512 3.913 4.968 4.019 ;
     RECT  6.24 2.963 6.696 4.019 ;
     RECT  10.56 3.491 11.832 4.019 ;
     RECT  15.264 3.883 15.288 4.019 ;
     RECT  25.584 3.443 26.04 4.019 ;
     RECT  29.04 3.443 29.712 4.019 ;
     RECT  38.112 3.443 38.568 4.019 ;
     RECT  41.52 2.915 41.544 4.019 ;
     RECT  44.976 3.443 47.16 4.019 ;
     RECT  71.232 4.011 73.416 4.019 ;
     RECT  77.28 3.443 85.464 4.019 ;
     RECT  91.056 1.187 91.512 4.019 ;
     RECT  96.24 2.339 96.696 4.019 ;
     RECT  97.92 3.443 97.944 4.019 ;
     RECT  99.456 3.443 103.56 4.019 ;
     RECT  112.032 2.915 112.056 4.019 ;
     RECT  115.584 3.627 116.112 4.019 ;
     RECT  117.312 3.627 117.336 4.019 ;
     RECT  119.04 3.385 119.064 4.019 ;
     RECT  125.856 3.923 126.912 4.019 ;
     RECT  30.864 2.963 31.224 4.067 ;
     RECT  80.304 4.019 85.464 4.115 ;
     RECT  13.2 3.685 13.608 4.259 ;
     RECT  34.512 3.443 35.352 4.355 ;
     RECT  54.048 3.733 57.384 4.355 ;
     RECT  91.152 4.019 91.512 4.403 ;
     RECT  48.432 3.301 53.064 4.405 ;
     RECT  55.728 4.355 57.384 4.451 ;
     RECT  45.6 4.019 46.728 4.489 ;
     RECT  47.904 4.405 53.064 4.489 ;
     RECT  87.168 2.339 87.624 4.501 ;
     RECT  88.656 2.339 89.784 4.501 ;
     RECT  4.944 4.019 4.968 4.595 ;
     RECT  6.24 4.019 6.264 4.595 ;
     RECT  10.56 4.019 11.4 4.595 ;
     RECT  18.6 3.443 21 4.595 ;
     RECT  22.176 3.443 24.312 4.595 ;
     RECT  25.584 4.019 25.608 4.595 ;
     RECT  27.744 3.443 27.768 4.595 ;
     RECT  30.864 4.067 30.888 4.595 ;
     RECT  32.928 3.443 33.384 4.595 ;
     RECT  34.512 4.355 35.256 4.595 ;
     RECT  39.792 2.407 40.512 4.595 ;
     RECT  43.68 3.443 43.704 4.595 ;
     RECT  48.432 4.489 53.064 4.595 ;
     RECT  54.048 4.355 54.072 4.595 ;
     RECT  55.728 4.451 56.712 4.595 ;
     RECT  59.184 3.443 59.208 4.595 ;
     RECT  71.664 4.019 73.416 4.595 ;
     RECT  75.12 3.443 75.144 4.595 ;
     RECT  77.28 4.019 79.032 4.595 ;
     RECT  80.304 4.115 80.76 4.595 ;
     RECT  82.032 4.115 85.464 4.595 ;
     RECT  87.168 4.501 89.784 4.595 ;
     RECT  91.488 4.403 91.512 4.595 ;
     RECT  92.784 2.915 92.808 4.595 ;
     RECT  99.6 4.019 100.536 4.595 ;
     RECT  101.808 4.019 101.832 4.595 ;
     RECT  103.536 4.019 103.56 4.595 ;
     RECT  106.56 3.443 107.448 4.595 ;
     RECT  109.152 3.011 109.176 4.595 ;
     RECT  120.768 3.385 121.512 4.595 ;
     RECT  122.496 3.923 124.584 4.595 ;
     RECT  38.544 4.019 38.568 4.643 ;
     RECT  20.448 4.595 20.472 4.691 ;
     RECT  77.28 4.595 78.312 4.691 ;
     RECT  121.008 4.595 121.512 4.691 ;
     RECT  82.032 4.595 84.216 4.715 ;
     RECT  82.032 4.715 82.056 4.729 ;
     RECT  17.424 3.443 17.448 4.739 ;
     RECT  104.832 3.443 105.312 4.739 ;
     RECT  98.16 4.755 98.184 4.843 ;
     RECT  87.504 4.595 87.528 4.931 ;
     RECT  94.2 2.915 94.968 5.027 ;
     RECT  48.96 4.595 51.312 5.075 ;
     RECT  110.4 3.059 110.904 5.109 ;
     RECT  17.52 5.045 17.544 5.133 ;
     RECT  103.728 4.837 103.752 5.163 ;
     RECT  112.704 4.789 112.728 5.163 ;
     RECT  0.192 4.019 3.24 5.171 ;
     RECT  34.512 4.595 35.112 5.171 ;
     RECT  85.44 4.595 85.464 5.171 ;
     RECT  104.88 4.739 105.312 5.219 ;
     RECT  83.4 4.715 84.216 5.227 ;
     RECT  124.848 5.173 124.872 5.257 ;
     RECT  64.368 2.291 68.28 5.419 ;
     RECT  110.4 5.109 111.624 5.459 ;
     RECT  30.816 5.413 30.84 5.497 ;
     RECT  52.32 4.595 52.344 5.587 ;
     RECT  18.6 4.595 19.032 5.603 ;
     RECT  60.912 2.339 62.664 5.605 ;
     RECT  94.2 5.027 94.872 5.605 ;
     RECT  48.96 5.075 49.944 5.621 ;
     RECT  31.248 5.587 31.272 5.675 ;
     RECT  48.624 5.621 49.944 5.675 ;
     RECT  52.32 5.587 53.208 5.675 ;
     RECT  93.984 5.605 94.872 5.675 ;
     RECT  60.912 5.605 63.048 5.689 ;
     RECT  81.648 5.605 81.672 5.689 ;
     RECT  93.984 5.675 94.512 5.689 ;
     RECT  101.232 5.605 101.256 5.689 ;
     RECT  27.312 5.653 27.336 5.739 ;
     RECT  26.208 5.663 26.232 5.747 ;
     RECT  48.624 5.675 48.648 5.747 ;
     RECT  88.512 4.595 89.544 5.747 ;
     RECT  9.216 5.685 9.24 5.773 ;
     RECT  110.4 5.459 110.712 5.845 ;
     RECT  109.968 5.845 110.712 5.931 ;
     RECT  78 4.691 78.312 6.197 ;
     RECT  69.408 2.339 69.96 6.239 ;
     RECT  126.6 4.019 126.912 6.277 ;
     RECT  0.192 5.171 2.712 6.323 ;
     RECT  64.368 5.419 65.256 6.323 ;
     RECT  69.408 6.239 70.68 6.323 ;
     RECT  126.48 6.277 126.912 6.517 ;
     RECT  25.536 6.483 25.56 6.571 ;
     RECT  38.832 6.483 38.856 6.571 ;
     RECT  97.632 6.483 97.656 6.571 ;
     RECT  58.128 6.517 58.152 6.601 ;
     RECT  126.48 6.517 127.08 6.755 ;
     RECT  52.32 5.675 52.344 6.803 ;
     RECT  126.48 6.755 126.912 6.803 ;
     RECT  112.56 6.739 113.016 6.827 ;
     RECT  64.368 6.323 64.824 6.851 ;
     RECT  51 5.075 51.312 6.853 ;
     RECT  69.936 6.323 69.96 6.899 ;
     RECT  98.016 6.837 98.04 6.925 ;
     RECT  50.736 6.853 51.312 7.091 ;
     RECT  79.824 7.029 79.848 7.117 ;
     RECT  78 6.197 78.696 7.147 ;
     RECT  49.056 7.391 49.08 7.475 ;
     RECT  0.192 6.323 1.08 7.523 ;
     RECT  49.152 7.797 49.176 8.003 ;
     RECT  66.528 5.419 68.28 8.579 ;
     RECT  49.104 8.437 49.128 8.747 ;
     RECT  60.912 5.689 62.664 9.107 ;
     RECT  64.8 6.851 64.824 9.491 ;
     RECT  81.888 10.293 81.912 10.451 ;
     RECT  110.4 5.931 110.712 10.463 ;
     RECT  110.4 10.463 110.808 10.547 ;
     RECT  110.4 10.547 110.712 10.549 ;
     RECT  81.936 10.501 81.96 10.603 ;
     RECT  60.912 9.107 62.112 10.883 ;
     RECT  71.664 4.595 72.912 10.883 ;
     RECT  0.192 7.523 0.696 10.931 ;
     RECT  66.528 8.579 67.512 11.039 ;
     RECT  110.304 10.549 110.712 11.051 ;
     RECT  66.144 11.039 67.512 11.123 ;
     RECT  66.432 11.123 67.512 11.341 ;
     RECT  18.6 5.603 18.912 14.053 ;
     RECT  18.192 14.053 18.912 14.281 ;
     RECT  94.2 5.689 94.512 15.397 ;
     RECT  94.2 15.397 94.872 15.481 ;
     RECT  85.488 15.445 85.512 15.531 ;
     RECT  18.6 14.281 18.912 15.955 ;
     RECT  61.8 10.883 62.112 15.955 ;
     RECT  17.856 15.955 18.912 16.043 ;
     RECT  61.488 15.955 62.112 16.043 ;
     RECT  72.6 10.883 72.912 16.083 ;
     RECT  72.6 16.083 73.272 16.171 ;
     RECT  113.28 16.181 113.304 16.269 ;
     RECT  105 5.219 105.312 16.309 ;
     RECT  105 16.309 106.008 16.403 ;
     RECT  83.4 5.227 83.712 16.405 ;
     RECT  115.8 4.019 116.112 16.405 ;
     RECT  56.4 4.595 56.712 16.467 ;
     RECT  82.512 16.405 83.712 16.491 ;
     RECT  102.192 16.405 102.216 16.491 ;
     RECT  115.8 16.405 116.328 16.491 ;
     RECT  47.424 16.467 47.448 16.555 ;
     RECT  48.528 16.467 48.552 16.555 ;
     RECT  54.672 16.501 54.696 16.585 ;
     RECT  60.288 16.501 60.312 16.585 ;
     RECT  51 7.091 51.312 16.629 ;
     RECT  31.008 16.559 31.032 16.643 ;
     RECT  63.84 16.559 63.864 16.643 ;
     RECT  98.112 16.559 98.136 16.643 ;
     RECT  56.304 16.467 56.712 16.683 ;
     RECT  50.352 16.629 51.312 16.717 ;
     RECT  112.032 16.757 112.056 16.845 ;
     RECT  18.6 16.043 18.912 16.991 ;
     RECT  78 7.147 78.312 16.991 ;
     RECT  80.64 16.915 80.664 17.003 ;
     RECT  67.2 11.341 67.512 17.013 ;
     RECT  25.68 16.981 25.704 17.067 ;
     RECT  68.832 16.933 68.856 17.067 ;
     RECT  18.6 16.991 19.032 17.075 ;
     RECT  37.104 16.991 37.128 17.075 ;
     RECT  58.128 16.629 58.152 17.075 ;
     RECT  77.904 16.991 78.312 17.075 ;
     RECT  39.072 17.013 39.096 17.101 ;
     RECT  41.52 17.013 41.544 17.101 ;
     RECT  66.384 17.013 67.512 17.101 ;
     RECT  71.232 17.077 71.256 17.171 ;
     RECT  43.92 17.375 43.944 17.459 ;
     RECT  45.6 4.489 46.104 17.459 ;
     RECT  29.4 4.019 29.712 17.491 ;
     RECT  99.6 4.595 99.912 17.525 ;
     RECT  74.688 17.461 74.712 17.545 ;
     RECT  7.8 3.443 8.112 17.557 ;
     RECT  34.8 5.171 35.112 17.567 ;
     RECT  28.512 17.491 29.712 17.579 ;
     RECT  7.8 17.557 8.52 17.605 ;
     RECT  94.2 15.481 94.512 17.605 ;
     RECT  99.6 17.525 100.152 17.613 ;
     RECT  33.84 17.567 35.112 17.651 ;
     RECT  93.504 17.605 94.512 17.653 ;
     RECT  10.752 17.589 10.776 17.677 ;
     RECT  119.616 17.589 119.64 17.677 ;
     RECT  110.4 11.051 110.712 17.781 ;
     RECT  109.68 17.781 110.712 17.891 ;
     RECT  13.2 4.259 13.512 17.893 ;
     RECT  13.2 17.893 14.232 17.977 ;
     RECT  7.8 17.605 9.048 18.027 ;
     RECT  10.848 17.941 10.872 18.027 ;
     RECT  6.768 17.951 6.792 18.035 ;
     RECT  15.264 17.989 15.288 18.091 ;
     RECT  118.608 17.989 118.632 18.091 ;
     RECT  90.624 18.095 90.648 18.101 ;
     RECT  93.504 17.653 94.68 18.155 ;
     RECT  90.528 18.101 90.648 18.179 ;
     RECT  59.952 18.101 59.976 18.189 ;
     RECT  90.528 18.179 90.552 18.189 ;
     RECT  6.288 18.143 6.312 18.227 ;
     RECT  22.224 18.143 22.248 18.227 ;
     RECT  94.2 18.155 94.68 18.275 ;
     RECT  24 4.595 24.312 18.357 ;
     RECT  24 18.357 24.456 18.445 ;
     RECT  13.2 17.977 13.512 18.613 ;
     RECT  105 16.403 105.312 18.613 ;
     RECT  104.448 18.613 105.312 18.697 ;
     RECT  12.48 18.613 13.512 18.851 ;
     RECT  115.8 16.491 116.112 19.093 ;
     RECT  72.6 16.171 72.912 19.333 ;
     RECT  83.4 16.491 83.712 19.333 ;
     RECT  16.32 19.333 16.344 19.563 ;
     RECT  20.736 19.477 20.76 19.563 ;
     RECT  115.8 19.093 116.376 19.563 ;
     RECT  43.344 19.487 43.368 19.571 ;
     RECT  66.048 19.509 66.072 19.597 ;
     RECT  0.24 10.931 0.696 19.667 ;
     RECT  2.4 6.323 2.712 19.669 ;
     RECT  29.4 17.579 29.712 19.669 ;
     RECT  83.28 19.333 83.712 19.691 ;
     RECT  86.64 19.525 86.664 19.691 ;
     RECT  2.4 19.669 3.624 19.755 ;
     RECT  12.624 18.851 13.512 19.755 ;
     RECT  96.96 19.669 96.984 19.755 ;
     RECT  40.2 4.595 40.512 19.836 ;
     RECT  40.2 19.836 40.632 19.861 ;
     RECT  28.224 19.795 28.248 19.883 ;
     RECT  29.4 19.669 29.88 19.883 ;
     RECT  110.4 17.891 110.712 19.893 ;
     RECT  4.08 19.861 4.104 19.947 ;
     RECT  18.6 17.075 18.912 19.957 ;
     RECT  80.064 19.893 80.088 19.981 ;
     RECT  110.4 19.893 111.48 19.981 ;
     RECT  39.888 19.861 40.632 20.003 ;
     RECT  45.6 17.459 45.912 20.005 ;
     RECT  18.048 19.957 18.912 20.051 ;
     RECT  72.6 19.333 73.704 20.053 ;
     RECT  56.4 16.683 56.712 20.085 ;
     RECT  45.6 20.005 46.152 20.089 ;
     RECT  54.768 20.053 54.792 20.139 ;
     RECT  68.928 20.053 68.952 20.139 ;
     RECT  71.952 20.053 73.704 20.139 ;
     RECT  0.672 19.667 0.696 20.195 ;
     RECT  105 18.697 105.312 20.213 ;
     RECT  102.384 20.179 102.408 20.267 ;
     RECT  78 17.075 78.312 20.277 ;
     RECT  79.872 20.197 79.896 20.331 ;
     RECT  105 20.213 105.528 20.339 ;
     RECT  77.904 20.277 78.312 20.341 ;
     RECT  32.88 20.277 32.904 20.365 ;
     RECT  77.904 20.341 78.552 20.365 ;
     RECT  78 20.365 78.552 20.425 ;
     RECT  4.848 20.371 4.968 20.459 ;
     RECT  39.888 20.003 40.512 20.469 ;
     RECT  88.512 5.747 89.112 20.485 ;
     RECT  7.8 18.027 8.112 20.533 ;
     RECT  39.024 20.469 40.512 20.557 ;
     RECT  75.168 20.499 75.192 20.587 ;
     RECT  58.128 20.485 58.152 20.651 ;
     RECT  60.48 20.469 60.504 20.675 ;
     RECT  34.8 17.651 35.112 20.677 ;
     RECT  83.4 19.691 83.712 20.677 ;
     RECT  56.4 20.085 57.144 20.691 ;
     RECT  88.512 20.485 89.544 20.715 ;
     RECT  99.6 17.613 99.912 20.725 ;
     RECT  34.8 20.677 35.208 20.779 ;
     RECT  56.4 20.691 57.192 20.779 ;
     RECT  83.4 20.677 84.072 20.779 ;
     RECT  98.688 20.725 99.912 20.809 ;
     RECT  10.8 20.591 10.824 20.883 ;
     RECT  7.8 20.533 8.616 20.917 ;
     RECT  10.608 20.883 10.824 20.963 ;
     RECT  10.608 20.963 10.632 20.971 ;
     RECT  7.8 20.917 9.096 21.001 ;
     RECT  113.424 20.947 113.448 21.035 ;
     RECT  24 18.445 24.312 21.075 ;
     RECT  115.8 19.563 116.112 21.075 ;
     RECT  4.848 20.459 4.872 21.099 ;
     RECT  110.4 19.981 110.712 21.109 ;
     RECT  102.624 21.075 103.128 21.163 ;
     RECT  115.8 21.075 116.232 21.163 ;
     RECT  102.624 21.163 102.696 21.193 ;
     RECT  109.968 21.109 110.712 21.193 ;
     RECT  49.296 21.109 49.32 21.203 ;
     RECT  26.352 21.109 26.376 21.301 ;
     RECT  26.016 21.301 26.376 21.349 ;
     RECT  121.2 4.691 121.512 21.365 ;
     RECT  24 21.075 24.408 21.419 ;
     RECT  25.92 21.349 26.376 21.433 ;
     RECT  30.816 21.359 30.84 21.443 ;
     RECT  26.352 21.433 26.376 21.456 ;
     RECT  22.272 21.365 22.296 21.611 ;
     RECT  90.816 21.523 90.84 21.611 ;
     RECT  120.528 21.365 121.512 21.611 ;
     RECT  51 16.717 51.312 21.621 ;
     RECT  52.704 21.541 52.728 21.675 ;
     RECT  102.672 21.193 102.696 21.675 ;
     RECT  119.184 21.589 119.208 21.675 ;
     RECT  120.96 21.611 121.512 21.675 ;
     RECT  75.264 21.599 75.288 21.683 ;
     RECT  6 21.651 6.024 21.685 ;
     RECT  50.64 21.621 51.312 21.709 ;
     RECT  96.336 21.621 96.36 21.709 ;
     RECT  117.696 21.365 117.72 21.709 ;
     RECT  6 21.685 6.456 21.739 ;
     RECT  83.4 20.779 83.712 21.743 ;
     RECT  81.504 21.685 81.528 21.779 ;
     RECT  82.512 21.743 83.712 21.781 ;
     RECT  82.32 21.781 83.712 21.827 ;
     RECT  82.32 21.827 82.344 21.867 ;
     RECT  86.352 21.749 86.376 21.971 ;
     RECT  7.8 21.001 8.76 21.995 ;
     RECT  88.512 20.715 89.448 22.197 ;
     RECT  85.44 22.133 85.464 22.221 ;
     RECT  88.032 22.197 89.448 22.251 ;
     RECT  2.4 19.755 2.712 22.261 ;
     RECT  78 20.425 78.312 22.261 ;
     RECT  86.592 22.261 86.616 22.345 ;
     RECT  2.4 22.261 3.672 22.355 ;
     RECT  21.072 22.261 21.096 22.355 ;
     RECT  78 22.261 79.272 22.355 ;
     RECT  17.04 22.291 17.064 22.379 ;
     RECT  88.032 22.251 89.208 22.451 ;
     RECT  72.6 20.139 72.912 22.453 ;
     RECT  56.4 20.779 56.712 22.501 ;
     RECT  21.024 22.405 21.048 22.507 ;
     RECT  11.424 22.453 11.448 22.537 ;
     RECT  72.336 22.453 72.912 22.537 ;
     RECT  45.6 20.089 45.912 22.559 ;
     RECT  56.304 22.501 56.712 22.585 ;
     RECT  44.4 22.549 44.424 22.635 ;
     RECT  45.6 22.559 46.2 22.643 ;
     RECT  36.48 21.637 36.504 22.645 ;
     RECT  38.784 22.549 38.808 22.645 ;
     RECT  72.6 22.537 72.912 22.675 ;
     RECT  74.016 22.453 74.04 22.675 ;
     RECT  6.432 21.739 6.456 22.693 ;
     RECT  94.2 18.275 94.512 22.703 ;
     RECT  36.48 22.645 37.368 22.739 ;
     RECT  65.568 22.645 65.592 22.739 ;
     RECT  72.6 22.675 74.04 22.739 ;
     RECT  42.72 22.709 42.744 22.741 ;
     RECT  39.888 20.557 40.512 22.763 ;
     RECT  72.6 22.739 73.752 22.763 ;
     RECT  80.544 22.389 80.568 22.763 ;
     RECT  6.432 22.693 6.648 22.777 ;
     RECT  93.504 22.703 94.512 22.787 ;
     RECT  123.792 4.595 123.816 22.789 ;
     RECT  2.4 22.355 3.576 22.797 ;
     RECT  88.512 22.451 89.208 22.797 ;
     RECT  91.872 22.709 91.896 22.797 ;
     RECT  107.76 22.709 107.784 22.797 ;
     RECT  38.688 22.645 38.808 22.827 ;
     RECT  42.72 22.741 43.08 22.827 ;
     RECT  6.432 22.777 6.456 22.835 ;
     RECT  36.48 22.739 36.504 22.861 ;
     RECT  38.688 22.827 38.712 22.861 ;
     RECT  42.672 22.837 42.696 22.931 ;
     RECT  59.808 22.837 59.832 22.931 ;
     RECT  69.36 22.837 69.384 22.931 ;
     RECT  121.2 21.675 121.512 22.995 ;
     RECT  121.2 22.995 122.328 23.083 ;
     RECT  99.6 20.809 99.912 23.125 ;
     RECT  7.8 21.995 8.112 23.251 ;
     RECT  12.048 23.173 12.168 23.275 ;
     RECT  13.2 19.755 13.512 23.285 ;
     RECT  7.8 23.251 8.808 23.327 ;
     RECT  34.8 20.779 35.112 23.327 ;
     RECT  110.4 21.193 110.712 23.327 ;
     RECT  7.8 23.327 9.576 23.339 ;
     RECT  12.144 23.275 12.168 23.339 ;
     RECT  9.552 23.339 9.576 23.411 ;
     RECT  34.176 23.327 35.112 23.411 ;
     RECT  54.624 23.327 54.648 23.411 ;
     RECT  110.4 23.327 111.432 23.411 ;
     RECT  99.6 23.125 100.584 23.659 ;
     RECT  98.592 23.605 98.616 23.689 ;
     RECT  115.8 21.163 116.112 23.701 ;
     RECT  105 20.339 105.312 23.733 ;
     RECT  83.4 21.827 83.712 23.763 ;
     RECT  115.152 23.701 116.112 23.787 ;
     RECT  106.608 23.711 106.632 23.795 ;
     RECT  123.792 22.789 124.152 23.795 ;
     RECT  29.4 19.883 29.712 23.797 ;
     RECT  105 23.733 105.432 23.797 ;
     RECT  27.504 23.763 27.528 23.851 ;
     RECT  83.4 23.763 83.832 23.851 ;
     RECT  13.2 23.285 13.656 23.861 ;
     RECT  29.088 23.797 29.712 23.881 ;
     RECT  104.88 23.797 105.432 23.891 ;
     RECT  102.384 23.605 102.408 23.904 ;
     RECT  17.088 23.845 17.112 23.929 ;
     RECT  13.2 23.861 14.28 23.987 ;
     RECT  49.968 23.903 49.992 23.987 ;
     RECT  64.368 23.903 64.392 23.987 ;
     RECT  18.6 20.051 18.912 23.989 ;
     RECT  18.432 23.989 18.912 24.131 ;
     RECT  72.6 22.763 72.912 24.805 ;
     RECT  40.2 22.763 40.512 24.885 ;
     RECT  5.424 24.661 5.448 24.939 ;
     RECT  21.936 24.853 21.96 24.939 ;
     RECT  72.6 24.805 73.656 24.939 ;
     RECT  113.376 24.853 113.4 24.939 ;
     RECT  87.12 24.885 87.144 24.973 ;
     RECT  24 21.419 24.312 24.997 ;
     RECT  40.2 24.885 40.92 24.997 ;
     RECT  94.2 22.787 94.512 24.997 ;
     RECT  2.4 22.797 2.712 25.013 ;
     RECT  3.936 24.709 3.96 25.013 ;
     RECT  42.72 24.885 42.744 25.013 ;
     RECT  2.4 25.013 3.96 25.067 ;
     RECT  97.728 24.979 97.752 25.067 ;
     RECT  23.904 24.997 24.312 25.081 ;
     RECT  40.2 24.997 41.016 25.081 ;
     RECT  94.08 24.997 94.512 25.081 ;
     RECT  125.568 24.997 125.592 25.081 ;
     RECT  85.68 25.013 85.704 25.101 ;
     RECT  2.4 25.067 3.912 25.187 ;
     RECT  3.888 25.187 3.912 25.195 ;
     RECT  42.192 25.013 42.888 25.259 ;
     RECT  117.936 25.247 117.96 25.331 ;
     RECT  119.136 25.247 119.16 25.331 ;
     RECT  60.384 25.299 60.408 25.387 ;
     RECT  20.688 25.397 20.712 25.485 ;
     RECT  34.8 23.411 35.112 25.491 ;
     RECT  82.032 25.429 82.056 25.515 ;
     RECT  18.6 24.131 18.912 25.525 ;
     RECT  110.4 23.411 110.712 25.573 ;
     RECT  34.8 25.491 35.208 25.579 ;
     RECT  38.736 25.491 38.76 25.579 ;
     RECT  48.144 25.477 48.168 25.579 ;
     RECT  15.36 25.525 15.384 25.609 ;
     RECT  67.2 17.101 67.512 25.621 ;
     RECT  11.616 25.555 11.64 25.643 ;
     RECT  42.864 25.259 42.888 25.643 ;
     RECT  110.016 25.573 110.712 25.657 ;
     RECT  56.4 22.585 56.712 25.683 ;
     RECT  67.2 25.621 68.424 25.707 ;
     RECT  18.6 25.525 19.368 25.715 ;
     RECT  44.448 25.205 44.472 25.715 ;
     RECT  56.4 25.683 57.624 25.771 ;
     RECT  78 22.355 78.312 25.861 ;
     RECT  20.352 25.909 20.376 26.003 ;
     RECT  70.368 25.653 70.392 26.003 ;
     RECT  59.424 25.717 59.448 26.027 ;
     RECT  31.92 25.967 31.944 26.051 ;
     RECT  51 21.709 51.312 26.101 ;
     RECT  51 26.101 51.72 26.131 ;
     RECT  99.6 23.659 99.912 26.131 ;
     RECT  88.512 22.797 89.112 26.207 ;
     RECT  51 26.131 51.864 26.219 ;
     RECT  99.6 26.131 100.152 26.219 ;
     RECT  77.856 25.861 78.312 26.283 ;
     RECT  88.512 26.207 90.072 26.291 ;
     RECT  76.08 26.229 76.104 26.317 ;
     RECT  92.352 26.229 92.376 26.317 ;
     RECT  51 26.219 51.72 26.475 ;
     RECT  52.992 26.389 53.016 26.475 ;
     RECT  96.768 26.437 96.792 26.539 ;
     RECT  7.8 23.339 8.112 26.629 ;
     RECT  6.048 26.707 6.072 26.795 ;
     RECT  7.8 26.629 8.712 26.795 ;
     RECT  27.84 26.707 27.864 26.795 ;
     RECT  79.776 26.707 79.8 26.795 ;
     RECT  91.248 26.229 91.272 26.795 ;
     RECT  42.096 26.805 42.12 26.893 ;
     RECT  56.4 25.771 56.712 27.061 ;
     RECT  37.968 27.027 37.992 27.115 ;
     RECT  108.336 27.027 108.36 27.115 ;
     RECT  42.144 27.061 42.168 27.145 ;
     RECT  55.632 27.061 56.712 27.277 ;
     RECT  4.512 26.741 4.536 27.283 ;
     RECT  18.6 25.715 18.912 27.301 ;
     RECT  115.8 23.787 116.112 27.301 ;
     RECT  4.368 27.283 4.536 27.347 ;
     RECT  94.2 25.081 94.512 27.359 ;
     RECT  4.368 27.347 4.392 27.371 ;
     RECT  26.016 27.283 26.04 27.371 ;
     RECT  63.12 26.805 63.144 27.371 ;
     RECT  93.984 27.359 94.512 27.381 ;
     RECT  18.096 27.301 18.912 27.385 ;
     RECT  115.68 27.301 116.112 27.385 ;
     RECT  80.448 27.359 80.472 27.443 ;
     RECT  93.984 27.381 95.496 27.443 ;
     RECT  29.4 23.881 29.712 27.509 ;
     RECT  29.4 27.509 30.504 27.597 ;
     RECT  40.2 25.081 40.512 27.603 ;
     RECT  40.2 27.603 41.112 27.691 ;
     RECT  88.512 26.291 89.112 27.733 ;
     RECT  34.8 25.579 35.112 27.765 ;
     RECT  88.368 27.733 89.112 27.819 ;
     RECT  67.2 25.707 67.512 27.829 ;
     RECT  34.8 27.765 35.544 27.875 ;
     RECT  70.656 27.781 70.68 27.877 ;
     RECT  94.2 27.443 95.496 27.883 ;
     RECT  66.672 27.829 67.512 27.913 ;
     RECT  85.92 27.765 85.944 27.923 ;
     RECT  98.112 27.829 98.136 27.923 ;
     RECT  51 26.475 51.432 27.935 ;
     RECT  56.4 27.277 56.712 27.935 ;
     RECT  88.512 27.819 89.112 27.935 ;
     RECT  51 27.935 51.912 28.019 ;
     RECT  56.4 27.935 57.624 28.019 ;
     RECT  64.416 27.935 64.44 28.019 ;
     RECT  88.512 27.935 89.544 28.019 ;
     RECT  78 26.283 78.312 28.149 ;
     RECT  118.08 28.085 118.104 28.173 ;
     RECT  70.608 27.877 70.68 28.203 ;
     RECT  41.616 28.127 41.64 28.211 ;
     RECT  77.376 28.149 78.312 28.237 ;
     RECT  126.6 6.803 126.912 28.243 ;
     RECT  70.608 28.203 70.632 28.267 ;
     RECT  13.2 23.987 13.512 28.271 ;
     RECT  45.6 22.643 45.912 28.319 ;
     RECT  11.712 28.243 11.736 28.331 ;
     RECT  125.808 28.243 126.912 28.331 ;
     RECT  13.2 28.271 13.704 28.355 ;
     RECT  43.104 28.149 43.128 28.395 ;
     RECT  45.6 28.319 46.2 28.403 ;
     RECT  110.4 25.657 110.712 28.405 ;
     RECT  57.936 28.371 57.96 28.459 ;
     RECT  79.872 27.877 79.896 28.459 ;
     RECT  97.68 28.371 97.704 28.459 ;
     RECT  112.368 27.733 112.392 28.459 ;
     RECT  77.472 28.237 78.312 28.489 ;
     RECT  109.968 28.405 110.712 28.489 ;
     RECT  44.208 27.637 44.232 28.523 ;
     RECT  47.616 28.435 47.64 28.523 ;
     RECT  91.44 28.435 91.464 28.523 ;
     RECT  45.6 28.403 46.104 28.627 ;
     RECT  121.2 23.083 121.512 28.693 ;
     RECT  38.496 28.627 38.52 28.715 ;
     RECT  45.36 28.627 46.104 28.715 ;
     RECT  123.792 23.795 123.816 28.755 ;
     RECT  121.2 28.693 121.608 28.779 ;
     RECT  105 23.891 105.312 28.819 ;
     RECT  68.592 28.755 68.616 28.843 ;
     RECT  123.552 28.755 123.816 28.843 ;
     RECT  7.8 26.795 8.112 28.853 ;
     RECT  45.6 28.715 46.104 28.907 ;
     RECT  105 28.819 106.104 28.907 ;
     RECT  121.2 28.779 121.512 28.917 ;
     RECT  7.8 28.853 8.52 28.941 ;
     RECT  72.6 24.939 72.912 28.981 ;
     RECT  120.768 28.917 121.512 29.005 ;
     RECT  72.6 28.981 73.56 29.065 ;
     RECT  74.688 28.981 74.712 29.065 ;
     RECT  122.544 28.981 122.568 29.065 ;
     RECT  88.512 28.019 89.112 29.075 ;
     RECT  120.816 29.005 121.512 29.075 ;
     RECT  100.896 28.917 100.92 29.099 ;
     RECT  24 25.081 24.312 29.109 ;
     RECT  54.384 29.039 54.408 29.123 ;
     RECT  61.8 16.043 62.112 29.139 ;
     RECT  58.992 28.947 59.016 29.173 ;
     RECT  102.288 29.045 102.312 29.203 ;
     RECT  24 29.109 25.32 29.219 ;
     RECT  61.8 29.139 62.52 29.227 ;
     RECT  81.312 28.405 81.336 29.291 ;
     RECT  102.288 29.203 102.36 29.291 ;
     RECT  7.8 28.941 8.112 29.365 ;
     RECT  24 29.219 25.128 29.365 ;
     RECT  29.4 27.597 29.712 29.365 ;
     RECT  58.992 29.173 59.448 29.365 ;
     RECT  61.8 29.227 62.112 29.365 ;
     RECT  83.4 23.851 83.712 29.365 ;
     RECT  113.616 29.331 113.64 29.365 ;
     RECT  115.8 27.385 116.112 29.365 ;
     RECT  58.656 29.365 59.448 29.419 ;
     RECT  29.184 29.365 29.712 29.459 ;
     RECT  58.656 29.419 58.68 29.459 ;
     RECT  102.288 29.291 102.312 29.459 ;
     RECT  113.376 29.365 113.832 29.459 ;
     RECT  60.864 29.365 62.112 29.507 ;
     RECT  115.8 29.365 116.424 29.507 ;
     RECT  82.656 29.365 83.712 29.555 ;
     RECT  23.904 29.365 25.128 29.699 ;
     RECT  38.784 29.365 38.808 29.699 ;
     RECT  96.576 27.829 96.6 29.795 ;
     RECT  29.4 29.459 29.712 29.797 ;
     RECT  40.2 27.691 40.512 29.893 ;
     RECT  7.152 29.365 8.112 30.035 ;
     RECT  23.904 29.699 24.312 30.035 ;
     RECT  78 28.489 78.312 30.133 ;
     RECT  7.8 30.035 8.112 30.181 ;
     RECT  56.4 28.019 56.712 30.181 ;
     RECT  18.6 27.385 18.912 30.291 ;
     RECT  39.888 29.893 40.512 30.325 ;
     RECT  41.616 30.325 41.64 30.355 ;
     RECT  4.32 30.181 4.344 30.379 ;
     RECT  7.8 30.181 8.568 30.379 ;
     RECT  9.744 30.291 9.768 30.379 ;
     RECT  16.56 30.133 16.584 30.379 ;
     RECT  56.4 30.181 57 30.379 ;
     RECT  77.904 30.133 78.312 30.379 ;
     RECT  87.408 29.301 87.432 30.379 ;
     RECT  96.336 30.181 96.36 30.379 ;
     RECT  41.616 30.355 42.456 30.419 ;
     RECT  42.432 30.419 42.456 30.443 ;
     RECT  10.848 30.037 10.872 30.507 ;
     RECT  58.272 30.469 58.296 30.571 ;
     RECT  67.2 27.913 67.512 30.581 ;
     RECT  19.968 30.517 19.992 30.611 ;
     RECT  29.4 29.797 30.264 30.635 ;
     RECT  31.968 30.547 31.992 30.635 ;
     RECT  71.328 30.547 71.352 30.635 ;
     RECT  76.176 30.325 76.2 30.635 ;
     RECT  18 30.291 18.912 30.763 ;
     RECT  33.6 30.675 33.624 30.763 ;
     RECT  45.6 28.907 45.912 30.773 ;
     RECT  72.6 29.065 72.912 30.805 ;
     RECT  39.6 30.325 40.512 30.827 ;
     RECT  88.8 29.075 89.112 30.837 ;
     RECT  94.2 27.883 94.512 30.837 ;
     RECT  12 30.325 12.024 30.851 ;
     RECT  55.248 30.517 55.272 30.851 ;
     RECT  123.792 28.843 123.816 30.851 ;
     RECT  37.536 30.773 38.136 30.861 ;
     RECT  65.04 30.805 65.064 30.891 ;
     RECT  88.8 30.837 89.208 30.925 ;
     RECT  94.2 30.837 94.92 30.925 ;
     RECT  38.112 30.861 38.136 30.947 ;
     RECT  67.2 30.581 68.424 30.948 ;
     RECT  45.6 30.773 46.104 30.949 ;
     RECT  72.384 30.805 72.912 30.949 ;
     RECT  71.808 30.949 72.912 31.033 ;
     RECT  98.016 31.029 98.04 31.139 ;
     RECT  99.6 26.219 99.912 31.251 ;
     RECT  45.6 30.949 46.728 31.285 ;
     RECT  99.504 31.251 99.912 31.339 ;
     RECT  92.928 31.285 92.952 31.369 ;
     RECT  82.128 31.343 82.152 31.427 ;
     RECT  85.488 31.343 85.512 31.427 ;
     RECT  113.76 31.343 113.784 31.427 ;
     RECT  28.224 31.477 28.248 31.507 ;
     RECT  110.4 28.489 110.712 31.507 ;
     RECT  28.224 31.507 28.344 31.571 ;
     RECT  44.976 31.285 46.728 31.583 ;
     RECT  28.32 31.571 28.344 31.595 ;
     RECT  109.584 31.507 110.712 31.595 ;
     RECT  44.976 31.583 46.776 31.621 ;
     RECT  44.976 31.621 47.256 31.659 ;
     RECT  45.6 31.659 47.256 31.667 ;
     RECT  48.336 30.965 48.36 31.667 ;
     RECT  91.44 31.285 91.464 31.667 ;
     RECT  34.8 27.875 35.112 31.669 ;
     RECT  81.888 31.605 81.912 31.693 ;
     RECT  47.232 31.667 47.256 31.723 ;
     RECT  34.8 31.669 35.928 31.753 ;
     RECT  52.896 31.443 52.92 31.765 ;
     RECT  7.8 30.379 8.112 31.797 ;
     RECT  56.4 30.379 56.712 31.797 ;
     RECT  126.6 28.331 126.912 31.827 ;
     RECT  59.28 31.765 59.304 31.851 ;
     RECT  55.872 31.797 56.712 31.885 ;
     RECT  7.8 31.797 8.232 31.907 ;
     RECT  52.464 31.765 52.92 31.907 ;
     RECT  51 28.019 51.312 31.909 ;
     RECT  105 28.907 105.312 31.909 ;
     RECT  125.664 31.827 126.912 31.915 ;
     RECT  24 30.035 24.312 31.919 ;
     RECT  60.432 31.861 60.456 31.945 ;
     RECT  52.464 31.907 52.488 31.955 ;
     RECT  50.688 31.909 51.312 31.993 ;
     RECT  105 31.909 106.248 31.993 ;
     RECT  24 31.919 25.08 32.003 ;
     RECT  100.896 31.919 100.92 32.003 ;
     RECT  74.304 32.309 74.328 32.373 ;
     RECT  83.4 29.555 83.712 32.403 ;
     RECT  115.8 29.507 116.112 32.403 ;
     RECT  114 32.341 114.024 32.427 ;
     RECT  64.512 32.373 64.536 32.483 ;
     RECT  74.208 32.373 74.328 32.483 ;
     RECT  82.608 32.403 83.712 32.491 ;
     RECT  96.288 31.861 96.312 32.491 ;
     RECT  115.488 32.403 116.112 32.491 ;
     RECT  2.4 25.187 2.712 32.495 ;
     RECT  15.84 32.437 15.864 32.495 ;
     RECT  29.4 30.635 29.712 32.495 ;
     RECT  56.4 31.885 56.712 32.495 ;
     RECT  2.4 32.495 3.432 32.579 ;
     RECT  15.84 32.495 16.536 32.579 ;
     RECT  29.4 32.495 29.832 32.579 ;
     RECT  7.8 31.907 8.112 32.629 ;
     RECT  15.84 32.579 15.864 32.683 ;
     RECT  7.488 32.629 8.112 32.723 ;
     RECT  17.088 32.629 17.112 32.723 ;
     RECT  97.488 32.181 97.512 32.723 ;
     RECT  56.4 32.495 57 32.979 ;
     RECT  115.8 32.491 116.112 32.979 ;
     RECT  121.2 29.075 121.512 32.979 ;
     RECT  56.4 32.979 57.192 33.013 ;
     RECT  56.4 33.013 58.152 33.067 ;
     RECT  115.8 32.979 117.096 33.067 ;
     RECT  121.104 32.979 121.512 33.067 ;
     RECT  72.6 31.033 72.912 33.071 ;
     RECT  78 30.379 78.312 33.071 ;
     RECT  58.128 33.067 58.152 33.097 ;
     RECT  72.24 33.071 72.912 33.155 ;
     RECT  78 33.071 78.456 33.155 ;
     RECT  80.928 33.071 80.952 33.155 ;
     RECT  18.6 30.763 18.912 33.461 ;
     RECT  56.4 33.067 56.712 33.525 ;
     RECT  18 33.461 18.912 33.549 ;
     RECT  110.4 31.595 110.712 33.555 ;
     RECT  110.304 33.555 110.712 33.589 ;
     RECT  55.68 33.525 56.712 33.613 ;
     RECT  110.304 33.589 110.808 33.643 ;
     RECT  111.84 31.237 111.864 33.643 ;
     RECT  112.848 33.541 112.872 33.643 ;
     RECT  110.4 33.643 110.808 33.673 ;
     RECT  118.704 33.647 118.728 33.731 ;
     RECT  124.8 33.647 124.824 33.731 ;
     RECT  120.048 33.717 120.072 33.805 ;
     RECT  54.672 33.845 54.696 33.909 ;
     RECT  54.576 33.909 54.696 33.971 ;
     RECT  54.576 33.971 54.6 33.997 ;
     RECT  13.2 28.355 13.512 34.031 ;
     RECT  13.2 34.031 14.232 34.115 ;
     RECT  59.616 34.037 59.64 34.125 ;
     RECT  46.944 34.069 46.968 34.155 ;
     RECT  5.664 34.223 5.688 34.307 ;
     RECT  107.712 34.223 107.736 34.307 ;
     RECT  59.664 34.293 59.688 34.381 ;
     RECT  45.6 31.667 45.912 34.415 ;
     RECT  13.2 34.115 13.512 34.421 ;
     RECT  11.376 34.405 11.4 34.489 ;
     RECT  45.6 34.415 46.776 34.499 ;
     RECT  13.104 34.421 13.512 34.509 ;
     RECT  82.176 33.747 82.2 34.579 ;
     RECT  83.4 32.491 83.712 34.579 ;
     RECT  45.6 34.499 46.728 34.667 ;
     RECT  81.888 34.579 83.712 34.667 ;
     RECT  51 31.993 51.312 34.799 ;
     RECT  50.88 34.799 51.312 34.883 ;
     RECT  81.984 34.667 82.008 34.883 ;
     RECT  15.984 35.701 16.008 35.785 ;
     RECT  7.8 32.723 8.112 35.893 ;
     RECT  7.8 35.893 8.232 36.035 ;
     RECT  121.2 33.067 121.512 49.583 ;
     RECT  121.2 49.583 121.608 49.667 ;
     RECT  122.544 50.101 122.568 50.185 ;
     RECT  64.416 57.333 64.44 57.421 ;
     RECT  64.704 57.445 64.728 57.529 ;
     RECT  129.408 88.693 129.432 88.883 ;
     RECT  64.848 91.813 64.872 91.897 ;
     RECT  67.2 30.948 67.512 92.115 ;
     RECT  66.288 92.115 67.512 92.203 ;
     RECT  126.6 31.915 126.912 93.733 ;
     RECT  126 93.733 126.912 93.907 ;
     RECT  125.76 93.907 126.912 93.995 ;
     RECT  124.848 109.669 124.872 109.753 ;
     RECT  124.032 109.843 124.056 109.931 ;
     RECT  82.032 113.941 82.056 114.027 ;
     RECT  81.984 114.165 82.008 114.275 ;
     RECT  53.04 115.701 53.064 115.765 ;
     RECT  85.488 115.765 85.512 115.859 ;
     RECT  53.04 115.765 53.16 116.147 ;
     RECT  53.04 116.147 53.064 116.339 ;
     RECT  85.536 116.053 85.56 116.779 ;
     RECT  49.536 117.983 49.56 118.067 ;
     RECT  49.872 118.483 49.896 118.571 ;
     RECT  67.2 92.203 67.512 123.157 ;
     RECT  70.176 123.119 70.2 123.203 ;
     RECT  67.2 123.157 68.424 123.243 ;
     RECT  126.6 93.995 126.912 133.343 ;
     RECT  126 133.343 126.912 133.427 ;
     RECT  126.432 133.427 126.912 133.995 ;
     RECT  126.6 133.995 126.912 136.223 ;
     RECT  126.48 136.223 126.912 136.307 ;
     RECT  126.6 136.307 126.912 149.941 ;
     RECT  126.48 149.941 126.912 150.035 ;
     RECT  124.272 178.579 124.296 178.667 ;
     RECT  125.424 178.579 125.448 178.667 ;
     RECT  38.784 179.029 38.808 179.061 ;
     RECT  40.2 30.827 40.512 179.061 ;
     RECT  38.16 179.061 38.808 179.115 ;
     RECT  38.16 179.115 38.184 179.363 ;
     RECT  64.992 179.317 65.016 179.401 ;
     RECT  39.888 179.061 40.512 179.475 ;
     RECT  39.552 179.475 40.512 179.563 ;
     RECT  108.864 179.475 108.888 179.563 ;
     RECT  51 34.883 51.312 179.605 ;
     RECT  106.608 179.173 106.632 179.843 ;
     RECT  82.032 179.509 82.056 179.845 ;
     RECT  83.4 34.667 83.712 179.845 ;
     RECT  50.736 179.605 51.312 179.893 ;
     RECT  101.088 179.829 101.112 179.917 ;
     RECT  49.968 179.893 51.312 179.939 ;
     RECT  82.032 179.845 83.712 179.947 ;
     RECT  74.64 179.893 74.664 179.977 ;
     RECT  51 179.939 51.312 179.989 ;
     RECT  102.576 179.461 102.6 180.035 ;
     RECT  4.896 179.797 4.92 180.133 ;
     RECT  105 31.993 105.312 180.133 ;
     RECT  13.2 34.509 13.512 180.149 ;
     RECT  42.864 179.221 42.888 180.179 ;
     RECT  49.968 179.939 49.992 180.179 ;
     RECT  63.84 179.509 63.864 180.179 ;
     RECT  82.032 179.947 82.056 180.179 ;
     RECT  86.784 179.605 86.808 180.179 ;
     RECT  121.2 49.667 121.512 180.191 ;
     RECT  103.056 180.037 103.08 180.203 ;
     RECT  104.304 180.133 105.312 180.217 ;
     RECT  124.272 180.133 124.296 180.217 ;
     RECT  121.2 180.191 121.608 180.275 ;
     RECT  117.936 180.149 117.96 180.405 ;
     RECT  117.648 180.405 117.96 180.459 ;
     RECT  13.104 180.149 13.512 180.517 ;
     RECT  13.104 180.517 13.656 180.563 ;
     RECT  4.896 180.133 5.688 180.565 ;
     RECT  56.4 33.613 56.712 180.597 ;
     RECT  99.6 31.339 99.912 180.597 ;
     RECT  4.896 180.565 5.736 180.651 ;
     RECT  13.2 180.563 13.656 180.651 ;
     RECT  22.224 179.797 22.248 180.651 ;
     RECT  48.336 180.149 48.36 180.685 ;
     RECT  91.68 180.597 91.704 180.685 ;
     RECT  99.6 180.597 100.248 180.685 ;
     RECT  0.192 180.565 0.216 180.709 ;
     RECT  51 179.989 51.864 180.755 ;
     RECT  122.496 180.597 122.52 180.755 ;
     RECT  4.896 180.651 4.92 180.995 ;
     RECT  0.192 180.709 0.648 181.141 ;
     RECT  0.192 181.141 1.128 181.189 ;
     RECT  2.4 32.579 2.712 181.189 ;
     RECT  7.8 36.035 8.112 181.237 ;
     RECT  40.2 179.563 40.512 181.237 ;
     RECT  126.6 150.035 126.912 181.401 ;
     RECT  0.192 181.189 2.712 181.813 ;
     RECT  6.816 181.237 8.112 181.813 ;
     RECT  13.2 180.651 13.512 181.813 ;
     RECT  18.6 33.549 18.912 181.813 ;
     RECT  24 32.003 24.312 181.813 ;
     RECT  29.4 32.579 29.712 181.813 ;
     RECT  31.008 180.405 31.032 181.813 ;
     RECT  33.6 181.237 33.624 181.813 ;
     RECT  34.8 31.753 35.112 181.813 ;
     RECT  39.312 181.237 40.512 181.813 ;
     RECT  45.6 34.667 45.912 181.813 ;
     RECT  51 180.755 51.312 181.813 ;
     RECT  56.4 180.597 56.904 181.813 ;
     RECT  61.8 29.507 62.112 181.813 ;
     RECT  64.368 181.237 64.392 181.813 ;
     RECT  67.2 123.243 67.512 181.813 ;
     RECT  72.6 33.155 72.912 181.813 ;
     RECT  74.016 181.237 74.04 181.813 ;
     RECT  78 33.155 78.312 181.813 ;
     RECT  83.4 179.947 83.712 181.813 ;
     RECT  88.8 30.925 89.112 181.813 ;
     RECT  94.2 30.925 94.512 181.813 ;
     RECT  96.864 181.237 96.888 181.813 ;
     RECT  99.6 180.685 99.912 181.813 ;
     RECT  102.576 181.237 102.6 181.813 ;
     RECT  110.4 33.673 110.712 181.813 ;
     RECT  115.8 33.067 116.112 181.813 ;
     RECT  117.648 180.459 117.672 181.813 ;
     RECT  121.2 180.275 121.512 181.813 ;
     RECT  123.648 181.237 123.672 181.813 ;
     RECT  0.192 181.813 4.2 182.341 ;
     RECT  5.472 181.813 11.64 182.341 ;
     RECT  12.96 181.813 14.712 182.341 ;
     RECT  16.896 181.813 16.92 182.341 ;
     RECT  18.24 181.813 27.048 182.341 ;
     RECT  29.4 181.813 42.84 182.341 ;
     RECT  44.16 181.813 46.824 182.341 ;
     RECT  48.096 181.813 53.832 182.341 ;
     RECT  55.104 181.813 78.408 182.341 ;
     RECT  81.936 181.813 103.896 182.341 ;
     RECT  105 180.217 105.312 182.341 ;
     RECT  106.512 181.813 125.448 182.341 ;
     RECT  126.6 181.401 126.744 182.341 ;
     RECT  0.192 182.341 11.64 182.389 ;
     RECT  12.96 182.341 126.744 182.389 ;
     RECT  0.192 182.389 127.176 182.629 ;
     RECT  0.192 182.629 128.088 182.965 ;
     RECT  129.36 182.437 129.384 182.965 ;
     RECT  0.192 182.965 129.384 183.568 ;
    LAYER M6 ;
     RECT  2.16 24.129 3.541 24.801 ;
     RECT  2.16 18.729 3.589 19.401 ;
     RECT  3.589 18.729 3.637 19.744 ;
     RECT  3.541 22.72 3.637 22.752 ;
     RECT  3.541 24.129 3.877 25.056 ;
     RECT  3.637 18.729 4.021 20.448 ;
     RECT  3.637 22.272 4.021 22.752 ;
     RECT  4.021 18.729 4.075 22.752 ;
     RECT  2.16 29.529 4.309 30.201 ;
     RECT  4.309 29.529 4.395 30.368 ;
     RECT  3.397 32.512 4.395 32.544 ;
     RECT  4.341 27.328 4.414 27.36 ;
     RECT  2.16 180.729 4.885 181.401 ;
     RECT  2.16 2.529 5.077 3.201 ;
     RECT  4.075 18.729 5.365 21.728 ;
     RECT  5.365 18.176 5.419 21.728 ;
     RECT  3.877 24.129 5.483 25.184 ;
     RECT  2.16 34.929 5.653 35.601 ;
     RECT  4.885 180.608 5.653 181.401 ;
     RECT  5.419 21.056 6.421 21.728 ;
     RECT  6.421 21.056 6.613 21.984 ;
     RECT  6.613 21.056 6.645 22.752 ;
     RECT  5.483 24.129 6.645 24.801 ;
     RECT  5.419 18.176 6.757 19.401 ;
     RECT  4.395 29.529 7.141 30.201 ;
     RECT  6.645 21.056 7.211 24.801 ;
     RECT  5.653 34.24 7.669 35.601 ;
     RECT  7.669 34.24 7.723 35.936 ;
     RECT  7.141 29.376 7.925 30.201 ;
     RECT  7.477 32.64 7.925 32.672 ;
     RECT  7.925 31.808 7.979 32.672 ;
     RECT  7.979 31.808 8.243 31.84 ;
     RECT  7.723 34.929 8.243 35.936 ;
     RECT  6.757 17.984 8.485 19.401 ;
     RECT  7.925 29.376 8.485 30.368 ;
     RECT  8.485 17.6 8.558 19.401 ;
     RECT  8.558 17.6 8.627 20.576 ;
     RECT  4.501 26.752 8.747 26.784 ;
     RECT  8.485 28.864 8.747 30.368 ;
     RECT  7.211 21.952 9.061 24.801 ;
     RECT  9.186 5.696 9.259 5.728 ;
     RECT  9.061 20.928 9.579 24.801 ;
     RECT  9.579 20.928 10.643 20.96 ;
     RECT  8.627 17.6 10.789 19.401 ;
     RECT  8.747 29.529 10.837 30.368 ;
     RECT  8.243 34.929 11.365 35.601 ;
     RECT  9.579 22.464 11.459 24.801 ;
     RECT  11.459 23.232 11.605 24.801 ;
     RECT  10.837 29.529 11.637 30.496 ;
     RECT  11.605 23.232 11.691 25.632 ;
     RECT  11.691 23.232 12.083 24.801 ;
     RECT  10.789 17.6 12.523 20.896 ;
     RECT  12.523 18.729 12.651 20.896 ;
     RECT  12.651 18.729 12.67 19.744 ;
     RECT  5.653 180.16 13.139 181.401 ;
     RECT  12.083 23.296 13.667 24.801 ;
     RECT  11.637 28.288 13.715 30.496 ;
     RECT  12.67 18.729 14.197 19.552 ;
     RECT  11.365 34.432 14.197 35.601 ;
     RECT  14.197 17.92 14.891 19.552 ;
     RECT  5.077 2.529 15.349 3.872 ;
     RECT  13.667 23.872 15.349 24.801 ;
     RECT  14.197 34.048 15.925 35.601 ;
     RECT  15.925 34.048 15.979 35.744 ;
     RECT  15.979 34.929 16.019 35.744 ;
     RECT  14.891 17.92 16.309 19.401 ;
     RECT  16.309 17.92 16.363 19.552 ;
     RECT  16.363 18.729 16.378 19.552 ;
     RECT  15.829 32.64 16.501 32.672 ;
     RECT  13.715 29.529 16.555 30.496 ;
     RECT  16.501 32.512 16.57 32.672 ;
     RECT  16.555 29.529 16.595 30.368 ;
     RECT  15.349 23.872 17.123 25.568 ;
     RECT  15.349 2.529 17.509 4.128 ;
     RECT  16.595 29.529 17.966 30.201 ;
     RECT  16.57 32.64 17.973 32.672 ;
     RECT  17.973 32.64 18.027 33.504 ;
     RECT  17.966 29.529 18.035 30.752 ;
     RECT  16.378 18.729 18.037 19.401 ;
     RECT  18.027 33.472 18.046 33.504 ;
     RECT  18.037 18.176 18.106 20 ;
     RECT  18.037 27.328 18.131 27.36 ;
     RECT  2.16 13.329 18.165 14.001 ;
     RECT  17.845 16 18.165 16.032 ;
     RECT  18.106 18.176 18.165 19.401 ;
     RECT  17.509 2.529 18.219 5.088 ;
     RECT  18.165 16 18.219 19.401 ;
     RECT  18.165 13.329 18.238 14.24 ;
     RECT  17.029 22.336 18.475 22.368 ;
     RECT  17.123 24 18.475 25.568 ;
     RECT  18.219 17.024 19.043 19.401 ;
     RECT  18.035 29.529 20.003 30.56 ;
     RECT  18.475 24.129 20.341 25.568 ;
     RECT  19.043 18.176 20.725 19.401 ;
     RECT  20.725 18.176 20.794 19.552 ;
     RECT  21.013 22.464 21.061 22.496 ;
     RECT  21.061 22.272 21.099 22.496 ;
     RECT  20.341 24.129 21.995 25.952 ;
     RECT  21.099 22.272 22.197 22.304 ;
     RECT  13.139 180.608 22.213 181.401 ;
     RECT  22.197 21.568 22.251 22.304 ;
     RECT  20.794 18.176 22.259 19.401 ;
     RECT  22.251 21.568 22.261 21.6 ;
     RECT  22.261 21.376 22.307 21.6 ;
     RECT  21.995 24.129 23.893 24.801 ;
     RECT  20.003 29.529 23.893 30.201 ;
     RECT  22.307 21.376 24.373 21.408 ;
     RECT  22.259 18.729 24.421 19.401 ;
     RECT  24.421 18.368 24.491 19.401 ;
     RECT  23.893 29.376 25.013 30.201 ;
     RECT  23.893 24.129 25.067 25.056 ;
     RECT  25.013 31.936 25.091 31.968 ;
     RECT  18.219 2.529 25.195 4.128 ;
     RECT  25.141 5.44 25.506 5.472 ;
     RECT  25.506 5.44 25.579 6.56 ;
     RECT  24.437 17.024 25.715 17.056 ;
     RECT  25.013 26.752 26.005 26.784 ;
     RECT  25.013 29.12 26.037 30.201 ;
     RECT  26.005 26.752 26.091 27.36 ;
     RECT  24.373 21.12 26.387 21.408 ;
     RECT  25.579 5.44 27.347 5.728 ;
     RECT  25.067 24.129 27.493 24.801 ;
     RECT  24.491 18.729 28.213 19.401 ;
     RECT  28.213 31.488 28.309 31.52 ;
     RECT  28.213 18.729 28.501 19.872 ;
     RECT  28.501 17.536 28.587 19.872 ;
     RECT  28.309 31.488 29.045 31.584 ;
     RECT  26.037 28.672 29.109 30.201 ;
     RECT  29.045 31.488 29.109 32.544 ;
     RECT  27.493 23.808 29.123 24.801 ;
     RECT  29.109 28.672 29.163 32.544 ;
     RECT  16.019 34.929 29.237 35.601 ;
     RECT  29.163 32.512 29.843 32.544 ;
     RECT  28.587 18.729 29.891 19.872 ;
     RECT  26.091 26.752 30.469 26.784 ;
     RECT  29.163 28.672 30.469 30.624 ;
     RECT  29.123 24.129 30.517 24.801 ;
     RECT  30.469 26.752 30.517 30.624 ;
     RECT  30.517 24.129 30.571 30.624 ;
     RECT  27.347 5.44 30.851 5.472 ;
     RECT  26.387 21.376 30.851 21.408 ;
     RECT  30.965 16.576 31.043 16.608 ;
     RECT  30.965 5.632 31.283 5.664 ;
     RECT  30.571 24.129 31.955 26.016 ;
     RECT  30.571 28.672 32.003 30.624 ;
     RECT  29.891 18.729 32.869 19.401 ;
     RECT  32.003 28.672 33.589 30.201 ;
     RECT  33.589 28.672 33.658 31.712 ;
     RECT  32.869 18.729 33.829 20.32 ;
     RECT  33.829 17.6 33.845 20.32 ;
     RECT  33.845 17.6 33.899 20.768 ;
     RECT  31.955 24.129 34.165 24.801 ;
     RECT  34.165 23.36 34.234 24.801 ;
     RECT  25.195 2.529 34.501 3.201 ;
     RECT  34.234 24.129 35.173 24.801 ;
     RECT  34.501 2.529 35.317 4.064 ;
     RECT  35.317 2.368 35.363 4.064 ;
     RECT  33.658 28.672 35.445 30.201 ;
     RECT  35.173 24.129 35.499 25.568 ;
     RECT  35.445 27.072 35.555 30.201 ;
     RECT  33.658 31.68 35.939 31.712 ;
     RECT  33.899 18.729 37.045 19.401 ;
     RECT  33.899 20.736 37.045 20.768 ;
     RECT  37.045 18.729 37.099 20.768 ;
     RECT  35.555 28.672 37.525 30.201 ;
     RECT  35.555 27.072 38.003 27.104 ;
     RECT  37.045 22.656 38.645 22.688 ;
     RECT  38.645 22.656 38.723 22.816 ;
     RECT  35.499 24.129 38.725 24.801 ;
     RECT  38.723 22.72 38.819 22.816 ;
     RECT  35.363 2.368 38.891 3.201 ;
     RECT  18.238 13.329 39.083 14.112 ;
     RECT  38.149 179.072 39.522 179.104 ;
     RECT  22.213 180.416 39.522 181.401 ;
     RECT  39.522 179.072 39.595 181.401 ;
     RECT  37.525 28.672 39.635 30.816 ;
     RECT  39.595 180.416 39.915 181.401 ;
     RECT  37.099 18.729 39.923 20.64 ;
     RECT  39.595 179.072 39.923 179.104 ;
     RECT  38.725 24.129 40.683 25.568 ;
     RECT  39.923 18.729 41.067 19.936 ;
     RECT  39.635 28.672 41.077 30.368 ;
     RECT  37.093 17.024 41.525 17.056 ;
     RECT  41.525 17.024 41.601 17.44 ;
     RECT  41.077 27.648 42.085 30.368 ;
     RECT  40.683 24.129 42.101 25.056 ;
     RECT  42.085 26.816 42.155 30.368 ;
     RECT  42.155 27.072 42.421 30.368 ;
     RECT  38.819 22.72 42.661 22.752 ;
     RECT  42.101 24.129 42.661 25.248 ;
     RECT  42.661 22.72 42.731 25.248 ;
     RECT  42.731 22.72 42.755 22.816 ;
     RECT  42.731 24.129 42.853 25.248 ;
     RECT  42.853 24.129 42.923 25.632 ;
     RECT  42.755 22.784 43.115 22.816 ;
     RECT  41.067 18.729 43.379 19.552 ;
     RECT  42.421 27.072 43.947 30.432 ;
     RECT  41.601 17.408 43.955 17.44 ;
     RECT  42.923 24.129 44.529 25.248 ;
     RECT  38.891 2.529 44.581 3.201 ;
     RECT  44.581 2.368 44.651 3.201 ;
     RECT  43.947 27.072 46.069 30.201 ;
     RECT  44.965 31.616 46.069 31.648 ;
     RECT  43.379 18.729 46.117 19.401 ;
     RECT  44.389 22.592 46.211 22.624 ;
     RECT  46.069 27.072 46.211 31.648 ;
     RECT  44.651 2.529 46.693 3.201 ;
     RECT  29.237 34.112 46.979 35.601 ;
     RECT  46.211 28.48 47.221 31.648 ;
     RECT  47.221 28.48 47.651 31.712 ;
     RECT  46.693 2.529 47.939 4.448 ;
     RECT  44.529 24.129 48.133 24.801 ;
     RECT  48.133 24.129 48.235 25.568 ;
     RECT  39.915 180.608 48.325 181.401 ;
     RECT  47.651 28.672 48.371 31.712 ;
     RECT  38.821 6.528 48.613 6.56 ;
     RECT  48.613 5.632 49.013 6.56 ;
     RECT  2.16 7.929 49.013 8.601 ;
     RECT  49.013 5.632 49.077 8.601 ;
     RECT  49.077 5.632 49.15 8.736 ;
     RECT  49.15 5.632 49.21 8.601 ;
     RECT  46.117 18.729 49.262 20.064 ;
     RECT  47.413 16.512 49.269 16.544 ;
     RECT  49.269 16.512 49.323 16.672 ;
     RECT  49.262 18.729 49.323 21.152 ;
     RECT  49.323 21.12 49.331 21.152 ;
     RECT  2.16 115.929 49.525 116.601 ;
     RECT  49.525 118.016 49.594 118.048 ;
     RECT  49.838 118.528 49.907 118.56 ;
     RECT  49.21 5.632 49.955 6.56 ;
     RECT  48.235 24.129 49.957 24.801 ;
     RECT  49.957 23.936 50.027 24.801 ;
     RECT  49.323 16.64 50.387 16.672 ;
     RECT  48.371 31.68 50.677 31.712 ;
     RECT  47.939 2.529 50.725 3.201 ;
     RECT  46.979 34.624 50.997 35.601 ;
     RECT  50.677 31.68 51.051 31.968 ;
     RECT  46.211 27.072 51.397 27.104 ;
     RECT  50.725 2.529 51.779 3.424 ;
     RECT  51.397 26.432 51.81 27.104 ;
     RECT  51.81 26.176 51.829 27.104 ;
     RECT  48.371 28.672 51.829 30.201 ;
     RECT  51.829 26.176 51.883 30.201 ;
     RECT  51.883 26.432 51.923 30.201 ;
     RECT  51.051 31.68 52.453 31.712 ;
     RECT  52.453 31.68 52.885 31.84 ;
     RECT  49.525 115.776 52.917 116.601 ;
     RECT  52.885 31.488 52.971 31.84 ;
     RECT  52.917 115.712 53.075 116.601 ;
     RECT  49.955 6.528 53.154 6.56 ;
     RECT  53.154 5.632 53.227 6.56 ;
     RECT  51.923 26.432 54.315 27.36 ;
     RECT  50.027 24.129 54.613 24.801 ;
     RECT  49.323 18.729 54.645 19.401 ;
     RECT  49.973 21.632 54.645 21.664 ;
     RECT  54.613 23.36 54.645 24.801 ;
     RECT  50.997 33.92 54.661 35.601 ;
     RECT  54.645 21.632 54.699 24.801 ;
     RECT  51.923 28.672 55.237 30.201 ;
     RECT  52.971 31.808 55.237 31.84 ;
     RECT  54.661 33.856 55.65 35.601 ;
     RECT  54.315 27.072 55.667 27.36 ;
     RECT  55.237 28.672 55.669 31.84 ;
     RECT  55.65 33.536 55.669 35.601 ;
     RECT  55.669 28.672 55.907 35.601 ;
     RECT  54.661 16.512 56.293 16.544 ;
     RECT  56.293 16.512 56.339 16.672 ;
     RECT  54.699 22.528 56.339 22.56 ;
     RECT  48.325 180.16 56.885 181.401 ;
     RECT  56.885 179.328 56.939 181.401 ;
     RECT  54.645 18.729 57.157 20.128 ;
     RECT  55.667 27.2 57.205 27.36 ;
     RECT  55.907 28.672 57.205 30.56 ;
     RECT  57.157 18.729 57.259 20.768 ;
     RECT  54.699 24.129 57.589 24.801 ;
     RECT  57.205 27.2 57.707 30.56 ;
     RECT  57.707 28.416 57.717 30.56 ;
     RECT  55.907 32.512 57.717 35.601 ;
     RECT  57.717 28.416 57.971 35.601 ;
     RECT  56.339 16.64 58.117 16.672 ;
     RECT  53.227 6.528 58.163 6.56 ;
     RECT  58.117 16.64 58.163 17.056 ;
     RECT  57.971 28.672 58.307 35.601 ;
     RECT  58.307 28.672 58.795 30.201 ;
     RECT  58.795 28.992 59.027 30.201 ;
     RECT  58.307 31.808 59.315 35.601 ;
     RECT  57.589 24.129 59.413 25.76 ;
     RECT  59.315 31.872 59.691 35.601 ;
     RECT  59.691 34.304 59.699 35.601 ;
     RECT  59.413 24.129 59.797 26.016 ;
     RECT  58.163 17.024 59.893 17.056 ;
     RECT  57.259 18.729 59.893 20.64 ;
     RECT  59.893 17.024 59.947 20.64 ;
     RECT  59.797 22.848 60.203 26.016 ;
     RECT  59.947 18.112 60.395 20.64 ;
     RECT  59.691 31.872 60.467 31.904 ;
     RECT  60.395 18.729 60.515 20.64 ;
     RECT  60.277 16.512 61.477 16.544 ;
     RECT  61.477 16 61.557 16.544 ;
     RECT  61.477 5.056 61.611 5.088 ;
     RECT  61.557 16 61.611 16.608 ;
     RECT  59.027 29.184 62.645 30.201 ;
     RECT  63.013 5.632 63.083 5.664 ;
     RECT  60.203 24.129 63.086 26.016 ;
     RECT  63.086 24.129 63.109 26.848 ;
     RECT  62.645 28.224 63.109 30.201 ;
     RECT  63.109 24.129 63.147 30.201 ;
     RECT  63.147 26.816 63.155 30.201 ;
     RECT  63.155 27.328 63.211 30.201 ;
     RECT  61.611 16.576 63.875 16.608 ;
     RECT  63.147 24.129 64.357 24.801 ;
     RECT  2.16 56.529 64.405 57.201 ;
     RECT  63.211 27.968 64.451 30.201 ;
     RECT  64.451 28.224 64.501 30.201 ;
     RECT  64.482 32.384 64.555 32.416 ;
     RECT  64.405 56.529 64.693 57.376 ;
     RECT  64.693 56.529 64.762 57.504 ;
     RECT  2.16 88.929 64.821 89.601 ;
     RECT  64.814 91.84 64.883 91.872 ;
     RECT  56.939 179.328 65.027 179.36 ;
     RECT  64.357 23.936 65.557 24.801 ;
     RECT  65.557 22.656 65.643 24.801 ;
     RECT  57.205 11.072 66.179 11.104 ;
     RECT  2.16 121.329 66.421 122.001 ;
     RECT  65.989 5.376 66.475 5.408 ;
     RECT  66.402 11.264 66.475 11.296 ;
     RECT  64.762 56.529 66.475 57.376 ;
     RECT  66.277 92.16 66.475 92.192 ;
     RECT  64.501 28.224 66.661 30.88 ;
     RECT  65.643 24.129 68.389 24.801 ;
     RECT  66.661 27.84 68.435 30.88 ;
     RECT  66.421 121.329 68.435 123.232 ;
     RECT  68.435 27.84 68.459 30.624 ;
     RECT  66.293 17.024 68.867 17.056 ;
     RECT  68.389 24.129 69.349 25.696 ;
     RECT  69.349 22.848 69.419 25.696 ;
     RECT  68.435 121.329 70.165 122.001 ;
     RECT  70.165 121.329 70.251 123.168 ;
     RECT  69.419 24.129 70.403 25.696 ;
     RECT  69.493 5.44 70.626 5.472 ;
     RECT  70.626 5.44 70.645 6.304 ;
     RECT  68.459 28.224 70.645 30.624 ;
     RECT  70.645 4.928 70.699 6.304 ;
     RECT  70.645 28.16 71.797 30.624 ;
     RECT  71.797 28.16 72.245 31.008 ;
     RECT  70.699 4.928 72.275 5.472 ;
     RECT  72.229 33.088 72.299 33.12 ;
     RECT  71.221 17.088 73.205 17.12 ;
     RECT  60.515 18.729 73.205 20.576 ;
     RECT  73.205 16.128 73.259 20.576 ;
     RECT  73.259 16.128 73.283 16.16 ;
     RECT  70.403 24.129 73.589 24.801 ;
     RECT  72.325 22.464 73.698 22.496 ;
     RECT  72.275 5.44 73.771 5.472 ;
     RECT  73.698 22.464 73.771 22.752 ;
     RECT  73.589 24.129 73.835 24.928 ;
     RECT  51.779 2.529 73.957 3.201 ;
     RECT  49.21 7.929 73.973 8.601 ;
     RECT  73.957 2.529 74.027 4 ;
     RECT  73.259 17.472 74.037 20.576 ;
     RECT  73.771 22.464 74.037 22.496 ;
     RECT  74.037 17.472 74.097 22.496 ;
     RECT  72.245 28.16 74.165 31.328 ;
     RECT  74.165 28.16 74.219 32.416 ;
     RECT  74.219 32.32 74.243 32.416 ;
     RECT  74.243 32.32 74.339 32.352 ;
     RECT  56.939 180.729 74.629 181.401 ;
     RECT  74.097 17.472 74.723 21.664 ;
     RECT  74.723 18.729 75.299 21.664 ;
     RECT  74.219 28.16 77.411 30.88 ;
     RECT  73.781 26.24 77.891 26.272 ;
     RECT  78.421 33.088 78.507 33.12 ;
     RECT  73.973 7.104 78.661 8.601 ;
     RECT  78.661 6.208 79.531 8.601 ;
     RECT  77.893 17.024 79.531 17.056 ;
     RECT  79.531 7.04 79.859 8.601 ;
     RECT  75.299 18.729 80.373 20.576 ;
     RECT  79.214 22.272 80.373 22.304 ;
     RECT  80.373 18.729 80.437 22.304 ;
     RECT  79.765 26.752 80.437 26.784 ;
     RECT  77.411 28.416 80.437 30.88 ;
     RECT  74.027 2.529 80.485 3.201 ;
     RECT  80.485 2.368 80.501 3.201 ;
     RECT  80.437 26.752 80.506 30.88 ;
     RECT  80.501 2.368 80.555 4.064 ;
     RECT  80.437 18.729 80.579 22.752 ;
     RECT  80.555 2.529 81.635 4.064 ;
     RECT  81.637 5.632 81.707 5.664 ;
     RECT  80.506 28.416 81.877 30.88 ;
     RECT  81.877 28.416 81.909 31.648 ;
     RECT  81.653 10.304 81.925 10.336 ;
     RECT  80.917 33.088 81.973 33.12 ;
     RECT  59.699 34.624 81.973 35.601 ;
     RECT  81.909 114.176 82.019 114.208 ;
     RECT  73.835 24.129 82.021 24.801 ;
     RECT  80.506 26.752 82.021 26.784 ;
     RECT  79.859 7.104 82.027 8.601 ;
     RECT  81.925 10.304 82.027 10.592 ;
     RECT  82.021 113.984 82.091 114.016 ;
     RECT  82.021 24.129 82.155 26.784 ;
     RECT  81.909 28.224 82.163 31.648 ;
     RECT  81.973 33.088 82.211 35.601 ;
     RECT  82.027 10.304 82.347 10.336 ;
     RECT  80.579 18.729 82.355 21.856 ;
     RECT  82.293 15.488 82.485 15.52 ;
     RECT  80.61 16.96 82.485 16.992 ;
     RECT  82.485 15.488 82.539 16.992 ;
     RECT  82.211 33.088 82.549 33.12 ;
     RECT  82.539 15.488 82.558 16.48 ;
     RECT  82.549 32.448 82.603 33.12 ;
     RECT  82.603 32.448 82.643 32.48 ;
     RECT  81.635 2.529 82.691 3.36 ;
     RECT  81.973 4.672 83.267 5.216 ;
     RECT  82.155 24.129 83.765 25.504 ;
     RECT  83.765 23.808 83.819 25.504 ;
     RECT  82.355 18.729 84.277 21.792 ;
     RECT  83.819 23.808 84.331 24.801 ;
     RECT  82.163 28.224 85.477 30.201 ;
     RECT  53.075 115.776 85.493 116.601 ;
     RECT  82.558 15.488 85.523 15.52 ;
     RECT  85.493 115.776 85.523 116.768 ;
     RECT  74.629 179.904 85.547 181.401 ;
     RECT  85.523 115.929 85.571 116.768 ;
     RECT  84.331 24.129 85.669 24.801 ;
     RECT  85.477 28.224 85.813 31.392 ;
     RECT  85.669 24.129 85.867 25.056 ;
     RECT  84.277 18.729 86.387 22.176 ;
     RECT  85.813 27.776 87.403 31.392 ;
     RECT  86.581 22.272 88.021 22.304 ;
     RECT  87.403 27.776 88.403 30.88 ;
     RECT  86.387 18.729 88.693 20.576 ;
     RECT  88.693 17.472 89.003 20.704 ;
     RECT  89.003 18.112 89.173 20.704 ;
     RECT  88.021 22.208 89.173 22.304 ;
     RECT  89.173 22.208 89.259 22.752 ;
     RECT  89.173 18.112 89.269 20.832 ;
     RECT  89.259 22.208 89.269 22.24 ;
     RECT  88.403 27.968 89.323 30.88 ;
     RECT  89.269 18.112 89.459 22.24 ;
     RECT  83.267 5.184 89.509 5.216 ;
     RECT  89.509 5.184 89.555 5.408 ;
     RECT  89.459 18.112 89.555 21.728 ;
     RECT  89.323 27.968 89.555 28 ;
     RECT  89.555 20.8 90.805 21.728 ;
     RECT  90.805 20.8 90.859 22.752 ;
     RECT  90.037 26.24 91.211 26.272 ;
     RECT  89.323 29.376 91.253 30.88 ;
     RECT  91.253 28.48 91.381 30.88 ;
     RECT  91.381 28.48 91.475 31.328 ;
     RECT  91.211 26.24 92.341 26.784 ;
     RECT  85.867 24.129 92.395 24.928 ;
     RECT  92.341 26.24 92.395 27.552 ;
     RECT  91.475 29.376 92.963 31.328 ;
     RECT  89.555 18.112 93.493 19.401 ;
     RECT  90.859 22.72 93.539 22.752 ;
     RECT  89.555 5.376 93.973 5.408 ;
     RECT  93.973 5.376 94.005 5.664 ;
     RECT  92.395 24.129 94.005 24.801 ;
     RECT  92.395 26.752 94.059 27.552 ;
     RECT  94.005 24.129 94.115 25.056 ;
     RECT  93.493 17.664 94.691 19.401 ;
     RECT  92.963 29.376 94.885 30.201 ;
     RECT  94.837 15.424 94.906 15.456 ;
     RECT  94.059 27.392 95.461 27.552 ;
     RECT  95.461 27.392 95.507 27.872 ;
     RECT  94.885 29.376 96.309 30.88 ;
     RECT  90.859 20.8 96.325 20.832 ;
     RECT  95.507 27.84 96.757 27.872 ;
     RECT  96.309 29.376 96.757 31.072 ;
     RECT  96.738 26.496 96.811 26.528 ;
     RECT  94.691 18.729 96.93 19.401 ;
     RECT  96.325 20.8 96.93 21.664 ;
     RECT  96.93 18.729 97.003 21.664 ;
     RECT  96.757 27.84 97.477 31.072 ;
     RECT  96.277 32.448 97.477 32.48 ;
     RECT  97.477 27.84 97.523 32.48 ;
     RECT  94.115 24.129 97.698 24.801 ;
     RECT  97.698 24.129 97.771 25.056 ;
     RECT  94.005 5.376 98.005 6.56 ;
     RECT  82.027 7.929 98.005 8.601 ;
     RECT  97.523 27.84 98.051 32.224 ;
     RECT  98.005 5.376 98.101 8.601 ;
     RECT  98.051 27.84 98.147 30.201 ;
     RECT  98.101 4.8 98.155 8.601 ;
     RECT  98.101 16.576 98.17 16.608 ;
     RECT  98.155 4.8 98.195 6.56 ;
     RECT  97.003 20.8 98.421 21.664 ;
     RECT  97.771 24.129 98.535 24.801 ;
     RECT  98.421 20.736 98.603 21.664 ;
     RECT  98.603 20.736 98.723 20.832 ;
     RECT  98.147 28.416 99.493 30.201 ;
     RECT  98.051 32.192 99.493 32.224 ;
     RECT  99.493 28.416 99.563 32.224 ;
     RECT  99.563 28.416 99.755 31.968 ;
     RECT  97.003 18.729 100.117 19.401 ;
     RECT  100.117 26.176 100.203 26.208 ;
     RECT  99.755 28.416 100.203 30.201 ;
     RECT  100.203 28.928 100.931 30.201 ;
     RECT  99.755 31.936 100.931 31.968 ;
     RECT  85.547 180.608 101.077 181.401 ;
     RECT  98.723 20.8 101.173 20.832 ;
     RECT  98.195 5.376 101.227 6.56 ;
     RECT  82.211 34.624 101.227 35.601 ;
     RECT  101.227 5.376 101.267 5.664 ;
     RECT  100.117 17.536 102.181 19.401 ;
     RECT  100.931 29.056 102.323 30.201 ;
     RECT  102.181 16.448 102.347 19.401 ;
     RECT  101.173 20.8 102.347 21.152 ;
     RECT  98.535 23.616 102.419 24.801 ;
     RECT  102.347 16.448 102.443 21.152 ;
     RECT  101.077 179.84 102.611 181.401 ;
     RECT  102.443 18.729 102.638 21.152 ;
     RECT  102.638 18.729 102.707 21.664 ;
     RECT  102.707 18.729 103.147 21.152 ;
     RECT  101.267 5.376 103.717 5.408 ;
     RECT  102.611 180.16 104.339 181.401 ;
     RECT  103.147 18.729 104.437 20.832 ;
     RECT  104.437 18.624 104.506 20.832 ;
     RECT  103.717 5.12 104.915 5.408 ;
     RECT  102.419 23.808 105.397 24.801 ;
     RECT  104.506 18.729 105.539 20.832 ;
     RECT  102.323 29.248 106.069 30.201 ;
     RECT  106.069 28.864 106.283 30.201 ;
     RECT  106.213 31.936 106.283 31.968 ;
     RECT  82.691 2.529 106.722 3.201 ;
     RECT  106.722 2.529 106.741 3.36 ;
     RECT  105.397 23.744 106.741 24.801 ;
     RECT  104.915 5.376 106.795 5.408 ;
     RECT  106.741 22.72 106.795 24.801 ;
     RECT  101.227 34.929 107.701 35.601 ;
     RECT  106.795 22.72 107.795 22.752 ;
     RECT  106.795 24.129 108.405 24.801 ;
     RECT  106.229 27.072 108.459 27.104 ;
     RECT  104.339 180.608 108.834 181.401 ;
     RECT  108.834 179.52 108.907 181.401 ;
     RECT  105.539 18.729 109.669 19.401 ;
     RECT  105.973 16.32 109.739 16.352 ;
     RECT  109.669 17.792 109.739 19.401 ;
     RECT  109.685 11.328 109.941 11.36 ;
     RECT  107.701 34.24 109.941 35.601 ;
     RECT  105.539 20.8 109.957 20.832 ;
     RECT  106.283 29.248 109.957 30.201 ;
     RECT  109.941 10.496 109.995 11.36 ;
     RECT  109.573 31.552 109.995 31.584 ;
     RECT  109.941 33.6 109.995 35.601 ;
     RECT  109.941 5.888 110.014 5.92 ;
     RECT  108.405 24.129 110.051 25.632 ;
     RECT  109.995 10.496 110.339 11.04 ;
     RECT  110.339 10.496 110.819 10.592 ;
     RECT  110.051 24.129 111.397 24.801 ;
     RECT  109.739 18.729 111.413 19.401 ;
     RECT  109.957 20.8 111.413 21.152 ;
     RECT  111.413 18.729 111.467 21.152 ;
     RECT  111.397 23.36 111.467 24.801 ;
     RECT  111.467 18.729 111.491 21.024 ;
     RECT  106.741 2.529 111.589 4 ;
     RECT  111.589 2.529 112.213 5.152 ;
     RECT  109.957 28.416 112.357 30.201 ;
     RECT  98.155 7.929 112.549 8.601 ;
     RECT  112.213 2.368 112.619 5.152 ;
     RECT  110.819 10.56 112.619 10.592 ;
     RECT  112.021 16.768 113.013 16.8 ;
     RECT  112.619 5.12 113.067 5.152 ;
     RECT  112.549 6.784 113.067 8.601 ;
     RECT  113.013 16.192 113.067 16.8 ;
     RECT  113.067 16.192 113.315 16.224 ;
     RECT  111.467 24.129 113.365 24.801 ;
     RECT  112.619 2.368 113.459 3.616 ;
     RECT  111.491 20.8 113.459 21.024 ;
     RECT  112.357 27.968 113.515 30.201 ;
     RECT  113.515 28.736 113.653 30.201 ;
     RECT  113.653 28.736 113.717 31.264 ;
     RECT  113.717 28.736 113.973 31.392 ;
     RECT  109.995 33.6 113.973 33.632 ;
     RECT  113.973 28.736 114.027 33.632 ;
     RECT  114.027 32.384 114.046 32.416 ;
     RECT  113.365 24.129 115.125 24.928 ;
     RECT  115.125 23.744 115.179 24.928 ;
     RECT  113.459 20.8 115.253 20.832 ;
     RECT  115.179 23.744 115.307 24.801 ;
     RECT  115.477 32.448 115.509 32.48 ;
     RECT  115.509 32.448 115.563 33.056 ;
     RECT  115.253 20.8 116.011 21.664 ;
     RECT  116.011 21.12 116.243 21.664 ;
     RECT  111.491 18.729 116.322 19.401 ;
     RECT  115.957 16.448 116.339 16.48 ;
     RECT  116.322 18.729 116.341 19.552 ;
     RECT  116.341 18.048 116.395 19.552 ;
     RECT  2.16 110.529 116.789 111.201 ;
     RECT  116.243 21.632 117.685 21.664 ;
     RECT  117.685 21.376 117.731 21.664 ;
     RECT  115.307 24.129 117.925 24.801 ;
     RECT  108.907 180.416 117.925 181.401 ;
     RECT  115.669 27.328 118.005 27.36 ;
     RECT  114.027 28.736 118.005 30.201 ;
     RECT  118.005 27.328 118.251 30.201 ;
     RECT  115.563 33.024 118.693 33.056 ;
     RECT  109.995 34.929 118.693 35.601 ;
     RECT  118.251 27.968 118.763 30.201 ;
     RECT  117.731 21.376 119.15 21.408 ;
     RECT  117.925 24.129 119.171 25.312 ;
     RECT  119.15 21.376 119.219 21.664 ;
     RECT  116.395 18.048 119.586 19.401 ;
     RECT  2.16 94.329 119.605 95.001 ;
     RECT  119.586 17.6 119.659 19.401 ;
     RECT  118.693 33.024 120.083 35.601 ;
     RECT  119.219 21.376 120.517 21.408 ;
     RECT  120.517 21.376 120.563 21.6 ;
     RECT  119.171 24.129 120.757 24.801 ;
     RECT  120.563 21.568 120.811 21.6 ;
     RECT  120.949 21.632 121.018 21.664 ;
     RECT  113.459 2.529 121.045 3.616 ;
     RECT  120.083 33.024 121.139 33.056 ;
     RECT  121.045 2.529 121.195 3.744 ;
     RECT  120.949 49.6 121.461 49.632 ;
     RECT  2.16 51.129 121.461 51.801 ;
     RECT  118.763 28.736 121.619 30.201 ;
     RECT  121.461 49.6 121.619 51.801 ;
     RECT  121.619 50.112 122.579 51.801 ;
     RECT  121.619 28.992 123.541 30.201 ;
     RECT  121.195 2.529 123.589 3.201 ;
     RECT  2.16 132.129 124.021 132.801 ;
     RECT  120.757 23.04 124.163 24.801 ;
     RECT  117.925 180.16 124.307 181.401 ;
     RECT  120.083 34.929 124.789 35.601 ;
     RECT  121.141 5.184 124.883 5.216 ;
     RECT  116.789 109.696 124.883 111.201 ;
     RECT  123.589 2.529 125.507 3.36 ;
     RECT  124.163 24.129 125.557 24.801 ;
     RECT  123.541 28.8 125.557 30.201 ;
     RECT  125.557 24.129 125.626 25.056 ;
     RECT  124.789 33.664 125.675 35.601 ;
     RECT  125.621 31.872 125.803 31.904 ;
     RECT  122.485 178.624 125.803 178.656 ;
     RECT  125.557 28.288 125.843 30.201 ;
     RECT  119.605 93.76 126.035 95.001 ;
     RECT  124.021 132.129 126.389 133.408 ;
     RECT  2.16 137.529 126.389 138.201 ;
     RECT  2.16 148.329 126.446 149.001 ;
     RECT  126.389 132.129 126.467 133.984 ;
     RECT  126.467 132.129 126.515 133.856 ;
     RECT  126.389 136.256 126.515 138.201 ;
     RECT  126.446 148.329 126.515 149.984 ;
     RECT  125.507 2.529 127.44 3.201 ;
     RECT  113.067 7.929 127.44 8.601 ;
     RECT  39.083 13.329 127.44 14.001 ;
     RECT  119.659 18.729 127.44 19.401 ;
     RECT  125.626 24.129 127.44 24.801 ;
     RECT  125.843 29.529 127.44 30.201 ;
     RECT  125.675 34.929 127.44 35.601 ;
     RECT  2.16 40.329 127.44 41.001 ;
     RECT  2.16 45.729 127.44 46.401 ;
     RECT  122.579 51.129 127.44 51.801 ;
     RECT  66.475 56.529 127.44 57.201 ;
     RECT  2.16 61.929 127.44 62.601 ;
     RECT  2.16 67.329 127.44 68.001 ;
     RECT  2.16 72.729 127.44 73.401 ;
     RECT  2.16 78.129 127.44 78.801 ;
     RECT  2.16 83.529 127.44 84.201 ;
     RECT  64.821 88.704 127.44 89.601 ;
     RECT  126.035 94.329 127.44 95.001 ;
     RECT  2.16 99.729 127.44 100.401 ;
     RECT  2.16 105.129 127.44 105.801 ;
     RECT  124.883 110.529 127.44 111.201 ;
     RECT  85.571 115.929 127.44 116.601 ;
     RECT  70.251 121.329 127.44 122.001 ;
     RECT  2.16 126.729 127.44 127.401 ;
     RECT  126.515 132.129 127.44 132.801 ;
     RECT  126.515 137.529 127.44 138.201 ;
     RECT  2.16 142.929 127.44 143.601 ;
     RECT  126.515 148.329 127.44 149.001 ;
     RECT  2.16 153.729 127.44 154.401 ;
     RECT  2.16 159.129 127.44 159.801 ;
     RECT  2.16 164.529 127.44 165.201 ;
     RECT  2.16 169.929 127.44 170.601 ;
     RECT  2.16 175.329 127.44 176.001 ;
     RECT  124.307 180.729 127.44 181.401 ;
     RECT  127.44 88.704 129.443 88.736 ;
    LAYER M7 ;
     RECT  119.808 3.317 119.84 3.445 ;
     RECT  119.616 3.445 119.84 3.499 ;
     RECT  80.512 2.357 80.544 4.075 ;
     RECT  15.36 3.829 15.392 4.139 ;
     RECT  112.576 3.573 112.608 5.109 ;
     RECT  121.152 3.509 121.184 5.227 ;
     RECT  106.752 3.317 106.784 5.419 ;
     RECT  25.152 4.085 25.184 5.429 ;
     RECT  73.984 3.957 74.016 5.429 ;
     RECT  25.152 5.429 25.568 5.483 ;
     RECT  81.984 5.173 82.016 5.621 ;
     RECT  9.216 3.829 9.248 5.739 ;
     RECT  70.656 4.917 70.688 6.315 ;
     RECT  49.024 5.621 49.056 6.517 ;
     RECT  44.608 2.357 44.64 6.571 ;
     RECT  53.184 5.621 53.216 6.571 ;
     RECT  94.016 5.621 94.88 6.571 ;
     RECT  73.728 5.429 74.016 7.147 ;
     RECT  49.024 6.517 49.184 7.467 ;
     RECT  49.088 7.467 49.184 7.851 ;
     RECT  81.664 5.621 82.016 10.293 ;
     RECT  81.664 10.293 82.336 10.347 ;
     RECT  112.576 5.109 113.056 10.603 ;
     RECT  63.04 5.621 63.072 11.115 ;
     RECT  109.952 5.877 109.984 11.317 ;
     RECT  109.696 11.317 109.984 11.371 ;
     RECT  38.848 2.357 38.88 14.069 ;
     RECT  38.848 14.069 39.072 14.123 ;
     RECT  94.848 6.571 94.88 15.467 ;
     RECT  81.984 10.347 82.336 15.477 ;
     RECT  73.728 7.147 73.76 16.117 ;
     RECT  101.184 5.621 101.216 16.437 ;
     RECT  49.088 7.851 49.12 16.501 ;
     RECT  61.568 5.045 61.6 16.501 ;
     RECT  49.088 16.501 49.312 16.555 ;
     RECT  30.976 5.621 31.008 16.619 ;
     RECT  60.288 16.501 61.6 16.619 ;
     RECT  98.112 4.789 98.144 16.619 ;
     RECT  113.024 10.603 113.056 16.811 ;
     RECT  79.488 6.197 79.52 16.949 ;
     RECT  81.984 15.477 82.528 17.003 ;
     RECT  25.536 5.483 25.568 17.013 ;
     RECT  60.288 16.619 60.32 17.013 ;
     RECT  66.432 5.365 66.464 17.013 ;
     RECT  79.488 16.949 80.672 17.013 ;
     RECT  66.304 17.013 66.464 17.067 ;
     RECT  79.232 17.013 80.672 17.067 ;
     RECT  41.024 17.013 41.568 17.451 ;
     RECT  73.216 16.117 73.76 17.461 ;
     RECT  73.216 17.461 73.824 17.515 ;
     RECT  109.696 11.371 109.728 17.835 ;
     RECT  115.968 16.437 116 18.037 ;
     RECT  59.904 17.013 60.32 18.101 ;
     RECT  59.904 18.101 60.384 18.155 ;
     RECT  18.176 5.045 18.208 18.165 ;
     RECT  18.048 18.165 18.208 18.219 ;
     RECT  66.304 17.067 66.336 19.509 ;
     RECT  14.848 18.037 14.88 19.563 ;
     RECT  16.32 17.909 16.352 19.563 ;
     RECT  20.736 18.165 20.768 19.563 ;
     RECT  65.6 19.509 66.336 19.563 ;
     RECT  12.48 17.589 12.512 19.701 ;
     RECT  3.648 19.701 3.68 19.893 ;
     RECT  79.232 17.067 79.264 19.893 ;
     RECT  80.64 17.067 80.672 19.893 ;
     RECT  41.024 17.451 41.056 19.947 ;
     RECT  79.232 19.893 80.672 19.947 ;
     RECT  18.048 18.219 18.08 20.011 ;
     RECT  73.728 17.515 73.824 20.139 ;
     RECT  101.184 16.437 102.432 20.213 ;
     RECT  101.184 20.213 103.136 20.267 ;
     RECT  104.448 18.613 104.48 20.267 ;
     RECT  5.376 18.165 5.408 20.459 ;
     RECT  60.288 18.155 60.384 20.523 ;
     RECT  60.288 20.523 60.32 20.533 ;
     RECT  8.576 17.973 8.608 20.587 ;
     RECT  60.16 20.533 60.32 20.587 ;
     RECT  88.96 17.461 88.992 20.587 ;
     RECT  12.48 19.701 12.64 20.597 ;
     RECT  33.856 17.589 33.888 20.725 ;
     RECT  84.288 19.637 84.32 20.725 ;
     RECT  33.856 20.725 34.208 20.779 ;
     RECT  11.968 20.597 12.64 20.907 ;
     RECT  98.432 20.725 98.464 20.917 ;
     RECT  98.432 20.917 98.592 20.971 ;
     RECT  24.448 17.013 25.568 21.163 ;
     RECT  49.28 16.555 49.312 21.163 ;
     RECT  101.184 20.267 101.472 21.163 ;
     RECT  103.104 20.267 103.136 21.163 ;
     RECT  25.536 21.163 25.568 21.365 ;
     RECT  25.536 21.365 25.632 21.366 ;
     RECT  28.544 17.525 28.576 21.419 ;
     RECT  119.616 3.499 119.648 21.557 ;
     RECT  73.728 20.139 73.76 21.621 ;
     RECT  101.44 21.163 101.472 21.621 ;
     RECT  115.968 18.037 116.384 21.621 ;
     RECT  119.616 21.557 120.8 21.621 ;
     RECT  96.96 19.701 96.992 21.675 ;
     RECT  115.264 21.621 116.384 21.675 ;
     RECT  84.032 20.725 84.32 21.803 ;
     RECT  22.208 21.557 22.24 22.261 ;
     RECT  89.28 21.621 89.312 22.261 ;
     RECT  3.648 19.893 4.064 22.315 ;
     RECT  21.952 22.261 22.24 22.315 ;
     RECT  79.232 19.947 80.544 22.315 ;
     RECT  80.448 22.315 80.544 22.443 ;
     RECT  21.952 22.315 21.984 22.453 ;
     RECT  73.728 21.621 74.08 22.453 ;
     RECT  73.6 22.453 74.08 22.507 ;
     RECT  39.04 14.123 39.072 22.645 ;
     RECT  37.056 20.597 37.088 22.699 ;
     RECT  7.168 21.045 7.2 22.709 ;
     RECT  3.84 22.315 4.064 22.763 ;
     RECT  90.816 21.557 90.848 22.763 ;
     RECT  42.688 19.509 42.72 22.773 ;
     RECT  38.656 22.645 39.072 22.827 ;
     RECT  42.688 22.773 43.104 22.891 ;
     RECT  60.16 20.587 60.192 22.891 ;
     RECT  69.376 20.085 69.408 22.891 ;
     RECT  119.168 21.621 120.992 23.083 ;
     RECT  11.968 20.907 12 23.221 ;
     RECT  11.648 23.221 12 23.275 ;
     RECT  6.656 22.709 7.2 23.339 ;
     RECT  9.536 21.941 9.568 23.403 ;
     RECT  34.176 20.779 34.208 23.403 ;
     RECT  54.656 20.085 54.688 23.403 ;
     RECT  111.424 19.893 111.456 23.403 ;
     RECT  98.56 20.971 98.592 23.659 ;
     RECT  115.264 21.675 115.296 23.733 ;
     RECT  106.752 22.709 106.784 23.787 ;
     RECT  115.136 23.733 115.296 23.787 ;
     RECT  84.288 21.803 84.32 23.797 ;
     RECT  83.776 23.797 84.32 23.851 ;
     RECT  101.44 21.621 102.688 23.851 ;
     RECT  49.984 21.621 50.016 23.979 ;
     RECT  65.6 19.563 65.632 23.979 ;
     RECT  73.6 22.507 73.76 24.885 ;
     RECT  73.6 24.885 73.824 24.939 ;
     RECT  89.216 22.261 89.312 24.939 ;
     RECT  115.136 23.787 115.168 24.939 ;
     RECT  25.6 21.366 25.632 25.013 ;
     RECT  3.84 22.763 3.872 25.067 ;
     RECT  43.072 22.891 43.104 25.067 ;
     RECT  44.48 22.581 44.512 25.259 ;
     RECT  119.168 23.083 119.648 25.269 ;
     RECT  21.056 22.453 21.984 25.451 ;
     RECT  83.776 23.851 83.808 25.515 ;
     RECT  18.432 22.325 18.464 25.579 ;
     RECT  40.64 24.949 40.672 25.579 ;
     RECT  57.216 11.061 57.248 25.717 ;
     RECT  21.952 25.451 21.984 25.963 ;
     RECT  60.352 25.333 60.384 26.027 ;
     RECT  101.44 23.851 101.472 26.165 ;
     RECT  97.728 25.013 97.76 26.485 ;
     RECT  81.984 17.003 82.016 26.741 ;
     RECT  92.352 24.885 92.384 26.741 ;
     RECT  5.44 24.885 5.472 26.795 ;
     RECT  42.112 25.205 42.912 26.859 ;
     RECT  63.104 25.973 63.136 26.859 ;
     RECT  51.84 26.165 51.872 27.061 ;
     RECT  54.272 26.421 54.304 27.061 ;
     RECT  54.272 27.061 54.432 27.115 ;
     RECT  108.416 25.589 108.448 27.115 ;
     RECT  25.024 25.013 25.632 27.317 ;
     RECT  51.84 27.061 52.832 27.317 ;
     RECT  118.208 25.269 119.648 27.317 ;
     RECT  80.448 22.443 80.48 27.435 ;
     RECT  94.016 25.013 94.048 27.435 ;
     RECT  30.528 25.973 30.56 27.563 ;
     RECT  91.264 26.741 92.384 27.563 ;
     RECT  42.88 26.859 42.912 27.691 ;
     RECT  35.456 25.525 35.488 27.819 ;
     RECT  85.824 25.013 85.856 27.819 ;
     RECT  96.768 26.485 97.76 27.883 ;
     RECT  51.84 27.317 52.96 28.011 ;
     RECT  57.216 25.717 57.696 28.011 ;
     RECT  63.168 27.317 63.2 28.011 ;
     RECT  118.016 27.317 119.648 28.139 ;
     RECT  81.984 26.741 82.144 28.213 ;
     RECT  89.28 24.939 89.312 28.267 ;
     RECT  125.568 25.013 125.6 28.277 ;
     RECT  11.648 23.275 11.68 28.331 ;
     RECT  125.568 28.277 125.792 28.331 ;
     RECT  57.664 28.011 57.696 28.405 ;
     RECT  100.16 26.165 101.472 28.405 ;
     RECT  57.664 28.405 57.888 28.459 ;
     RECT  96.768 27.883 96.8 28.459 ;
     RECT  99.712 28.405 101.472 28.459 ;
     RECT  91.264 27.563 91.424 28.523 ;
     RECT  57.856 28.459 57.888 28.661 ;
     RECT  25.024 27.317 26.08 28.715 ;
     RECT  113.472 27.957 113.504 28.725 ;
     RECT  68.416 25.653 68.448 28.789 ;
     RECT  68.416 28.789 68.64 28.843 ;
     RECT  8.704 26.741 8.736 28.907 ;
     RECT  73.728 24.939 73.824 29.035 ;
     RECT  54.4 27.115 54.432 29.099 ;
     RECT  62.656 28.213 62.688 29.227 ;
     RECT  57.856 28.661 58.784 29.291 ;
     RECT  101.184 28.459 101.472 29.291 ;
     RECT  113.472 28.725 114.016 29.291 ;
     RECT  87.424 27.765 87.456 29.355 ;
     RECT  7.168 23.339 7.2 29.419 ;
     RECT  25.024 28.715 25.632 29.419 ;
     RECT  113.472 29.291 113.76 29.419 ;
     RECT  18.048 27.317 18.08 30.379 ;
     RECT  43.904 28.469 43.936 30.443 ;
     RECT  29.248 29.365 29.28 30.581 ;
     RECT  73.728 29.035 73.76 30.581 ;
     RECT  68.608 28.843 68.64 30.635 ;
     RECT  37.568 27.061 37.6 30.827 ;
     RECT  46.08 28.853 46.112 30.827 ;
     RECT  95.168 30.325 96.352 30.891 ;
     RECT  73.728 30.581 74.272 31.019 ;
     RECT  96.32 30.891 96.352 31.083 ;
     RECT  113.664 29.419 113.76 31.221 ;
     RECT  113.664 31.221 114.016 31.275 ;
     RECT  99.712 28.459 99.744 31.285 ;
     RECT  91.392 28.523 91.424 31.339 ;
     RECT  99.52 31.285 99.744 31.339 ;
     RECT  87.36 30.325 87.392 31.403 ;
     RECT  113.728 31.275 114.016 31.403 ;
     RECT  29.12 30.581 29.28 31.53 ;
     RECT  33.6 30.709 33.632 31.723 ;
     RECT  48.192 25.525 48.224 31.723 ;
     RECT  57.856 29.291 57.888 31.797 ;
     RECT  57.728 31.797 57.888 31.851 ;
     RECT  59.52 29.365 59.552 31.861 ;
     RECT  125.76 28.331 125.792 31.861 ;
     RECT  125.632 31.861 125.792 31.915 ;
     RECT  25.024 29.419 25.056 31.979 ;
     RECT  106.24 27.061 106.272 31.979 ;
     RECT  99.52 31.339 99.552 32.235 ;
     RECT  74.176 31.019 74.272 32.363 ;
     RECT  64.512 30.837 64.544 32.427 ;
     RECT  74.176 32.363 74.208 32.427 ;
     RECT  81.92 28.213 82.144 32.437 ;
     RECT  116.8 29.365 116.832 32.437 ;
     RECT  4.352 27.317 4.384 32.555 ;
     RECT  16.512 30.325 16.544 32.555 ;
     RECT  29.056 31.53 29.28 32.555 ;
     RECT  57.728 31.851 57.76 32.555 ;
     RECT  7.936 30.325 7.968 32.629 ;
     RECT  7.68 32.629 7.968 32.683 ;
     RECT  118.72 28.139 119.648 33.013 ;
     RECT  120.96 23.083 120.992 33.013 ;
     RECT  115.52 32.437 116.832 33.067 ;
     RECT  72.256 30.581 72.288 33.131 ;
     RECT  78.464 30.325 78.496 33.131 ;
     RECT  81.92 32.437 82.592 33.131 ;
     RECT  17.984 30.709 18.016 33.515 ;
     RECT  55.68 31.797 55.712 33.579 ;
     RECT  113.984 31.403 114.016 33.643 ;
     RECT  118.72 33.013 120.992 33.707 ;
     RECT  125.632 31.915 125.664 33.707 ;
     RECT  119.616 33.707 120.992 33.771 ;
     RECT  59.52 31.861 59.68 34.091 ;
     RECT  29.248 32.555 29.28 34.155 ;
     RECT  109.952 31.541 109.984 34.283 ;
     RECT  59.52 34.091 59.552 34.347 ;
     RECT  39.04 22.827 39.072 34.475 ;
     RECT  101.184 29.291 101.216 34.667 ;
     RECT  51.008 31.669 51.04 34.859 ;
     RECT  81.92 33.131 82.016 34.859 ;
     RECT  15.936 32.629 15.968 35.755 ;
     RECT  7.68 32.683 7.712 35.947 ;
     RECT  120.96 33.771 120.992 49.643 ;
     RECT  64.704 34.613 64.736 57.515 ;
     RECT  64.832 88.693 64.864 91.883 ;
     RECT  119.616 33.771 119.648 93.803 ;
     RECT  116.8 33.067 116.832 109.739 ;
     RECT  81.92 34.859 81.952 113.973 ;
     RECT  81.92 113.973 82.08 114.219 ;
     RECT  52.928 28.011 52.96 115.755 ;
     RECT  82.048 114.219 82.08 115.819 ;
     RECT  49.536 115.765 49.568 118.059 ;
     RECT  70.208 115.765 70.24 123.179 ;
     RECT  66.432 57.333 66.464 123.243 ;
     RECT  124.032 109.877 124.064 133.419 ;
     RECT  125.76 93.941 125.792 133.813 ;
     RECT  125.76 133.813 126.496 149.995 ;
     RECT  121.472 50.101 121.504 178.613 ;
     RECT  125.76 149.995 125.792 178.667 ;
     RECT  49.856 118.517 49.888 180.203 ;
     RECT  121.472 178.613 122.528 180.267 ;
     RECT  39.552 179.509 39.584 180.405 ;
     RECT  39.552 180.405 39.904 180.459 ;
     RECT  39.872 180.459 39.904 180.651 ;
     RECT  56.896 179.317 56.928 180.651 ;
     RECT  85.504 116.725 85.536 180.651 ;
     RECT  108.864 179.509 108.896 180.651 ;
     RECT  122.496 180.267 122.528 180.651 ;
  END
END ot_qkvd_kv_wq_leaf
END LIBRARY
